VERSION 5.8 ;
BUSBITCHARS "[]" ;
DIVIDERCHAR "/" ;
UNITS
    DATABASE MICRONS 1000 ;
END UNITS

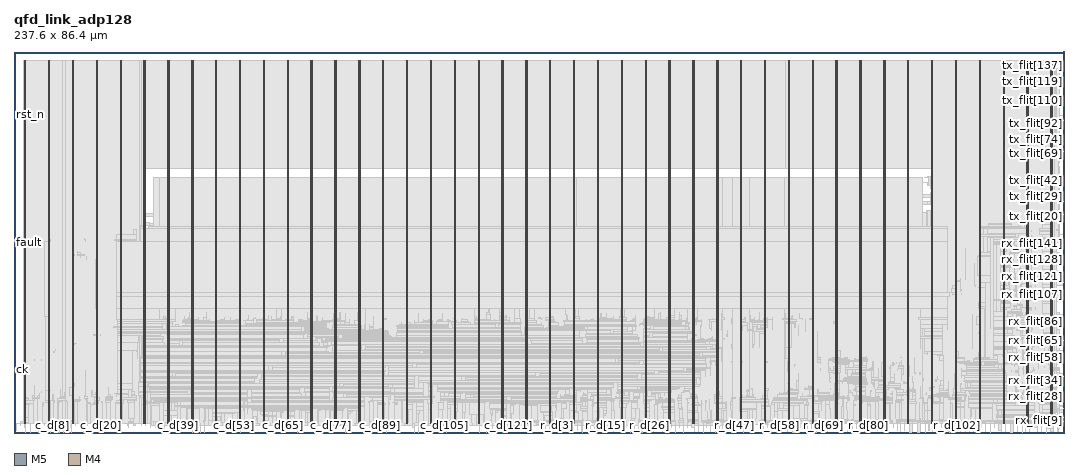
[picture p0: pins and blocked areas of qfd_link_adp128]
MACRO qfd_link_adp128
  FOREIGN qfd_link_adp128 0 0 ;
  CLASS BLOCK ;
  SIZE 237.6 BY 86.4 ;
  PIN c_cr
    DIRECTION OUTPUT ;
    USE SIGNAL ;
    PORT
      LAYER M5 ;
        RECT  0.432 0 0.456 0.084 ;
    END
  END c_cr
  PIN c_d[0]
    DIRECTION INPUT ;
    USE SIGNAL ;
    PORT
      LAYER M5 ;
        RECT  1.344 0 1.368 0.084 ;
    END
  END c_d[0]
  PIN c_d[100]
    DIRECTION INPUT ;
    USE SIGNAL ;
    PORT
      LAYER M5 ;
        RECT  92.736 0 92.76 0.084 ;
    END
  END c_d[100]
  PIN c_d[101]
    DIRECTION INPUT ;
    USE SIGNAL ;
    PORT
      LAYER M5 ;
        RECT  93.648 0 93.672 0.084 ;
    END
  END c_d[101]
  PIN c_d[102]
    DIRECTION INPUT ;
    USE SIGNAL ;
    PORT
      LAYER M5 ;
        RECT  94.56 0 94.584 0.084 ;
    END
  END c_d[102]
  PIN c_d[103]
    DIRECTION INPUT ;
    USE SIGNAL ;
    PORT
      LAYER M5 ;
        RECT  95.472 0 95.496 0.084 ;
    END
  END c_d[103]
  PIN c_d[104]
    DIRECTION INPUT ;
    USE SIGNAL ;
    PORT
      LAYER M5 ;
        RECT  96.384 0 96.408 0.084 ;
    END
  END c_d[104]
  PIN c_d[105]
    DIRECTION INPUT ;
    USE SIGNAL ;
    PORT
      LAYER M5 ;
        RECT  97.296 0 97.32 0.084 ;
    END
  END c_d[105]
  PIN c_d[106]
    DIRECTION INPUT ;
    USE SIGNAL ;
    PORT
      LAYER M5 ;
        RECT  98.208 0 98.232 0.084 ;
    END
  END c_d[106]
  PIN c_d[107]
    DIRECTION INPUT ;
    USE SIGNAL ;
    PORT
      LAYER M5 ;
        RECT  99.12 0 99.144 0.084 ;
    END
  END c_d[107]
  PIN c_d[108]
    DIRECTION INPUT ;
    USE SIGNAL ;
    PORT
      LAYER M5 ;
        RECT  100.032 0 100.056 0.084 ;
    END
  END c_d[108]
  PIN c_d[109]
    DIRECTION INPUT ;
    USE SIGNAL ;
    PORT
      LAYER M5 ;
        RECT  100.992 0 101.016 0.084 ;
    END
  END c_d[109]
  PIN c_d[10]
    DIRECTION INPUT ;
    USE SIGNAL ;
    PORT
      LAYER M5 ;
        RECT  10.512 0 10.536 0.084 ;
    END
  END c_d[10]
  PIN c_d[110]
    DIRECTION INPUT ;
    USE SIGNAL ;
    PORT
      LAYER M5 ;
        RECT  101.904 0 101.928 0.084 ;
    END
  END c_d[110]
  PIN c_d[111]
    DIRECTION INPUT ;
    USE SIGNAL ;
    PORT
      LAYER M5 ;
        RECT  102.816 0 102.84 0.084 ;
    END
  END c_d[111]
  PIN c_d[112]
    DIRECTION INPUT ;
    USE SIGNAL ;
    PORT
      LAYER M5 ;
        RECT  103.728 0 103.752 0.084 ;
    END
  END c_d[112]
  PIN c_d[113]
    DIRECTION INPUT ;
    USE SIGNAL ;
    PORT
      LAYER M5 ;
        RECT  104.64 0 104.664 0.084 ;
    END
  END c_d[113]
  PIN c_d[114]
    DIRECTION INPUT ;
    USE SIGNAL ;
    PORT
      LAYER M5 ;
        RECT  105.552 0 105.576 0.084 ;
    END
  END c_d[114]
  PIN c_d[115]
    DIRECTION INPUT ;
    USE SIGNAL ;
    PORT
      LAYER M5 ;
        RECT  106.464 0 106.488 0.084 ;
    END
  END c_d[115]
  PIN c_d[116]
    DIRECTION INPUT ;
    USE SIGNAL ;
    PORT
      LAYER M5 ;
        RECT  107.376 0 107.4 0.084 ;
    END
  END c_d[116]
  PIN c_d[117]
    DIRECTION INPUT ;
    USE SIGNAL ;
    PORT
      LAYER M5 ;
        RECT  108.288 0 108.312 0.084 ;
    END
  END c_d[117]
  PIN c_d[118]
    DIRECTION INPUT ;
    USE SIGNAL ;
    PORT
      LAYER M5 ;
        RECT  109.2 0 109.224 0.084 ;
    END
  END c_d[118]
  PIN c_d[119]
    DIRECTION INPUT ;
    USE SIGNAL ;
    PORT
      LAYER M5 ;
        RECT  110.112 0 110.136 0.084 ;
    END
  END c_d[119]
  PIN c_d[11]
    DIRECTION INPUT ;
    USE SIGNAL ;
    PORT
      LAYER M5 ;
        RECT  11.424 0 11.448 0.084 ;
    END
  END c_d[11]
  PIN c_d[120]
    DIRECTION INPUT ;
    USE SIGNAL ;
    PORT
      LAYER M5 ;
        RECT  111.024 0 111.048 0.084 ;
    END
  END c_d[120]
  PIN c_d[121]
    DIRECTION INPUT ;
    USE SIGNAL ;
    PORT
      LAYER M5 ;
        RECT  111.936 0 111.96 0.084 ;
    END
  END c_d[121]
  PIN c_d[122]
    DIRECTION INPUT ;
    USE SIGNAL ;
    PORT
      LAYER M5 ;
        RECT  112.848 0 112.872 0.084 ;
    END
  END c_d[122]
  PIN c_d[123]
    DIRECTION INPUT ;
    USE SIGNAL ;
    PORT
      LAYER M5 ;
        RECT  113.76 0 113.784 0.084 ;
    END
  END c_d[123]
  PIN c_d[124]
    DIRECTION INPUT ;
    USE SIGNAL ;
    PORT
      LAYER M5 ;
        RECT  114.672 0 114.696 0.084 ;
    END
  END c_d[124]
  PIN c_d[125]
    DIRECTION INPUT ;
    USE SIGNAL ;
    PORT
      LAYER M5 ;
        RECT  115.584 0 115.608 0.084 ;
    END
  END c_d[125]
  PIN c_d[126]
    DIRECTION INPUT ;
    USE SIGNAL ;
    PORT
      LAYER M5 ;
        RECT  116.496 0 116.52 0.084 ;
    END
  END c_d[126]
  PIN c_d[127]
    DIRECTION INPUT ;
    USE SIGNAL ;
    PORT
      LAYER M5 ;
        RECT  117.408 0 117.432 0.084 ;
    END
  END c_d[127]
  PIN c_d[12]
    DIRECTION INPUT ;
    USE SIGNAL ;
    PORT
      LAYER M5 ;
        RECT  12.336 0 12.36 0.084 ;
    END
  END c_d[12]
  PIN c_d[13]
    DIRECTION INPUT ;
    USE SIGNAL ;
    PORT
      LAYER M5 ;
        RECT  13.248 0 13.272 0.084 ;
    END
  END c_d[13]
  PIN c_d[14]
    DIRECTION INPUT ;
    USE SIGNAL ;
    PORT
      LAYER M5 ;
        RECT  14.16 0 14.184 0.084 ;
    END
  END c_d[14]
  PIN c_d[15]
    DIRECTION INPUT ;
    USE SIGNAL ;
    PORT
      LAYER M5 ;
        RECT  15.072 0 15.096 0.084 ;
    END
  END c_d[15]
  PIN c_d[16]
    DIRECTION INPUT ;
    USE SIGNAL ;
    PORT
      LAYER M5 ;
        RECT  15.984 0 16.008 0.084 ;
    END
  END c_d[16]
  PIN c_d[17]
    DIRECTION INPUT ;
    USE SIGNAL ;
    PORT
      LAYER M5 ;
        RECT  16.896 0 16.92 0.084 ;
    END
  END c_d[17]
  PIN c_d[18]
    DIRECTION INPUT ;
    USE SIGNAL ;
    PORT
      LAYER M5 ;
        RECT  17.808 0 17.832 0.084 ;
    END
  END c_d[18]
  PIN c_d[19]
    DIRECTION INPUT ;
    USE SIGNAL ;
    PORT
      LAYER M5 ;
        RECT  18.72 0 18.744 0.084 ;
    END
  END c_d[19]
  PIN c_d[1]
    DIRECTION INPUT ;
    USE SIGNAL ;
    PORT
      LAYER M5 ;
        RECT  2.256 0 2.28 0.084 ;
    END
  END c_d[1]
  PIN c_d[20]
    DIRECTION INPUT ;
    USE SIGNAL ;
    PORT
      LAYER M5 ;
        RECT  19.632 0 19.656 0.084 ;
    END
  END c_d[20]
  PIN c_d[21]
    DIRECTION INPUT ;
    USE SIGNAL ;
    PORT
      LAYER M5 ;
        RECT  20.544 0 20.568 0.084 ;
    END
  END c_d[21]
  PIN c_d[22]
    DIRECTION INPUT ;
    USE SIGNAL ;
    PORT
      LAYER M5 ;
        RECT  21.456 0 21.48 0.084 ;
    END
  END c_d[22]
  PIN c_d[23]
    DIRECTION INPUT ;
    USE SIGNAL ;
    PORT
      LAYER M5 ;
        RECT  22.368 0 22.392 0.084 ;
    END
  END c_d[23]
  PIN c_d[24]
    DIRECTION INPUT ;
    USE SIGNAL ;
    PORT
      LAYER M5 ;
        RECT  23.28 0 23.304 0.084 ;
    END
  END c_d[24]
  PIN c_d[25]
    DIRECTION INPUT ;
    USE SIGNAL ;
    PORT
      LAYER M5 ;
        RECT  24.192 0 24.216 0.084 ;
    END
  END c_d[25]
  PIN c_d[26]
    DIRECTION INPUT ;
    USE SIGNAL ;
    PORT
      LAYER M5 ;
        RECT  25.104 0 25.128 0.084 ;
    END
  END c_d[26]
  PIN c_d[27]
    DIRECTION INPUT ;
    USE SIGNAL ;
    PORT
      LAYER M5 ;
        RECT  26.016 0 26.04 0.084 ;
    END
  END c_d[27]
  PIN c_d[28]
    DIRECTION INPUT ;
    USE SIGNAL ;
    PORT
      LAYER M5 ;
        RECT  26.928 0 26.952 0.084 ;
    END
  END c_d[28]
  PIN c_d[29]
    DIRECTION INPUT ;
    USE SIGNAL ;
    PORT
      LAYER M5 ;
        RECT  27.84 0 27.864 0.084 ;
    END
  END c_d[29]
  PIN c_d[2]
    DIRECTION INPUT ;
    USE SIGNAL ;
    PORT
      LAYER M5 ;
        RECT  3.168 0 3.192 0.084 ;
    END
  END c_d[2]
  PIN c_d[30]
    DIRECTION INPUT ;
    USE SIGNAL ;
    PORT
      LAYER M5 ;
        RECT  28.752 0 28.776 0.084 ;
    END
  END c_d[30]
  PIN c_d[31]
    DIRECTION INPUT ;
    USE SIGNAL ;
    PORT
      LAYER M5 ;
        RECT  29.712 0 29.736 0.084 ;
    END
  END c_d[31]
  PIN c_d[32]
    DIRECTION INPUT ;
    USE SIGNAL ;
    PORT
      LAYER M5 ;
        RECT  30.624 0 30.648 0.084 ;
    END
  END c_d[32]
  PIN c_d[33]
    DIRECTION INPUT ;
    USE SIGNAL ;
    PORT
      LAYER M5 ;
        RECT  31.536 0 31.56 0.084 ;
    END
  END c_d[33]
  PIN c_d[34]
    DIRECTION INPUT ;
    USE SIGNAL ;
    PORT
      LAYER M5 ;
        RECT  32.448 0 32.472 0.084 ;
    END
  END c_d[34]
  PIN c_d[35]
    DIRECTION INPUT ;
    USE SIGNAL ;
    PORT
      LAYER M5 ;
        RECT  33.36 0 33.384 0.084 ;
    END
  END c_d[35]
  PIN c_d[36]
    DIRECTION INPUT ;
    USE SIGNAL ;
    PORT
      LAYER M5 ;
        RECT  34.272 0 34.296 0.084 ;
    END
  END c_d[36]
  PIN c_d[37]
    DIRECTION INPUT ;
    USE SIGNAL ;
    PORT
      LAYER M5 ;
        RECT  35.184 0 35.208 0.084 ;
    END
  END c_d[37]
  PIN c_d[38]
    DIRECTION INPUT ;
    USE SIGNAL ;
    PORT
      LAYER M5 ;
        RECT  36.096 0 36.12 0.084 ;
    END
  END c_d[38]
  PIN c_d[39]
    DIRECTION INPUT ;
    USE SIGNAL ;
    PORT
      LAYER M5 ;
        RECT  37.008 0 37.032 0.084 ;
    END
  END c_d[39]
  PIN c_d[3]
    DIRECTION INPUT ;
    USE SIGNAL ;
    PORT
      LAYER M5 ;
        RECT  4.08 0 4.104 0.084 ;
    END
  END c_d[3]
  PIN c_d[40]
    DIRECTION INPUT ;
    USE SIGNAL ;
    PORT
      LAYER M5 ;
        RECT  37.92 0 37.944 0.084 ;
    END
  END c_d[40]
  PIN c_d[41]
    DIRECTION INPUT ;
    USE SIGNAL ;
    PORT
      LAYER M5 ;
        RECT  38.832 0 38.856 0.084 ;
    END
  END c_d[41]
  PIN c_d[42]
    DIRECTION INPUT ;
    USE SIGNAL ;
    PORT
      LAYER M5 ;
        RECT  39.744 0 39.768 0.084 ;
    END
  END c_d[42]
  PIN c_d[43]
    DIRECTION INPUT ;
    USE SIGNAL ;
    PORT
      LAYER M5 ;
        RECT  40.656 0 40.68 0.084 ;
    END
  END c_d[43]
  PIN c_d[44]
    DIRECTION INPUT ;
    USE SIGNAL ;
    PORT
      LAYER M5 ;
        RECT  41.568 0 41.592 0.084 ;
    END
  END c_d[44]
  PIN c_d[45]
    DIRECTION INPUT ;
    USE SIGNAL ;
    PORT
      LAYER M5 ;
        RECT  42.48 0 42.504 0.084 ;
    END
  END c_d[45]
  PIN c_d[46]
    DIRECTION INPUT ;
    USE SIGNAL ;
    PORT
      LAYER M5 ;
        RECT  43.392 0 43.416 0.084 ;
    END
  END c_d[46]
  PIN c_d[47]
    DIRECTION INPUT ;
    USE SIGNAL ;
    PORT
      LAYER M5 ;
        RECT  44.304 0 44.328 0.084 ;
    END
  END c_d[47]
  PIN c_d[48]
    DIRECTION INPUT ;
    USE SIGNAL ;
    PORT
      LAYER M5 ;
        RECT  45.216 0 45.24 0.084 ;
    END
  END c_d[48]
  PIN c_d[49]
    DIRECTION INPUT ;
    USE SIGNAL ;
    PORT
      LAYER M5 ;
        RECT  46.128 0 46.152 0.084 ;
    END
  END c_d[49]
  PIN c_d[4]
    DIRECTION INPUT ;
    USE SIGNAL ;
    PORT
      LAYER M5 ;
        RECT  4.992 0 5.016 0.084 ;
    END
  END c_d[4]
  PIN c_d[50]
    DIRECTION INPUT ;
    USE SIGNAL ;
    PORT
      LAYER M5 ;
        RECT  47.04 0 47.064 0.084 ;
    END
  END c_d[50]
  PIN c_d[51]
    DIRECTION INPUT ;
    USE SIGNAL ;
    PORT
      LAYER M5 ;
        RECT  47.952 0 47.976 0.084 ;
    END
  END c_d[51]
  PIN c_d[52]
    DIRECTION INPUT ;
    USE SIGNAL ;
    PORT
      LAYER M5 ;
        RECT  48.864 0 48.888 0.084 ;
    END
  END c_d[52]
  PIN c_d[53]
    DIRECTION INPUT ;
    USE SIGNAL ;
    PORT
      LAYER M5 ;
        RECT  49.776 0 49.8 0.084 ;
    END
  END c_d[53]
  PIN c_d[54]
    DIRECTION INPUT ;
    USE SIGNAL ;
    PORT
      LAYER M5 ;
        RECT  50.688 0 50.712 0.084 ;
    END
  END c_d[54]
  PIN c_d[55]
    DIRECTION INPUT ;
    USE SIGNAL ;
    PORT
      LAYER M5 ;
        RECT  51.6 0 51.624 0.084 ;
    END
  END c_d[55]
  PIN c_d[56]
    DIRECTION INPUT ;
    USE SIGNAL ;
    PORT
      LAYER M5 ;
        RECT  52.512 0 52.536 0.084 ;
    END
  END c_d[56]
  PIN c_d[57]
    DIRECTION INPUT ;
    USE SIGNAL ;
    PORT
      LAYER M5 ;
        RECT  53.472 0 53.496 0.084 ;
    END
  END c_d[57]
  PIN c_d[58]
    DIRECTION INPUT ;
    USE SIGNAL ;
    PORT
      LAYER M5 ;
        RECT  54.384 0 54.408 0.084 ;
    END
  END c_d[58]
  PIN c_d[59]
    DIRECTION INPUT ;
    USE SIGNAL ;
    PORT
      LAYER M5 ;
        RECT  55.296 0 55.32 0.084 ;
    END
  END c_d[59]
  PIN c_d[5]
    DIRECTION INPUT ;
    USE SIGNAL ;
    PORT
      LAYER M5 ;
        RECT  5.952 0 5.976 0.084 ;
    END
  END c_d[5]
  PIN c_d[60]
    DIRECTION INPUT ;
    USE SIGNAL ;
    PORT
      LAYER M5 ;
        RECT  56.208 0 56.232 0.084 ;
    END
  END c_d[60]
  PIN c_d[61]
    DIRECTION INPUT ;
    USE SIGNAL ;
    PORT
      LAYER M5 ;
        RECT  57.12 0 57.144 0.084 ;
    END
  END c_d[61]
  PIN c_d[62]
    DIRECTION INPUT ;
    USE SIGNAL ;
    PORT
      LAYER M5 ;
        RECT  58.032 0 58.056 0.084 ;
    END
  END c_d[62]
  PIN c_d[63]
    DIRECTION INPUT ;
    USE SIGNAL ;
    PORT
      LAYER M5 ;
        RECT  58.944 0 58.968 0.084 ;
    END
  END c_d[63]
  PIN c_d[64]
    DIRECTION INPUT ;
    USE SIGNAL ;
    PORT
      LAYER M5 ;
        RECT  59.856 0 59.88 0.084 ;
    END
  END c_d[64]
  PIN c_d[65]
    DIRECTION INPUT ;
    USE SIGNAL ;
    PORT
      LAYER M5 ;
        RECT  60.768 0 60.792 0.084 ;
    END
  END c_d[65]
  PIN c_d[66]
    DIRECTION INPUT ;
    USE SIGNAL ;
    PORT
      LAYER M5 ;
        RECT  61.68 0 61.704 0.084 ;
    END
  END c_d[66]
  PIN c_d[67]
    DIRECTION INPUT ;
    USE SIGNAL ;
    PORT
      LAYER M5 ;
        RECT  62.592 0 62.616 0.084 ;
    END
  END c_d[67]
  PIN c_d[68]
    DIRECTION INPUT ;
    USE SIGNAL ;
    PORT
      LAYER M5 ;
        RECT  63.504 0 63.528 0.084 ;
    END
  END c_d[68]
  PIN c_d[69]
    DIRECTION INPUT ;
    USE SIGNAL ;
    PORT
      LAYER M5 ;
        RECT  64.416 0 64.44 0.084 ;
    END
  END c_d[69]
  PIN c_d[6]
    DIRECTION INPUT ;
    USE SIGNAL ;
    PORT
      LAYER M5 ;
        RECT  6.864 0 6.888 0.084 ;
    END
  END c_d[6]
  PIN c_d[70]
    DIRECTION INPUT ;
    USE SIGNAL ;
    PORT
      LAYER M5 ;
        RECT  65.328 0 65.352 0.084 ;
    END
  END c_d[70]
  PIN c_d[71]
    DIRECTION INPUT ;
    USE SIGNAL ;
    PORT
      LAYER M5 ;
        RECT  66.24 0 66.264 0.084 ;
    END
  END c_d[71]
  PIN c_d[72]
    DIRECTION INPUT ;
    USE SIGNAL ;
    PORT
      LAYER M5 ;
        RECT  67.152 0 67.176 0.084 ;
    END
  END c_d[72]
  PIN c_d[73]
    DIRECTION INPUT ;
    USE SIGNAL ;
    PORT
      LAYER M5 ;
        RECT  68.064 0 68.088 0.084 ;
    END
  END c_d[73]
  PIN c_d[74]
    DIRECTION INPUT ;
    USE SIGNAL ;
    PORT
      LAYER M5 ;
        RECT  68.976 0 69 0.084 ;
    END
  END c_d[74]
  PIN c_d[75]
    DIRECTION INPUT ;
    USE SIGNAL ;
    PORT
      LAYER M5 ;
        RECT  69.888 0 69.912 0.084 ;
    END
  END c_d[75]
  PIN c_d[76]
    DIRECTION INPUT ;
    USE SIGNAL ;
    PORT
      LAYER M5 ;
        RECT  70.8 0 70.824 0.084 ;
    END
  END c_d[76]
  PIN c_d[77]
    DIRECTION INPUT ;
    USE SIGNAL ;
    PORT
      LAYER M5 ;
        RECT  71.712 0 71.736 0.084 ;
    END
  END c_d[77]
  PIN c_d[78]
    DIRECTION INPUT ;
    USE SIGNAL ;
    PORT
      LAYER M5 ;
        RECT  72.624 0 72.648 0.084 ;
    END
  END c_d[78]
  PIN c_d[79]
    DIRECTION INPUT ;
    USE SIGNAL ;
    PORT
      LAYER M5 ;
        RECT  73.536 0 73.56 0.084 ;
    END
  END c_d[79]
  PIN c_d[7]
    DIRECTION INPUT ;
    USE SIGNAL ;
    PORT
      LAYER M5 ;
        RECT  7.776 0 7.8 0.084 ;
    END
  END c_d[7]
  PIN c_d[80]
    DIRECTION INPUT ;
    USE SIGNAL ;
    PORT
      LAYER M5 ;
        RECT  74.448 0 74.472 0.084 ;
    END
  END c_d[80]
  PIN c_d[81]
    DIRECTION INPUT ;
    USE SIGNAL ;
    PORT
      LAYER M5 ;
        RECT  75.36 0 75.384 0.084 ;
    END
  END c_d[81]
  PIN c_d[82]
    DIRECTION INPUT ;
    USE SIGNAL ;
    PORT
      LAYER M5 ;
        RECT  76.272 0 76.296 0.084 ;
    END
  END c_d[82]
  PIN c_d[83]
    DIRECTION INPUT ;
    USE SIGNAL ;
    PORT
      LAYER M5 ;
        RECT  77.232 0 77.256 0.084 ;
    END
  END c_d[83]
  PIN c_d[84]
    DIRECTION INPUT ;
    USE SIGNAL ;
    PORT
      LAYER M5 ;
        RECT  78.144 0 78.168 0.084 ;
    END
  END c_d[84]
  PIN c_d[85]
    DIRECTION INPUT ;
    USE SIGNAL ;
    PORT
      LAYER M5 ;
        RECT  79.056 0 79.08 0.084 ;
    END
  END c_d[85]
  PIN c_d[86]
    DIRECTION INPUT ;
    USE SIGNAL ;
    PORT
      LAYER M5 ;
        RECT  79.968 0 79.992 0.084 ;
    END
  END c_d[86]
  PIN c_d[87]
    DIRECTION INPUT ;
    USE SIGNAL ;
    PORT
      LAYER M5 ;
        RECT  80.88 0 80.904 0.084 ;
    END
  END c_d[87]
  PIN c_d[88]
    DIRECTION INPUT ;
    USE SIGNAL ;
    PORT
      LAYER M5 ;
        RECT  81.792 0 81.816 0.084 ;
    END
  END c_d[88]
  PIN c_d[89]
    DIRECTION INPUT ;
    USE SIGNAL ;
    PORT
      LAYER M5 ;
        RECT  82.704 0 82.728 0.084 ;
    END
  END c_d[89]
  PIN c_d[8]
    DIRECTION INPUT ;
    USE SIGNAL ;
    PORT
      LAYER M5 ;
        RECT  8.688 0 8.712 0.084 ;
    END
  END c_d[8]
  PIN c_d[90]
    DIRECTION INPUT ;
    USE SIGNAL ;
    PORT
      LAYER M5 ;
        RECT  83.616 0 83.64 0.084 ;
    END
  END c_d[90]
  PIN c_d[91]
    DIRECTION INPUT ;
    USE SIGNAL ;
    PORT
      LAYER M5 ;
        RECT  84.528 0 84.552 0.084 ;
    END
  END c_d[91]
  PIN c_d[92]
    DIRECTION INPUT ;
    USE SIGNAL ;
    PORT
      LAYER M5 ;
        RECT  85.44 0 85.464 0.084 ;
    END
  END c_d[92]
  PIN c_d[93]
    DIRECTION INPUT ;
    USE SIGNAL ;
    PORT
      LAYER M5 ;
        RECT  86.352 0 86.376 0.084 ;
    END
  END c_d[93]
  PIN c_d[94]
    DIRECTION INPUT ;
    USE SIGNAL ;
    PORT
      LAYER M5 ;
        RECT  87.264 0 87.288 0.084 ;
    END
  END c_d[94]
  PIN c_d[95]
    DIRECTION INPUT ;
    USE SIGNAL ;
    PORT
      LAYER M5 ;
        RECT  88.176 0 88.2 0.084 ;
    END
  END c_d[95]
  PIN c_d[96]
    DIRECTION INPUT ;
    USE SIGNAL ;
    PORT
      LAYER M5 ;
        RECT  89.088 0 89.112 0.084 ;
    END
  END c_d[96]
  PIN c_d[97]
    DIRECTION INPUT ;
    USE SIGNAL ;
    PORT
      LAYER M5 ;
        RECT  90 0 90.024 0.084 ;
    END
  END c_d[97]
  PIN c_d[98]
    DIRECTION INPUT ;
    USE SIGNAL ;
    PORT
      LAYER M5 ;
        RECT  90.912 0 90.936 0.084 ;
    END
  END c_d[98]
  PIN c_d[99]
    DIRECTION INPUT ;
    USE SIGNAL ;
    PORT
      LAYER M5 ;
        RECT  91.824 0 91.848 0.084 ;
    END
  END c_d[99]
  PIN c_d[9]
    DIRECTION INPUT ;
    USE SIGNAL ;
    PORT
      LAYER M5 ;
        RECT  9.6 0 9.624 0.084 ;
    END
  END c_d[9]
  PIN c_v
    DIRECTION INPUT ;
    USE SIGNAL ;
    PORT
      LAYER M5 ;
        RECT  118.32 0 118.344 0.084 ;
    END
  END c_v
  PIN ck
    DIRECTION INPUT ;
    USE SIGNAL ;
    PORT
      LAYER M4 ;
        RECT  0 14.4 0.084 14.424 ;
    END
    PORT
      LAYER M4 ;
        RECT  0.06 14.4 2.408 14.424 ;
    END
  END ck
  PIN fault
    DIRECTION OUTPUT ;
    USE SIGNAL ;
    PORT
      LAYER M4 ;
        RECT  0 43.2 0.084 43.224 ;
    END
    PORT
      LAYER M4 ;
        RECT  0.06 43.2 0.137 43.224 ;
    END
  END fault
  PIN r_cr
    DIRECTION INPUT ;
    USE SIGNAL ;
    PORT
      LAYER M5 ;
        RECT  119.232 0 119.256 0.084 ;
    END
  END r_cr
  PIN r_d[0]
    DIRECTION OUTPUT ;
    USE SIGNAL ;
    PORT
      LAYER M5 ;
        RECT  120.144 0 120.168 0.084 ;
    END
  END r_d[0]
  PIN r_d[100]
    DIRECTION OUTPUT ;
    USE SIGNAL ;
    PORT
      LAYER M5 ;
        RECT  211.536 0 211.56 0.084 ;
    END
  END r_d[100]
  PIN r_d[101]
    DIRECTION OUTPUT ;
    USE SIGNAL ;
    PORT
      LAYER M5 ;
        RECT  212.448 0 212.472 0.084 ;
    END
  END r_d[101]
  PIN r_d[102]
    DIRECTION OUTPUT ;
    USE SIGNAL ;
    PORT
      LAYER M5 ;
        RECT  213.36 0 213.384 0.084 ;
    END
  END r_d[102]
  PIN r_d[103]
    DIRECTION OUTPUT ;
    USE SIGNAL ;
    PORT
      LAYER M5 ;
        RECT  214.272 0 214.296 0.084 ;
    END
  END r_d[103]
  PIN r_d[104]
    DIRECTION OUTPUT ;
    USE SIGNAL ;
    PORT
      LAYER M5 ;
        RECT  215.184 0 215.208 0.084 ;
    END
  END r_d[104]
  PIN r_d[105]
    DIRECTION OUTPUT ;
    USE SIGNAL ;
    PORT
      LAYER M5 ;
        RECT  216.096 0 216.12 0.084 ;
    END
  END r_d[105]
  PIN r_d[106]
    DIRECTION OUTPUT ;
    USE SIGNAL ;
    PORT
      LAYER M5 ;
        RECT  217.008 0 217.032 0.084 ;
    END
  END r_d[106]
  PIN r_d[107]
    DIRECTION OUTPUT ;
    USE SIGNAL ;
    PORT
      LAYER M5 ;
        RECT  217.92 0 217.944 0.084 ;
    END
  END r_d[107]
  PIN r_d[108]
    DIRECTION OUTPUT ;
    USE SIGNAL ;
    PORT
      LAYER M5 ;
        RECT  218.832 0 218.856 0.084 ;
    END
  END r_d[108]
  PIN r_d[109]
    DIRECTION OUTPUT ;
    USE SIGNAL ;
    PORT
      LAYER M5 ;
        RECT  219.792 0 219.816 0.084 ;
    END
  END r_d[109]
  PIN r_d[10]
    DIRECTION OUTPUT ;
    USE SIGNAL ;
    PORT
      LAYER M5 ;
        RECT  129.312 0 129.336 0.084 ;
    END
  END r_d[10]
  PIN r_d[110]
    DIRECTION OUTPUT ;
    USE SIGNAL ;
    PORT
      LAYER M5 ;
        RECT  220.704 0 220.728 0.084 ;
    END
  END r_d[110]
  PIN r_d[111]
    DIRECTION OUTPUT ;
    USE SIGNAL ;
    PORT
      LAYER M5 ;
        RECT  221.616 0 221.64 0.084 ;
    END
  END r_d[111]
  PIN r_d[112]
    DIRECTION OUTPUT ;
    USE SIGNAL ;
    PORT
      LAYER M5 ;
        RECT  222.528 0 222.552 0.084 ;
    END
  END r_d[112]
  PIN r_d[113]
    DIRECTION OUTPUT ;
    USE SIGNAL ;
    PORT
      LAYER M5 ;
        RECT  223.44 0 223.464 0.084 ;
    END
  END r_d[113]
  PIN r_d[114]
    DIRECTION OUTPUT ;
    USE SIGNAL ;
    PORT
      LAYER M5 ;
        RECT  224.352 0 224.376 0.084 ;
    END
  END r_d[114]
  PIN r_d[115]
    DIRECTION OUTPUT ;
    USE SIGNAL ;
    PORT
      LAYER M5 ;
        RECT  225.264 0 225.288 0.084 ;
    END
  END r_d[115]
  PIN r_d[116]
    DIRECTION OUTPUT ;
    USE SIGNAL ;
    PORT
      LAYER M5 ;
        RECT  226.176 0 226.2 0.084 ;
    END
  END r_d[116]
  PIN r_d[117]
    DIRECTION OUTPUT ;
    USE SIGNAL ;
    PORT
      LAYER M5 ;
        RECT  227.088 0 227.112 0.084 ;
    END
  END r_d[117]
  PIN r_d[118]
    DIRECTION OUTPUT ;
    USE SIGNAL ;
    PORT
      LAYER M5 ;
        RECT  228 0 228.024 0.084 ;
    END
  END r_d[118]
  PIN r_d[119]
    DIRECTION OUTPUT ;
    USE SIGNAL ;
    PORT
      LAYER M5 ;
        RECT  228.912 0 228.936 0.084 ;
    END
  END r_d[119]
  PIN r_d[11]
    DIRECTION OUTPUT ;
    USE SIGNAL ;
    PORT
      LAYER M5 ;
        RECT  130.224 0 130.248 0.084 ;
    END
  END r_d[11]
  PIN r_d[120]
    DIRECTION OUTPUT ;
    USE SIGNAL ;
    PORT
      LAYER M5 ;
        RECT  229.824 0 229.848 0.084 ;
    END
  END r_d[120]
  PIN r_d[121]
    DIRECTION OUTPUT ;
    USE SIGNAL ;
    PORT
      LAYER M5 ;
        RECT  230.736 0 230.76 0.084 ;
    END
  END r_d[121]
  PIN r_d[122]
    DIRECTION OUTPUT ;
    USE SIGNAL ;
    PORT
      LAYER M5 ;
        RECT  231.648 0 231.672 0.084 ;
    END
  END r_d[122]
  PIN r_d[123]
    DIRECTION OUTPUT ;
    USE SIGNAL ;
    PORT
      LAYER M5 ;
        RECT  232.56 0 232.584 0.084 ;
    END
  END r_d[123]
  PIN r_d[124]
    DIRECTION OUTPUT ;
    USE SIGNAL ;
    PORT
      LAYER M5 ;
        RECT  233.472 0 233.496 0.084 ;
    END
  END r_d[124]
  PIN r_d[125]
    DIRECTION OUTPUT ;
    USE SIGNAL ;
    PORT
      LAYER M5 ;
        RECT  234.384 0 234.408 0.084 ;
    END
  END r_d[125]
  PIN r_d[126]
    DIRECTION OUTPUT ;
    USE SIGNAL ;
    PORT
      LAYER M5 ;
        RECT  235.296 0 235.32 0.084 ;
    END
  END r_d[126]
  PIN r_d[127]
    DIRECTION OUTPUT ;
    USE SIGNAL ;
    PORT
      LAYER M5 ;
        RECT  236.208 0 236.232 0.084 ;
    END
  END r_d[127]
  PIN r_d[12]
    DIRECTION OUTPUT ;
    USE SIGNAL ;
    PORT
      LAYER M5 ;
        RECT  131.136 0 131.16 0.084 ;
    END
  END r_d[12]
  PIN r_d[13]
    DIRECTION OUTPUT ;
    USE SIGNAL ;
    PORT
      LAYER M5 ;
        RECT  132.048 0 132.072 0.084 ;
    END
  END r_d[13]
  PIN r_d[14]
    DIRECTION OUTPUT ;
    USE SIGNAL ;
    PORT
      LAYER M5 ;
        RECT  132.96 0 132.984 0.084 ;
    END
  END r_d[14]
  PIN r_d[15]
    DIRECTION OUTPUT ;
    USE SIGNAL ;
    PORT
      LAYER M5 ;
        RECT  133.872 0 133.896 0.084 ;
    END
  END r_d[15]
  PIN r_d[16]
    DIRECTION OUTPUT ;
    USE SIGNAL ;
    PORT
      LAYER M5 ;
        RECT  134.784 0 134.808 0.084 ;
    END
  END r_d[16]
  PIN r_d[17]
    DIRECTION OUTPUT ;
    USE SIGNAL ;
    PORT
      LAYER M5 ;
        RECT  135.696 0 135.72 0.084 ;
    END
  END r_d[17]
  PIN r_d[18]
    DIRECTION OUTPUT ;
    USE SIGNAL ;
    PORT
      LAYER M5 ;
        RECT  136.608 0 136.632 0.084 ;
    END
  END r_d[18]
  PIN r_d[19]
    DIRECTION OUTPUT ;
    USE SIGNAL ;
    PORT
      LAYER M5 ;
        RECT  137.52 0 137.544 0.084 ;
    END
  END r_d[19]
  PIN r_d[1]
    DIRECTION OUTPUT ;
    USE SIGNAL ;
    PORT
      LAYER M5 ;
        RECT  121.056 0 121.08 0.084 ;
    END
  END r_d[1]
  PIN r_d[20]
    DIRECTION OUTPUT ;
    USE SIGNAL ;
    PORT
      LAYER M5 ;
        RECT  138.432 0 138.456 0.084 ;
    END
  END r_d[20]
  PIN r_d[21]
    DIRECTION OUTPUT ;
    USE SIGNAL ;
    PORT
      LAYER M5 ;
        RECT  139.344 0 139.368 0.084 ;
    END
  END r_d[21]
  PIN r_d[22]
    DIRECTION OUTPUT ;
    USE SIGNAL ;
    PORT
      LAYER M5 ;
        RECT  140.256 0 140.28 0.084 ;
    END
  END r_d[22]
  PIN r_d[23]
    DIRECTION OUTPUT ;
    USE SIGNAL ;
    PORT
      LAYER M5 ;
        RECT  141.168 0 141.192 0.084 ;
    END
  END r_d[23]
  PIN r_d[24]
    DIRECTION OUTPUT ;
    USE SIGNAL ;
    PORT
      LAYER M5 ;
        RECT  142.08 0 142.104 0.084 ;
    END
  END r_d[24]
  PIN r_d[25]
    DIRECTION OUTPUT ;
    USE SIGNAL ;
    PORT
      LAYER M5 ;
        RECT  142.992 0 143.016 0.084 ;
    END
  END r_d[25]
  PIN r_d[26]
    DIRECTION OUTPUT ;
    USE SIGNAL ;
    PORT
      LAYER M5 ;
        RECT  143.904 0 143.928 0.084 ;
    END
  END r_d[26]
  PIN r_d[27]
    DIRECTION OUTPUT ;
    USE SIGNAL ;
    PORT
      LAYER M5 ;
        RECT  144.816 0 144.84 0.084 ;
    END
  END r_d[27]
  PIN r_d[28]
    DIRECTION OUTPUT ;
    USE SIGNAL ;
    PORT
      LAYER M5 ;
        RECT  145.728 0 145.752 0.084 ;
    END
  END r_d[28]
  PIN r_d[29]
    DIRECTION OUTPUT ;
    USE SIGNAL ;
    PORT
      LAYER M5 ;
        RECT  146.64 0 146.664 0.084 ;
    END
  END r_d[29]
  PIN r_d[2]
    DIRECTION OUTPUT ;
    USE SIGNAL ;
    PORT
      LAYER M5 ;
        RECT  121.968 0 121.992 0.084 ;
    END
  END r_d[2]
  PIN r_d[30]
    DIRECTION OUTPUT ;
    USE SIGNAL ;
    PORT
      LAYER M5 ;
        RECT  147.552 0 147.576 0.084 ;
    END
  END r_d[30]
  PIN r_d[31]
    DIRECTION OUTPUT ;
    USE SIGNAL ;
    PORT
      LAYER M5 ;
        RECT  148.512 0 148.536 0.084 ;
    END
  END r_d[31]
  PIN r_d[32]
    DIRECTION OUTPUT ;
    USE SIGNAL ;
    PORT
      LAYER M5 ;
        RECT  149.424 0 149.448 0.084 ;
    END
  END r_d[32]
  PIN r_d[33]
    DIRECTION OUTPUT ;
    USE SIGNAL ;
    PORT
      LAYER M5 ;
        RECT  150.336 0 150.36 0.084 ;
    END
  END r_d[33]
  PIN r_d[34]
    DIRECTION OUTPUT ;
    USE SIGNAL ;
    PORT
      LAYER M5 ;
        RECT  151.248 0 151.272 0.084 ;
    END
  END r_d[34]
  PIN r_d[35]
    DIRECTION OUTPUT ;
    USE SIGNAL ;
    PORT
      LAYER M5 ;
        RECT  152.16 0 152.184 0.084 ;
    END
  END r_d[35]
  PIN r_d[36]
    DIRECTION OUTPUT ;
    USE SIGNAL ;
    PORT
      LAYER M5 ;
        RECT  153.072 0 153.096 0.084 ;
    END
  END r_d[36]
  PIN r_d[37]
    DIRECTION OUTPUT ;
    USE SIGNAL ;
    PORT
      LAYER M5 ;
        RECT  153.984 0 154.008 0.084 ;
    END
  END r_d[37]
  PIN r_d[38]
    DIRECTION OUTPUT ;
    USE SIGNAL ;
    PORT
      LAYER M5 ;
        RECT  154.896 0 154.92 0.084 ;
    END
  END r_d[38]
  PIN r_d[39]
    DIRECTION OUTPUT ;
    USE SIGNAL ;
    PORT
      LAYER M5 ;
        RECT  155.808 0 155.832 0.084 ;
    END
  END r_d[39]
  PIN r_d[3]
    DIRECTION OUTPUT ;
    USE SIGNAL ;
    PORT
      LAYER M5 ;
        RECT  122.88 0 122.904 0.084 ;
    END
  END r_d[3]
  PIN r_d[40]
    DIRECTION OUTPUT ;
    USE SIGNAL ;
    PORT
      LAYER M5 ;
        RECT  156.72 0 156.744 0.084 ;
    END
  END r_d[40]
  PIN r_d[41]
    DIRECTION OUTPUT ;
    USE SIGNAL ;
    PORT
      LAYER M5 ;
        RECT  157.632 0 157.656 0.084 ;
    END
  END r_d[41]
  PIN r_d[42]
    DIRECTION OUTPUT ;
    USE SIGNAL ;
    PORT
      LAYER M5 ;
        RECT  158.544 0 158.568 0.084 ;
    END
  END r_d[42]
  PIN r_d[43]
    DIRECTION OUTPUT ;
    USE SIGNAL ;
    PORT
      LAYER M5 ;
        RECT  159.456 0 159.48 0.084 ;
    END
  END r_d[43]
  PIN r_d[44]
    DIRECTION OUTPUT ;
    USE SIGNAL ;
    PORT
      LAYER M5 ;
        RECT  160.368 0 160.392 0.084 ;
    END
  END r_d[44]
  PIN r_d[45]
    DIRECTION OUTPUT ;
    USE SIGNAL ;
    PORT
      LAYER M5 ;
        RECT  161.28 0 161.304 0.084 ;
    END
  END r_d[45]
  PIN r_d[46]
    DIRECTION OUTPUT ;
    USE SIGNAL ;
    PORT
      LAYER M5 ;
        RECT  162.192 0 162.216 0.084 ;
    END
  END r_d[46]
  PIN r_d[47]
    DIRECTION OUTPUT ;
    USE SIGNAL ;
    PORT
      LAYER M5 ;
        RECT  163.104 0 163.128 0.084 ;
    END
  END r_d[47]
  PIN r_d[48]
    DIRECTION OUTPUT ;
    USE SIGNAL ;
    PORT
      LAYER M5 ;
        RECT  164.016 0 164.04 0.084 ;
    END
  END r_d[48]
  PIN r_d[49]
    DIRECTION OUTPUT ;
    USE SIGNAL ;
    PORT
      LAYER M5 ;
        RECT  164.928 0 164.952 0.084 ;
    END
  END r_d[49]
  PIN r_d[4]
    DIRECTION OUTPUT ;
    USE SIGNAL ;
    PORT
      LAYER M5 ;
        RECT  123.792 0 123.816 0.084 ;
    END
  END r_d[4]
  PIN r_d[50]
    DIRECTION OUTPUT ;
    USE SIGNAL ;
    PORT
      LAYER M5 ;
        RECT  165.84 0 165.864 0.084 ;
    END
  END r_d[50]
  PIN r_d[51]
    DIRECTION OUTPUT ;
    USE SIGNAL ;
    PORT
      LAYER M5 ;
        RECT  166.752 0 166.776 0.084 ;
    END
  END r_d[51]
  PIN r_d[52]
    DIRECTION OUTPUT ;
    USE SIGNAL ;
    PORT
      LAYER M5 ;
        RECT  167.664 0 167.688 0.084 ;
    END
  END r_d[52]
  PIN r_d[53]
    DIRECTION OUTPUT ;
    USE SIGNAL ;
    PORT
      LAYER M5 ;
        RECT  168.576 0 168.6 0.084 ;
    END
  END r_d[53]
  PIN r_d[54]
    DIRECTION OUTPUT ;
    USE SIGNAL ;
    PORT
      LAYER M5 ;
        RECT  169.488 0 169.512 0.084 ;
    END
  END r_d[54]
  PIN r_d[55]
    DIRECTION OUTPUT ;
    USE SIGNAL ;
    PORT
      LAYER M5 ;
        RECT  170.4 0 170.424 0.084 ;
    END
  END r_d[55]
  PIN r_d[56]
    DIRECTION OUTPUT ;
    USE SIGNAL ;
    PORT
      LAYER M5 ;
        RECT  171.312 0 171.336 0.084 ;
    END
  END r_d[56]
  PIN r_d[57]
    DIRECTION OUTPUT ;
    USE SIGNAL ;
    PORT
      LAYER M5 ;
        RECT  172.272 0 172.296 0.084 ;
    END
  END r_d[57]
  PIN r_d[58]
    DIRECTION OUTPUT ;
    USE SIGNAL ;
    PORT
      LAYER M5 ;
        RECT  173.184 0 173.208 0.084 ;
    END
  END r_d[58]
  PIN r_d[59]
    DIRECTION OUTPUT ;
    USE SIGNAL ;
    PORT
      LAYER M5 ;
        RECT  174.096 0 174.12 0.084 ;
    END
  END r_d[59]
  PIN r_d[5]
    DIRECTION OUTPUT ;
    USE SIGNAL ;
    PORT
      LAYER M5 ;
        RECT  124.752 0 124.776 0.084 ;
    END
  END r_d[5]
  PIN r_d[60]
    DIRECTION OUTPUT ;
    USE SIGNAL ;
    PORT
      LAYER M5 ;
        RECT  175.008 0 175.032 0.084 ;
    END
  END r_d[60]
  PIN r_d[61]
    DIRECTION OUTPUT ;
    USE SIGNAL ;
    PORT
      LAYER M5 ;
        RECT  175.92 0 175.944 0.084 ;
    END
  END r_d[61]
  PIN r_d[62]
    DIRECTION OUTPUT ;
    USE SIGNAL ;
    PORT
      LAYER M5 ;
        RECT  176.832 0 176.856 0.084 ;
    END
  END r_d[62]
  PIN r_d[63]
    DIRECTION OUTPUT ;
    USE SIGNAL ;
    PORT
      LAYER M5 ;
        RECT  177.744 0 177.768 0.084 ;
    END
  END r_d[63]
  PIN r_d[64]
    DIRECTION OUTPUT ;
    USE SIGNAL ;
    PORT
      LAYER M5 ;
        RECT  178.656 0 178.68 0.084 ;
    END
  END r_d[64]
  PIN r_d[65]
    DIRECTION OUTPUT ;
    USE SIGNAL ;
    PORT
      LAYER M5 ;
        RECT  179.568 0 179.592 0.084 ;
    END
  END r_d[65]
  PIN r_d[66]
    DIRECTION OUTPUT ;
    USE SIGNAL ;
    PORT
      LAYER M5 ;
        RECT  180.48 0 180.504 0.084 ;
    END
  END r_d[66]
  PIN r_d[67]
    DIRECTION OUTPUT ;
    USE SIGNAL ;
    PORT
      LAYER M5 ;
        RECT  181.392 0 181.416 0.084 ;
    END
  END r_d[67]
  PIN r_d[68]
    DIRECTION OUTPUT ;
    USE SIGNAL ;
    PORT
      LAYER M5 ;
        RECT  182.304 0 182.328 0.084 ;
    END
  END r_d[68]
  PIN r_d[69]
    DIRECTION OUTPUT ;
    USE SIGNAL ;
    PORT
      LAYER M5 ;
        RECT  183.216 0 183.24 0.084 ;
    END
  END r_d[69]
  PIN r_d[6]
    DIRECTION OUTPUT ;
    USE SIGNAL ;
    PORT
      LAYER M5 ;
        RECT  125.664 0 125.688 0.084 ;
    END
  END r_d[6]
  PIN r_d[70]
    DIRECTION OUTPUT ;
    USE SIGNAL ;
    PORT
      LAYER M5 ;
        RECT  184.128 0 184.152 0.084 ;
    END
  END r_d[70]
  PIN r_d[71]
    DIRECTION OUTPUT ;
    USE SIGNAL ;
    PORT
      LAYER M5 ;
        RECT  185.04 0 185.064 0.084 ;
    END
  END r_d[71]
  PIN r_d[72]
    DIRECTION OUTPUT ;
    USE SIGNAL ;
    PORT
      LAYER M5 ;
        RECT  185.952 0 185.976 0.084 ;
    END
  END r_d[72]
  PIN r_d[73]
    DIRECTION OUTPUT ;
    USE SIGNAL ;
    PORT
      LAYER M5 ;
        RECT  186.864 0 186.888 0.084 ;
    END
  END r_d[73]
  PIN r_d[74]
    DIRECTION OUTPUT ;
    USE SIGNAL ;
    PORT
      LAYER M5 ;
        RECT  187.776 0 187.8 0.084 ;
    END
  END r_d[74]
  PIN r_d[75]
    DIRECTION OUTPUT ;
    USE SIGNAL ;
    PORT
      LAYER M5 ;
        RECT  188.688 0 188.712 0.084 ;
    END
  END r_d[75]
  PIN r_d[76]
    DIRECTION OUTPUT ;
    USE SIGNAL ;
    PORT
      LAYER M5 ;
        RECT  189.6 0 189.624 0.084 ;
    END
  END r_d[76]
  PIN r_d[77]
    DIRECTION OUTPUT ;
    USE SIGNAL ;
    PORT
      LAYER M5 ;
        RECT  190.512 0 190.536 0.084 ;
    END
  END r_d[77]
  PIN r_d[78]
    DIRECTION OUTPUT ;
    USE SIGNAL ;
    PORT
      LAYER M5 ;
        RECT  191.424 0 191.448 0.084 ;
    END
  END r_d[78]
  PIN r_d[79]
    DIRECTION OUTPUT ;
    USE SIGNAL ;
    PORT
      LAYER M5 ;
        RECT  192.336 0 192.36 0.084 ;
    END
  END r_d[79]
  PIN r_d[7]
    DIRECTION OUTPUT ;
    USE SIGNAL ;
    PORT
      LAYER M5 ;
        RECT  126.576 0 126.6 0.084 ;
    END
  END r_d[7]
  PIN r_d[80]
    DIRECTION OUTPUT ;
    USE SIGNAL ;
    PORT
      LAYER M5 ;
        RECT  193.248 0 193.272 0.084 ;
    END
  END r_d[80]
  PIN r_d[81]
    DIRECTION OUTPUT ;
    USE SIGNAL ;
    PORT
      LAYER M5 ;
        RECT  194.16 0 194.184 0.084 ;
    END
  END r_d[81]
  PIN r_d[82]
    DIRECTION OUTPUT ;
    USE SIGNAL ;
    PORT
      LAYER M5 ;
        RECT  195.072 0 195.096 0.084 ;
    END
  END r_d[82]
  PIN r_d[83]
    DIRECTION OUTPUT ;
    USE SIGNAL ;
    PORT
      LAYER M5 ;
        RECT  196.032 0 196.056 0.084 ;
    END
  END r_d[83]
  PIN r_d[84]
    DIRECTION OUTPUT ;
    USE SIGNAL ;
    PORT
      LAYER M5 ;
        RECT  196.944 0 196.968 0.084 ;
    END
  END r_d[84]
  PIN r_d[85]
    DIRECTION OUTPUT ;
    USE SIGNAL ;
    PORT
      LAYER M5 ;
        RECT  197.856 0 197.88 0.084 ;
    END
  END r_d[85]
  PIN r_d[86]
    DIRECTION OUTPUT ;
    USE SIGNAL ;
    PORT
      LAYER M5 ;
        RECT  198.768 0 198.792 0.084 ;
    END
  END r_d[86]
  PIN r_d[87]
    DIRECTION OUTPUT ;
    USE SIGNAL ;
    PORT
      LAYER M5 ;
        RECT  199.68 0 199.704 0.084 ;
    END
  END r_d[87]
  PIN r_d[88]
    DIRECTION OUTPUT ;
    USE SIGNAL ;
    PORT
      LAYER M5 ;
        RECT  200.592 0 200.616 0.084 ;
    END
  END r_d[88]
  PIN r_d[89]
    DIRECTION OUTPUT ;
    USE SIGNAL ;
    PORT
      LAYER M5 ;
        RECT  201.504 0 201.528 0.084 ;
    END
  END r_d[89]
  PIN r_d[8]
    DIRECTION OUTPUT ;
    USE SIGNAL ;
    PORT
      LAYER M5 ;
        RECT  127.488 0 127.512 0.084 ;
    END
  END r_d[8]
  PIN r_d[90]
    DIRECTION OUTPUT ;
    USE SIGNAL ;
    PORT
      LAYER M5 ;
        RECT  202.416 0 202.44 0.084 ;
    END
  END r_d[90]
  PIN r_d[91]
    DIRECTION OUTPUT ;
    USE SIGNAL ;
    PORT
      LAYER M5 ;
        RECT  203.328 0 203.352 0.084 ;
    END
  END r_d[91]
  PIN r_d[92]
    DIRECTION OUTPUT ;
    USE SIGNAL ;
    PORT
      LAYER M5 ;
        RECT  204.24 0 204.264 0.084 ;
    END
  END r_d[92]
  PIN r_d[93]
    DIRECTION OUTPUT ;
    USE SIGNAL ;
    PORT
      LAYER M5 ;
        RECT  205.152 0 205.176 0.084 ;
    END
  END r_d[93]
  PIN r_d[94]
    DIRECTION OUTPUT ;
    USE SIGNAL ;
    PORT
      LAYER M5 ;
        RECT  206.064 0 206.088 0.084 ;
    END
  END r_d[94]
  PIN r_d[95]
    DIRECTION OUTPUT ;
    USE SIGNAL ;
    PORT
      LAYER M5 ;
        RECT  206.976 0 207 0.084 ;
    END
  END r_d[95]
  PIN r_d[96]
    DIRECTION OUTPUT ;
    USE SIGNAL ;
    PORT
      LAYER M5 ;
        RECT  207.888 0 207.912 0.084 ;
    END
  END r_d[96]
  PIN r_d[97]
    DIRECTION OUTPUT ;
    USE SIGNAL ;
    PORT
      LAYER M5 ;
        RECT  208.8 0 208.824 0.084 ;
    END
  END r_d[97]
  PIN r_d[98]
    DIRECTION OUTPUT ;
    USE SIGNAL ;
    PORT
      LAYER M5 ;
        RECT  209.712 0 209.736 0.084 ;
    END
  END r_d[98]
  PIN r_d[99]
    DIRECTION OUTPUT ;
    USE SIGNAL ;
    PORT
      LAYER M5 ;
        RECT  210.624 0 210.648 0.084 ;
    END
  END r_d[99]
  PIN r_d[9]
    DIRECTION OUTPUT ;
    USE SIGNAL ;
    PORT
      LAYER M5 ;
        RECT  128.4 0 128.424 0.084 ;
    END
  END r_d[9]
  PIN r_v
    DIRECTION OUTPUT ;
    USE SIGNAL ;
    PORT
      LAYER M5 ;
        RECT  237.12 0 237.144 0.084 ;
    END
  END r_v
  PIN rst_n
    DIRECTION INPUT ;
    USE SIGNAL ;
    PORT
      LAYER M4 ;
        RECT  0 72 0.084 72.024 ;
    END
    PORT
      LAYER M4 ;
        RECT  0.06 72 0.179 72.024 ;
    END
  END rst_n
  PIN rx_flit[0]
    DIRECTION INPUT ;
    USE SIGNAL ;
    PORT
      LAYER M4 ;
        RECT  237.516 0.144 237.6 0.168 ;
    END
  END rx_flit[0]
  PIN rx_flit[100]
    DIRECTION INPUT ;
    USE SIGNAL ;
    PORT
      LAYER M4 ;
        RECT  237.516 29.232 237.6 29.256 ;
    END
  END rx_flit[100]
  PIN rx_flit[101]
    DIRECTION INPUT ;
    USE SIGNAL ;
    PORT
      LAYER M4 ;
        RECT  237.516 29.52 237.6 29.544 ;
    END
  END rx_flit[101]
  PIN rx_flit[102]
    DIRECTION INPUT ;
    USE SIGNAL ;
    PORT
      LAYER M4 ;
        RECT  237.516 29.808 237.6 29.832 ;
    END
  END rx_flit[102]
  PIN rx_flit[103]
    DIRECTION INPUT ;
    USE SIGNAL ;
    PORT
      LAYER M4 ;
        RECT  237.516 30.096 237.6 30.12 ;
    END
  END rx_flit[103]
  PIN rx_flit[104]
    DIRECTION INPUT ;
    USE SIGNAL ;
    PORT
      LAYER M4 ;
        RECT  237.516 30.384 237.6 30.408 ;
    END
  END rx_flit[104]
  PIN rx_flit[105]
    DIRECTION INPUT ;
    USE SIGNAL ;
    PORT
      LAYER M4 ;
        RECT  237.516 30.672 237.6 30.696 ;
    END
  END rx_flit[105]
  PIN rx_flit[106]
    DIRECTION INPUT ;
    USE SIGNAL ;
    PORT
      LAYER M4 ;
        RECT  237.516 30.96 237.6 30.984 ;
    END
  END rx_flit[106]
  PIN rx_flit[107]
    DIRECTION INPUT ;
    USE SIGNAL ;
    PORT
      LAYER M4 ;
        RECT  237.516 31.248 237.6 31.272 ;
    END
  END rx_flit[107]
  PIN rx_flit[108]
    DIRECTION INPUT ;
    USE SIGNAL ;
    PORT
      LAYER M4 ;
        RECT  237.516 31.536 237.6 31.56 ;
    END
  END rx_flit[108]
  PIN rx_flit[109]
    DIRECTION INPUT ;
    USE SIGNAL ;
    PORT
      LAYER M4 ;
        RECT  237.516 31.824 237.6 31.848 ;
    END
  END rx_flit[109]
  PIN rx_flit[10]
    DIRECTION INPUT ;
    USE SIGNAL ;
    PORT
      LAYER M4 ;
        RECT  237.516 3.024 237.6 3.048 ;
    END
  END rx_flit[10]
  PIN rx_flit[110]
    DIRECTION INPUT ;
    USE SIGNAL ;
    PORT
      LAYER M4 ;
        RECT  237.516 32.112 237.6 32.136 ;
    END
  END rx_flit[110]
  PIN rx_flit[111]
    DIRECTION INPUT ;
    USE SIGNAL ;
    PORT
      LAYER M4 ;
        RECT  237.516 32.448 237.6 32.472 ;
    END
  END rx_flit[111]
  PIN rx_flit[112]
    DIRECTION INPUT ;
    USE SIGNAL ;
    PORT
      LAYER M4 ;
        RECT  237.516 32.736 237.6 32.76 ;
    END
  END rx_flit[112]
  PIN rx_flit[113]
    DIRECTION INPUT ;
    USE SIGNAL ;
    PORT
      LAYER M4 ;
        RECT  237.516 33.024 237.6 33.048 ;
    END
  END rx_flit[113]
  PIN rx_flit[114]
    DIRECTION INPUT ;
    USE SIGNAL ;
    PORT
      LAYER M4 ;
        RECT  237.516 33.312 237.6 33.336 ;
    END
  END rx_flit[114]
  PIN rx_flit[115]
    DIRECTION INPUT ;
    USE SIGNAL ;
    PORT
      LAYER M4 ;
        RECT  237.516 33.6 237.6 33.624 ;
    END
  END rx_flit[115]
  PIN rx_flit[116]
    DIRECTION INPUT ;
    USE SIGNAL ;
    PORT
      LAYER M4 ;
        RECT  237.516 33.888 237.6 33.912 ;
    END
  END rx_flit[116]
  PIN rx_flit[117]
    DIRECTION INPUT ;
    USE SIGNAL ;
    PORT
      LAYER M4 ;
        RECT  237.516 34.176 237.6 34.2 ;
    END
  END rx_flit[117]
  PIN rx_flit[118]
    DIRECTION INPUT ;
    USE SIGNAL ;
    PORT
      LAYER M4 ;
        RECT  237.516 34.464 237.6 34.488 ;
    END
  END rx_flit[118]
  PIN rx_flit[119]
    DIRECTION INPUT ;
    USE SIGNAL ;
    PORT
      LAYER M4 ;
        RECT  237.516 34.752 237.6 34.776 ;
    END
  END rx_flit[119]
  PIN rx_flit[11]
    DIRECTION INPUT ;
    USE SIGNAL ;
    PORT
      LAYER M4 ;
        RECT  237.516 3.312 237.6 3.336 ;
    END
  END rx_flit[11]
  PIN rx_flit[120]
    DIRECTION INPUT ;
    USE SIGNAL ;
    PORT
      LAYER M4 ;
        RECT  237.516 35.04 237.6 35.064 ;
    END
  END rx_flit[120]
  PIN rx_flit[121]
    DIRECTION INPUT ;
    USE SIGNAL ;
    PORT
      LAYER M4 ;
        RECT  237.516 35.328 237.6 35.352 ;
    END
  END rx_flit[121]
  PIN rx_flit[122]
    DIRECTION INPUT ;
    USE SIGNAL ;
    PORT
      LAYER M4 ;
        RECT  237.516 35.616 237.6 35.64 ;
    END
  END rx_flit[122]
  PIN rx_flit[123]
    DIRECTION INPUT ;
    USE SIGNAL ;
    PORT
      LAYER M4 ;
        RECT  237.516 35.904 237.6 35.928 ;
    END
  END rx_flit[123]
  PIN rx_flit[124]
    DIRECTION INPUT ;
    USE SIGNAL ;
    PORT
      LAYER M4 ;
        RECT  237.516 36.192 237.6 36.216 ;
    END
  END rx_flit[124]
  PIN rx_flit[125]
    DIRECTION INPUT ;
    USE SIGNAL ;
    PORT
      LAYER M4 ;
        RECT  237.516 36.48 237.6 36.504 ;
    END
  END rx_flit[125]
  PIN rx_flit[126]
    DIRECTION INPUT ;
    USE SIGNAL ;
    PORT
      LAYER M4 ;
        RECT  237.516 36.768 237.6 36.792 ;
    END
  END rx_flit[126]
  PIN rx_flit[127]
    DIRECTION INPUT ;
    USE SIGNAL ;
    PORT
      LAYER M4 ;
        RECT  237.516 37.056 237.6 37.08 ;
    END
  END rx_flit[127]
  PIN rx_flit[128]
    DIRECTION INPUT ;
    USE SIGNAL ;
    PORT
      LAYER M4 ;
        RECT  237.516 37.392 237.6 37.416 ;
    END
  END rx_flit[128]
  PIN rx_flit[129]
    DIRECTION INPUT ;
    USE SIGNAL ;
    PORT
      LAYER M4 ;
        RECT  237.516 37.68 237.6 37.704 ;
    END
  END rx_flit[129]
  PIN rx_flit[12]
    DIRECTION INPUT ;
    USE SIGNAL ;
    PORT
      LAYER M4 ;
        RECT  237.516 3.648 237.6 3.672 ;
    END
  END rx_flit[12]
  PIN rx_flit[130]
    DIRECTION INPUT ;
    USE SIGNAL ;
    PORT
      LAYER M4 ;
        RECT  237.516 37.968 237.6 37.992 ;
    END
  END rx_flit[130]
  PIN rx_flit[131]
    DIRECTION INPUT ;
    USE SIGNAL ;
    PORT
      LAYER M4 ;
        RECT  237.516 38.256 237.6 38.28 ;
    END
  END rx_flit[131]
  PIN rx_flit[132]
    DIRECTION INPUT ;
    USE SIGNAL ;
    PORT
      LAYER M4 ;
        RECT  237.516 38.544 237.6 38.568 ;
    END
  END rx_flit[132]
  PIN rx_flit[133]
    DIRECTION INPUT ;
    USE SIGNAL ;
    PORT
      LAYER M4 ;
        RECT  237.516 38.832 237.6 38.856 ;
    END
  END rx_flit[133]
  PIN rx_flit[134]
    DIRECTION INPUT ;
    USE SIGNAL ;
    PORT
      LAYER M4 ;
        RECT  237.516 39.12 237.6 39.144 ;
    END
  END rx_flit[134]
  PIN rx_flit[135]
    DIRECTION INPUT ;
    USE SIGNAL ;
    PORT
      LAYER M4 ;
        RECT  237.516 39.408 237.6 39.432 ;
    END
  END rx_flit[135]
  PIN rx_flit[136]
    DIRECTION INPUT ;
    USE SIGNAL ;
    PORT
      LAYER M4 ;
        RECT  237.516 39.696 237.6 39.72 ;
    END
  END rx_flit[136]
  PIN rx_flit[137]
    DIRECTION INPUT ;
    USE SIGNAL ;
    PORT
      LAYER M4 ;
        RECT  237.516 39.984 237.6 40.008 ;
    END
  END rx_flit[137]
  PIN rx_flit[138]
    DIRECTION INPUT ;
    USE SIGNAL ;
    PORT
      LAYER M4 ;
        RECT  237.516 40.272 237.6 40.296 ;
    END
  END rx_flit[138]
  PIN rx_flit[139]
    DIRECTION INPUT ;
    USE SIGNAL ;
    PORT
      LAYER M4 ;
        RECT  237.516 40.56 237.6 40.584 ;
    END
  END rx_flit[139]
  PIN rx_flit[13]
    DIRECTION INPUT ;
    USE SIGNAL ;
    PORT
      LAYER M4 ;
        RECT  237.516 3.936 237.6 3.96 ;
    END
  END rx_flit[13]
  PIN rx_flit[140]
    DIRECTION INPUT ;
    USE SIGNAL ;
    PORT
      LAYER M4 ;
        RECT  237.516 40.848 237.6 40.872 ;
    END
  END rx_flit[140]
  PIN rx_flit[141]
    DIRECTION INPUT ;
    USE SIGNAL ;
    PORT
      LAYER M4 ;
        RECT  237.516 41.136 237.6 41.16 ;
    END
  END rx_flit[141]
  PIN rx_flit[142]
    DIRECTION INPUT ;
    USE SIGNAL ;
    PORT
      LAYER M4 ;
        RECT  237.516 41.424 237.6 41.448 ;
    END
  END rx_flit[142]
  PIN rx_flit[143]
    DIRECTION INPUT ;
    USE SIGNAL ;
    PORT
      LAYER M4 ;
        RECT  237.516 41.712 237.6 41.736 ;
    END
  END rx_flit[143]
  PIN rx_flit[144]
    DIRECTION INPUT ;
    USE SIGNAL ;
    PORT
      LAYER M4 ;
        RECT  237.516 42.048 237.6 42.072 ;
    END
  END rx_flit[144]
  PIN rx_flit[145]
    DIRECTION INPUT ;
    USE SIGNAL ;
    PORT
      LAYER M4 ;
        RECT  237.516 42.336 237.6 42.36 ;
    END
  END rx_flit[145]
  PIN rx_flit[146]
    DIRECTION INPUT ;
    USE SIGNAL ;
    PORT
      LAYER M4 ;
        RECT  237.516 42.624 237.6 42.648 ;
    END
  END rx_flit[146]
  PIN rx_flit[14]
    DIRECTION INPUT ;
    USE SIGNAL ;
    PORT
      LAYER M4 ;
        RECT  237.516 4.224 237.6 4.248 ;
    END
  END rx_flit[14]
  PIN rx_flit[15]
    DIRECTION INPUT ;
    USE SIGNAL ;
    PORT
      LAYER M4 ;
        RECT  237.516 4.512 237.6 4.536 ;
    END
  END rx_flit[15]
  PIN rx_flit[16]
    DIRECTION INPUT ;
    USE SIGNAL ;
    PORT
      LAYER M4 ;
        RECT  237.516 4.8 237.6 4.824 ;
    END
  END rx_flit[16]
  PIN rx_flit[17]
    DIRECTION INPUT ;
    USE SIGNAL ;
    PORT
      LAYER M4 ;
        RECT  237.516 5.088 237.6 5.112 ;
    END
  END rx_flit[17]
  PIN rx_flit[18]
    DIRECTION INPUT ;
    USE SIGNAL ;
    PORT
      LAYER M4 ;
        RECT  237.516 5.376 237.6 5.4 ;
    END
  END rx_flit[18]
  PIN rx_flit[19]
    DIRECTION INPUT ;
    USE SIGNAL ;
    PORT
      LAYER M4 ;
        RECT  237.516 5.664 237.6 5.688 ;
    END
  END rx_flit[19]
  PIN rx_flit[1]
    DIRECTION INPUT ;
    USE SIGNAL ;
    PORT
      LAYER M4 ;
        RECT  237.516 0.432 237.6 0.456 ;
    END
  END rx_flit[1]
  PIN rx_flit[20]
    DIRECTION INPUT ;
    USE SIGNAL ;
    PORT
      LAYER M4 ;
        RECT  237.516 5.952 237.6 5.976 ;
    END
  END rx_flit[20]
  PIN rx_flit[21]
    DIRECTION INPUT ;
    USE SIGNAL ;
    PORT
      LAYER M4 ;
        RECT  237.516 6.24 237.6 6.264 ;
    END
  END rx_flit[21]
  PIN rx_flit[22]
    DIRECTION INPUT ;
    USE SIGNAL ;
    PORT
      LAYER M4 ;
        RECT  237.516 6.528 237.6 6.552 ;
    END
  END rx_flit[22]
  PIN rx_flit[23]
    DIRECTION INPUT ;
    USE SIGNAL ;
    PORT
      LAYER M4 ;
        RECT  237.516 6.816 237.6 6.84 ;
    END
  END rx_flit[23]
  PIN rx_flit[24]
    DIRECTION INPUT ;
    USE SIGNAL ;
    PORT
      LAYER M4 ;
        RECT  237.516 7.104 237.6 7.128 ;
    END
  END rx_flit[24]
  PIN rx_flit[25]
    DIRECTION INPUT ;
    USE SIGNAL ;
    PORT
      LAYER M4 ;
        RECT  237.516 7.392 237.6 7.416 ;
    END
  END rx_flit[25]
  PIN rx_flit[26]
    DIRECTION INPUT ;
    USE SIGNAL ;
    PORT
      LAYER M4 ;
        RECT  237.516 7.68 237.6 7.704 ;
    END
  END rx_flit[26]
  PIN rx_flit[27]
    DIRECTION INPUT ;
    USE SIGNAL ;
    PORT
      LAYER M4 ;
        RECT  237.516 7.968 237.6 7.992 ;
    END
  END rx_flit[27]
  PIN rx_flit[28]
    DIRECTION INPUT ;
    USE SIGNAL ;
    PORT
      LAYER M4 ;
        RECT  237.516 8.256 237.6 8.28 ;
    END
  END rx_flit[28]
  PIN rx_flit[29]
    DIRECTION INPUT ;
    USE SIGNAL ;
    PORT
      LAYER M4 ;
        RECT  237.516 8.592 237.6 8.616 ;
    END
  END rx_flit[29]
  PIN rx_flit[2]
    DIRECTION INPUT ;
    USE SIGNAL ;
    PORT
      LAYER M4 ;
        RECT  237.516 0.72 237.6 0.744 ;
    END
  END rx_flit[2]
  PIN rx_flit[30]
    DIRECTION INPUT ;
    USE SIGNAL ;
    PORT
      LAYER M4 ;
        RECT  237.516 8.88 237.6 8.904 ;
    END
  END rx_flit[30]
  PIN rx_flit[31]
    DIRECTION INPUT ;
    USE SIGNAL ;
    PORT
      LAYER M4 ;
        RECT  237.516 9.168 237.6 9.192 ;
    END
  END rx_flit[31]
  PIN rx_flit[32]
    DIRECTION INPUT ;
    USE SIGNAL ;
    PORT
      LAYER M4 ;
        RECT  237.516 9.456 237.6 9.48 ;
    END
  END rx_flit[32]
  PIN rx_flit[33]
    DIRECTION INPUT ;
    USE SIGNAL ;
    PORT
      LAYER M4 ;
        RECT  237.516 9.744 237.6 9.768 ;
    END
  END rx_flit[33]
  PIN rx_flit[34]
    DIRECTION INPUT ;
    USE SIGNAL ;
    PORT
      LAYER M4 ;
        RECT  237.516 10.032 237.6 10.056 ;
    END
  END rx_flit[34]
  PIN rx_flit[35]
    DIRECTION INPUT ;
    USE SIGNAL ;
    PORT
      LAYER M4 ;
        RECT  237.516 10.32 237.6 10.344 ;
    END
  END rx_flit[35]
  PIN rx_flit[36]
    DIRECTION INPUT ;
    USE SIGNAL ;
    PORT
      LAYER M4 ;
        RECT  237.516 10.608 237.6 10.632 ;
    END
  END rx_flit[36]
  PIN rx_flit[37]
    DIRECTION INPUT ;
    USE SIGNAL ;
    PORT
      LAYER M4 ;
        RECT  237.516 10.896 237.6 10.92 ;
    END
  END rx_flit[37]
  PIN rx_flit[38]
    DIRECTION INPUT ;
    USE SIGNAL ;
    PORT
      LAYER M4 ;
        RECT  237.516 11.184 237.6 11.208 ;
    END
  END rx_flit[38]
  PIN rx_flit[39]
    DIRECTION INPUT ;
    USE SIGNAL ;
    PORT
      LAYER M4 ;
        RECT  237.516 11.472 237.6 11.496 ;
    END
  END rx_flit[39]
  PIN rx_flit[3]
    DIRECTION INPUT ;
    USE SIGNAL ;
    PORT
      LAYER M4 ;
        RECT  237.516 1.008 237.6 1.032 ;
    END
  END rx_flit[3]
  PIN rx_flit[40]
    DIRECTION INPUT ;
    USE SIGNAL ;
    PORT
      LAYER M4 ;
        RECT  237.516 11.76 237.6 11.784 ;
    END
  END rx_flit[40]
  PIN rx_flit[41]
    DIRECTION INPUT ;
    USE SIGNAL ;
    PORT
      LAYER M4 ;
        RECT  237.516 12.048 237.6 12.072 ;
    END
  END rx_flit[41]
  PIN rx_flit[42]
    DIRECTION INPUT ;
    USE SIGNAL ;
    PORT
      LAYER M4 ;
        RECT  237.516 12.336 237.6 12.36 ;
    END
  END rx_flit[42]
  PIN rx_flit[43]
    DIRECTION INPUT ;
    USE SIGNAL ;
    PORT
      LAYER M4 ;
        RECT  237.516 12.624 237.6 12.648 ;
    END
  END rx_flit[43]
  PIN rx_flit[44]
    DIRECTION INPUT ;
    USE SIGNAL ;
    PORT
      LAYER M4 ;
        RECT  237.516 12.912 237.6 12.936 ;
    END
  END rx_flit[44]
  PIN rx_flit[45]
    DIRECTION INPUT ;
    USE SIGNAL ;
    PORT
      LAYER M4 ;
        RECT  237.516 13.248 237.6 13.272 ;
    END
  END rx_flit[45]
  PIN rx_flit[46]
    DIRECTION INPUT ;
    USE SIGNAL ;
    PORT
      LAYER M4 ;
        RECT  237.516 13.536 237.6 13.56 ;
    END
  END rx_flit[46]
  PIN rx_flit[47]
    DIRECTION INPUT ;
    USE SIGNAL ;
    PORT
      LAYER M4 ;
        RECT  237.516 13.824 237.6 13.848 ;
    END
  END rx_flit[47]
  PIN rx_flit[48]
    DIRECTION INPUT ;
    USE SIGNAL ;
    PORT
      LAYER M4 ;
        RECT  237.516 14.112 237.6 14.136 ;
    END
  END rx_flit[48]
  PIN rx_flit[49]
    DIRECTION INPUT ;
    USE SIGNAL ;
    PORT
      LAYER M4 ;
        RECT  237.516 14.4 237.6 14.424 ;
    END
  END rx_flit[49]
  PIN rx_flit[4]
    DIRECTION INPUT ;
    USE SIGNAL ;
    PORT
      LAYER M4 ;
        RECT  237.516 1.296 237.6 1.32 ;
    END
  END rx_flit[4]
  PIN rx_flit[50]
    DIRECTION INPUT ;
    USE SIGNAL ;
    PORT
      LAYER M4 ;
        RECT  237.516 14.688 237.6 14.712 ;
    END
  END rx_flit[50]
  PIN rx_flit[51]
    DIRECTION INPUT ;
    USE SIGNAL ;
    PORT
      LAYER M4 ;
        RECT  237.516 14.976 237.6 15 ;
    END
  END rx_flit[51]
  PIN rx_flit[52]
    DIRECTION INPUT ;
    USE SIGNAL ;
    PORT
      LAYER M4 ;
        RECT  237.516 15.264 237.6 15.288 ;
    END
  END rx_flit[52]
  PIN rx_flit[53]
    DIRECTION INPUT ;
    USE SIGNAL ;
    PORT
      LAYER M4 ;
        RECT  237.516 15.552 237.6 15.576 ;
    END
  END rx_flit[53]
  PIN rx_flit[54]
    DIRECTION INPUT ;
    USE SIGNAL ;
    PORT
      LAYER M4 ;
        RECT  237.516 15.84 237.6 15.864 ;
    END
  END rx_flit[54]
  PIN rx_flit[55]
    DIRECTION INPUT ;
    USE SIGNAL ;
    PORT
      LAYER M4 ;
        RECT  237.516 16.128 237.6 16.152 ;
    END
  END rx_flit[55]
  PIN rx_flit[56]
    DIRECTION INPUT ;
    USE SIGNAL ;
    PORT
      LAYER M4 ;
        RECT  237.516 16.416 237.6 16.44 ;
    END
  END rx_flit[56]
  PIN rx_flit[57]
    DIRECTION INPUT ;
    USE SIGNAL ;
    PORT
      LAYER M4 ;
        RECT  237.516 16.704 237.6 16.728 ;
    END
  END rx_flit[57]
  PIN rx_flit[58]
    DIRECTION INPUT ;
    USE SIGNAL ;
    PORT
      LAYER M4 ;
        RECT  237.516 16.992 237.6 17.016 ;
    END
  END rx_flit[58]
  PIN rx_flit[59]
    DIRECTION INPUT ;
    USE SIGNAL ;
    PORT
      LAYER M4 ;
        RECT  237.516 17.28 237.6 17.304 ;
    END
  END rx_flit[59]
  PIN rx_flit[5]
    DIRECTION INPUT ;
    USE SIGNAL ;
    PORT
      LAYER M4 ;
        RECT  237.516 1.584 237.6 1.608 ;
    END
  END rx_flit[5]
  PIN rx_flit[60]
    DIRECTION INPUT ;
    USE SIGNAL ;
    PORT
      LAYER M4 ;
        RECT  237.516 17.568 237.6 17.592 ;
    END
  END rx_flit[60]
  PIN rx_flit[61]
    DIRECTION INPUT ;
    USE SIGNAL ;
    PORT
      LAYER M4 ;
        RECT  237.516 17.856 237.6 17.88 ;
    END
  END rx_flit[61]
  PIN rx_flit[62]
    DIRECTION INPUT ;
    USE SIGNAL ;
    PORT
      LAYER M4 ;
        RECT  237.516 18.192 237.6 18.216 ;
    END
  END rx_flit[62]
  PIN rx_flit[63]
    DIRECTION INPUT ;
    USE SIGNAL ;
    PORT
      LAYER M4 ;
        RECT  237.516 18.48 237.6 18.504 ;
    END
  END rx_flit[63]
  PIN rx_flit[64]
    DIRECTION INPUT ;
    USE SIGNAL ;
    PORT
      LAYER M4 ;
        RECT  237.516 18.768 237.6 18.792 ;
    END
  END rx_flit[64]
  PIN rx_flit[65]
    DIRECTION INPUT ;
    USE SIGNAL ;
    PORT
      LAYER M4 ;
        RECT  237.516 19.056 237.6 19.08 ;
    END
  END rx_flit[65]
  PIN rx_flit[66]
    DIRECTION INPUT ;
    USE SIGNAL ;
    PORT
      LAYER M4 ;
        RECT  237.516 19.344 237.6 19.368 ;
    END
  END rx_flit[66]
  PIN rx_flit[67]
    DIRECTION INPUT ;
    USE SIGNAL ;
    PORT
      LAYER M4 ;
        RECT  237.516 19.632 237.6 19.656 ;
    END
  END rx_flit[67]
  PIN rx_flit[68]
    DIRECTION INPUT ;
    USE SIGNAL ;
    PORT
      LAYER M4 ;
        RECT  237.516 19.92 237.6 19.944 ;
    END
  END rx_flit[68]
  PIN rx_flit[69]
    DIRECTION INPUT ;
    USE SIGNAL ;
    PORT
      LAYER M4 ;
        RECT  237.516 20.208 237.6 20.232 ;
    END
  END rx_flit[69]
  PIN rx_flit[6]
    DIRECTION INPUT ;
    USE SIGNAL ;
    PORT
      LAYER M4 ;
        RECT  237.516 1.872 237.6 1.896 ;
    END
  END rx_flit[6]
  PIN rx_flit[70]
    DIRECTION INPUT ;
    USE SIGNAL ;
    PORT
      LAYER M4 ;
        RECT  237.516 20.496 237.6 20.52 ;
    END
  END rx_flit[70]
  PIN rx_flit[71]
    DIRECTION INPUT ;
    USE SIGNAL ;
    PORT
      LAYER M4 ;
        RECT  237.516 20.784 237.6 20.808 ;
    END
  END rx_flit[71]
  PIN rx_flit[72]
    DIRECTION INPUT ;
    USE SIGNAL ;
    PORT
      LAYER M4 ;
        RECT  237.516 21.072 237.6 21.096 ;
    END
  END rx_flit[72]
  PIN rx_flit[73]
    DIRECTION INPUT ;
    USE SIGNAL ;
    PORT
      LAYER M4 ;
        RECT  237.516 21.36 237.6 21.384 ;
    END
  END rx_flit[73]
  PIN rx_flit[74]
    DIRECTION INPUT ;
    USE SIGNAL ;
    PORT
      LAYER M4 ;
        RECT  237.516 21.648 237.6 21.672 ;
    END
  END rx_flit[74]
  PIN rx_flit[75]
    DIRECTION INPUT ;
    USE SIGNAL ;
    PORT
      LAYER M4 ;
        RECT  237.516 21.936 237.6 21.96 ;
    END
  END rx_flit[75]
  PIN rx_flit[76]
    DIRECTION INPUT ;
    USE SIGNAL ;
    PORT
      LAYER M4 ;
        RECT  237.516 22.224 237.6 22.248 ;
    END
  END rx_flit[76]
  PIN rx_flit[77]
    DIRECTION INPUT ;
    USE SIGNAL ;
    PORT
      LAYER M4 ;
        RECT  237.516 22.512 237.6 22.536 ;
    END
  END rx_flit[77]
  PIN rx_flit[78]
    DIRECTION INPUT ;
    USE SIGNAL ;
    PORT
      LAYER M4 ;
        RECT  237.516 22.848 237.6 22.872 ;
    END
  END rx_flit[78]
  PIN rx_flit[79]
    DIRECTION INPUT ;
    USE SIGNAL ;
    PORT
      LAYER M4 ;
        RECT  237.516 23.136 237.6 23.16 ;
    END
  END rx_flit[79]
  PIN rx_flit[7]
    DIRECTION INPUT ;
    USE SIGNAL ;
    PORT
      LAYER M4 ;
        RECT  237.516 2.16 237.6 2.184 ;
    END
  END rx_flit[7]
  PIN rx_flit[80]
    DIRECTION INPUT ;
    USE SIGNAL ;
    PORT
      LAYER M4 ;
        RECT  237.516 23.424 237.6 23.448 ;
    END
  END rx_flit[80]
  PIN rx_flit[81]
    DIRECTION INPUT ;
    USE SIGNAL ;
    PORT
      LAYER M4 ;
        RECT  237.516 23.712 237.6 23.736 ;
    END
  END rx_flit[81]
  PIN rx_flit[82]
    DIRECTION INPUT ;
    USE SIGNAL ;
    PORT
      LAYER M4 ;
        RECT  237.516 24 237.6 24.024 ;
    END
  END rx_flit[82]
  PIN rx_flit[83]
    DIRECTION INPUT ;
    USE SIGNAL ;
    PORT
      LAYER M4 ;
        RECT  237.516 24.288 237.6 24.312 ;
    END
  END rx_flit[83]
  PIN rx_flit[84]
    DIRECTION INPUT ;
    USE SIGNAL ;
    PORT
      LAYER M4 ;
        RECT  237.516 24.576 237.6 24.6 ;
    END
  END rx_flit[84]
  PIN rx_flit[85]
    DIRECTION INPUT ;
    USE SIGNAL ;
    PORT
      LAYER M4 ;
        RECT  237.516 24.864 237.6 24.888 ;
    END
  END rx_flit[85]
  PIN rx_flit[86]
    DIRECTION INPUT ;
    USE SIGNAL ;
    PORT
      LAYER M4 ;
        RECT  237.516 25.152 237.6 25.176 ;
    END
  END rx_flit[86]
  PIN rx_flit[87]
    DIRECTION INPUT ;
    USE SIGNAL ;
    PORT
      LAYER M4 ;
        RECT  237.516 25.44 237.6 25.464 ;
    END
  END rx_flit[87]
  PIN rx_flit[88]
    DIRECTION INPUT ;
    USE SIGNAL ;
    PORT
      LAYER M4 ;
        RECT  237.516 25.728 237.6 25.752 ;
    END
  END rx_flit[88]
  PIN rx_flit[89]
    DIRECTION INPUT ;
    USE SIGNAL ;
    PORT
      LAYER M4 ;
        RECT  237.516 26.016 237.6 26.04 ;
    END
  END rx_flit[89]
  PIN rx_flit[8]
    DIRECTION INPUT ;
    USE SIGNAL ;
    PORT
      LAYER M4 ;
        RECT  237.516 2.448 237.6 2.472 ;
    END
  END rx_flit[8]
  PIN rx_flit[90]
    DIRECTION INPUT ;
    USE SIGNAL ;
    PORT
      LAYER M4 ;
        RECT  237.516 26.304 237.6 26.328 ;
    END
  END rx_flit[90]
  PIN rx_flit[91]
    DIRECTION INPUT ;
    USE SIGNAL ;
    PORT
      LAYER M4 ;
        RECT  237.516 26.592 237.6 26.616 ;
    END
  END rx_flit[91]
  PIN rx_flit[92]
    DIRECTION INPUT ;
    USE SIGNAL ;
    PORT
      LAYER M4 ;
        RECT  237.516 26.88 237.6 26.904 ;
    END
  END rx_flit[92]
  PIN rx_flit[93]
    DIRECTION INPUT ;
    USE SIGNAL ;
    PORT
      LAYER M4 ;
        RECT  237.516 27.168 237.6 27.192 ;
    END
  END rx_flit[93]
  PIN rx_flit[94]
    DIRECTION INPUT ;
    USE SIGNAL ;
    PORT
      LAYER M4 ;
        RECT  237.516 27.456 237.6 27.48 ;
    END
  END rx_flit[94]
  PIN rx_flit[95]
    DIRECTION INPUT ;
    USE SIGNAL ;
    PORT
      LAYER M4 ;
        RECT  237.516 27.792 237.6 27.816 ;
    END
  END rx_flit[95]
  PIN rx_flit[96]
    DIRECTION INPUT ;
    USE SIGNAL ;
    PORT
      LAYER M4 ;
        RECT  237.516 28.08 237.6 28.104 ;
    END
  END rx_flit[96]
  PIN rx_flit[97]
    DIRECTION INPUT ;
    USE SIGNAL ;
    PORT
      LAYER M4 ;
        RECT  237.516 28.368 237.6 28.392 ;
    END
  END rx_flit[97]
  PIN rx_flit[98]
    DIRECTION INPUT ;
    USE SIGNAL ;
    PORT
      LAYER M4 ;
        RECT  237.516 28.656 237.6 28.68 ;
    END
  END rx_flit[98]
  PIN rx_flit[99]
    DIRECTION INPUT ;
    USE SIGNAL ;
    PORT
      LAYER M4 ;
        RECT  237.516 28.944 237.6 28.968 ;
    END
  END rx_flit[99]
  PIN rx_flit[9]
    DIRECTION INPUT ;
    USE SIGNAL ;
    PORT
      LAYER M4 ;
        RECT  237.516 2.736 237.6 2.76 ;
    END
  END rx_flit[9]
  PIN rx_v
    DIRECTION INPUT ;
    USE SIGNAL ;
    PORT
      LAYER M4 ;
        RECT  237.516 42.912 237.6 42.936 ;
    END
  END rx_v
  PIN tx_flit[0]
    DIRECTION OUTPUT ;
    USE SIGNAL ;
    PORT
      LAYER M4 ;
        RECT  237.516 43.2 237.6 43.224 ;
    END
  END tx_flit[0]
  PIN tx_flit[100]
    DIRECTION OUTPUT ;
    USE SIGNAL ;
    PORT
      LAYER M4 ;
        RECT  237.516 72.288 237.6 72.312 ;
    END
  END tx_flit[100]
  PIN tx_flit[101]
    DIRECTION OUTPUT ;
    USE SIGNAL ;
    PORT
      LAYER M4 ;
        RECT  237.516 72.576 237.6 72.6 ;
    END
  END tx_flit[101]
  PIN tx_flit[102]
    DIRECTION OUTPUT ;
    USE SIGNAL ;
    PORT
      LAYER M4 ;
        RECT  237.516 72.864 237.6 72.888 ;
    END
  END tx_flit[102]
  PIN tx_flit[103]
    DIRECTION OUTPUT ;
    USE SIGNAL ;
    PORT
      LAYER M4 ;
        RECT  237.516 73.152 237.6 73.176 ;
    END
  END tx_flit[103]
  PIN tx_flit[104]
    DIRECTION OUTPUT ;
    USE SIGNAL ;
    PORT
      LAYER M4 ;
        RECT  237.516 73.44 237.6 73.464 ;
    END
  END tx_flit[104]
  PIN tx_flit[105]
    DIRECTION OUTPUT ;
    USE SIGNAL ;
    PORT
      LAYER M4 ;
        RECT  237.516 73.728 237.6 73.752 ;
    END
  END tx_flit[105]
  PIN tx_flit[106]
    DIRECTION OUTPUT ;
    USE SIGNAL ;
    PORT
      LAYER M4 ;
        RECT  237.516 74.016 237.6 74.04 ;
    END
  END tx_flit[106]
  PIN tx_flit[107]
    DIRECTION OUTPUT ;
    USE SIGNAL ;
    PORT
      LAYER M4 ;
        RECT  237.516 74.304 237.6 74.328 ;
    END
  END tx_flit[107]
  PIN tx_flit[108]
    DIRECTION OUTPUT ;
    USE SIGNAL ;
    PORT
      LAYER M4 ;
        RECT  237.516 74.592 237.6 74.616 ;
    END
  END tx_flit[108]
  PIN tx_flit[109]
    DIRECTION OUTPUT ;
    USE SIGNAL ;
    PORT
      LAYER M4 ;
        RECT  237.516 74.88 237.6 74.904 ;
    END
  END tx_flit[109]
  PIN tx_flit[10]
    DIRECTION OUTPUT ;
    USE SIGNAL ;
    PORT
      LAYER M4 ;
        RECT  237.516 46.08 237.6 46.104 ;
    END
  END tx_flit[10]
  PIN tx_flit[110]
    DIRECTION OUTPUT ;
    USE SIGNAL ;
    PORT
      LAYER M4 ;
        RECT  237.516 75.168 237.6 75.192 ;
    END
  END tx_flit[110]
  PIN tx_flit[111]
    DIRECTION OUTPUT ;
    USE SIGNAL ;
    PORT
      LAYER M4 ;
        RECT  237.516 75.456 237.6 75.48 ;
    END
  END tx_flit[111]
  PIN tx_flit[112]
    DIRECTION OUTPUT ;
    USE SIGNAL ;
    PORT
      LAYER M4 ;
        RECT  237.516 75.792 237.6 75.816 ;
    END
  END tx_flit[112]
  PIN tx_flit[113]
    DIRECTION OUTPUT ;
    USE SIGNAL ;
    PORT
      LAYER M4 ;
        RECT  237.516 76.08 237.6 76.104 ;
    END
  END tx_flit[113]
  PIN tx_flit[114]
    DIRECTION OUTPUT ;
    USE SIGNAL ;
    PORT
      LAYER M4 ;
        RECT  237.516 76.368 237.6 76.392 ;
    END
  END tx_flit[114]
  PIN tx_flit[115]
    DIRECTION OUTPUT ;
    USE SIGNAL ;
    PORT
      LAYER M4 ;
        RECT  237.516 76.656 237.6 76.68 ;
    END
  END tx_flit[115]
  PIN tx_flit[116]
    DIRECTION OUTPUT ;
    USE SIGNAL ;
    PORT
      LAYER M4 ;
        RECT  237.516 76.944 237.6 76.968 ;
    END
  END tx_flit[116]
  PIN tx_flit[117]
    DIRECTION OUTPUT ;
    USE SIGNAL ;
    PORT
      LAYER M4 ;
        RECT  237.516 77.232 237.6 77.256 ;
    END
  END tx_flit[117]
  PIN tx_flit[118]
    DIRECTION OUTPUT ;
    USE SIGNAL ;
    PORT
      LAYER M4 ;
        RECT  237.516 77.52 237.6 77.544 ;
    END
  END tx_flit[118]
  PIN tx_flit[119]
    DIRECTION OUTPUT ;
    USE SIGNAL ;
    PORT
      LAYER M4 ;
        RECT  237.516 77.808 237.6 77.832 ;
    END
  END tx_flit[119]
  PIN tx_flit[11]
    DIRECTION OUTPUT ;
    USE SIGNAL ;
    PORT
      LAYER M4 ;
        RECT  237.516 46.368 237.6 46.392 ;
    END
  END tx_flit[11]
  PIN tx_flit[120]
    DIRECTION OUTPUT ;
    USE SIGNAL ;
    PORT
      LAYER M4 ;
        RECT  237.516 78.096 237.6 78.12 ;
    END
  END tx_flit[120]
  PIN tx_flit[121]
    DIRECTION OUTPUT ;
    USE SIGNAL ;
    PORT
      LAYER M4 ;
        RECT  237.516 78.384 237.6 78.408 ;
    END
  END tx_flit[121]
  PIN tx_flit[122]
    DIRECTION OUTPUT ;
    USE SIGNAL ;
    PORT
      LAYER M4 ;
        RECT  237.516 78.672 237.6 78.696 ;
    END
  END tx_flit[122]
  PIN tx_flit[123]
    DIRECTION OUTPUT ;
    USE SIGNAL ;
    PORT
      LAYER M4 ;
        RECT  237.516 78.96 237.6 78.984 ;
    END
  END tx_flit[123]
  PIN tx_flit[124]
    DIRECTION OUTPUT ;
    USE SIGNAL ;
    PORT
      LAYER M4 ;
        RECT  237.516 79.248 237.6 79.272 ;
    END
  END tx_flit[124]
  PIN tx_flit[125]
    DIRECTION OUTPUT ;
    USE SIGNAL ;
    PORT
      LAYER M4 ;
        RECT  237.516 79.536 237.6 79.56 ;
    END
  END tx_flit[125]
  PIN tx_flit[126]
    DIRECTION OUTPUT ;
    USE SIGNAL ;
    PORT
      LAYER M4 ;
        RECT  237.516 79.824 237.6 79.848 ;
    END
  END tx_flit[126]
  PIN tx_flit[127]
    DIRECTION OUTPUT ;
    USE SIGNAL ;
    PORT
      LAYER M4 ;
        RECT  237.516 80.112 237.6 80.136 ;
    END
  END tx_flit[127]
  PIN tx_flit[128]
    DIRECTION OUTPUT ;
    USE SIGNAL ;
    PORT
      LAYER M4 ;
        RECT  237.516 80.448 237.6 80.472 ;
    END
  END tx_flit[128]
  PIN tx_flit[129]
    DIRECTION OUTPUT ;
    USE SIGNAL ;
    PORT
      LAYER M4 ;
        RECT  237.516 80.736 237.6 80.76 ;
    END
  END tx_flit[129]
  PIN tx_flit[12]
    DIRECTION OUTPUT ;
    USE SIGNAL ;
    PORT
      LAYER M4 ;
        RECT  237.516 46.656 237.6 46.68 ;
    END
  END tx_flit[12]
  PIN tx_flit[130]
    DIRECTION OUTPUT ;
    USE SIGNAL ;
    PORT
      LAYER M4 ;
        RECT  237.516 81.024 237.6 81.048 ;
    END
  END tx_flit[130]
  PIN tx_flit[131]
    DIRECTION OUTPUT ;
    USE SIGNAL ;
    PORT
      LAYER M4 ;
        RECT  237.516 81.312 237.6 81.336 ;
    END
  END tx_flit[131]
  PIN tx_flit[132]
    DIRECTION OUTPUT ;
    USE SIGNAL ;
    PORT
      LAYER M4 ;
        RECT  237.516 81.6 237.6 81.624 ;
    END
  END tx_flit[132]
  PIN tx_flit[133]
    DIRECTION OUTPUT ;
    USE SIGNAL ;
    PORT
      LAYER M4 ;
        RECT  237.516 81.888 237.6 81.912 ;
    END
  END tx_flit[133]
  PIN tx_flit[134]
    DIRECTION OUTPUT ;
    USE SIGNAL ;
    PORT
      LAYER M4 ;
        RECT  237.516 82.176 237.6 82.2 ;
    END
  END tx_flit[134]
  PIN tx_flit[135]
    DIRECTION OUTPUT ;
    USE SIGNAL ;
    PORT
      LAYER M4 ;
        RECT  237.516 82.464 237.6 82.488 ;
    END
  END tx_flit[135]
  PIN tx_flit[136]
    DIRECTION OUTPUT ;
    USE SIGNAL ;
    PORT
      LAYER M4 ;
        RECT  237.516 82.752 237.6 82.776 ;
    END
  END tx_flit[136]
  PIN tx_flit[137]
    DIRECTION OUTPUT ;
    USE SIGNAL ;
    PORT
      LAYER M4 ;
        RECT  237.516 83.04 237.6 83.064 ;
    END
  END tx_flit[137]
  PIN tx_flit[138]
    DIRECTION OUTPUT ;
    USE SIGNAL ;
    PORT
      LAYER M4 ;
        RECT  237.516 83.328 237.6 83.352 ;
    END
  END tx_flit[138]
  PIN tx_flit[139]
    DIRECTION OUTPUT ;
    USE SIGNAL ;
    PORT
      LAYER M4 ;
        RECT  237.516 83.616 237.6 83.64 ;
    END
  END tx_flit[139]
  PIN tx_flit[13]
    DIRECTION OUTPUT ;
    USE SIGNAL ;
    PORT
      LAYER M4 ;
        RECT  237.516 46.992 237.6 47.016 ;
    END
  END tx_flit[13]
  PIN tx_flit[140]
    DIRECTION OUTPUT ;
    USE SIGNAL ;
    PORT
      LAYER M4 ;
        RECT  237.516 83.904 237.6 83.928 ;
    END
  END tx_flit[140]
  PIN tx_flit[141]
    DIRECTION OUTPUT ;
    USE SIGNAL ;
    PORT
      LAYER M4 ;
        RECT  237.516 84.192 237.6 84.216 ;
    END
  END tx_flit[141]
  PIN tx_flit[142]
    DIRECTION OUTPUT ;
    USE SIGNAL ;
    PORT
      LAYER M4 ;
        RECT  237.516 84.48 237.6 84.504 ;
    END
  END tx_flit[142]
  PIN tx_flit[143]
    DIRECTION OUTPUT ;
    USE SIGNAL ;
    PORT
      LAYER M4 ;
        RECT  237.516 84.768 237.6 84.792 ;
    END
  END tx_flit[143]
  PIN tx_flit[144]
    DIRECTION OUTPUT ;
    USE SIGNAL ;
    PORT
      LAYER M4 ;
        RECT  237.516 85.056 237.6 85.08 ;
    END
  END tx_flit[144]
  PIN tx_flit[145]
    DIRECTION OUTPUT ;
    USE SIGNAL ;
    PORT
      LAYER M4 ;
        RECT  237.516 85.392 237.6 85.416 ;
    END
  END tx_flit[145]
  PIN tx_flit[146]
    DIRECTION OUTPUT ;
    USE SIGNAL ;
    PORT
      LAYER M4 ;
        RECT  237.516 85.68 237.6 85.704 ;
    END
  END tx_flit[146]
  PIN tx_flit[14]
    DIRECTION OUTPUT ;
    USE SIGNAL ;
    PORT
      LAYER M4 ;
        RECT  237.516 47.28 237.6 47.304 ;
    END
  END tx_flit[14]
  PIN tx_flit[15]
    DIRECTION OUTPUT ;
    USE SIGNAL ;
    PORT
      LAYER M4 ;
        RECT  237.516 47.568 237.6 47.592 ;
    END
  END tx_flit[15]
  PIN tx_flit[16]
    DIRECTION OUTPUT ;
    USE SIGNAL ;
    PORT
      LAYER M4 ;
        RECT  237.516 47.856 237.6 47.88 ;
    END
  END tx_flit[16]
  PIN tx_flit[17]
    DIRECTION OUTPUT ;
    USE SIGNAL ;
    PORT
      LAYER M4 ;
        RECT  237.516 48.144 237.6 48.168 ;
    END
  END tx_flit[17]
  PIN tx_flit[18]
    DIRECTION OUTPUT ;
    USE SIGNAL ;
    PORT
      LAYER M4 ;
        RECT  237.516 48.432 237.6 48.456 ;
    END
  END tx_flit[18]
  PIN tx_flit[19]
    DIRECTION OUTPUT ;
    USE SIGNAL ;
    PORT
      LAYER M4 ;
        RECT  237.516 48.72 237.6 48.744 ;
    END
  END tx_flit[19]
  PIN tx_flit[1]
    DIRECTION OUTPUT ;
    USE SIGNAL ;
    PORT
      LAYER M4 ;
        RECT  237.516 43.488 237.6 43.512 ;
    END
  END tx_flit[1]
  PIN tx_flit[20]
    DIRECTION OUTPUT ;
    USE SIGNAL ;
    PORT
      LAYER M4 ;
        RECT  237.516 49.008 237.6 49.032 ;
    END
  END tx_flit[20]
  PIN tx_flit[21]
    DIRECTION OUTPUT ;
    USE SIGNAL ;
    PORT
      LAYER M4 ;
        RECT  237.516 49.296 237.6 49.32 ;
    END
  END tx_flit[21]
  PIN tx_flit[22]
    DIRECTION OUTPUT ;
    USE SIGNAL ;
    PORT
      LAYER M4 ;
        RECT  237.516 49.584 237.6 49.608 ;
    END
  END tx_flit[22]
  PIN tx_flit[23]
    DIRECTION OUTPUT ;
    USE SIGNAL ;
    PORT
      LAYER M4 ;
        RECT  237.516 49.872 237.6 49.896 ;
    END
  END tx_flit[23]
  PIN tx_flit[24]
    DIRECTION OUTPUT ;
    USE SIGNAL ;
    PORT
      LAYER M4 ;
        RECT  237.516 50.16 237.6 50.184 ;
    END
  END tx_flit[24]
  PIN tx_flit[25]
    DIRECTION OUTPUT ;
    USE SIGNAL ;
    PORT
      LAYER M4 ;
        RECT  237.516 50.448 237.6 50.472 ;
    END
  END tx_flit[25]
  PIN tx_flit[26]
    DIRECTION OUTPUT ;
    USE SIGNAL ;
    PORT
      LAYER M4 ;
        RECT  237.516 50.736 237.6 50.76 ;
    END
  END tx_flit[26]
  PIN tx_flit[27]
    DIRECTION OUTPUT ;
    USE SIGNAL ;
    PORT
      LAYER M4 ;
        RECT  237.516 51.024 237.6 51.048 ;
    END
  END tx_flit[27]
  PIN tx_flit[28]
    DIRECTION OUTPUT ;
    USE SIGNAL ;
    PORT
      LAYER M4 ;
        RECT  237.516 51.312 237.6 51.336 ;
    END
  END tx_flit[28]
  PIN tx_flit[29]
    DIRECTION OUTPUT ;
    USE SIGNAL ;
    PORT
      LAYER M4 ;
        RECT  237.516 51.648 237.6 51.672 ;
    END
  END tx_flit[29]
  PIN tx_flit[2]
    DIRECTION OUTPUT ;
    USE SIGNAL ;
    PORT
      LAYER M4 ;
        RECT  237.516 43.776 237.6 43.8 ;
    END
  END tx_flit[2]
  PIN tx_flit[30]
    DIRECTION OUTPUT ;
    USE SIGNAL ;
    PORT
      LAYER M4 ;
        RECT  237.516 51.936 237.6 51.96 ;
    END
  END tx_flit[30]
  PIN tx_flit[31]
    DIRECTION OUTPUT ;
    USE SIGNAL ;
    PORT
      LAYER M4 ;
        RECT  237.516 52.224 237.6 52.248 ;
    END
  END tx_flit[31]
  PIN tx_flit[32]
    DIRECTION OUTPUT ;
    USE SIGNAL ;
    PORT
      LAYER M4 ;
        RECT  237.516 52.512 237.6 52.536 ;
    END
  END tx_flit[32]
  PIN tx_flit[33]
    DIRECTION OUTPUT ;
    USE SIGNAL ;
    PORT
      LAYER M4 ;
        RECT  237.516 52.8 237.6 52.824 ;
    END
  END tx_flit[33]
  PIN tx_flit[34]
    DIRECTION OUTPUT ;
    USE SIGNAL ;
    PORT
      LAYER M4 ;
        RECT  237.516 53.088 237.6 53.112 ;
    END
  END tx_flit[34]
  PIN tx_flit[35]
    DIRECTION OUTPUT ;
    USE SIGNAL ;
    PORT
      LAYER M4 ;
        RECT  237.516 53.376 237.6 53.4 ;
    END
  END tx_flit[35]
  PIN tx_flit[36]
    DIRECTION OUTPUT ;
    USE SIGNAL ;
    PORT
      LAYER M4 ;
        RECT  237.516 53.664 237.6 53.688 ;
    END
  END tx_flit[36]
  PIN tx_flit[37]
    DIRECTION OUTPUT ;
    USE SIGNAL ;
    PORT
      LAYER M4 ;
        RECT  237.516 53.952 237.6 53.976 ;
    END
  END tx_flit[37]
  PIN tx_flit[38]
    DIRECTION OUTPUT ;
    USE SIGNAL ;
    PORT
      LAYER M4 ;
        RECT  237.516 54.24 237.6 54.264 ;
    END
  END tx_flit[38]
  PIN tx_flit[39]
    DIRECTION OUTPUT ;
    USE SIGNAL ;
    PORT
      LAYER M4 ;
        RECT  237.516 54.528 237.6 54.552 ;
    END
  END tx_flit[39]
  PIN tx_flit[3]
    DIRECTION OUTPUT ;
    USE SIGNAL ;
    PORT
      LAYER M4 ;
        RECT  237.516 44.064 237.6 44.088 ;
    END
  END tx_flit[3]
  PIN tx_flit[40]
    DIRECTION OUTPUT ;
    USE SIGNAL ;
    PORT
      LAYER M4 ;
        RECT  237.516 54.816 237.6 54.84 ;
    END
  END tx_flit[40]
  PIN tx_flit[41]
    DIRECTION OUTPUT ;
    USE SIGNAL ;
    PORT
      LAYER M4 ;
        RECT  237.516 55.104 237.6 55.128 ;
    END
  END tx_flit[41]
  PIN tx_flit[42]
    DIRECTION OUTPUT ;
    USE SIGNAL ;
    PORT
      LAYER M4 ;
        RECT  237.516 55.392 237.6 55.416 ;
    END
  END tx_flit[42]
  PIN tx_flit[43]
    DIRECTION OUTPUT ;
    USE SIGNAL ;
    PORT
      LAYER M4 ;
        RECT  237.516 55.68 237.6 55.704 ;
    END
  END tx_flit[43]
  PIN tx_flit[44]
    DIRECTION OUTPUT ;
    USE SIGNAL ;
    PORT
      LAYER M4 ;
        RECT  237.516 55.968 237.6 55.992 ;
    END
  END tx_flit[44]
  PIN tx_flit[45]
    DIRECTION OUTPUT ;
    USE SIGNAL ;
    PORT
      LAYER M4 ;
        RECT  237.516 56.256 237.6 56.28 ;
    END
  END tx_flit[45]
  PIN tx_flit[46]
    DIRECTION OUTPUT ;
    USE SIGNAL ;
    PORT
      LAYER M4 ;
        RECT  237.516 56.592 237.6 56.616 ;
    END
  END tx_flit[46]
  PIN tx_flit[47]
    DIRECTION OUTPUT ;
    USE SIGNAL ;
    PORT
      LAYER M4 ;
        RECT  237.516 56.88 237.6 56.904 ;
    END
  END tx_flit[47]
  PIN tx_flit[48]
    DIRECTION OUTPUT ;
    USE SIGNAL ;
    PORT
      LAYER M4 ;
        RECT  237.516 57.168 237.6 57.192 ;
    END
  END tx_flit[48]
  PIN tx_flit[49]
    DIRECTION OUTPUT ;
    USE SIGNAL ;
    PORT
      LAYER M4 ;
        RECT  237.516 57.456 237.6 57.48 ;
    END
  END tx_flit[49]
  PIN tx_flit[4]
    DIRECTION OUTPUT ;
    USE SIGNAL ;
    PORT
      LAYER M4 ;
        RECT  237.516 44.352 237.6 44.376 ;
    END
  END tx_flit[4]
  PIN tx_flit[50]
    DIRECTION OUTPUT ;
    USE SIGNAL ;
    PORT
      LAYER M4 ;
        RECT  237.516 57.744 237.6 57.768 ;
    END
  END tx_flit[50]
  PIN tx_flit[51]
    DIRECTION OUTPUT ;
    USE SIGNAL ;
    PORT
      LAYER M4 ;
        RECT  237.516 58.032 237.6 58.056 ;
    END
  END tx_flit[51]
  PIN tx_flit[52]
    DIRECTION OUTPUT ;
    USE SIGNAL ;
    PORT
      LAYER M4 ;
        RECT  237.516 58.32 237.6 58.344 ;
    END
  END tx_flit[52]
  PIN tx_flit[53]
    DIRECTION OUTPUT ;
    USE SIGNAL ;
    PORT
      LAYER M4 ;
        RECT  237.516 58.608 237.6 58.632 ;
    END
  END tx_flit[53]
  PIN tx_flit[54]
    DIRECTION OUTPUT ;
    USE SIGNAL ;
    PORT
      LAYER M4 ;
        RECT  237.516 58.896 237.6 58.92 ;
    END
  END tx_flit[54]
  PIN tx_flit[55]
    DIRECTION OUTPUT ;
    USE SIGNAL ;
    PORT
      LAYER M4 ;
        RECT  237.516 59.184 237.6 59.208 ;
    END
  END tx_flit[55]
  PIN tx_flit[56]
    DIRECTION OUTPUT ;
    USE SIGNAL ;
    PORT
      LAYER M4 ;
        RECT  237.516 59.472 237.6 59.496 ;
    END
  END tx_flit[56]
  PIN tx_flit[57]
    DIRECTION OUTPUT ;
    USE SIGNAL ;
    PORT
      LAYER M4 ;
        RECT  237.516 59.76 237.6 59.784 ;
    END
  END tx_flit[57]
  PIN tx_flit[58]
    DIRECTION OUTPUT ;
    USE SIGNAL ;
    PORT
      LAYER M4 ;
        RECT  237.516 60.048 237.6 60.072 ;
    END
  END tx_flit[58]
  PIN tx_flit[59]
    DIRECTION OUTPUT ;
    USE SIGNAL ;
    PORT
      LAYER M4 ;
        RECT  237.516 60.336 237.6 60.36 ;
    END
  END tx_flit[59]
  PIN tx_flit[5]
    DIRECTION OUTPUT ;
    USE SIGNAL ;
    PORT
      LAYER M4 ;
        RECT  237.516 44.64 237.6 44.664 ;
    END
  END tx_flit[5]
  PIN tx_flit[60]
    DIRECTION OUTPUT ;
    USE SIGNAL ;
    PORT
      LAYER M4 ;
        RECT  237.516 60.624 237.6 60.648 ;
    END
  END tx_flit[60]
  PIN tx_flit[61]
    DIRECTION OUTPUT ;
    USE SIGNAL ;
    PORT
      LAYER M4 ;
        RECT  237.516 60.912 237.6 60.936 ;
    END
  END tx_flit[61]
  PIN tx_flit[62]
    DIRECTION OUTPUT ;
    USE SIGNAL ;
    PORT
      LAYER M4 ;
        RECT  237.516 61.248 237.6 61.272 ;
    END
  END tx_flit[62]
  PIN tx_flit[63]
    DIRECTION OUTPUT ;
    USE SIGNAL ;
    PORT
      LAYER M4 ;
        RECT  237.516 61.536 237.6 61.56 ;
    END
  END tx_flit[63]
  PIN tx_flit[64]
    DIRECTION OUTPUT ;
    USE SIGNAL ;
    PORT
      LAYER M4 ;
        RECT  237.516 61.824 237.6 61.848 ;
    END
  END tx_flit[64]
  PIN tx_flit[65]
    DIRECTION OUTPUT ;
    USE SIGNAL ;
    PORT
      LAYER M4 ;
        RECT  237.516 62.112 237.6 62.136 ;
    END
  END tx_flit[65]
  PIN tx_flit[66]
    DIRECTION OUTPUT ;
    USE SIGNAL ;
    PORT
      LAYER M4 ;
        RECT  237.516 62.4 237.6 62.424 ;
    END
  END tx_flit[66]
  PIN tx_flit[67]
    DIRECTION OUTPUT ;
    USE SIGNAL ;
    PORT
      LAYER M4 ;
        RECT  237.516 62.688 237.6 62.712 ;
    END
  END tx_flit[67]
  PIN tx_flit[68]
    DIRECTION OUTPUT ;
    USE SIGNAL ;
    PORT
      LAYER M4 ;
        RECT  237.516 62.976 237.6 63 ;
    END
  END tx_flit[68]
  PIN tx_flit[69]
    DIRECTION OUTPUT ;
    USE SIGNAL ;
    PORT
      LAYER M4 ;
        RECT  237.516 63.264 237.6 63.288 ;
    END
  END tx_flit[69]
  PIN tx_flit[6]
    DIRECTION OUTPUT ;
    USE SIGNAL ;
    PORT
      LAYER M4 ;
        RECT  237.516 44.928 237.6 44.952 ;
    END
  END tx_flit[6]
  PIN tx_flit[70]
    DIRECTION OUTPUT ;
    USE SIGNAL ;
    PORT
      LAYER M4 ;
        RECT  237.516 63.552 237.6 63.576 ;
    END
  END tx_flit[70]
  PIN tx_flit[71]
    DIRECTION OUTPUT ;
    USE SIGNAL ;
    PORT
      LAYER M4 ;
        RECT  237.516 63.84 237.6 63.864 ;
    END
  END tx_flit[71]
  PIN tx_flit[72]
    DIRECTION OUTPUT ;
    USE SIGNAL ;
    PORT
      LAYER M4 ;
        RECT  237.516 64.128 237.6 64.152 ;
    END
  END tx_flit[72]
  PIN tx_flit[73]
    DIRECTION OUTPUT ;
    USE SIGNAL ;
    PORT
      LAYER M4 ;
        RECT  237.516 64.416 237.6 64.44 ;
    END
  END tx_flit[73]
  PIN tx_flit[74]
    DIRECTION OUTPUT ;
    USE SIGNAL ;
    PORT
      LAYER M4 ;
        RECT  237.516 64.704 237.6 64.728 ;
    END
  END tx_flit[74]
  PIN tx_flit[75]
    DIRECTION OUTPUT ;
    USE SIGNAL ;
    PORT
      LAYER M4 ;
        RECT  237.516 64.992 237.6 65.016 ;
    END
  END tx_flit[75]
  PIN tx_flit[76]
    DIRECTION OUTPUT ;
    USE SIGNAL ;
    PORT
      LAYER M4 ;
        RECT  237.516 65.28 237.6 65.304 ;
    END
  END tx_flit[76]
  PIN tx_flit[77]
    DIRECTION OUTPUT ;
    USE SIGNAL ;
    PORT
      LAYER M4 ;
        RECT  237.516 65.568 237.6 65.592 ;
    END
  END tx_flit[77]
  PIN tx_flit[78]
    DIRECTION OUTPUT ;
    USE SIGNAL ;
    PORT
      LAYER M4 ;
        RECT  237.516 65.856 237.6 65.88 ;
    END
  END tx_flit[78]
  PIN tx_flit[79]
    DIRECTION OUTPUT ;
    USE SIGNAL ;
    PORT
      LAYER M4 ;
        RECT  237.516 66.192 237.6 66.216 ;
    END
  END tx_flit[79]
  PIN tx_flit[7]
    DIRECTION OUTPUT ;
    USE SIGNAL ;
    PORT
      LAYER M4 ;
        RECT  237.516 45.216 237.6 45.24 ;
    END
  END tx_flit[7]
  PIN tx_flit[80]
    DIRECTION OUTPUT ;
    USE SIGNAL ;
    PORT
      LAYER M4 ;
        RECT  237.516 66.48 237.6 66.504 ;
    END
  END tx_flit[80]
  PIN tx_flit[81]
    DIRECTION OUTPUT ;
    USE SIGNAL ;
    PORT
      LAYER M4 ;
        RECT  237.516 66.768 237.6 66.792 ;
    END
  END tx_flit[81]
  PIN tx_flit[82]
    DIRECTION OUTPUT ;
    USE SIGNAL ;
    PORT
      LAYER M4 ;
        RECT  237.516 67.056 237.6 67.08 ;
    END
  END tx_flit[82]
  PIN tx_flit[83]
    DIRECTION OUTPUT ;
    USE SIGNAL ;
    PORT
      LAYER M4 ;
        RECT  237.516 67.344 237.6 67.368 ;
    END
  END tx_flit[83]
  PIN tx_flit[84]
    DIRECTION OUTPUT ;
    USE SIGNAL ;
    PORT
      LAYER M4 ;
        RECT  237.516 67.632 237.6 67.656 ;
    END
  END tx_flit[84]
  PIN tx_flit[85]
    DIRECTION OUTPUT ;
    USE SIGNAL ;
    PORT
      LAYER M4 ;
        RECT  237.516 67.92 237.6 67.944 ;
    END
  END tx_flit[85]
  PIN tx_flit[86]
    DIRECTION OUTPUT ;
    USE SIGNAL ;
    PORT
      LAYER M4 ;
        RECT  237.516 68.208 237.6 68.232 ;
    END
  END tx_flit[86]
  PIN tx_flit[87]
    DIRECTION OUTPUT ;
    USE SIGNAL ;
    PORT
      LAYER M4 ;
        RECT  237.516 68.496 237.6 68.52 ;
    END
  END tx_flit[87]
  PIN tx_flit[88]
    DIRECTION OUTPUT ;
    USE SIGNAL ;
    PORT
      LAYER M4 ;
        RECT  237.516 68.784 237.6 68.808 ;
    END
  END tx_flit[88]
  PIN tx_flit[89]
    DIRECTION OUTPUT ;
    USE SIGNAL ;
    PORT
      LAYER M4 ;
        RECT  237.516 69.072 237.6 69.096 ;
    END
  END tx_flit[89]
  PIN tx_flit[8]
    DIRECTION OUTPUT ;
    USE SIGNAL ;
    PORT
      LAYER M4 ;
        RECT  237.516 45.504 237.6 45.528 ;
    END
  END tx_flit[8]
  PIN tx_flit[90]
    DIRECTION OUTPUT ;
    USE SIGNAL ;
    PORT
      LAYER M4 ;
        RECT  237.516 69.36 237.6 69.384 ;
    END
  END tx_flit[90]
  PIN tx_flit[91]
    DIRECTION OUTPUT ;
    USE SIGNAL ;
    PORT
      LAYER M4 ;
        RECT  237.516 69.648 237.6 69.672 ;
    END
  END tx_flit[91]
  PIN tx_flit[92]
    DIRECTION OUTPUT ;
    USE SIGNAL ;
    PORT
      LAYER M4 ;
        RECT  237.516 69.936 237.6 69.96 ;
    END
  END tx_flit[92]
  PIN tx_flit[93]
    DIRECTION OUTPUT ;
    USE SIGNAL ;
    PORT
      LAYER M4 ;
        RECT  237.516 70.224 237.6 70.248 ;
    END
  END tx_flit[93]
  PIN tx_flit[94]
    DIRECTION OUTPUT ;
    USE SIGNAL ;
    PORT
      LAYER M4 ;
        RECT  237.516 70.512 237.6 70.536 ;
    END
  END tx_flit[94]
  PIN tx_flit[95]
    DIRECTION OUTPUT ;
    USE SIGNAL ;
    PORT
      LAYER M4 ;
        RECT  237.516 70.848 237.6 70.872 ;
    END
  END tx_flit[95]
  PIN tx_flit[96]
    DIRECTION OUTPUT ;
    USE SIGNAL ;
    PORT
      LAYER M4 ;
        RECT  237.516 71.136 237.6 71.16 ;
    END
  END tx_flit[96]
  PIN tx_flit[97]
    DIRECTION OUTPUT ;
    USE SIGNAL ;
    PORT
      LAYER M4 ;
        RECT  237.516 71.424 237.6 71.448 ;
    END
  END tx_flit[97]
  PIN tx_flit[98]
    DIRECTION OUTPUT ;
    USE SIGNAL ;
    PORT
      LAYER M4 ;
        RECT  237.516 71.712 237.6 71.736 ;
    END
  END tx_flit[98]
  PIN tx_flit[99]
    DIRECTION OUTPUT ;
    USE SIGNAL ;
    PORT
      LAYER M4 ;
        RECT  237.516 72 237.6 72.024 ;
    END
  END tx_flit[99]
  PIN tx_flit[9]
    DIRECTION OUTPUT ;
    USE SIGNAL ;
    PORT
      LAYER M4 ;
        RECT  237.516 45.792 237.6 45.816 ;
    END
  END tx_flit[9]
  PIN tx_up
    DIRECTION INPUT ;
    USE SIGNAL ;
    PORT
      LAYER M4 ;
        RECT  237.516 85.968 237.6 85.992 ;
    END
  END tx_up
  PIN tx_v
    DIRECTION OUTPUT ;
    USE SIGNAL ;
    PORT
      LAYER M4 ;
        RECT  237.516 86.256 237.6 86.28 ;
    END
  END tx_v
  PIN VDD
    DIRECTION INOUT ;
    USE POWER ;
    PORT
      LAYER M5 ;
        RECT  234.792 2.151 234.912 84.249 ;
        RECT  229.392 2.151 229.512 84.249 ;
        RECT  223.992 2.151 224.112 84.249 ;
        RECT  218.592 2.151 218.712 84.249 ;
        RECT  213.192 2.151 213.312 84.249 ;
        RECT  207.792 2.151 207.912 84.249 ;
        RECT  202.392 2.151 202.512 84.249 ;
        RECT  196.992 2.151 197.112 84.249 ;
        RECT  191.592 2.151 191.712 84.249 ;
        RECT  186.192 2.151 186.312 84.249 ;
        RECT  180.792 2.151 180.912 84.249 ;
        RECT  175.392 2.151 175.512 84.249 ;
        RECT  169.992 2.151 170.112 84.249 ;
        RECT  164.592 2.151 164.712 84.249 ;
        RECT  159.192 2.151 159.312 84.249 ;
        RECT  153.792 2.151 153.912 84.249 ;
        RECT  148.392 2.151 148.512 84.249 ;
        RECT  142.992 2.151 143.112 84.249 ;
        RECT  137.592 2.151 137.712 84.249 ;
        RECT  132.192 2.151 132.312 84.249 ;
        RECT  126.792 2.151 126.912 84.249 ;
        RECT  121.392 2.151 121.512 84.249 ;
        RECT  115.992 2.151 116.112 84.249 ;
        RECT  110.592 2.151 110.712 84.249 ;
        RECT  105.192 2.151 105.312 84.249 ;
        RECT  99.792 2.151 99.912 84.249 ;
        RECT  94.392 2.151 94.512 84.249 ;
        RECT  88.992 2.151 89.112 84.249 ;
        RECT  83.592 2.151 83.712 84.249 ;
        RECT  78.192 2.151 78.312 84.249 ;
        RECT  72.792 2.151 72.912 84.249 ;
        RECT  67.392 2.151 67.512 84.249 ;
        RECT  61.992 2.151 62.112 84.249 ;
        RECT  56.592 2.151 56.712 84.249 ;
        RECT  51.192 2.151 51.312 84.249 ;
        RECT  45.792 2.151 45.912 84.249 ;
        RECT  40.392 2.151 40.512 84.249 ;
        RECT  34.992 2.151 35.112 84.249 ;
        RECT  29.592 2.151 29.712 84.249 ;
        RECT  24.192 2.151 24.312 84.249 ;
        RECT  18.792 2.151 18.912 84.249 ;
        RECT  13.392 2.151 13.512 84.249 ;
        RECT  7.992 2.151 8.112 84.249 ;
        RECT  2.592 2.151 2.712 84.249 ;
    END
  END VDD
  PIN VSS
    DIRECTION INOUT ;
    USE GROUND ;
    PORT
      LAYER M5 ;
        RECT  234.6 2.137 234.72 84.263 ;
        RECT  229.2 2.137 229.32 84.263 ;
        RECT  223.8 2.137 223.92 84.263 ;
        RECT  218.4 2.137 218.52 84.263 ;
        RECT  213 2.137 213.12 84.263 ;
        RECT  207.6 2.137 207.72 84.263 ;
        RECT  202.2 2.137 202.32 84.263 ;
        RECT  196.8 2.137 196.92 84.263 ;
        RECT  191.4 2.137 191.52 84.263 ;
        RECT  186 2.137 186.12 84.263 ;
        RECT  180.6 2.137 180.72 84.263 ;
        RECT  175.2 2.137 175.32 84.263 ;
        RECT  169.8 2.137 169.92 84.263 ;
        RECT  164.4 2.137 164.52 84.263 ;
        RECT  159 2.137 159.12 84.263 ;
        RECT  153.6 2.137 153.72 84.263 ;
        RECT  148.2 2.137 148.32 84.263 ;
        RECT  142.8 2.137 142.92 84.263 ;
        RECT  137.4 2.137 137.52 84.263 ;
        RECT  132 2.137 132.12 84.263 ;
        RECT  126.6 2.137 126.72 84.263 ;
        RECT  121.2 2.137 121.32 84.263 ;
        RECT  115.8 2.137 115.92 84.263 ;
        RECT  110.4 2.137 110.52 84.263 ;
        RECT  105 2.137 105.12 84.263 ;
        RECT  99.6 2.137 99.72 84.263 ;
        RECT  94.2 2.137 94.32 84.263 ;
        RECT  88.8 2.137 88.92 84.263 ;
        RECT  83.4 2.137 83.52 84.263 ;
        RECT  78 2.137 78.12 84.263 ;
        RECT  72.6 2.137 72.72 84.263 ;
        RECT  67.2 2.137 67.32 84.263 ;
        RECT  61.8 2.137 61.92 84.263 ;
        RECT  56.4 2.137 56.52 84.263 ;
        RECT  51 2.137 51.12 84.263 ;
        RECT  45.6 2.137 45.72 84.263 ;
        RECT  40.2 2.137 40.32 84.263 ;
        RECT  34.8 2.137 34.92 84.263 ;
        RECT  29.4 2.137 29.52 84.263 ;
        RECT  24 2.137 24.12 84.263 ;
        RECT  18.6 2.137 18.72 84.263 ;
        RECT  13.2 2.137 13.32 84.263 ;
        RECT  7.8 2.137 7.92 84.263 ;
        RECT  2.4 2.137 2.52 84.263 ;
    END
  END VSS
  # OT_OBS_CLOSED layer=M5 d_um=1.536 added=412
  OBS
    LAYER RVTN ;
     RECT  2.16 2.16 235.44 2.295 ;
     RECT  2.16 2.565 235.44 2.835 ;
     RECT  2.16 3.105 235.44 3.375 ;
     RECT  2.16 3.645 235.44 3.915 ;
     RECT  2.16 4.185 235.44 4.455 ;
     RECT  2.16 4.725 235.44 4.995 ;
     RECT  2.16 5.265 235.44 5.535 ;
     RECT  2.16 5.805 235.44 6.075 ;
     RECT  2.16 6.345 235.44 6.615 ;
     RECT  2.16 6.885 235.44 7.155 ;
     RECT  2.16 7.425 235.44 7.695 ;
     RECT  2.16 7.965 235.44 8.235 ;
     RECT  2.16 8.505 235.44 8.775 ;
     RECT  2.16 9.045 235.44 9.315 ;
     RECT  2.16 9.585 235.44 9.855 ;
     RECT  2.16 10.125 235.44 10.395 ;
     RECT  2.16 10.665 235.44 10.935 ;
     RECT  2.16 11.205 235.44 11.475 ;
     RECT  2.16 11.745 235.44 12.015 ;
     RECT  2.16 12.285 235.44 12.555 ;
     RECT  2.16 12.825 235.44 13.095 ;
     RECT  2.16 13.365 235.44 13.635 ;
     RECT  2.16 13.905 235.44 14.175 ;
     RECT  2.16 14.445 235.44 14.715 ;
     RECT  2.16 14.985 235.44 15.255 ;
     RECT  2.16 15.525 235.44 15.795 ;
     RECT  2.16 16.065 235.44 16.335 ;
     RECT  2.16 16.605 235.44 16.875 ;
     RECT  2.16 17.145 235.44 17.415 ;
     RECT  2.16 17.685 235.44 17.955 ;
     RECT  2.16 18.225 235.44 18.495 ;
     RECT  2.16 18.765 235.44 19.035 ;
     RECT  2.16 19.305 235.44 19.575 ;
     RECT  2.16 19.845 235.44 20.115 ;
     RECT  2.16 20.385 235.44 20.655 ;
     RECT  2.16 20.925 235.44 21.195 ;
     RECT  2.16 21.465 235.44 21.735 ;
     RECT  2.16 22.005 235.44 22.275 ;
     RECT  2.16 22.545 235.44 22.815 ;
     RECT  2.16 23.085 235.44 23.355 ;
     RECT  2.16 23.625 235.44 23.895 ;
     RECT  2.16 24.165 235.44 24.435 ;
     RECT  2.16 24.705 235.44 24.975 ;
     RECT  2.16 25.245 235.44 25.515 ;
     RECT  2.16 25.785 235.44 25.92 ;
     RECT  2.16 25.92 29.484 26.055 ;
     RECT  207.684 25.92 235.44 26.055 ;
     RECT  2.16 26.325 29.484 26.595 ;
     RECT  207.684 26.325 235.44 26.595 ;
     RECT  2.16 26.865 29.484 27.135 ;
     RECT  207.684 26.865 235.44 27.135 ;
     RECT  2.16 27.405 29.484 27.675 ;
     RECT  207.684 27.405 235.44 27.675 ;
     RECT  2.16 27.945 29.484 28.215 ;
     RECT  207.684 27.945 235.44 28.215 ;
     RECT  2.16 28.485 29.484 28.755 ;
     RECT  207.684 28.485 235.44 28.755 ;
     RECT  2.16 29.025 29.484 29.295 ;
     RECT  207.684 29.025 235.44 29.295 ;
     RECT  2.16 29.565 29.484 29.835 ;
     RECT  207.684 29.565 235.44 29.835 ;
     RECT  2.16 30.105 29.484 30.375 ;
     RECT  207.684 30.105 235.44 30.375 ;
     RECT  2.16 30.645 29.484 30.915 ;
     RECT  207.684 30.645 235.44 30.915 ;
     RECT  2.16 31.185 29.484 31.455 ;
     RECT  207.684 31.185 235.44 31.455 ;
     RECT  2.16 31.725 29.484 31.995 ;
     RECT  207.684 31.725 235.44 31.995 ;
     RECT  2.16 32.265 29.484 32.535 ;
     RECT  207.684 32.265 235.44 32.535 ;
     RECT  2.16 32.805 29.484 33.075 ;
     RECT  207.684 32.805 235.44 33.075 ;
     RECT  2.16 33.345 29.484 33.615 ;
     RECT  207.684 33.345 235.44 33.615 ;
     RECT  2.16 33.885 29.484 34.155 ;
     RECT  207.684 33.885 235.44 34.155 ;
     RECT  2.16 34.425 29.484 34.695 ;
     RECT  207.684 34.425 235.44 34.695 ;
     RECT  2.16 34.965 29.484 35.235 ;
     RECT  207.684 34.965 235.44 35.235 ;
     RECT  2.16 35.505 29.484 35.775 ;
     RECT  207.684 35.505 235.44 35.775 ;
     RECT  2.16 36.045 29.484 36.315 ;
     RECT  207.684 36.045 235.44 36.315 ;
     RECT  2.16 36.585 29.484 36.855 ;
     RECT  207.684 36.585 235.44 36.855 ;
     RECT  2.16 37.125 29.484 37.395 ;
     RECT  207.684 37.125 235.44 37.395 ;
     RECT  2.16 37.665 29.484 37.935 ;
     RECT  207.684 37.665 235.44 37.935 ;
     RECT  2.16 38.205 29.484 38.475 ;
     RECT  207.684 38.205 235.44 38.475 ;
     RECT  2.16 38.745 29.484 39.015 ;
     RECT  207.684 38.745 235.44 39.015 ;
     RECT  2.16 39.285 29.484 39.555 ;
     RECT  207.684 39.285 235.44 39.555 ;
     RECT  2.16 39.825 29.484 40.095 ;
     RECT  207.684 39.825 235.44 40.095 ;
     RECT  2.16 40.365 29.484 40.635 ;
     RECT  207.684 40.365 235.44 40.635 ;
     RECT  2.16 40.905 29.484 41.175 ;
     RECT  207.684 40.905 235.44 41.175 ;
     RECT  2.16 41.445 29.484 41.715 ;
     RECT  207.684 41.445 235.44 41.715 ;
     RECT  2.16 41.985 29.484 42.255 ;
     RECT  207.684 41.985 235.44 42.255 ;
     RECT  2.16 42.525 29.484 42.795 ;
     RECT  207.684 42.525 235.44 42.795 ;
     RECT  2.16 43.065 29.484 43.335 ;
     RECT  207.684 43.065 235.44 43.335 ;
     RECT  2.16 43.605 29.484 43.875 ;
     RECT  207.684 43.605 235.44 43.875 ;
     RECT  2.16 44.145 29.484 44.415 ;
     RECT  207.684 44.145 235.44 44.415 ;
     RECT  2.16 44.685 29.484 44.955 ;
     RECT  207.684 44.685 235.44 44.955 ;
     RECT  2.16 45.225 29.484 45.495 ;
     RECT  207.684 45.225 235.44 45.495 ;
     RECT  2.16 45.765 29.484 46.035 ;
     RECT  207.684 45.765 235.44 46.035 ;
     RECT  2.16 46.305 29.484 46.575 ;
     RECT  207.684 46.305 235.44 46.575 ;
     RECT  2.16 46.845 29.484 47.115 ;
     RECT  207.684 46.845 235.44 47.115 ;
     RECT  2.16 47.385 29.484 47.655 ;
     RECT  207.684 47.385 235.44 47.655 ;
     RECT  2.16 47.925 29.484 48.195 ;
     RECT  207.684 47.925 235.44 48.195 ;
     RECT  2.16 48.465 29.484 48.735 ;
     RECT  207.684 48.465 235.44 48.735 ;
     RECT  2.16 49.005 29.484 49.275 ;
     RECT  207.684 49.005 235.44 49.275 ;
     RECT  2.16 49.545 29.484 49.815 ;
     RECT  207.684 49.545 235.44 49.815 ;
     RECT  2.16 50.085 29.484 50.355 ;
     RECT  207.684 50.085 235.44 50.355 ;
     RECT  2.16 50.625 29.484 50.895 ;
     RECT  207.684 50.625 235.44 50.895 ;
     RECT  2.16 51.165 29.484 51.435 ;
     RECT  207.684 51.165 235.44 51.435 ;
     RECT  2.16 51.705 29.484 51.975 ;
     RECT  207.684 51.705 235.44 51.975 ;
     RECT  2.16 52.245 29.484 52.515 ;
     RECT  207.684 52.245 235.44 52.515 ;
     RECT  2.16 52.785 29.484 53.055 ;
     RECT  207.684 52.785 235.44 53.055 ;
     RECT  2.16 53.325 29.484 53.595 ;
     RECT  207.684 53.325 235.44 53.595 ;
     RECT  2.16 53.865 29.484 54.135 ;
     RECT  207.684 53.865 235.44 54.135 ;
     RECT  2.16 54.405 29.484 54.675 ;
     RECT  207.684 54.405 235.44 54.675 ;
     RECT  2.16 54.945 29.484 55.215 ;
     RECT  207.684 54.945 235.44 55.215 ;
     RECT  2.16 55.485 29.484 55.755 ;
     RECT  207.684 55.485 235.44 55.755 ;
     RECT  2.16 56.025 29.484 56.295 ;
     RECT  207.684 56.025 235.44 56.295 ;
     RECT  2.16 56.565 29.484 56.835 ;
     RECT  207.684 56.565 235.44 56.835 ;
     RECT  2.16 57.105 29.484 57.375 ;
     RECT  207.684 57.105 235.44 57.375 ;
     RECT  2.16 57.645 29.484 57.915 ;
     RECT  207.684 57.645 235.44 57.915 ;
     RECT  2.16 58.185 29.484 58.455 ;
     RECT  207.684 58.185 235.44 58.455 ;
     RECT  2.16 58.725 29.484 58.995 ;
     RECT  207.684 58.725 235.44 58.995 ;
     RECT  2.16 59.265 29.484 59.535 ;
     RECT  207.684 59.265 235.44 59.535 ;
     RECT  2.16 59.805 29.484 59.94 ;
     RECT  207.684 59.805 235.44 59.94 ;
     RECT  2.16 59.94 235.44 60.075 ;
     RECT  2.16 60.345 235.44 60.615 ;
     RECT  2.16 60.885 235.44 61.155 ;
     RECT  2.16 61.425 235.44 61.695 ;
     RECT  2.16 61.965 235.44 62.235 ;
     RECT  2.16 62.505 235.44 62.775 ;
     RECT  2.16 63.045 235.44 63.315 ;
     RECT  2.16 63.585 235.44 63.855 ;
     RECT  2.16 64.125 235.44 64.395 ;
     RECT  2.16 64.665 235.44 64.935 ;
     RECT  2.16 65.205 235.44 65.475 ;
     RECT  2.16 65.745 235.44 66.015 ;
     RECT  2.16 66.285 235.44 66.555 ;
     RECT  2.16 66.825 235.44 67.095 ;
     RECT  2.16 67.365 235.44 67.635 ;
     RECT  2.16 67.905 235.44 68.175 ;
     RECT  2.16 68.445 235.44 68.715 ;
     RECT  2.16 68.985 235.44 69.255 ;
     RECT  2.16 69.525 235.44 69.795 ;
     RECT  2.16 70.065 235.44 70.335 ;
     RECT  2.16 70.605 235.44 70.875 ;
     RECT  2.16 71.145 235.44 71.415 ;
     RECT  2.16 71.685 235.44 71.955 ;
     RECT  2.16 72.225 235.44 72.495 ;
     RECT  2.16 72.765 235.44 73.035 ;
     RECT  2.16 73.305 235.44 73.575 ;
     RECT  2.16 73.845 235.44 74.115 ;
     RECT  2.16 74.385 235.44 74.655 ;
     RECT  2.16 74.925 235.44 75.195 ;
     RECT  2.16 75.465 235.44 75.735 ;
     RECT  2.16 76.005 235.44 76.275 ;
     RECT  2.16 76.545 235.44 76.815 ;
     RECT  2.16 77.085 235.44 77.355 ;
     RECT  2.16 77.625 235.44 77.895 ;
     RECT  2.16 78.165 235.44 78.435 ;
     RECT  2.16 78.705 235.44 78.975 ;
     RECT  2.16 79.245 235.44 79.515 ;
     RECT  2.16 79.785 235.44 80.055 ;
     RECT  2.16 80.325 235.44 80.595 ;
     RECT  2.16 80.865 235.44 81.135 ;
     RECT  2.16 81.405 235.44 81.675 ;
     RECT  2.16 81.945 235.44 82.215 ;
     RECT  2.16 82.485 235.44 82.755 ;
     RECT  2.16 83.025 235.44 83.295 ;
     RECT  2.16 83.565 235.44 83.835 ;
     RECT  2.16 84.105 235.44 84.24 ;
    LAYER RVTP ;
     RECT  2.16 2.295 235.44 2.565 ;
     RECT  2.16 2.835 235.44 3.105 ;
     RECT  2.16 3.375 235.44 3.645 ;
     RECT  2.16 3.915 235.44 4.185 ;
     RECT  2.16 4.455 235.44 4.725 ;
     RECT  2.16 4.995 235.44 5.265 ;
     RECT  2.16 5.535 235.44 5.805 ;
     RECT  2.16 6.075 235.44 6.345 ;
     RECT  2.16 6.615 235.44 6.885 ;
     RECT  2.16 7.155 235.44 7.425 ;
     RECT  2.16 7.695 235.44 7.965 ;
     RECT  2.16 8.235 235.44 8.505 ;
     RECT  2.16 8.775 235.44 9.045 ;
     RECT  2.16 9.315 235.44 9.585 ;
     RECT  2.16 9.855 235.44 10.125 ;
     RECT  2.16 10.395 235.44 10.665 ;
     RECT  2.16 10.935 235.44 11.205 ;
     RECT  2.16 11.475 235.44 11.745 ;
     RECT  2.16 12.015 235.44 12.285 ;
     RECT  2.16 12.555 235.44 12.825 ;
     RECT  2.16 13.095 235.44 13.365 ;
     RECT  2.16 13.635 235.44 13.905 ;
     RECT  2.16 14.175 235.44 14.445 ;
     RECT  2.16 14.715 235.44 14.985 ;
     RECT  2.16 15.255 235.44 15.525 ;
     RECT  2.16 15.795 235.44 16.065 ;
     RECT  2.16 16.335 235.44 16.605 ;
     RECT  2.16 16.875 235.44 17.145 ;
     RECT  2.16 17.415 235.44 17.685 ;
     RECT  2.16 17.955 235.44 18.225 ;
     RECT  2.16 18.495 235.44 18.765 ;
     RECT  2.16 19.035 235.44 19.305 ;
     RECT  2.16 19.575 235.44 19.845 ;
     RECT  2.16 20.115 235.44 20.385 ;
     RECT  2.16 20.655 235.44 20.925 ;
     RECT  2.16 21.195 235.44 21.465 ;
     RECT  2.16 21.735 235.44 22.005 ;
     RECT  2.16 22.275 235.44 22.545 ;
     RECT  2.16 22.815 235.44 23.085 ;
     RECT  2.16 23.355 235.44 23.625 ;
     RECT  2.16 23.895 235.44 24.165 ;
     RECT  2.16 24.435 235.44 24.705 ;
     RECT  2.16 24.975 235.44 25.245 ;
     RECT  2.16 25.515 235.44 25.785 ;
     RECT  2.16 26.055 29.484 26.325 ;
     RECT  207.684 26.055 235.44 26.325 ;
     RECT  2.16 26.595 29.484 26.865 ;
     RECT  207.684 26.595 235.44 26.865 ;
     RECT  2.16 27.135 29.484 27.405 ;
     RECT  207.684 27.135 235.44 27.405 ;
     RECT  2.16 27.675 29.484 27.945 ;
     RECT  207.684 27.675 235.44 27.945 ;
     RECT  2.16 28.215 29.484 28.485 ;
     RECT  207.684 28.215 235.44 28.485 ;
     RECT  2.16 28.755 29.484 29.025 ;
     RECT  207.684 28.755 235.44 29.025 ;
     RECT  2.16 29.295 29.484 29.565 ;
     RECT  207.684 29.295 235.44 29.565 ;
     RECT  2.16 29.835 29.484 30.105 ;
     RECT  207.684 29.835 235.44 30.105 ;
     RECT  2.16 30.375 29.484 30.645 ;
     RECT  207.684 30.375 235.44 30.645 ;
     RECT  2.16 30.915 29.484 31.185 ;
     RECT  207.684 30.915 235.44 31.185 ;
     RECT  2.16 31.455 29.484 31.725 ;
     RECT  207.684 31.455 235.44 31.725 ;
     RECT  2.16 31.995 29.484 32.265 ;
     RECT  207.684 31.995 235.44 32.265 ;
     RECT  2.16 32.535 29.484 32.805 ;
     RECT  207.684 32.535 235.44 32.805 ;
     RECT  2.16 33.075 29.484 33.345 ;
     RECT  207.684 33.075 235.44 33.345 ;
     RECT  2.16 33.615 29.484 33.885 ;
     RECT  207.684 33.615 235.44 33.885 ;
     RECT  2.16 34.155 29.484 34.425 ;
     RECT  207.684 34.155 235.44 34.425 ;
     RECT  2.16 34.695 29.484 34.965 ;
     RECT  207.684 34.695 235.44 34.965 ;
     RECT  2.16 35.235 29.484 35.505 ;
     RECT  207.684 35.235 235.44 35.505 ;
     RECT  2.16 35.775 29.484 36.045 ;
     RECT  207.684 35.775 235.44 36.045 ;
     RECT  2.16 36.315 29.484 36.585 ;
     RECT  207.684 36.315 235.44 36.585 ;
     RECT  2.16 36.855 29.484 37.125 ;
     RECT  207.684 36.855 235.44 37.125 ;
     RECT  2.16 37.395 29.484 37.665 ;
     RECT  207.684 37.395 235.44 37.665 ;
     RECT  2.16 37.935 29.484 38.205 ;
     RECT  207.684 37.935 235.44 38.205 ;
     RECT  2.16 38.475 29.484 38.745 ;
     RECT  207.684 38.475 235.44 38.745 ;
     RECT  2.16 39.015 29.484 39.285 ;
     RECT  207.684 39.015 235.44 39.285 ;
     RECT  2.16 39.555 29.484 39.825 ;
     RECT  207.684 39.555 235.44 39.825 ;
     RECT  2.16 40.095 29.484 40.365 ;
     RECT  207.684 40.095 235.44 40.365 ;
     RECT  2.16 40.635 29.484 40.905 ;
     RECT  207.684 40.635 235.44 40.905 ;
     RECT  2.16 41.175 29.484 41.445 ;
     RECT  207.684 41.175 235.44 41.445 ;
     RECT  2.16 41.715 29.484 41.985 ;
     RECT  207.684 41.715 235.44 41.985 ;
     RECT  2.16 42.255 29.484 42.525 ;
     RECT  207.684 42.255 235.44 42.525 ;
     RECT  2.16 42.795 29.484 43.065 ;
     RECT  207.684 42.795 235.44 43.065 ;
     RECT  2.16 43.335 29.484 43.605 ;
     RECT  207.684 43.335 235.44 43.605 ;
     RECT  2.16 43.875 29.484 44.145 ;
     RECT  207.684 43.875 235.44 44.145 ;
     RECT  2.16 44.415 29.484 44.685 ;
     RECT  207.684 44.415 235.44 44.685 ;
     RECT  2.16 44.955 29.484 45.225 ;
     RECT  207.684 44.955 235.44 45.225 ;
     RECT  2.16 45.495 29.484 45.765 ;
     RECT  207.684 45.495 235.44 45.765 ;
     RECT  2.16 46.035 29.484 46.305 ;
     RECT  207.684 46.035 235.44 46.305 ;
     RECT  2.16 46.575 29.484 46.845 ;
     RECT  207.684 46.575 235.44 46.845 ;
     RECT  2.16 47.115 29.484 47.385 ;
     RECT  207.684 47.115 235.44 47.385 ;
     RECT  2.16 47.655 29.484 47.925 ;
     RECT  207.684 47.655 235.44 47.925 ;
     RECT  2.16 48.195 29.484 48.465 ;
     RECT  207.684 48.195 235.44 48.465 ;
     RECT  2.16 48.735 29.484 49.005 ;
     RECT  207.684 48.735 235.44 49.005 ;
     RECT  2.16 49.275 29.484 49.545 ;
     RECT  207.684 49.275 235.44 49.545 ;
     RECT  2.16 49.815 29.484 50.085 ;
     RECT  207.684 49.815 235.44 50.085 ;
     RECT  2.16 50.355 29.484 50.625 ;
     RECT  207.684 50.355 235.44 50.625 ;
     RECT  2.16 50.895 29.484 51.165 ;
     RECT  207.684 50.895 235.44 51.165 ;
     RECT  2.16 51.435 29.484 51.705 ;
     RECT  207.684 51.435 235.44 51.705 ;
     RECT  2.16 51.975 29.484 52.245 ;
     RECT  207.684 51.975 235.44 52.245 ;
     RECT  2.16 52.515 29.484 52.785 ;
     RECT  207.684 52.515 235.44 52.785 ;
     RECT  2.16 53.055 29.484 53.325 ;
     RECT  207.684 53.055 235.44 53.325 ;
     RECT  2.16 53.595 29.484 53.865 ;
     RECT  207.684 53.595 235.44 53.865 ;
     RECT  2.16 54.135 29.484 54.405 ;
     RECT  207.684 54.135 235.44 54.405 ;
     RECT  2.16 54.675 29.484 54.945 ;
     RECT  207.684 54.675 235.44 54.945 ;
     RECT  2.16 55.215 29.484 55.485 ;
     RECT  207.684 55.215 235.44 55.485 ;
     RECT  2.16 55.755 29.484 56.025 ;
     RECT  207.684 55.755 235.44 56.025 ;
     RECT  2.16 56.295 29.484 56.565 ;
     RECT  207.684 56.295 235.44 56.565 ;
     RECT  2.16 56.835 29.484 57.105 ;
     RECT  207.684 56.835 235.44 57.105 ;
     RECT  2.16 57.375 29.484 57.645 ;
     RECT  207.684 57.375 235.44 57.645 ;
     RECT  2.16 57.915 29.484 58.185 ;
     RECT  207.684 57.915 235.44 58.185 ;
     RECT  2.16 58.455 29.484 58.725 ;
     RECT  207.684 58.455 235.44 58.725 ;
     RECT  2.16 58.995 29.484 59.265 ;
     RECT  207.684 58.995 235.44 59.265 ;
     RECT  2.16 59.535 29.484 59.805 ;
     RECT  207.684 59.535 235.44 59.805 ;
     RECT  2.16 60.075 235.44 60.345 ;
     RECT  2.16 60.615 235.44 60.885 ;
     RECT  2.16 61.155 235.44 61.425 ;
     RECT  2.16 61.695 235.44 61.965 ;
     RECT  2.16 62.235 235.44 62.505 ;
     RECT  2.16 62.775 235.44 63.045 ;
     RECT  2.16 63.315 235.44 63.585 ;
     RECT  2.16 63.855 235.44 64.125 ;
     RECT  2.16 64.395 235.44 64.665 ;
     RECT  2.16 64.935 235.44 65.205 ;
     RECT  2.16 65.475 235.44 65.745 ;
     RECT  2.16 66.015 235.44 66.285 ;
     RECT  2.16 66.555 235.44 66.825 ;
     RECT  2.16 67.095 235.44 67.365 ;
     RECT  2.16 67.635 235.44 67.905 ;
     RECT  2.16 68.175 235.44 68.445 ;
     RECT  2.16 68.715 235.44 68.985 ;
     RECT  2.16 69.255 235.44 69.525 ;
     RECT  2.16 69.795 235.44 70.065 ;
     RECT  2.16 70.335 235.44 70.605 ;
     RECT  2.16 70.875 235.44 71.145 ;
     RECT  2.16 71.415 235.44 71.685 ;
     RECT  2.16 71.955 235.44 72.225 ;
     RECT  2.16 72.495 235.44 72.765 ;
     RECT  2.16 73.035 235.44 73.305 ;
     RECT  2.16 73.575 235.44 73.845 ;
     RECT  2.16 74.115 235.44 74.385 ;
     RECT  2.16 74.655 235.44 74.925 ;
     RECT  2.16 75.195 235.44 75.465 ;
     RECT  2.16 75.735 235.44 76.005 ;
     RECT  2.16 76.275 235.44 76.545 ;
     RECT  2.16 76.815 235.44 77.085 ;
     RECT  2.16 77.355 235.44 77.625 ;
     RECT  2.16 77.895 235.44 78.165 ;
     RECT  2.16 78.435 235.44 78.705 ;
     RECT  2.16 78.975 235.44 79.245 ;
     RECT  2.16 79.515 235.44 79.785 ;
     RECT  2.16 80.055 235.44 80.325 ;
     RECT  2.16 80.595 235.44 80.865 ;
     RECT  2.16 81.135 235.44 81.405 ;
     RECT  2.16 81.675 235.44 81.945 ;
     RECT  2.16 82.215 235.44 82.485 ;
     RECT  2.16 82.755 235.44 83.025 ;
     RECT  2.16 83.295 235.44 83.565 ;
     RECT  2.16 83.835 235.44 84.105 ;
    LAYER M1 ;
     RECT  2.16 2.151 235.44 25.929 ;
     RECT  31.536 28.08 205.656 57.816 ;
     RECT  2.16 25.929 29.484 59.931 ;
     RECT  207.684 25.929 235.44 59.931 ;
     RECT  2.16 59.931 235.44 84.249 ;
    LAYER M2 ;
     RECT  0.463 2.106 1.363 2.124 ;
     RECT  1.363 2.106 2.16 2.52 ;
     RECT  0.103 43.146 2.16 43.164 ;
     RECT  2.16 2.106 2.399 84.249 ;
     RECT  2.399 2.151 11.011 84.249 ;
     RECT  11.011 2.106 11.723 84.249 ;
     RECT  11.723 2.151 28.507 84.249 ;
     RECT  28.507 2.106 28.859 84.249 ;
     RECT  28.859 2.151 29.484 84.249 ;
     RECT  29.484 36.864 29.52 37.269 ;
     RECT  29.484 39.906 29.52 42.984 ;
     RECT  29.484 45.846 29.52 45.909 ;
     RECT  29.484 48.978 29.52 84.249 ;
     RECT  29.484 2.151 29.543 30.024 ;
     RECT  29.52 36.864 29.579 36.882 ;
     RECT  29.52 42.156 29.615 42.984 ;
     RECT  29.484 31.428 29.651 33.138 ;
     RECT  29.651 32.976 29.687 33.066 ;
     RECT  29.615 42.606 29.687 42.984 ;
     RECT  29.543 2.151 29.695 28.476 ;
     RECT  29.651 31.428 29.939 31.914 ;
     RECT  29.484 35.406 29.975 35.424 ;
     RECT  29.939 31.896 30.011 31.914 ;
     RECT  29.52 39.906 30.047 41.094 ;
     RECT  29.695 2.106 30.119 28.476 ;
     RECT  29.687 42.696 30.191 42.984 ;
     RECT  29.484 34.092 30.227 34.65 ;
     RECT  30.191 42.696 30.227 42.714 ;
     RECT  29.52 45.846 30.227 45.864 ;
     RECT  30.227 34.326 30.263 34.65 ;
     RECT  30.047 39.906 30.479 40.554 ;
     RECT  29.484 46.926 30.767 47.682 ;
     RECT  29.484 44.226 30.803 44.244 ;
     RECT  30.119 2.151 30.883 28.476 ;
     RECT  29.543 29.466 30.883 30.024 ;
     RECT  30.883 2.151 31.171 30.024 ;
     RECT  31.171 1.692 31.536 30.024 ;
     RECT  30.263 34.632 31.536 34.65 ;
     RECT  30.479 39.906 31.536 39.924 ;
     RECT  30.767 46.926 31.536 47.304 ;
     RECT  29.52 48.978 31.536 49.572 ;
     RECT  31.536 1.692 32.827 57.816 ;
     RECT  32.827 1.611 127.211 57.816 ;
     RECT  127.211 1.656 160.331 57.816 ;
     RECT  160.331 2.034 162.499 57.816 ;
     RECT  29.52 59.931 164.731 84.249 ;
     RECT  162.499 1.998 166.523 57.816 ;
     RECT  166.523 2.034 174.407 57.816 ;
     RECT  164.731 59.886 174.515 84.249 ;
     RECT  174.407 2.151 205.656 57.816 ;
     RECT  205.656 36.792 206.527 49.878 ;
     RECT  205.987 57.816 206.671 57.834 ;
     RECT  205.656 56.736 206.707 56.754 ;
     RECT  206.527 36.792 206.779 50.346 ;
     RECT  205.656 51.786 206.815 52.434 ;
     RECT  206.707 56.106 206.887 56.754 ;
     RECT  206.671 57.816 206.887 58.104 ;
     RECT  205.656 32.508 206.923 33.102 ;
     RECT  205.656 33.93 206.923 35.298 ;
     RECT  206.887 56.106 207.283 58.104 ;
     RECT  206.815 51.642 207.355 52.434 ;
     RECT  205.656 53.298 207.355 54.054 ;
     RECT  207.355 51.642 207.391 54.054 ;
     RECT  206.923 32.508 207.499 35.298 ;
     RECT  206.779 36.792 207.499 50.454 ;
     RECT  205.656 2.151 207.684 28.944 ;
     RECT  205.656 31.662 207.684 31.68 ;
     RECT  207.499 32.508 207.684 50.454 ;
     RECT  207.391 51.642 207.684 54.504 ;
     RECT  207.283 55.386 207.684 58.104 ;
     RECT  174.515 59.931 207.684 84.249 ;
     RECT  207.684 2.151 235.44 84.249 ;
     RECT  235.44 83.304 235.463 84.204 ;
     RECT  235.44 3.582 235.679 10.89 ;
     RECT  235.44 66.456 235.679 82.476 ;
     RECT  235.44 13.068 235.931 16.974 ;
     RECT  235.44 21.942 235.931 35.46 ;
     RECT  235.44 36.36 235.931 38.97 ;
     RECT  235.679 4.662 235.967 10.89 ;
     RECT  235.44 11.682 235.967 12.24 ;
     RECT  235.931 13.338 235.967 16.974 ;
     RECT  235.44 17.892 235.967 21.186 ;
     RECT  235.931 21.942 235.967 23.85 ;
     RECT  235.931 25.722 235.967 35.46 ;
     RECT  235.931 36.792 235.967 38.97 ;
     RECT  235.44 39.87 235.967 42.21 ;
     RECT  235.679 66.456 235.967 79.704 ;
     RECT  235.679 80.496 235.967 82.476 ;
     RECT  235.463 83.304 235.967 83.754 ;
     RECT  235.967 4.662 236.003 8.226 ;
     RECT  235.967 80.676 236.003 82.476 ;
     RECT  235.44 43.002 236.363 65.664 ;
     RECT  235.967 15.462 236.435 16.974 ;
     RECT  235.967 66.456 236.471 66.744 ;
     RECT  235.967 67.536 236.471 79.704 ;
     RECT  236.003 4.662 236.507 7.254 ;
     RECT  235.967 22.212 236.507 23.31 ;
     RECT  235.931 24.642 236.507 24.93 ;
     RECT  236.471 67.536 236.507 75.114 ;
     RECT  236.471 75.906 236.507 78.084 ;
     RECT  235.967 83.466 236.507 83.754 ;
     RECT  236.507 4.662 236.543 6.408 ;
     RECT  236.507 7.236 236.543 7.254 ;
     RECT  236.003 8.208 236.543 8.226 ;
     RECT  235.967 10.332 236.543 10.35 ;
     RECT  235.967 13.338 236.543 13.59 ;
     RECT  235.967 14.688 236.543 14.706 ;
     RECT  236.435 15.462 236.543 16.02 ;
     RECT  236.435 16.956 236.543 16.974 ;
     RECT  235.967 18.54 236.543 21.186 ;
     RECT  236.507 22.356 236.543 23.31 ;
     RECT  236.507 24.912 236.543 24.93 ;
     RECT  235.967 26.802 236.543 27.36 ;
     RECT  235.967 29.646 236.543 30.708 ;
     RECT  235.967 36.792 236.543 36.81 ;
     RECT  235.967 38.142 236.543 38.16 ;
     RECT  235.967 40.374 236.543 40.896 ;
     RECT  236.363 43.002 236.543 60.264 ;
     RECT  236.363 61.2 236.543 65.664 ;
     RECT  236.471 66.456 236.543 66.474 ;
     RECT  236.507 67.536 236.543 73.224 ;
     RECT  236.507 74.016 236.543 74.034 ;
     RECT  236.507 75.096 236.543 75.114 ;
     RECT  236.507 75.906 236.543 76.194 ;
     RECT  236.507 77.256 236.543 78.084 ;
     RECT  236.471 78.876 236.543 79.704 ;
     RECT  236.003 80.766 236.543 82.476 ;
     RECT  236.507 83.466 236.543 83.484 ;
     RECT  236.543 18.54 236.579 18.72 ;
     RECT  235.967 31.968 236.579 32.328 ;
     RECT  236.543 40.374 236.579 40.392 ;
     RECT  236.543 61.236 236.579 61.254 ;
     RECT  236.543 62.586 236.579 63.684 ;
     RECT  236.543 77.904 236.579 77.922 ;
     RECT  236.543 78.984 236.579 79.614 ;
     RECT  236.579 62.676 236.615 63.684 ;
     RECT  236.579 78.984 236.615 79.002 ;
     RECT  235.679 3.582 237.443 3.87 ;
     RECT  236.543 6.012 237.443 6.336 ;
     RECT  236.543 13.338 237.443 13.356 ;
     RECT  237.443 3.582 237.479 3.744 ;
     RECT  236.543 21.132 237.479 21.186 ;
     RECT  236.543 29.646 237.479 29.826 ;
     RECT  235.967 33.354 237.479 34.92 ;
     RECT  237.479 3.582 237.515 3.6 ;
     RECT  236.543 4.662 237.515 5.22 ;
     RECT  236.543 15.462 237.515 15.48 ;
     RECT  236.579 18.702 237.515 18.72 ;
     RECT  236.543 20.052 237.515 20.07 ;
     RECT  237.479 21.132 237.515 21.15 ;
     RECT  236.543 26.802 237.515 26.82 ;
     RECT  237.479 29.808 237.515 29.826 ;
     RECT  236.579 31.968 237.515 31.986 ;
     RECT  237.479 33.588 237.515 33.606 ;
     RECT  237.479 34.362 237.515 34.92 ;
     RECT  236.543 45 237.515 45.018 ;
     RECT  236.543 49.446 237.515 50.004 ;
     RECT  236.543 52.416 237.515 52.884 ;
     RECT  236.543 56.916 237.515 56.934 ;
     RECT  236.615 63.126 237.515 63.684 ;
     RECT  236.543 69.534 237.515 69.552 ;
     RECT  236.543 70.776 237.515 70.794 ;
     RECT  236.543 71.856 237.515 71.874 ;
     RECT  236.543 75.906 237.515 75.924 ;
     RECT  236.543 82.386 237.515 82.476 ;
     RECT  237.515 5.04 237.551 5.058 ;
     RECT  237.443 6.012 237.587 6.03 ;
     RECT  237.515 82.386 237.587 82.404 ;
    LAYER M3 ;
     RECT  235.296 0.091 235.314 0.139 ;
     RECT  235.116 0.139 235.314 0.235 ;
     RECT  131.436 0.091 131.454 0.523 ;
     RECT  223.416 0.091 223.434 0.571 ;
     RECT  237.492 0.139 237.51 1.003 ;
     RECT  233.604 0.091 233.622 1.099 ;
     RECT  234.432 0.235 235.314 1.099 ;
     RECT  236.232 0.427 236.25 1.099 ;
     RECT  2.556 0.091 2.574 1.147 ;
     RECT  12.924 0.091 12.942 1.147 ;
     RECT  20.232 0.091 20.25 1.147 ;
     RECT  61.308 0.091 61.326 1.147 ;
     RECT  90.576 0.091 90.594 1.147 ;
     RECT  116.136 0.091 116.154 1.147 ;
     RECT  135.648 0.091 135.666 1.147 ;
     RECT  144.792 0.091 144.81 1.147 ;
     RECT  153.972 0.091 153.99 1.147 ;
     RECT  165.024 0.091 165.042 1.147 ;
     RECT  169.488 0.091 169.506 1.147 ;
     RECT  173.196 0.091 173.214 1.147 ;
     RECT  179.568 0.091 179.586 1.147 ;
     RECT  211.572 0.091 211.59 1.147 ;
     RECT  231.66 0.091 231.678 1.147 ;
     RECT  237.42 1.003 237.51 1.387 ;
     RECT  126.576 0.091 126.594 1.606 ;
     RECT  127.476 0.571 127.494 1.606 ;
     RECT  160.38 0.091 160.398 1.651 ;
     RECT  30.816 1.147 30.834 1.687 ;
     RECT  136.8 1.147 136.818 1.687 ;
     RECT  137.556 0.091 137.574 1.687 ;
     RECT  8.352 0.091 8.37 1.723 ;
     RECT  15.696 0.091 15.714 1.723 ;
     RECT  23.904 0.091 23.922 1.723 ;
     RECT  25.956 1.147 25.974 1.723 ;
     RECT  32.004 1.147 32.022 1.723 ;
     RECT  32.832 1.606 32.85 1.723 ;
     RECT  33.948 0.091 33.966 1.723 ;
     RECT  59.364 1.651 59.382 1.723 ;
     RECT  64.188 0.091 64.206 1.723 ;
     RECT  68.436 1.147 68.454 1.723 ;
     RECT  80.388 1.147 80.406 1.723 ;
     RECT  82.368 0.091 82.386 1.723 ;
     RECT  105.264 0.091 105.282 1.723 ;
     RECT  106.992 0.091 107.01 1.723 ;
     RECT  183.276 0.091 183.294 1.723 ;
     RECT  73.584 1.723 74.142 1.957 ;
     RECT  75.024 0.091 75.042 1.957 ;
     RECT  78.156 1.723 78.174 1.957 ;
     RECT  110.124 1.723 110.682 1.957 ;
     RECT  162.36 0.091 162.378 1.993 ;
     RECT  163.224 0.091 163.242 1.993 ;
     RECT  165.888 1.147 165.906 1.993 ;
     RECT  166.716 0.091 166.734 1.993 ;
     RECT  54.18 1.723 54.414 2.029 ;
     RECT  118.296 1.723 118.314 2.029 ;
     RECT  174.24 0.571 174.258 2.029 ;
     RECT  175.068 0.091 175.086 2.029 ;
     RECT  110.124 1.957 110.718 2.056 ;
     RECT  45.288 1.723 45.306 2.059 ;
     RECT  46.188 1.147 46.206 2.059 ;
     RECT  56.304 1.723 56.322 2.059 ;
     RECT  57.168 1.723 57.186 2.059 ;
     RECT  62.928 1.147 62.946 2.059 ;
     RECT  45.288 2.059 46.206 2.065 ;
     RECT  73.584 1.957 75.042 2.065 ;
     RECT  75.888 1.723 75.906 2.065 ;
     RECT  77.184 1.723 77.202 2.065 ;
     RECT  11.088 0.091 11.106 2.101 ;
     RECT  28.764 1.723 28.782 2.101 ;
     RECT  29.772 1.723 29.79 2.101 ;
     RECT  30.816 1.687 31.194 2.101 ;
     RECT  45.036 2.065 46.206 2.101 ;
     RECT  122.004 0.571 122.022 2.101 ;
     RECT  123.012 0.091 123.03 2.101 ;
     RECT  130.392 0.091 130.41 2.101 ;
     RECT  162.36 1.993 163.242 2.101 ;
     RECT  171.288 0.091 171.306 2.101 ;
     RECT  172.728 1.147 173.214 2.101 ;
     RECT  0.468 0.571 0.486 2.129 ;
     RECT  78.156 1.957 78.822 2.129 ;
     RECT  12.708 1.147 12.942 2.143 ;
     RECT  13.86 1.723 13.878 2.143 ;
     RECT  19.188 1.147 19.206 2.143 ;
     RECT  23.184 1.723 23.922 2.143 ;
     RECT  28.512 2.101 28.854 2.143 ;
     RECT  29.7 2.101 31.194 2.143 ;
     RECT  35.244 1.723 35.262 2.143 ;
     RECT  40.428 0.091 40.446 2.143 ;
     RECT  50.292 1.723 50.31 2.143 ;
     RECT  51.228 0.091 51.246 2.143 ;
     RECT  61.092 1.147 61.326 2.143 ;
     RECT  67.14 1.723 67.158 2.143 ;
     RECT  72.756 1.723 72.774 2.143 ;
     RECT  77.112 2.065 77.418 2.143 ;
     RECT  78.156 2.129 78.297 2.143 ;
     RECT  83.304 1.723 83.322 2.143 ;
     RECT  84.204 0.091 84.222 2.143 ;
     RECT  88.272 1.723 88.29 2.143 ;
     RECT  89.136 1.723 89.154 2.143 ;
     RECT  93.672 1.723 93.69 2.143 ;
     RECT  94.536 1.723 94.554 2.143 ;
     RECT  99.18 1.147 99.198 2.143 ;
     RECT  100.26 1.723 100.278 2.143 ;
     RECT  121.176 0.091 121.194 2.143 ;
     RECT  122.004 2.101 123.03 2.143 ;
     RECT  131.436 0.523 131.994 2.143 ;
     RECT  142.092 0.091 142.11 2.143 ;
     RECT  143.208 1.147 143.226 2.143 ;
     RECT  147.672 1.147 147.69 2.143 ;
     RECT  148.788 1.147 148.806 2.143 ;
     RECT  158.688 0.091 158.706 2.143 ;
     RECT  159.552 0.091 159.57 2.143 ;
     RECT  168.804 1.147 169.506 2.143 ;
     RECT  170.424 1.147 170.442 2.143 ;
     RECT  174.24 2.029 175.086 2.143 ;
     RECT  180.468 0.091 180.486 2.143 ;
     RECT  185.364 1.147 185.382 2.143 ;
     RECT  186.408 1.147 187.002 2.143 ;
     RECT  191.556 1.147 191.574 2.143 ;
     RECT  196.164 1.147 196.182 2.143 ;
     RECT  196.956 0.091 196.974 2.143 ;
     RECT  201.528 0.571 201.546 2.143 ;
     RECT  202.536 0.091 203.274 2.143 ;
     RECT  207.036 0.571 207.054 2.143 ;
     RECT  207.9 0.091 207.918 2.143 ;
     RECT  212.58 0.091 212.598 2.143 ;
     RECT  213.372 0.571 213.39 2.143 ;
     RECT  222.696 0.571 223.434 2.143 ;
     RECT  224.352 0.091 224.37 2.143 ;
     RECT  228.924 0.091 228.942 2.143 ;
     RECT  229.788 0.091 229.806 2.143 ;
     RECT  237.42 1.387 237.582 2.155 ;
     RECT  9.252 1.723 9.27 2.191 ;
     RECT  10.188 0.091 10.206 2.191 ;
     RECT  11.016 2.101 11.718 2.191 ;
     RECT  12.708 2.143 13.878 2.191 ;
     RECT  52.74 1.723 52.758 2.191 ;
     RECT  53.856 2.029 54.414 2.191 ;
     RECT  55.476 1.723 55.494 2.191 ;
     RECT  59.004 1.723 59.922 2.191 ;
     RECT  66.384 1.723 66.402 2.191 ;
     RECT  87.3 1.723 87.318 2.191 ;
     RECT  96.372 1.723 96.39 2.191 ;
     RECT  97.128 1.723 97.146 2.191 ;
     RECT  97.884 0.091 97.902 2.191 ;
     RECT  145.944 1.147 145.962 2.191 ;
     RECT  153.324 1.147 153.99 2.191 ;
     RECT  154.908 0.091 154.926 2.191 ;
     RECT  156.744 1.147 156.762 2.191 ;
     RECT  157.572 0.091 157.59 2.191 ;
     RECT  164.376 1.147 165.042 2.191 ;
     RECT  165.888 1.993 166.734 2.191 ;
     RECT  225.504 0.091 226.206 2.191 ;
     RECT  11.016 2.191 13.878 2.219 ;
     RECT  28.512 2.143 31.194 2.219 ;
     RECT  77.112 2.143 78.297 2.219 ;
     RECT  138.672 1.147 138.69 2.219 ;
     RECT  149.724 0.091 149.742 2.219 ;
     RECT  152.316 1.147 152.334 2.219 ;
     RECT  153.324 2.191 154.926 2.219 ;
     RECT  162.324 2.101 163.242 2.219 ;
     RECT  187.776 0.091 187.794 2.219 ;
     RECT  198.936 1.147 198.954 2.219 ;
     RECT  211.14 1.147 211.59 2.219 ;
     RECT  215.352 0.091 215.37 2.219 ;
     RECT  135.108 1.147 135.666 2.227 ;
     RECT  136.8 1.687 137.574 2.227 ;
     RECT  180.468 2.143 180.705 2.227 ;
     RECT  181.656 0.091 181.674 2.227 ;
     RECT  199.836 0.571 199.854 2.227 ;
     RECT  200.592 0.091 200.61 2.227 ;
     RECT  206.208 0.091 206.226 2.227 ;
     RECT  207.036 2.143 207.918 2.227 ;
     RECT  222.696 2.143 224.37 2.227 ;
     RECT  225.108 2.191 226.386 2.227 ;
     RECT  228.132 0.091 228.15 2.227 ;
     RECT  228.924 2.143 229.806 2.227 ;
     RECT  230.94 1.147 231.678 2.227 ;
     RECT  3.708 0.091 3.726 2.255 ;
     RECT  4.608 1.723 4.626 2.255 ;
     RECT  5.58 0.091 5.598 2.255 ;
     RECT  6.984 1.723 7.002 2.255 ;
     RECT  7.74 1.723 8.37 2.255 ;
     RECT  9.252 2.191 10.206 2.255 ;
     RECT  11.088 2.219 13.878 2.255 ;
     RECT  15.156 1.723 15.714 2.255 ;
     RECT  18.615 2.143 19.206 2.255 ;
     RECT  20.16 1.147 20.25 2.255 ;
     RECT  22.428 1.723 22.446 2.255 ;
     RECT  25.668 1.723 25.974 2.255 ;
     RECT  26.928 1.723 27.486 2.255 ;
     RECT  28.764 2.219 31.194 2.255 ;
     RECT  32.004 1.723 33.966 2.255 ;
     RECT  36.108 1.723 36.126 2.255 ;
     RECT  37.98 1.723 37.998 2.255 ;
     RECT  38.808 1.723 39.402 2.255 ;
     RECT  42.156 0.091 42.174 2.255 ;
     RECT  43.992 1.723 44.01 2.255 ;
     RECT  49.428 0.091 49.446 2.255 ;
     RECT  50.292 2.143 51.246 2.255 ;
     RECT  52.092 2.191 52.758 2.255 ;
     RECT  53.856 2.191 55.494 2.255 ;
     RECT  58.032 1.723 58.05 2.255 ;
     RECT  65.376 1.723 65.394 2.255 ;
     RECT  68.436 1.723 68.994 2.255 ;
     RECT  70.884 1.723 71.37 2.255 ;
     RECT  73.584 2.065 75.906 2.255 ;
     RECT  77.184 2.219 78.297 2.255 ;
     RECT  79.56 1.147 79.578 2.255 ;
     RECT  80.388 1.723 80.946 2.255 ;
     RECT  82.008 1.723 82.386 2.255 ;
     RECT  83.304 2.143 84.222 2.255 ;
     RECT  85.176 1.723 85.194 2.255 ;
     RECT  86.328 1.723 86.346 2.255 ;
     RECT  88.272 2.143 89.154 2.255 ;
     RECT  90.216 1.147 90.594 2.255 ;
     RECT  91.512 0.091 91.53 2.255 ;
     RECT  92.484 1.723 92.502 2.255 ;
     RECT  93.672 2.143 94.554 2.255 ;
     RECT  95.544 1.723 95.562 2.255 ;
     RECT  99.18 2.143 100.278 2.255 ;
     RECT  101.052 1.723 101.07 2.255 ;
     RECT  101.988 1.723 102.69 2.255 ;
     RECT  103.752 1.723 103.77 2.255 ;
     RECT  106.416 1.723 107.01 2.255 ;
     RECT  108.288 0.091 108.306 2.255 ;
     RECT  109.224 1.723 109.242 2.255 ;
     RECT  110.124 2.056 110.754 2.255 ;
     RECT  111.6 0.091 111.618 2.255 ;
     RECT  112.896 1.723 112.914 2.255 ;
     RECT  113.796 1.723 113.814 2.255 ;
     RECT  114.768 1.723 114.786 2.255 ;
     RECT  117.036 0.091 117.054 2.255 ;
     RECT  16.596 1.723 16.614 2.263 ;
     RECT  17.46 0.091 17.478 2.263 ;
     RECT  20.16 2.255 20.178 2.263 ;
     RECT  21.132 1.723 21.15 2.263 ;
     RECT  25.956 2.255 25.974 2.263 ;
     RECT  26.928 2.255 26.946 2.263 ;
     RECT  37.08 1.147 37.098 2.263 ;
     RECT  43.056 0.091 43.074 2.263 ;
     RECT  59.004 2.191 59.994 2.263 ;
     RECT  61.092 2.143 61.905 2.263 ;
     RECT  62.928 2.059 63.018 2.263 ;
     RECT  80.424 2.255 80.946 2.263 ;
     RECT  96.372 2.191 97.902 2.263 ;
     RECT  99.18 2.255 100.206 2.263 ;
     RECT  101.988 2.255 102.438 2.263 ;
     RECT  104.724 1.723 105.282 2.263 ;
     RECT  118.296 2.029 118.602 2.263 ;
     RECT  128.52 0.091 128.538 2.263 ;
     RECT  135.108 2.227 137.574 2.263 ;
     RECT  139.536 0.091 139.554 2.263 ;
     RECT  164.376 2.191 166.734 2.263 ;
     RECT  168.804 2.143 170.442 2.263 ;
     RECT  191.415 2.143 191.574 2.263 ;
     RECT  192.384 0.091 192.402 2.263 ;
     RECT  193.356 0.091 193.374 2.263 ;
     RECT  194.508 1.147 194.526 2.263 ;
     RECT  197.856 0.091 197.874 2.263 ;
     RECT  212.58 2.143 213.39 2.263 ;
     RECT  216.144 0.091 216.162 2.263 ;
     RECT  218.304 1.147 218.934 2.263 ;
     RECT  221.94 1.147 221.958 2.263 ;
     RECT  222.696 2.227 226.386 2.263 ;
     RECT  227.124 0.091 227.142 2.263 ;
     RECT  228.132 2.227 229.806 2.263 ;
     RECT  232.56 0.091 232.578 2.263 ;
     RECT  233.604 1.099 235.314 2.263 ;
     RECT  237.384 2.155 237.582 2.285 ;
     RECT  59.004 2.263 60.354 2.291 ;
     RECT  63.756 1.723 64.206 2.291 ;
     RECT  158.688 2.143 159.57 2.299 ;
     RECT  230.868 2.227 231.678 2.299 ;
     RECT  232.56 2.263 235.314 2.299 ;
     RECT  87.228 2.191 87.318 2.327 ;
     RECT  56.304 2.059 57.186 2.335 ;
     RECT  59.004 2.291 59.382 2.335 ;
     RECT  91.44 2.263 91.458 2.335 ;
     RECT  120.24 0.091 120.258 2.335 ;
     RECT  121.176 2.143 123.03 2.335 ;
     RECT  123.984 0.091 124.002 2.335 ;
     RECT  124.884 1.147 124.902 2.335 ;
     RECT  125.676 0.571 125.694 2.335 ;
     RECT  126.576 1.606 127.494 2.335 ;
     RECT  130.356 2.101 130.554 2.335 ;
     RECT  131.436 2.143 132.105 2.335 ;
     RECT  142.092 2.143 143.226 2.335 ;
     RECT  144.216 1.147 144.81 2.335 ;
     RECT  146.808 0.091 146.826 2.335 ;
     RECT  150.588 1.147 150.606 2.335 ;
     RECT  155.952 0.091 155.97 2.335 ;
     RECT  156.744 2.191 157.59 2.335 ;
     RECT  158.364 2.299 159.57 2.335 ;
     RECT  160.308 1.651 160.398 2.335 ;
     RECT  161.316 1.147 161.334 2.335 ;
     RECT  164.052 2.263 166.734 2.335 ;
     RECT  167.544 0.091 167.562 2.335 ;
     RECT  168.804 2.263 170.55 2.335 ;
     RECT  171.288 2.101 173.214 2.335 ;
     RECT  177.984 1.147 178.002 2.335 ;
     RECT  180.468 2.227 181.674 2.335 ;
     RECT  182.988 1.723 183.294 2.335 ;
     RECT  184.14 0.091 184.158 2.335 ;
     RECT  185.364 2.143 187.002 2.335 ;
     RECT  188.64 0.091 188.658 2.335 ;
     RECT  189.612 0.091 189.63 2.335 ;
     RECT  190.656 0.091 190.674 2.335 ;
     RECT  191.415 2.263 193.518 2.335 ;
     RECT  194.364 2.263 194.526 2.335 ;
     RECT  195.408 0.571 195.426 2.335 ;
     RECT  197.82 2.263 197.874 2.335 ;
     RECT  204.48 0.091 205.182 2.335 ;
     RECT  206.208 2.227 207.918 2.335 ;
     RECT  215.496 2.263 216.162 2.335 ;
     RECT  217.008 0.091 217.026 2.335 ;
     RECT  218.304 2.263 219.042 2.335 ;
     RECT  219.78 0.091 219.798 2.335 ;
     RECT  227.124 2.263 229.806 2.335 ;
     RECT  230.868 2.299 235.314 2.335 ;
     RECT  17.352 2.263 17.478 2.371 ;
     RECT  18.615 2.255 18.897 2.371 ;
     RECT  21.024 2.263 21.15 2.371 ;
     RECT  23.184 2.143 24.105 2.371 ;
     RECT  33.696 2.255 33.966 2.371 ;
     RECT  34.815 2.143 35.262 2.371 ;
     RECT  36.9 2.263 37.098 2.371 ;
     RECT  40.215 2.143 40.446 2.371 ;
     RECT  41.22 1.723 41.238 2.371 ;
     RECT  44.856 2.101 46.206 2.371 ;
     RECT  47.232 1.723 47.25 2.371 ;
     RECT  47.988 1.723 48.546 2.371 ;
     RECT  66.312 2.191 66.402 2.371 ;
     RECT  67.14 2.143 67.305 2.371 ;
     RECT  70.056 1.723 70.074 2.371 ;
     RECT  72.615 2.143 72.774 2.371 ;
     RECT  73.584 2.255 74.43 2.371 ;
     RECT  82.26 2.255 82.386 2.371 ;
     RECT  83.304 2.255 83.898 2.371 ;
     RECT  88.704 2.255 89.154 2.371 ;
     RECT  101.808 2.263 102.438 2.371 ;
     RECT  106.416 2.255 106.722 2.371 ;
     RECT  110.196 2.255 110.754 2.371 ;
     RECT  117.792 2.263 118.602 2.371 ;
     RECT  124.884 2.335 127.494 2.371 ;
     RECT  128.376 2.263 128.538 2.371 ;
     RECT  130.284 2.335 130.554 2.371 ;
     RECT  131.328 2.335 132.105 2.371 ;
     RECT  134.064 1.147 134.082 2.371 ;
     RECT  135.108 2.263 138.582 2.371 ;
     RECT  142.092 2.335 144.81 2.371 ;
     RECT  145.548 2.191 145.962 2.371 ;
     RECT  150.48 2.335 150.606 2.371 ;
     RECT  155.952 2.335 161.334 2.371 ;
     RECT  162.324 2.219 163.134 2.371 ;
     RECT  199.836 2.227 200.61 2.371 ;
     RECT  2.304 1.147 2.574 2.413 ;
     RECT  3.312 2.263 3.33 2.413 ;
     RECT  50.544 2.255 51.246 2.413 ;
     RECT  65.88 2.371 67.305 2.413 ;
     RECT  104.616 2.263 105.282 2.413 ;
     RECT  130.284 2.371 132.105 2.413 ;
     RECT  174.24 2.143 175.305 2.413 ;
     RECT  176.076 0.091 176.778 2.413 ;
     RECT  196.164 2.143 196.974 2.413 ;
     RECT  227.124 2.335 235.314 2.443 ;
     RECT  236.232 1.099 236.574 2.443 ;
     RECT  60.228 2.291 60.354 2.461 ;
     RECT  61.092 2.263 63.018 2.461 ;
     RECT  63.756 2.291 63.846 2.461 ;
     RECT  96.084 2.263 97.902 2.461 ;
     RECT  98.748 2.263 100.206 2.461 ;
     RECT  103.5 2.371 103.518 2.461 ;
     RECT  115.704 1.147 116.154 2.461 ;
     RECT  120.096 2.335 120.258 2.461 ;
     RECT  121.032 2.335 123.066 2.461 ;
     RECT  129.384 1.147 129.402 2.461 ;
     RECT  130.284 2.413 132.297 2.461 ;
     RECT  133.164 0.091 133.182 2.461 ;
     RECT  134.064 2.371 138.582 2.461 ;
     RECT  141.3 0.091 141.318 2.461 ;
     RECT  142.092 2.371 145.962 2.461 ;
     RECT  146.772 2.335 146.826 2.461 ;
     RECT  150.48 2.371 150.642 2.461 ;
     RECT  151.452 0.091 151.47 2.461 ;
     RECT  155.952 2.371 163.134 2.461 ;
     RECT  168.804 2.335 173.214 2.461 ;
     RECT  174.24 2.413 176.778 2.461 ;
     RECT  221.94 2.263 226.386 2.461 ;
     RECT  227.124 2.443 236.574 2.461 ;
     RECT  9.684 2.255 9.99 2.489 ;
     RECT  15.444 2.255 15.462 2.489 ;
     RECT  22.752 2.371 24.606 2.489 ;
     RECT  33.696 2.371 35.586 2.489 ;
     RECT  44.856 2.371 49.374 2.489 ;
     RECT  60.228 2.461 63.846 2.489 ;
     RECT  65.88 2.413 67.497 2.489 ;
     RECT  82.26 2.371 83.898 2.489 ;
     RECT  87.444 2.371 87.93 2.489 ;
     RECT  90.9 2.335 91.458 2.489 ;
     RECT  96.084 2.461 100.206 2.489 ;
     RECT  114.12 2.263 114.354 2.489 ;
     RECT  141.3 2.461 146.826 2.489 ;
     RECT  129.276 2.461 133.182 2.497 ;
     RECT  133.92 2.461 138.582 2.497 ;
     RECT  139.536 2.263 139.662 2.497 ;
     RECT  140.436 0.091 140.454 2.497 ;
     RECT  147.672 2.143 148.806 2.497 ;
     RECT  149.616 2.335 149.634 2.497 ;
     RECT  168.804 2.461 176.778 2.497 ;
     RECT  1.368 1.723 1.386 2.525 ;
     RECT  7.74 2.255 8.154 2.525 ;
     RECT  11.7 2.255 13.626 2.525 ;
     RECT  19.944 2.263 20.178 2.525 ;
     RECT  25.956 2.263 26.946 2.525 ;
     RECT  60.336 2.489 63.846 2.525 ;
     RECT  71.424 2.371 74.43 2.525 ;
     RECT  80.424 2.263 81.306 2.525 ;
     RECT  115.704 2.461 116.262 2.525 ;
     RECT  119.808 2.461 123.066 2.533 ;
     RECT  123.984 2.335 124.146 2.533 ;
     RECT  124.884 2.371 128.538 2.533 ;
     RECT  139.536 2.497 140.454 2.533 ;
     RECT  70.056 2.371 70.686 2.539 ;
     RECT  63.396 2.525 63.846 2.561 ;
     RECT  146.628 2.489 146.826 2.561 ;
     RECT  141.3 2.489 145.782 2.569 ;
     RECT  146.7 2.561 146.826 2.569 ;
     RECT  147.672 2.497 149.634 2.569 ;
     RECT  220.968 0.091 220.986 2.569 ;
     RECT  221.94 2.461 236.574 2.569 ;
     RECT  69.84 2.539 70.686 2.573 ;
     RECT  69.84 2.573 70.578 2.597 ;
     RECT  106.2 2.371 106.722 2.597 ;
     RECT  129.276 2.497 138.582 2.597 ;
     RECT  31.032 2.255 31.194 2.605 ;
     RECT  32.004 2.255 32.85 2.605 ;
     RECT  152.388 2.335 152.586 2.605 ;
     RECT  153.324 2.219 154.818 2.605 ;
     RECT  155.844 2.461 163.134 2.605 ;
     RECT  168.624 2.497 176.778 2.605 ;
     RECT  177.912 2.335 178.002 2.605 ;
     RECT  178.992 1.147 179.586 2.605 ;
     RECT  180.432 2.335 181.674 2.605 ;
     RECT  182.808 2.335 184.158 2.605 ;
     RECT  187.884 2.335 188.658 2.605 ;
     RECT  189.612 2.335 189.81 2.605 ;
     RECT  190.656 2.335 193.518 2.605 ;
     RECT  194.364 2.335 195.426 2.605 ;
     RECT  196.164 2.413 197.097 2.605 ;
     RECT  197.82 2.335 198.81 2.605 ;
     RECT  199.728 2.371 200.61 2.605 ;
     RECT  201.528 2.143 203.274 2.605 ;
     RECT  206.064 2.335 207.918 2.605 ;
     RECT  208.8 0.571 208.818 2.605 ;
     RECT  209.772 1.147 209.79 2.605 ;
     RECT  211.068 2.335 211.086 2.605 ;
     RECT  211.824 2.263 213.39 2.605 ;
     RECT  214.236 0.091 214.254 2.605 ;
     RECT  218.304 2.335 219.798 2.605 ;
     RECT  220.968 2.569 236.574 2.605 ;
     RECT  129.276 2.597 138.546 2.633 ;
     RECT  155.556 2.605 163.134 2.633 ;
     RECT  21.024 2.371 21.762 2.641 ;
     RECT  42.984 2.263 43.074 2.641 ;
     RECT  117.108 2.371 118.71 2.641 ;
     RECT  164.052 2.335 167.562 2.641 ;
     RECT  177.876 2.605 184.158 2.641 ;
     RECT  187.884 2.605 189.81 2.641 ;
     RECT  190.656 2.605 198.81 2.641 ;
     RECT  199.728 2.605 203.526 2.641 ;
     RECT  204.372 2.335 205.182 2.641 ;
     RECT  206.064 2.605 208.818 2.641 ;
     RECT  209.772 2.605 211.086 2.641 ;
     RECT  211.824 2.605 214.254 2.641 ;
     RECT  215.496 2.335 217.026 2.641 ;
     RECT  217.98 2.605 236.574 2.641 ;
     RECT  101.376 2.371 102.438 2.669 ;
     RECT  119.736 2.533 128.538 2.759 ;
     RECT  129.276 2.633 134.082 2.759 ;
     RECT  135.108 2.633 138.546 2.759 ;
     RECT  139.392 2.533 140.454 2.759 ;
     RECT  141.228 2.569 145.782 2.759 ;
     RECT  146.7 2.569 149.634 2.759 ;
     RECT  150.372 2.461 151.47 2.759 ;
     RECT  152.388 2.605 154.818 2.759 ;
     RECT  155.556 2.633 161.406 2.759 ;
     RECT  162.216 2.633 163.134 2.759 ;
     RECT  164.052 2.641 167.85 2.759 ;
     RECT  168.624 2.605 177.03 2.759 ;
     RECT  177.876 2.641 184.446 2.759 ;
     RECT  185.256 2.335 187.074 2.759 ;
     RECT  187.884 2.641 198.81 2.759 ;
     RECT  199.728 2.641 211.086 2.759 ;
     RECT  211.824 2.641 214.434 2.759 ;
     RECT  215.496 2.641 236.574 2.759 ;
     RECT  13.104 2.525 13.626 2.768 ;
     RECT  56.304 2.335 57.69 2.768 ;
     RECT  88.704 2.371 89.37 2.768 ;
     RECT  98.1 2.489 100.206 2.768 ;
     RECT  121.104 2.759 122.634 2.768 ;
     RECT  44.1 2.371 44.118 2.779 ;
     RECT  44.856 2.489 46.89 2.779 ;
     RECT  101.376 2.669 102.366 2.795 ;
     RECT  117.108 2.641 118.746 2.795 ;
     RECT  146.7 2.759 149.526 2.795 ;
     RECT  158.652 2.759 161.334 2.795 ;
     RECT  36.9 2.371 37.746 2.803 ;
     RECT  176.364 2.759 177.03 2.803 ;
     RECT  44.1 2.779 46.89 2.831 ;
     RECT  185.256 2.759 186.297 2.831 ;
     RECT  196.815 2.759 198.45 2.831 ;
     RECT  217.26 2.759 221.526 2.831 ;
     RECT  42.984 2.641 43.218 2.839 ;
     RECT  176.364 2.803 177.066 2.839 ;
     RECT  36.684 2.803 37.746 2.861 ;
     RECT  42.984 2.839 43.254 2.867 ;
     RECT  44.856 2.831 46.89 2.867 ;
     RECT  53.856 2.255 54.99 2.867 ;
     RECT  71.424 2.525 73.062 2.867 ;
     RECT  74.196 2.525 74.43 2.867 ;
     RECT  107.82 2.263 108.018 2.867 ;
     RECT  129.564 2.759 129.69 2.867 ;
     RECT  131.688 2.759 132.498 2.867 ;
     RECT  53.856 2.867 54.126 2.939 ;
     RECT  74.268 2.867 74.43 2.939 ;
     RECT  121.176 2.768 122.634 3.029 ;
     RECT  128.664 2.911 128.79 3.029 ;
     RECT  136.944 2.759 138.474 3.029 ;
     RECT  141.372 2.759 141.462 3.029 ;
     RECT  142.776 2.759 144.126 3.029 ;
     RECT  152.388 2.759 154.782 3.029 ;
     RECT  156.888 2.759 157.914 3.029 ;
     RECT  158.652 2.795 160.542 3.029 ;
     RECT  162.36 2.759 162.486 3.029 ;
     RECT  167.112 2.759 167.85 3.029 ;
     RECT  169.128 2.759 170.097 3.029 ;
     RECT  173.916 2.759 175.59 3.029 ;
     RECT  180.468 2.759 180.954 3.029 ;
     RECT  181.944 2.759 182.286 3.029 ;
     RECT  184.428 2.759 184.446 3.029 ;
     RECT  187.02 2.759 187.074 3.029 ;
     RECT  187.884 2.759 188.73 3.029 ;
     RECT  189.54 2.759 190.026 3.029 ;
     RECT  193.068 2.759 193.914 3.029 ;
     RECT  194.904 2.759 195.75 3.029 ;
     RECT  199.728 2.759 203.994 3.029 ;
     RECT  204.804 2.759 205.182 3.029 ;
     RECT  209.34 2.759 210.402 3.029 ;
     RECT  211.824 2.759 214.254 3.029 ;
     RECT  215.496 2.759 215.514 3.029 ;
     RECT  156.888 3.029 157.806 3.065 ;
     RECT  112.392 2.263 112.41 3.073 ;
     RECT  64.656 2.461 64.674 3.109 ;
     RECT  110.196 2.371 111.33 3.145 ;
     RECT  26.424 2.525 26.946 3.181 ;
     RECT  176.364 2.839 177.138 3.181 ;
     RECT  177.876 2.759 179.622 3.181 ;
     RECT  123.732 2.759 124.362 3.209 ;
     RECT  131.832 2.867 132.498 3.209 ;
     RECT  171.108 2.759 171.27 3.209 ;
     RECT  176.364 3.181 179.622 3.209 ;
     RECT  204.948 3.029 205.038 3.209 ;
     RECT  150.588 2.759 151.434 3.299 ;
     RECT  26.424 3.181 27.306 3.307 ;
     RECT  139.824 2.759 140.454 3.307 ;
     RECT  171.144 3.209 171.27 3.335 ;
     RECT  222.444 2.759 236.574 3.577 ;
     RECT  2.304 2.413 3.33 3.605 ;
     RECT  54.036 2.939 54.126 3.685 ;
     RECT  54.864 2.867 54.99 3.685 ;
     RECT  61.815 2.525 62.478 3.685 ;
     RECT  63.396 2.561 63.414 3.685 ;
     RECT  216.504 2.759 216.522 3.685 ;
     RECT  44.856 2.867 45.99 3.721 ;
     RECT  46.728 2.867 46.89 3.721 ;
     RECT  222.3 3.577 236.574 3.749 ;
     RECT  110.196 3.145 111.402 3.811 ;
     RECT  56.415 2.768 57.69 3.835 ;
     RECT  58.5 2.335 59.382 3.835 ;
     RECT  33.732 2.489 35.586 3.847 ;
     RECT  36.9 2.861 36.918 3.847 ;
     RECT  56.415 3.835 59.382 3.847 ;
     RECT  108 2.867 108.018 3.847 ;
     RECT  56.232 3.847 59.382 3.875 ;
     RECT  237.42 2.285 237.582 3.875 ;
     RECT  119.808 2.759 119.934 3.883 ;
     RECT  121.176 3.029 121.842 3.883 ;
     RECT  133.488 2.759 133.506 3.919 ;
     RECT  61.815 3.685 63.414 3.965 ;
     RECT  110.196 3.811 111.474 3.965 ;
     RECT  222.3 3.749 231.066 3.983 ;
     RECT  231.984 3.749 236.574 4.109 ;
     RECT  232.056 4.109 236.574 4.145 ;
     RECT  223.488 3.983 231.066 4.157 ;
     RECT  222.3 3.983 222.678 4.181 ;
     RECT  56.232 3.875 57.69 4.189 ;
     RECT  103.428 2.461 103.518 4.189 ;
     RECT  103.176 4.189 103.518 4.225 ;
     RECT  104.616 2.413 105.297 4.225 ;
     RECT  103.176 4.225 105.297 4.261 ;
     RECT  106.2 2.597 106.542 4.261 ;
     RECT  52.092 2.255 52.11 4.351 ;
     RECT  232.056 4.145 235.314 4.379 ;
     RECT  108 3.847 108.198 4.387 ;
     RECT  75.564 2.255 75.69 4.423 ;
     RECT  133.488 3.919 133.866 4.423 ;
     RECT  47.736 2.489 49.374 4.459 ;
     RECT  44.856 3.721 46.89 4.495 ;
     RECT  47.736 4.459 49.806 4.495 ;
     RECT  112.392 3.073 112.59 4.495 ;
     RECT  91.08 2.489 91.458 4.507 ;
     RECT  180.615 3.029 180.954 4.507 ;
     RECT  181.944 3.029 182.178 4.507 ;
     RECT  44.856 4.495 49.806 4.531 ;
     RECT  50.544 2.413 51.297 4.531 ;
     RECT  119.808 3.883 121.842 4.531 ;
     RECT  126.576 2.759 127.71 4.531 ;
     RECT  60.336 2.525 60.57 4.621 ;
     RECT  65.88 2.489 66.33 4.621 ;
     RECT  67.068 2.489 67.497 4.621 ;
     RECT  147.06 2.795 149.526 4.649 ;
     RECT  152.496 3.029 154.782 4.649 ;
     RECT  232.056 4.379 235.278 4.649 ;
     RECT  109.044 2.263 109.062 4.657 ;
     RECT  101.376 2.795 101.97 4.729 ;
     RECT  60.3 4.621 60.57 4.747 ;
     RECT  55.836 4.189 57.69 4.765 ;
     RECT  58.5 3.875 59.382 4.765 ;
     RECT  99.615 2.768 100.206 4.765 ;
     RECT  128.664 3.029 128.682 4.801 ;
     RECT  129.672 2.867 129.69 4.801 ;
     RECT  61.815 3.965 62.478 4.891 ;
     RECT  63.396 3.965 63.414 4.891 ;
     RECT  132.015 3.209 132.498 4.891 ;
     RECT  142.776 3.029 143.874 4.891 ;
     RECT  164.304 2.759 166.05 4.891 ;
     RECT  196.815 2.831 197.19 4.891 ;
     RECT  207.576 2.759 207.897 4.891 ;
     RECT  119.16 4.531 121.842 4.919 ;
     RECT  122.616 3.029 122.634 4.919 ;
     RECT  126.54 4.531 127.71 4.919 ;
     RECT  155.556 2.759 155.574 4.919 ;
     RECT  156.888 3.065 156.906 4.919 ;
     RECT  161.316 2.795 161.334 4.919 ;
     RECT  172.008 2.759 172.782 4.919 ;
     RECT  180.615 4.507 182.178 4.919 ;
     RECT  232.056 4.649 232.074 4.927 ;
     RECT  131.904 4.891 132.498 4.928 ;
     RECT  142.704 4.891 143.874 4.928 ;
     RECT  196.704 4.891 197.19 4.928 ;
     RECT  55.836 4.765 59.382 4.963 ;
     RECT  60.3 4.747 61.002 4.963 ;
     RECT  75.564 4.423 76.05 4.963 ;
     RECT  236.232 4.145 236.574 4.991 ;
     RECT  65.88 4.621 67.497 4.999 ;
     RECT  68.724 2.255 68.958 4.999 ;
     RECT  125.784 2.759 125.802 4.999 ;
     RECT  126.54 4.919 127.206 4.999 ;
     RECT  205.956 2.759 206.658 5.029 ;
     RECT  207.504 4.891 207.897 5.029 ;
     RECT  54.036 3.685 54.99 5.035 ;
     RECT  55.836 4.963 61.002 5.035 ;
     RECT  61.815 4.891 63.414 5.035 ;
     RECT  92.592 2.371 92.61 5.035 ;
     RECT  128.664 4.801 129.69 5.035 ;
     RECT  160.128 3.029 160.506 5.035 ;
     RECT  172.764 4.919 172.782 5.035 ;
     RECT  173.916 3.029 175.554 5.035 ;
     RECT  205.956 5.029 207.897 5.069 ;
     RECT  68.724 4.999 69.174 5.071 ;
     RECT  91.08 4.507 91.854 5.071 ;
     RECT  92.592 5.035 92.646 5.071 ;
     RECT  64.656 3.109 64.962 5.131 ;
     RECT  65.88 4.999 67.554 5.131 ;
     RECT  222.552 4.181 222.678 5.131 ;
     RECT  223.488 4.157 230.994 5.131 ;
     RECT  43.2 2.867 43.254 5.161 ;
     RECT  54.036 5.035 61.002 5.161 ;
     RECT  61.815 5.035 63.486 5.161 ;
     RECT  70.56 2.597 70.578 5.161 ;
     RECT  71.496 2.867 71.514 5.161 ;
     RECT  72.324 2.867 72.99 5.161 ;
     RECT  74.34 2.939 74.43 5.161 ;
     RECT  75.564 4.963 76.626 5.161 ;
     RECT  77.4 2.255 78.297 5.161 ;
     RECT  109.044 4.657 109.386 5.161 ;
     RECT  110.196 3.965 111.402 5.161 ;
     RECT  133.488 4.423 133.974 5.161 ;
     RECT  222.552 5.131 230.994 5.161 ;
     RECT  52.092 4.351 52.146 5.179 ;
     RECT  73.8 5.161 74.43 5.179 ;
     RECT  33.732 3.847 36.918 5.189 ;
     RECT  135.288 2.759 135.774 5.189 ;
     RECT  152.496 4.649 154.674 5.189 ;
     RECT  157.716 3.065 157.734 5.189 ;
     RECT  162.36 3.029 162.378 5.189 ;
     RECT  183.564 2.759 183.582 5.189 ;
     RECT  188.604 3.029 188.622 5.189 ;
     RECT  70.56 5.161 70.686 5.197 ;
     RECT  71.496 5.161 72.99 5.197 ;
     RECT  73.8 5.179 74.574 5.197 ;
     RECT  96.084 2.489 97.038 5.233 ;
     RECT  150.588 3.299 151.254 5.233 ;
     RECT  64.656 5.131 67.554 5.269 ;
     RECT  68.724 5.071 69.282 5.269 ;
     RECT  70.488 5.197 70.686 5.269 ;
     RECT  93.78 2.255 94.497 5.269 ;
     RECT  232.812 4.649 235.278 5.269 ;
     RECT  53.928 5.161 63.63 5.275 ;
     RECT  64.62 5.269 67.554 5.275 ;
     RECT  107.928 4.387 108.198 5.305 ;
     RECT  109.044 5.161 111.402 5.305 ;
     RECT  147.06 4.649 149.418 5.305 ;
     RECT  167.112 3.029 167.166 5.305 ;
     RECT  167.976 3.181 167.994 5.305 ;
     RECT  222.336 5.161 230.994 5.332 ;
     RECT  53.928 5.275 67.554 5.341 ;
     RECT  68.724 5.269 70.686 5.341 ;
     RECT  71.496 5.197 74.574 5.341 ;
     RECT  88.815 2.768 89.37 5.341 ;
     RECT  90.144 2.263 90.162 5.341 ;
     RECT  164.268 4.891 166.05 5.341 ;
     RECT  167.112 5.305 167.994 5.341 ;
     RECT  231.984 4.927 232.074 5.369 ;
     RECT  52.884 4.387 52.902 5.431 ;
     RECT  53.784 5.341 67.554 5.431 ;
     RECT  68.724 5.341 74.574 5.431 ;
     RECT  141.444 3.029 141.462 5.459 ;
     RECT  150.552 5.233 151.254 5.459 ;
     RECT  158.94 3.029 159.297 5.459 ;
     RECT  160.128 5.035 161.118 5.459 ;
     RECT  164.268 5.341 168.03 5.459 ;
     RECT  172.764 5.035 175.554 5.459 ;
     RECT  184.68 3.181 184.698 5.459 ;
     RECT  190.008 3.029 190.026 5.459 ;
     RECT  191.304 2.759 191.754 5.459 ;
     RECT  44.1 2.831 44.118 5.467 ;
     RECT  44.856 4.531 51.297 5.467 ;
     RECT  53.784 5.431 74.574 5.467 ;
     RECT  98.1 2.768 98.802 5.467 ;
     RECT  236.232 4.991 236.538 5.495 ;
     RECT  75.564 5.161 78.297 5.503 ;
     RECT  99.615 4.765 100.314 5.503 ;
     RECT  107.928 5.305 111.402 5.503 ;
     RECT  185.688 2.831 186.297 5.503 ;
     RECT  216.504 3.685 216.558 5.503 ;
     RECT  217.476 2.831 221.526 5.503 ;
     RECT  123.804 3.209 124.362 5.539 ;
     RECT  43.128 5.161 43.254 5.552 ;
     RECT  236.232 5.495 236.25 5.567 ;
     RECT  39.024 2.255 39.258 5.575 ;
     RECT  40.215 2.371 41.958 5.575 ;
     RECT  52.884 5.431 52.938 5.575 ;
     RECT  128.124 5.035 129.69 5.575 ;
     RECT  139.824 3.307 140.526 5.575 ;
     RECT  159.015 5.459 159.297 5.575 ;
     RECT  160.128 5.459 160.362 5.575 ;
     RECT  164.268 5.459 167.958 5.575 ;
     RECT  169.164 3.029 170.097 5.575 ;
     RECT  98.064 5.467 98.802 5.603 ;
     RECT  42.768 5.552 43.254 5.611 ;
     RECT  44.1 5.467 51.297 5.611 ;
     RECT  107.82 5.503 111.402 5.611 ;
     RECT  237.492 3.875 237.582 5.659 ;
     RECT  42.768 5.611 51.297 5.701 ;
     RECT  52.02 5.179 52.146 5.701 ;
     RECT  52.884 5.575 52.974 5.701 ;
     RECT  53.784 5.467 74.718 5.701 ;
     RECT  75.492 5.503 78.297 5.701 ;
     RECT  122.688 5.035 122.706 5.701 ;
     RECT  132.015 4.928 132.498 5.701 ;
     RECT  142.776 4.928 143.874 5.729 ;
     RECT  151.092 5.459 151.254 5.729 ;
     RECT  215.1 3.181 215.118 5.729 ;
     RECT  39.024 5.575 41.958 5.737 ;
     RECT  42.768 5.701 52.146 5.737 ;
     RECT  37.728 2.861 37.746 5.809 ;
     RECT  37.728 5.809 38.178 5.845 ;
     RECT  39.024 5.737 52.146 5.845 ;
     RECT  137.268 3.029 138.474 5.845 ;
     RECT  142.776 5.729 143.802 5.845 ;
     RECT  185.688 5.503 186.426 5.845 ;
     RECT  37.728 5.845 52.146 5.881 ;
     RECT  52.884 5.701 78.297 5.881 ;
     RECT  130.824 2.759 130.842 5.881 ;
     RECT  132.015 5.701 132.642 5.881 ;
     RECT  133.488 5.161 134.046 5.881 ;
     RECT  137.124 5.845 138.474 5.881 ;
     RECT  146.844 5.305 149.418 5.881 ;
     RECT  213.015 3.029 214.254 5.881 ;
     RECT  216.504 5.503 221.526 5.881 ;
     RECT  4.356 2.371 4.374 5.971 ;
     RECT  130.824 5.881 130.878 5.971 ;
     RECT  36.36 5.189 36.918 5.995 ;
     RECT  37.728 5.881 78.297 5.995 ;
     RECT  146.484 5.881 149.418 5.999 ;
     RECT  187.308 3.181 187.722 5.999 ;
     RECT  213.015 5.881 215.01 5.999 ;
     RECT  237.42 5.659 237.582 6.035 ;
     RECT  36.36 5.995 78.297 6.043 ;
     RECT  79.308 2.263 79.326 6.043 ;
     RECT  115.815 2.525 116.262 6.043 ;
     RECT  169.092 5.575 170.097 6.043 ;
     RECT  171.252 3.335 171.27 6.043 ;
     RECT  128.124 5.575 129.798 6.071 ;
     RECT  91.08 5.071 92.646 6.079 ;
     RECT  115.704 6.043 116.262 6.115 ;
     RECT  36.36 6.043 79.326 6.173 ;
     RECT  174.06 5.459 175.554 6.241 ;
     RECT  176.364 3.209 177.714 6.241 ;
     RECT  37.728 6.173 79.326 6.269 ;
     RECT  169.092 6.043 171.27 6.269 ;
     RECT  222.3 5.332 230.994 6.269 ;
     RECT  52.02 6.269 79.326 6.275 ;
     RECT  6.336 2.263 6.354 6.277 ;
     RECT  112.392 4.495 113.058 6.277 ;
     RECT  115.344 6.115 116.262 6.277 ;
     RECT  117.108 2.795 118.422 6.277 ;
     RECT  119.16 4.919 121.734 6.277 ;
     RECT  122.544 5.701 122.706 6.277 ;
     RECT  130.824 5.971 131.022 6.277 ;
     RECT  153.54 5.189 154.674 6.277 ;
     RECT  155.484 5.035 155.502 6.277 ;
     RECT  178.92 3.209 179.622 6.277 ;
     RECT  189.972 5.575 189.99 6.277 ;
     RECT  193.068 3.029 193.734 6.277 ;
     RECT  132.015 5.881 134.046 6.283 ;
     RECT  6.336 6.277 6.57 6.305 ;
     RECT  31.032 2.605 32.85 6.313 ;
     RECT  112.284 6.277 113.058 6.313 ;
     RECT  132.012 6.283 134.046 6.313 ;
     RECT  130.788 6.277 131.022 6.317 ;
     RECT  237.42 6.035 237.438 6.341 ;
     RECT  84.672 2.263 84.834 6.349 ;
     RECT  99.576 5.503 100.314 6.349 ;
     RECT  189.972 6.277 190.422 6.349 ;
     RECT  232.056 5.369 232.074 6.349 ;
     RECT  232.812 5.269 235.314 6.349 ;
     RECT  84.672 6.349 84.87 6.377 ;
     RECT  193.068 6.277 193.842 6.377 ;
     RECT  2.415 3.605 3.33 6.385 ;
     RECT  172.008 4.919 172.026 6.385 ;
     RECT  82.26 2.489 82.278 6.421 ;
     RECT  83.34 2.489 83.898 6.421 ;
     RECT  130.824 6.317 131.022 6.421 ;
     RECT  189.972 6.349 190.494 6.449 ;
     RECT  193.068 6.377 193.77 6.449 ;
     RECT  88.815 5.341 90.162 6.511 ;
     RECT  98.1 5.603 98.802 6.511 ;
     RECT  99.576 6.349 100.35 6.511 ;
     RECT  112.284 6.313 113.094 6.511 ;
     RECT  114.3 2.489 114.354 6.511 ;
     RECT  115.272 6.277 118.422 6.511 ;
     RECT  153.54 6.277 155.502 6.511 ;
     RECT  183.672 5.305 183.69 6.511 ;
     RECT  184.536 5.575 184.554 6.511 ;
     RECT  17.352 2.371 18.897 6.539 ;
     RECT  28.836 2.255 30.114 6.539 ;
     RECT  145.044 2.759 145.71 6.539 ;
     RECT  153.324 6.511 155.502 6.539 ;
     RECT  178.92 6.277 179.694 6.539 ;
     RECT  82.26 6.421 83.898 6.547 ;
     RECT  86.04 2.263 86.058 6.547 ;
     RECT  86.796 6.421 86.814 6.547 ;
     RECT  125.784 4.999 127.206 6.547 ;
     RECT  128.124 6.071 128.574 6.547 ;
     RECT  130.824 6.421 131.058 6.547 ;
     RECT  162.216 5.305 162.234 6.547 ;
     RECT  153.324 6.539 154.818 6.557 ;
     RECT  130.824 6.547 131.13 6.571 ;
     RECT  131.94 6.313 134.046 6.571 ;
     RECT  150.3 5.575 150.318 6.571 ;
     RECT  151.092 5.729 151.11 6.571 ;
     RECT  22.932 2.489 24.606 6.583 ;
     RECT  112.284 6.511 113.382 6.583 ;
     RECT  114.3 6.511 118.422 6.583 ;
     RECT  119.16 6.277 122.706 6.583 ;
     RECT  123.804 5.539 125.01 6.583 ;
     RECT  86.04 6.547 86.814 6.611 ;
     RECT  191.304 5.459 191.697 6.619 ;
     RECT  232.02 6.349 235.422 6.619 ;
     RECT  16.488 2.263 16.614 6.655 ;
     RECT  137.124 5.881 138.546 6.655 ;
     RECT  174.06 6.241 177.714 6.655 ;
     RECT  30.96 6.313 32.85 6.667 ;
     RECT  2.415 6.385 3.402 6.691 ;
     RECT  4.356 5.971 4.518 6.691 ;
     RECT  29.196 6.539 30.114 6.691 ;
     RECT  30.96 6.667 32.922 6.691 ;
     RECT  107.496 5.611 111.402 6.691 ;
     RECT  112.284 6.583 122.706 6.691 ;
     RECT  142.596 5.845 143.802 6.691 ;
     RECT  145.116 6.539 145.71 6.691 ;
     RECT  152.496 5.189 152.514 6.691 ;
     RECT  159.015 5.575 160.362 6.691 ;
     RECT  161.1 5.459 161.118 6.691 ;
     RECT  174.06 6.655 177.822 6.691 ;
     RECT  180.615 4.919 182.034 6.691 ;
     RECT  182.808 5.035 182.826 6.691 ;
     RECT  185.616 5.845 186.426 6.691 ;
     RECT  196.815 4.928 197.19 6.691 ;
     RECT  198 2.831 198.45 6.691 ;
     RECT  207.576 5.069 207.897 6.691 ;
     RECT  209.34 3.029 209.502 6.691 ;
     RECT  211.968 3.029 212.274 6.691 ;
     RECT  216.072 5.881 221.526 6.691 ;
     RECT  222.3 6.269 226.566 6.691 ;
     RECT  231.84 6.619 235.422 6.691 ;
     RECT  82.26 6.547 83.97 6.719 ;
     RECT  155.556 6.619 155.754 6.719 ;
     RECT  211.86 6.691 212.274 6.719 ;
     RECT  185.616 6.691 186.642 6.749 ;
     RECT  18.072 6.539 18.897 6.781 ;
     RECT  93.744 5.269 94.497 6.781 ;
     RECT  152.496 6.691 152.586 6.781 ;
     RECT  196.815 6.691 198.45 6.781 ;
     RECT  202.215 3.029 203.994 6.781 ;
     RECT  205.956 5.069 206.658 6.781 ;
     RECT  207.576 6.691 209.502 6.781 ;
     RECT  210.312 3.029 210.33 6.781 ;
     RECT  213.015 5.999 214.254 6.781 ;
     RECT  158.472 6.691 161.118 6.797 ;
     RECT  96.084 5.233 97.218 6.808 ;
     RECT  29.196 6.691 32.922 6.809 ;
     RECT  52.884 6.275 79.326 6.809 ;
     RECT  84.708 6.377 84.87 6.809 ;
     RECT  152.424 6.781 152.586 6.809 ;
     RECT  153.504 6.557 154.818 6.809 ;
     RECT  158.472 6.797 160.362 6.809 ;
     RECT  161.1 6.797 161.118 6.809 ;
     RECT  179.352 6.539 179.694 6.809 ;
     RECT  204.948 3.209 204.966 6.809 ;
     RECT  205.884 6.781 206.658 6.809 ;
     RECT  207.576 6.781 210.33 6.809 ;
     RECT  216.072 6.691 226.566 6.809 ;
     RECT  227.304 6.269 230.994 6.809 ;
     RECT  80.424 2.525 80.442 6.811 ;
     RECT  25.992 3.307 27.306 6.817 ;
     RECT  31.788 6.809 32.922 6.817 ;
     RECT  33.732 5.189 35.586 6.817 ;
     RECT  98.1 6.511 100.35 6.817 ;
     RECT  6.408 6.305 6.57 6.845 ;
     RECT  16.488 6.655 17.226 6.845 ;
     RECT  29.196 6.809 31.05 6.845 ;
     RECT  82.26 6.719 83.754 6.845 ;
     RECT  95.94 6.808 97.218 6.845 ;
     RECT  171.468 6.385 172.026 6.845 ;
     RECT  187.524 5.999 187.722 6.845 ;
     RECT  222.48 6.809 226.566 6.845 ;
     RECT  231.732 6.691 235.422 6.845 ;
     RECT  125.784 6.547 128.574 6.851 ;
     RECT  8.892 2.641 8.91 6.853 ;
     RECT  9.9 2.489 9.99 6.853 ;
     RECT  19.944 2.525 19.962 6.853 ;
     RECT  88.704 6.511 90.162 6.853 ;
     RECT  91.08 6.079 92.682 6.853 ;
     RECT  98.1 6.817 100.422 6.853 ;
     RECT  101.376 4.729 102.258 6.853 ;
     RECT  103.176 4.261 106.542 6.853 ;
     RECT  139.824 5.575 141.174 6.853 ;
     RECT  171.72 6.845 172.026 6.853 ;
     RECT  172.764 5.459 173.322 6.853 ;
     RECT  13.215 2.768 13.626 6.859 ;
     RECT  22.932 6.583 24.678 6.881 ;
     RECT  86.04 6.611 86.742 6.889 ;
     RECT  98.1 6.853 100.494 6.889 ;
     RECT  101.376 6.853 102.294 6.889 ;
     RECT  103.176 6.853 106.614 6.889 ;
     RECT  107.496 6.691 122.706 6.889 ;
     RECT  123.804 6.583 125.046 6.889 ;
     RECT  145.116 6.691 146.034 6.889 ;
     RECT  146.844 5.999 149.382 6.889 ;
     RECT  164.196 5.575 167.958 6.889 ;
     RECT  169.092 6.269 170.694 6.889 ;
     RECT  188.46 5.305 188.478 6.889 ;
     RECT  199.548 3.181 199.566 6.889 ;
     RECT  153.504 6.809 154.638 6.893 ;
     RECT  19.944 6.853 20.07 6.907 ;
     RECT  20.916 2.641 21.762 6.907 ;
     RECT  103.032 6.889 106.614 6.907 ;
     RECT  171.72 6.853 173.322 6.907 ;
     RECT  174.06 6.691 178.542 6.907 ;
     RECT  127.98 6.851 128.574 6.917 ;
     RECT  31.788 6.817 35.586 6.925 ;
     RECT  36.36 6.173 36.918 6.925 ;
     RECT  103.032 6.907 106.65 6.925 ;
     RECT  18.072 6.781 19.026 6.941 ;
     RECT  196.815 6.781 198.702 6.952 ;
     RECT  207.576 6.809 209.61 6.952 ;
     RECT  7.815 2.525 8.154 6.961 ;
     RECT  98.1 6.889 102.294 6.961 ;
     RECT  103.032 6.925 106.686 6.961 ;
     RECT  139.752 6.853 141.174 6.961 ;
     RECT  156.492 5.035 156.51 6.961 ;
     RECT  199.512 6.889 199.566 6.961 ;
     RECT  200.412 3.029 200.826 6.961 ;
     RECT  85.68 6.889 86.742 6.989 ;
     RECT  130.824 6.571 134.046 6.989 ;
     RECT  160.164 6.809 160.362 6.989 ;
     RECT  188.46 6.889 188.514 6.989 ;
     RECT  204.984 6.889 205.002 6.989 ;
     RECT  207.504 6.952 209.61 6.989 ;
     RECT  9.9 6.853 10.206 7.051 ;
     RECT  88.704 6.853 92.682 7.051 ;
     RECT  11.7 2.525 12.042 7.079 ;
     RECT  13.14 6.859 13.626 7.079 ;
     RECT  19.908 6.907 20.07 7.079 ;
     RECT  29.415 6.845 31.05 7.079 ;
     RECT  53.64 6.809 79.326 7.079 ;
     RECT  162.216 6.547 162.522 7.079 ;
     RECT  80.208 6.811 80.442 7.087 ;
     RECT  81.288 2.525 81.306 7.087 ;
     RECT  98.1 6.961 106.686 7.087 ;
     RECT  107.496 6.889 125.046 7.087 ;
     RECT  125.784 6.851 127.098 7.087 ;
     RECT  128.268 6.917 128.574 7.087 ;
     RECT  142.524 6.691 143.802 7.087 ;
     RECT  191.304 6.619 192.078 7.087 ;
     RECT  193.068 6.449 193.698 7.087 ;
     RECT  236.52 6.235 236.538 7.087 ;
     RECT  9.864 7.051 10.854 7.088 ;
     RECT  52.02 6.275 52.146 7.099 ;
     RECT  52.884 6.809 52.902 7.099 ;
     RECT  19.908 7.079 19.926 7.115 ;
     RECT  160.2 6.989 160.362 7.115 ;
     RECT  161.28 6.961 161.298 7.115 ;
     RECT  135.288 5.189 135.738 7.123 ;
     RECT  84.708 6.809 84.834 7.147 ;
     RECT  145.116 6.889 149.382 7.147 ;
     RECT  207.576 6.989 209.61 7.151 ;
     RECT  80.208 7.087 81.306 7.181 ;
     RECT  202.215 6.781 204.174 7.187 ;
     RECT  128.268 7.087 128.61 7.195 ;
     RECT  129.348 6.071 129.798 7.195 ;
     RECT  135.252 7.123 135.738 7.195 ;
     RECT  137.124 6.655 138.942 7.195 ;
     RECT  139.716 6.961 141.174 7.195 ;
     RECT  212.976 6.781 214.254 7.195 ;
     RECT  214.992 5.999 215.01 7.195 ;
     RECT  227.376 6.809 230.994 7.195 ;
     RECT  13.215 7.079 13.626 7.231 ;
     RECT  14.4 2.371 14.418 7.231 ;
     RECT  31.788 6.925 36.918 7.231 ;
     RECT  37.728 6.269 51.297 7.231 ;
     RECT  80.64 7.181 81.306 7.231 ;
     RECT  135.18 7.195 135.738 7.231 ;
     RECT  164.196 6.889 170.694 7.231 ;
     RECT  180.615 6.691 182.826 7.231 ;
     RECT  191.304 7.087 193.698 7.231 ;
     RECT  194.904 3.029 195.57 7.231 ;
     RECT  199.512 6.961 200.826 7.231 ;
     RECT  212.976 7.195 215.01 7.231 ;
     RECT  80.64 7.231 81.342 7.259 ;
     RECT  98.1 7.087 127.098 7.259 ;
     RECT  137.124 7.195 141.174 7.259 ;
     RECT  212.976 7.231 215.154 7.259 ;
     RECT  199.476 7.231 200.826 7.277 ;
     RECT  134.928 7.231 135.738 7.291 ;
     RECT  7.092 6.961 8.154 7.321 ;
     RECT  8.892 6.853 9.126 7.321 ;
     RECT  13.215 7.231 14.85 7.321 ;
     RECT  31.788 7.231 51.297 7.321 ;
     RECT  52.02 7.099 52.902 7.321 ;
     RECT  131.976 6.989 134.046 7.321 ;
     RECT  134.784 7.291 135.738 7.321 ;
     RECT  171.72 6.907 178.542 7.321 ;
     RECT  179.352 6.809 179.622 7.321 ;
     RECT  180.615 7.231 182.898 7.321 ;
     RECT  183.672 6.511 184.554 7.321 ;
     RECT  185.616 6.749 186.426 7.321 ;
     RECT  142.524 7.087 143.838 7.339 ;
     RECT  191.304 7.231 195.606 7.339 ;
     RECT  2.415 6.691 4.518 7.349 ;
     RECT  7.092 7.321 9.126 7.349 ;
     RECT  53.64 7.079 79.218 7.349 ;
     RECT  145.116 7.147 149.526 7.349 ;
     RECT  155.556 6.719 155.682 7.349 ;
     RECT  156.492 6.961 156.654 7.349 ;
     RECT  157.428 5.305 157.446 7.349 ;
     RECT  171.72 7.321 179.622 7.349 ;
     RECT  189.972 6.449 189.99 7.349 ;
     RECT  206.64 6.809 206.658 7.349 ;
     RECT  227.376 7.195 231.678 7.349 ;
     RECT  9.9 7.088 10.854 7.357 ;
     RECT  11.7 7.079 11.898 7.357 ;
     RECT  25.668 6.817 27.306 7.357 ;
     RECT  87.624 2.489 87.93 7.357 ;
     RECT  88.704 7.051 92.718 7.357 ;
     RECT  215.1 7.259 215.154 7.357 ;
     RECT  236.484 7.087 236.538 7.357 ;
     RECT  9.9 7.357 11.898 7.373 ;
     RECT  23.112 6.881 24.678 7.373 ;
     RECT  29.415 7.079 29.97 7.373 ;
     RECT  18.252 6.941 19.026 7.384 ;
     RECT  8.82 7.349 8.946 7.385 ;
     RECT  18.252 7.384 19.314 7.385 ;
     RECT  98.1 7.259 111.654 7.385 ;
     RECT  155.556 7.349 155.61 7.385 ;
     RECT  232.452 6.845 234.897 7.385 ;
     RECT  20.808 6.907 21.762 7.387 ;
     RECT  191.304 7.339 195.822 7.393 ;
     RECT  196.704 6.952 198.702 7.393 ;
     RECT  199.764 7.277 200.826 7.393 ;
     RECT  23.112 7.373 23.13 7.421 ;
     RECT  155.556 7.385 155.574 7.421 ;
     RECT  156.456 7.357 156.474 7.421 ;
     RECT  86.04 6.989 86.742 7.429 ;
     RECT  96.408 6.845 97.218 7.429 ;
     RECT  98.1 7.385 111.402 7.429 ;
     RECT  128.268 7.195 129.798 7.429 ;
     RECT  130.824 6.989 131.202 7.429 ;
     RECT  131.976 7.321 135.738 7.429 ;
     RECT  4.284 7.349 4.518 7.435 ;
     RECT  150.3 6.571 151.11 7.435 ;
     RECT  180.615 7.321 186.426 7.457 ;
     RECT  20.808 7.387 22.014 7.465 ;
     RECT  81.036 7.259 81.342 7.465 ;
     RECT  82.26 6.845 83.697 7.465 ;
     RECT  86.04 7.429 86.886 7.465 ;
     RECT  87.624 7.357 92.718 7.465 ;
     RECT  142.524 7.339 144.162 7.465 ;
     RECT  188.532 7.321 188.694 7.465 ;
     RECT  190.08 7.429 190.494 7.465 ;
     RECT  13.215 7.321 15.03 7.469 ;
     RECT  145.116 7.349 149.382 7.469 ;
     RECT  93.636 6.781 94.59 7.483 ;
     RECT  14.4 7.469 15.03 7.493 ;
     RECT  20.664 7.465 22.014 7.501 ;
     RECT  86.04 7.465 92.718 7.501 ;
     RECT  93.636 7.483 94.734 7.501 ;
     RECT  131.976 7.429 135.774 7.501 ;
     RECT  142.524 7.465 144.198 7.501 ;
     RECT  145.116 7.469 148.914 7.501 ;
     RECT  187.56 6.845 187.722 7.501 ;
     RECT  188.532 7.465 189.054 7.501 ;
     RECT  14.616 7.493 15.03 7.517 ;
     RECT  23.904 7.373 24.678 7.529 ;
     RECT  128.268 7.429 131.202 7.529 ;
     RECT  157.464 7.429 157.482 7.529 ;
     RECT  182.016 7.457 186.426 7.591 ;
     RECT  188.532 7.501 189.126 7.591 ;
     RECT  190.08 7.465 190.566 7.591 ;
     RECT  191.304 7.393 198.702 7.591 ;
     RECT  211.86 6.719 211.878 7.591 ;
     RECT  212.976 7.259 214.362 7.591 ;
     RECT  86.04 7.501 94.734 7.619 ;
     RECT  142.524 7.501 148.914 7.619 ;
     RECT  160.236 7.115 160.362 7.619 ;
     RECT  164.196 7.231 170.802 7.619 ;
     RECT  171.756 7.349 179.622 7.619 ;
     RECT  199.764 7.393 201.294 7.619 ;
     RECT  202.215 7.187 204.102 7.619 ;
     RECT  205.884 6.809 205.902 7.619 ;
     RECT  234.072 7.385 234.897 7.619 ;
     RECT  202.215 7.619 202.554 7.621 ;
     RECT  16.488 6.845 16.614 7.627 ;
     RECT  24.015 7.529 24.678 7.627 ;
     RECT  25.668 7.357 27.81 7.627 ;
     RECT  84.636 7.147 84.834 7.627 ;
     RECT  152.424 6.809 152.442 7.627 ;
     RECT  202.212 7.621 202.554 7.627 ;
     RECT  164.232 7.619 170.622 7.655 ;
     RECT  171.828 7.619 179.622 7.655 ;
     RECT  96.408 7.429 111.402 7.661 ;
     RECT  30.78 7.079 31.05 7.663 ;
     RECT  31.788 7.321 52.902 7.663 ;
     RECT  216.072 6.809 221.706 7.663 ;
     RECT  222.48 6.845 225.558 7.663 ;
     RECT  234.288 7.619 234.897 7.663 ;
     RECT  102.096 7.661 111.402 7.664 ;
     RECT  168.84 7.655 170.622 7.664 ;
     RECT  14.616 7.517 14.85 7.678 ;
     RECT  164.232 7.655 167.814 7.691 ;
     RECT  4.284 7.435 4.626 7.699 ;
     RECT  5.364 2.263 5.382 7.699 ;
     RECT  30.78 7.663 52.902 7.699 ;
     RECT  53.64 7.349 71.442 7.699 ;
     RECT  112.464 7.259 127.098 7.727 ;
     RECT  171.972 7.655 177.282 7.727 ;
     RECT  128.268 7.529 129.798 7.735 ;
     RECT  152.208 7.627 152.442 7.735 ;
     RECT  178.02 7.655 179.622 7.735 ;
     RECT  182.016 7.591 186.462 7.735 ;
     RECT  187.56 7.501 187.794 7.735 ;
     RECT  206.712 7.501 206.73 7.735 ;
     RECT  207.576 7.151 207.99 7.735 ;
     RECT  16.272 7.627 16.614 7.771 ;
     RECT  162.468 7.079 162.522 7.771 ;
     RECT  182.016 7.735 187.794 7.771 ;
     RECT  188.532 7.591 189.162 7.771 ;
     RECT  204.912 7.735 204.93 7.771 ;
     RECT  211.5 7.591 214.362 7.771 ;
     RECT  216.072 7.663 225.558 7.771 ;
     RECT  226.332 6.845 226.566 7.771 ;
     RECT  227.376 7.349 228.294 7.771 ;
     RECT  232.452 7.385 233.334 7.771 ;
     RECT  9.9 7.373 11.718 7.799 ;
     RECT  30.78 7.699 71.442 7.799 ;
     RECT  140.076 7.259 141.174 7.799 ;
     RECT  145.836 7.619 146.718 7.799 ;
     RECT  234.288 7.663 234.954 7.799 ;
     RECT  20.664 7.501 22.23 7.805 ;
     RECT  128.16 7.735 129.798 7.805 ;
     RECT  140.22 7.799 141.174 7.819 ;
     RECT  152.208 7.735 152.694 7.819 ;
     RECT  153.504 6.893 154.566 7.819 ;
     RECT  4.284 7.699 5.382 7.861 ;
     RECT  20.772 7.805 22.23 7.861 ;
     RECT  137.124 7.259 139.194 7.861 ;
     RECT  158.472 6.809 159.426 7.861 ;
     RECT  160.236 7.619 160.254 7.861 ;
     RECT  178.02 7.735 179.694 7.861 ;
     RECT  180.615 7.457 181.17 7.861 ;
     RECT  2.415 7.349 3.33 7.889 ;
     RECT  96.408 7.661 100.998 7.889 ;
     RECT  131.976 7.501 135.846 7.889 ;
     RECT  147.492 7.619 148.914 7.889 ;
     RECT  150.156 7.435 151.11 7.889 ;
     RECT  152.064 7.819 154.566 7.889 ;
     RECT  162.468 7.771 163.35 7.889 ;
     RECT  168.84 7.664 170.586 7.889 ;
     RECT  190.08 7.591 198.702 7.889 ;
     RECT  206.712 7.735 207.99 7.889 ;
     RECT  216.036 7.771 228.294 7.889 ;
     RECT  229.068 7.349 230.994 7.889 ;
     RECT  137.088 7.861 139.194 7.897 ;
     RECT  147.492 7.889 148.59 7.901 ;
     RECT  204.912 7.771 205.794 7.901 ;
     RECT  226.548 7.889 228.294 7.901 ;
     RECT  136.908 7.897 139.194 7.915 ;
     RECT  10.224 7.799 11.718 7.925 ;
     RECT  14.796 7.678 14.85 7.925 ;
     RECT  20.772 7.861 22.374 7.925 ;
     RECT  24.015 7.627 27.81 7.925 ;
     RECT  164.268 7.691 167.814 7.925 ;
     RECT  205.164 7.901 205.794 7.925 ;
     RECT  227.88 7.901 228.294 7.925 ;
     RECT  18.288 7.385 19.314 7.933 ;
     RECT  234.324 7.799 234.954 7.933 ;
     RECT  235.944 7.357 236.538 7.933 ;
     RECT  123.588 7.727 127.098 7.949 ;
     RECT  128.268 7.805 129.798 7.949 ;
     RECT  136.188 7.915 139.194 7.949 ;
     RECT  140.22 7.819 141.498 7.949 ;
     RECT  145.908 7.799 146.718 7.949 ;
     RECT  148.176 7.901 148.59 7.949 ;
     RECT  150.156 7.889 151.074 7.949 ;
     RECT  182.016 7.771 189.162 7.949 ;
     RECT  229.215 7.889 230.994 7.949 ;
     RECT  30.888 7.799 71.442 7.961 ;
     RECT  162.468 7.889 163.206 7.961 ;
     RECT  171.972 7.727 177.246 7.961 ;
     RECT  182.016 7.949 188.91 7.961 ;
     RECT  210.348 6.889 210.366 7.963 ;
     RECT  211.464 7.771 214.362 7.963 ;
     RECT  153.144 7.889 154.566 7.969 ;
     RECT  2.415 7.889 3.15 7.997 ;
     RECT  4.284 7.861 5.706 7.997 ;
     RECT  18.288 7.933 19.422 7.997 ;
     RECT  20.844 7.925 22.374 7.997 ;
     RECT  102.204 7.664 111.402 7.997 ;
     RECT  162.504 7.961 163.206 7.997 ;
     RECT  164.268 7.925 164.826 7.997 ;
     RECT  172.692 7.961 177.246 7.997 ;
     RECT  196.74 7.889 198.702 7.997 ;
     RECT  210.348 7.963 214.362 7.997 ;
     RECT  231.984 7.771 233.334 7.997 ;
     RECT  86.184 7.619 94.734 8.005 ;
     RECT  112.464 7.727 122.85 8.011 ;
     RECT  29.415 7.373 29.697 8.041 ;
     RECT  207 7.889 207.99 8.041 ;
     RECT  209.34 7.151 209.61 8.041 ;
     RECT  72.18 7.349 79.218 8.045 ;
     RECT  190.08 7.889 195.822 8.069 ;
     RECT  81.036 7.465 83.697 8.131 ;
     RECT  131.976 7.889 135.306 8.131 ;
     RECT  15.948 7.771 16.614 8.159 ;
     RECT  20.844 7.997 22.194 8.159 ;
     RECT  53.64 7.961 71.442 8.159 ;
     RECT  123.624 7.949 127.098 8.159 ;
     RECT  136.188 7.949 136.35 8.159 ;
     RECT  153.144 7.969 154.602 8.159 ;
     RECT  158.472 7.861 160.254 8.159 ;
     RECT  165.6 7.925 167.382 8.159 ;
     RECT  178.02 7.861 181.17 8.159 ;
     RECT  190.08 8.069 193.734 8.159 ;
     RECT  194.904 8.069 195.822 8.159 ;
     RECT  232.236 7.997 232.398 8.159 ;
     RECT  86.184 8.005 95.202 8.189 ;
     RECT  96.48 7.889 100.998 8.189 ;
     RECT  196.74 7.997 197.946 8.189 ;
     RECT  10.476 7.925 11.718 8.195 ;
     RECT  15.948 8.159 16.29 8.195 ;
     RECT  20.844 8.159 22.014 8.195 ;
     RECT  130.536 7.529 131.202 8.195 ;
     RECT  182.016 7.961 187.866 8.195 ;
     RECT  216.036 7.889 225.666 8.195 ;
     RECT  232.236 8.159 232.254 8.195 ;
     RECT  80.424 8.131 83.697 8.203 ;
     RECT  142.524 7.619 145.062 8.203 ;
     RECT  233.172 7.997 233.334 8.203 ;
     RECT  153.144 8.159 154.566 8.231 ;
     RECT  158.472 8.159 159.894 8.231 ;
     RECT  178.02 8.159 178.686 8.231 ;
     RECT  234.324 7.933 236.538 8.231 ;
     RECT  11.376 8.195 11.718 8.237 ;
     RECT  112.392 8.011 122.85 8.237 ;
     RECT  80.388 8.203 83.697 8.239 ;
     RECT  75.24 8.045 79.218 8.251 ;
     RECT  93.744 8.189 95.202 8.267 ;
     RECT  96.588 8.189 100.998 8.267 ;
     RECT  75.24 8.251 79.254 8.275 ;
     RECT  80.064 8.239 83.697 8.275 ;
     RECT  84.636 7.627 85.194 8.275 ;
     RECT  233.172 8.203 233.478 8.285 ;
     RECT  123.624 8.159 123.822 8.303 ;
     RECT  165.744 8.159 167.382 8.303 ;
     RECT  18.288 7.997 18.897 8.311 ;
     RECT  104.004 7.997 111.402 8.311 ;
     RECT  112.392 8.237 122.67 8.311 ;
     RECT  140.256 7.949 141.498 8.311 ;
     RECT  179.532 8.159 181.17 8.311 ;
     RECT  182.016 8.195 186.822 8.311 ;
     RECT  207 8.041 208.026 8.311 ;
     RECT  208.872 8.041 209.61 8.311 ;
     RECT  210.348 7.997 211.626 8.311 ;
     RECT  215.1 7.357 215.226 8.311 ;
     RECT  14.796 7.925 14.814 8.333 ;
     RECT  142.416 8.203 145.062 8.339 ;
     RECT  178.02 8.231 178.506 8.339 ;
     RECT  187.596 8.195 187.866 8.339 ;
     RECT  11.448 8.237 11.718 8.429 ;
     RECT  150.3 7.949 151.074 8.429 ;
     RECT  164.415 7.997 164.826 8.429 ;
     RECT  165.744 8.303 166.266 8.429 ;
     RECT  169.272 7.889 170.586 8.429 ;
     RECT  179.532 8.311 186.822 8.429 ;
     RECT  187.596 8.339 187.614 8.429 ;
     RECT  203.328 7.619 204.102 8.429 ;
     RECT  207 8.311 211.626 8.429 ;
     RECT  216.396 8.195 225.666 8.429 ;
     RECT  226.548 7.901 227.106 8.429 ;
     RECT  227.88 7.925 227.898 8.429 ;
     RECT  230.292 7.949 230.994 8.429 ;
     RECT  4.284 7.997 4.554 8.465 ;
     RECT  5.328 7.997 5.706 8.465 ;
     RECT  11.448 8.429 11.538 8.465 ;
     RECT  15.948 8.195 16.182 8.465 ;
     RECT  26.604 7.925 27.81 8.465 ;
     RECT  137.088 7.949 139.194 8.465 ;
     RECT  167.04 8.303 167.382 8.465 ;
     RECT  188.712 7.961 188.838 8.465 ;
     RECT  212.4 7.997 214.362 8.465 ;
     RECT  215.1 8.311 215.55 8.465 ;
     RECT  234.324 8.231 235.962 8.465 ;
     RECT  124.632 8.159 127.098 8.477 ;
     RECT  165.78 8.429 166.266 8.477 ;
     RECT  190.08 8.159 192.618 8.491 ;
     RECT  93.744 8.267 94.77 8.501 ;
     RECT  165.78 8.477 166.05 8.501 ;
     RECT  13.215 7.469 13.497 8.509 ;
     RECT  28.728 8.041 29.697 8.509 ;
     RECT  199.764 7.619 200.754 8.509 ;
     RECT  16.128 8.465 16.182 8.525 ;
     RECT  93.744 8.501 94.734 8.525 ;
     RECT  189.684 8.491 192.618 8.525 ;
     RECT  130.608 8.195 131.202 8.536 ;
     RECT  131.94 8.131 135.306 8.536 ;
     RECT  5.364 8.465 5.706 8.537 ;
     RECT  123.624 8.303 123.714 8.537 ;
     RECT  128.736 7.949 129.798 8.537 ;
     RECT  164.415 8.429 164.754 8.537 ;
     RECT  165.78 8.501 166.014 8.537 ;
     RECT  180.072 8.429 184.77 8.537 ;
     RECT  212.472 8.465 214.362 8.545 ;
     RECT  215.1 8.465 215.478 8.545 ;
     RECT  181.8 8.537 184.77 8.573 ;
     RECT  202.176 7.627 202.554 8.581 ;
     RECT  123.696 8.537 123.714 8.609 ;
     RECT  212.472 8.545 215.478 8.609 ;
     RECT  24.015 7.925 25.83 8.671 ;
     RECT  75.24 8.275 85.194 8.671 ;
     RECT  86.184 8.189 92.754 8.671 ;
     RECT  126.504 8.477 127.098 8.671 ;
     RECT  144.18 8.339 145.062 8.671 ;
     RECT  234.324 8.465 234.897 8.671 ;
     RECT  167.04 8.465 167.346 8.699 ;
     RECT  185.508 8.429 186.822 8.699 ;
     RECT  207.54 8.429 211.518 8.699 ;
     RECT  216.396 8.429 225.45 8.699 ;
     RECT  158.472 8.231 159.642 8.717 ;
     RECT  102.204 7.997 103.194 8.731 ;
     RECT  104.004 8.311 122.67 8.731 ;
     RECT  8.82 7.385 8.838 8.735 ;
     RECT  17.64 8.311 18.897 8.735 ;
     RECT  21.384 8.195 21.726 8.735 ;
     RECT  130.608 8.536 135.306 8.735 ;
     RECT  212.472 8.609 215.226 8.735 ;
     RECT  23.148 8.311 23.166 8.743 ;
     RECT  23.904 8.671 25.83 8.743 ;
     RECT  226.548 8.429 226.962 8.743 ;
     RECT  128.844 8.537 129.798 8.765 ;
     RECT  30.888 7.961 52.758 8.771 ;
     RECT  30.888 8.771 39.186 8.779 ;
     RECT  153.144 8.231 154.494 8.779 ;
     RECT  124.632 8.477 125.766 8.807 ;
     RECT  150.3 8.429 150.318 8.807 ;
     RECT  162.504 7.997 162.522 8.807 ;
     RECT  167.04 8.699 167.31 8.807 ;
     RECT  172.728 7.997 177.246 8.807 ;
     RECT  178.38 8.339 178.506 8.807 ;
     RECT  153.108 8.779 154.494 8.813 ;
     RECT  206.352 8.683 206.406 8.813 ;
     RECT  26.604 8.465 27.342 8.815 ;
     RECT  198.684 7.997 198.702 8.815 ;
     RECT  199.764 8.509 201.186 8.815 ;
     RECT  201.924 8.581 202.554 8.815 ;
     RECT  137.088 8.465 138.222 8.827 ;
     RECT  178.488 8.807 178.506 8.843 ;
     RECT  23.148 8.743 25.83 8.851 ;
     RECT  98.352 8.267 100.998 8.851 ;
     RECT  144.18 8.671 145.206 8.851 ;
     RECT  145.944 7.949 146.214 8.851 ;
     RECT  173.304 8.807 177.246 8.851 ;
     RECT  229.215 7.949 229.497 8.851 ;
     RECT  128.844 8.765 129.042 8.861 ;
     RECT  22.788 8.851 25.83 8.909 ;
     RECT  153.108 8.813 153.897 8.909 ;
     RECT  39.924 8.771 52.758 8.941 ;
     RECT  98.352 8.851 101.178 8.941 ;
     RECT  136.548 8.827 138.222 8.941 ;
     RECT  234.288 8.671 234.897 8.941 ;
     RECT  128.88 8.861 129.042 8.957 ;
     RECT  53.64 8.159 65.07 8.969 ;
     RECT  173.304 8.851 177.534 8.969 ;
     RECT  198.36 8.815 198.702 8.969 ;
     RECT  216.396 8.699 224.874 8.969 ;
     RECT  226.296 8.743 226.962 8.969 ;
     RECT  229.104 8.851 229.497 8.969 ;
     RECT  72.216 8.045 74.466 8.977 ;
     RECT  75.24 8.671 92.754 8.977 ;
     RECT  98.352 8.941 101.322 8.977 ;
     RECT  216.396 8.969 224.838 8.977 ;
     RECT  5.688 8.537 5.706 9.005 ;
     RECT  134.892 8.735 135.306 9.005 ;
     RECT  185.508 8.699 186.75 9.005 ;
     RECT  208.764 8.699 211.518 9.005 ;
     RECT  231.552 8.941 231.57 9.005 ;
     RECT  144.18 8.851 146.214 9.019 ;
     RECT  53.676 8.969 65.07 9.041 ;
     RECT  128.88 8.957 129.006 9.041 ;
     RECT  134.892 9.005 135.234 9.041 ;
     RECT  181.8 8.573 184.59 9.041 ;
     RECT  226.332 8.969 226.962 9.041 ;
     RECT  102.204 8.731 122.67 9.049 ;
     RECT  18.468 8.735 18.897 9.053 ;
     RECT  53.676 9.041 64.782 9.077 ;
     RECT  136.296 8.941 138.222 9.077 ;
     RECT  209.412 9.005 211.518 9.077 ;
     RECT  188.748 8.465 188.838 9.085 ;
     RECT  189.684 8.525 189.702 9.085 ;
     RECT  194.904 8.159 195.606 9.085 ;
     RECT  196.74 8.189 197.514 9.085 ;
     RECT  230.292 8.429 230.31 9.085 ;
     RECT  128.88 9.041 128.97 9.113 ;
     RECT  136.44 9.077 138.222 9.113 ;
     RECT  173.304 8.969 173.322 9.113 ;
     RECT  174.096 8.969 177.534 9.113 ;
     RECT  188.748 9.085 189.702 9.113 ;
     RECT  206.388 8.813 206.406 9.113 ;
     RECT  233.928 8.941 234.897 9.113 ;
     RECT  28.26 8.509 29.697 9.115 ;
     RECT  30.78 8.779 39.186 9.115 ;
     RECT  129.78 8.765 129.798 9.115 ;
     RECT  130.608 8.735 134.118 9.115 ;
     RECT  151.056 8.429 151.074 9.115 ;
     RECT  228.168 8.779 228.366 9.115 ;
     RECT  39.924 8.941 52.83 9.121 ;
     RECT  96.588 8.267 97.506 9.121 ;
     RECT  140.256 8.311 141.57 9.121 ;
     RECT  142.416 8.339 143.298 9.121 ;
     RECT  144.18 9.019 146.394 9.121 ;
     RECT  147.204 8.539 147.222 9.121 ;
     RECT  148.176 7.949 148.497 9.121 ;
     RECT  128.88 9.113 128.898 9.149 ;
     RECT  174.996 9.113 177.534 9.149 ;
     RECT  181.8 9.041 184.446 9.149 ;
     RECT  212.616 8.735 215.226 9.149 ;
     RECT  126.504 8.671 127.242 9.155 ;
     RECT  65.916 8.159 71.406 9.163 ;
     RECT  140.076 9.121 141.57 9.163 ;
     RECT  142.416 9.121 143.37 9.163 ;
     RECT  72.216 8.977 92.754 9.205 ;
     RECT  98.352 8.977 101.466 9.211 ;
     RECT  102.204 9.049 122.958 9.211 ;
     RECT  203.4 8.429 204.102 9.211 ;
     RECT  65.556 9.163 71.406 9.239 ;
     RECT  72.144 9.205 92.754 9.239 ;
     RECT  151.056 9.115 151.794 9.239 ;
     RECT  174.096 9.113 174.258 9.239 ;
     RECT  181.8 9.149 183.654 9.239 ;
     RECT  184.428 9.149 184.446 9.239 ;
     RECT  185.616 9.005 186.75 9.239 ;
     RECT  214.056 9.149 215.226 9.239 ;
     RECT  228.168 9.115 228.474 9.239 ;
     RECT  96.588 9.121 97.614 9.247 ;
     RECT  98.352 9.211 122.958 9.247 ;
     RECT  144.144 9.121 146.394 9.247 ;
     RECT  147.132 9.121 148.806 9.247 ;
     RECT  193.716 8.159 193.734 9.247 ;
     RECT  11.448 8.465 11.466 9.275 ;
     RECT  199.764 8.815 202.554 9.275 ;
     RECT  96.588 9.247 122.958 9.283 ;
     RECT  139.032 8.465 139.194 9.283 ;
     RECT  140.076 9.163 143.37 9.283 ;
     RECT  151.56 9.239 151.794 9.283 ;
     RECT  152.748 9.121 152.838 9.283 ;
     RECT  216.252 8.977 224.838 9.283 ;
     RECT  216.18 9.283 224.838 9.311 ;
     RECT  190.584 8.525 192.618 9.319 ;
     RECT  136.584 9.113 138.222 9.355 ;
     RECT  139.032 9.283 143.37 9.355 ;
     RECT  165.888 8.537 166.014 9.355 ;
     RECT  190.512 9.319 192.618 9.355 ;
     RECT  193.716 9.247 193.806 9.355 ;
     RECT  159.015 8.717 159.642 9.383 ;
     RECT  190.44 9.355 192.618 9.383 ;
     RECT  198.684 8.969 198.702 9.383 ;
     RECT  28.26 9.115 39.186 9.389 ;
     RECT  65.808 9.239 71.406 9.391 ;
     RECT  72.144 9.239 85.158 9.391 ;
     RECT  216.18 9.311 224.658 9.391 ;
     RECT  226.548 9.041 226.962 9.391 ;
     RECT  6.228 9.121 6.246 9.419 ;
     RECT  233.136 8.779 233.154 9.419 ;
     RECT  26.568 8.815 27.342 9.437 ;
     RECT  65.808 9.391 85.158 9.437 ;
     RECT  96.588 9.283 123.246 9.481 ;
     RECT  165.816 9.355 166.014 9.481 ;
     RECT  202.032 9.275 202.554 9.481 ;
     RECT  203.292 9.211 204.102 9.481 ;
     RECT  229.215 8.969 229.497 9.481 ;
     RECT  230.256 9.085 230.31 9.481 ;
     RECT  93.744 8.525 94.698 9.499 ;
     RECT  165.816 9.481 166.122 9.509 ;
     RECT  167.04 8.807 167.058 9.509 ;
     RECT  188.748 9.113 189.198 9.509 ;
     RECT  191.415 9.383 192.618 9.509 ;
     RECT  193.716 9.355 193.986 9.509 ;
     RECT  226.548 9.391 227.322 9.509 ;
     RECT  228.456 9.239 228.474 9.509 ;
     RECT  169.815 8.429 170.586 9.517 ;
     RECT  151.56 9.283 152.838 9.545 ;
     RECT  165.888 9.509 166.122 9.545 ;
     RECT  175.032 9.149 177.534 9.545 ;
     RECT  193.788 9.509 193.806 9.545 ;
     RECT  126.615 9.155 127.242 9.553 ;
     RECT  128.124 9.481 128.142 9.553 ;
     RECT  214.2 9.239 215.226 9.553 ;
     RECT  229.215 9.481 230.31 9.581 ;
     RECT  207.54 8.699 207.954 9.589 ;
     RECT  17.64 8.735 17.658 9.617 ;
     RECT  214.2 9.553 215.262 9.625 ;
     RECT  216.072 9.391 224.658 9.625 ;
     RECT  93.744 9.499 94.734 9.629 ;
     RECT  202.032 9.481 204.102 9.629 ;
     RECT  7.092 7.349 8.097 9.643 ;
     RECT  136.584 9.355 143.37 9.643 ;
     RECT  144.144 9.247 148.842 9.643 ;
     RECT  190.44 9.383 190.638 9.643 ;
     RECT  188.784 9.509 189.198 9.677 ;
     RECT  7.092 9.643 8.298 9.689 ;
     RECT  189.972 9.643 190.638 9.689 ;
     RECT  209.52 9.077 211.518 9.689 ;
     RECT  126.615 9.553 128.142 9.739 ;
     RECT  30.6 9.389 39.186 9.751 ;
     RECT  39.924 9.121 52.902 9.751 ;
     RECT  95.904 9.481 123.246 9.751 ;
     RECT  180.072 8.537 180.897 9.751 ;
     RECT  165.996 9.545 166.122 9.779 ;
     RECT  175.215 9.545 177.534 9.779 ;
     RECT  181.8 9.239 181.998 9.779 ;
     RECT  185.616 9.239 186.714 9.779 ;
     RECT  194.904 9.085 197.514 9.779 ;
     RECT  199.764 9.275 201.186 9.779 ;
     RECT  136.584 9.643 148.842 9.787 ;
     RECT  149.868 9.751 149.886 9.787 ;
     RECT  167.004 9.625 167.022 9.787 ;
     RECT  199.764 9.779 200.574 9.787 ;
     RECT  190.044 9.689 190.638 9.815 ;
     RECT  202.215 9.629 204.102 9.815 ;
     RECT  211.104 9.689 211.518 9.815 ;
     RECT  95.904 9.751 123.498 9.823 ;
     RECT  124.848 8.807 125.766 9.823 ;
     RECT  179.568 9.751 180.897 9.823 ;
     RECT  129.78 9.115 134.118 9.835 ;
     RECT  134.892 9.041 135.162 9.835 ;
     RECT  136.584 9.787 149.886 9.851 ;
     RECT  181.98 9.779 181.998 9.851 ;
     RECT  30.6 9.751 52.902 9.859 ;
     RECT  53.676 9.077 64.71 9.859 ;
     RECT  126.615 9.739 128.682 9.883 ;
     RECT  23.328 8.909 25.83 9.895 ;
     RECT  26.568 9.437 26.802 9.895 ;
     RECT  126.504 9.883 128.682 9.895 ;
     RECT  129.78 9.835 135.162 9.895 ;
     RECT  179.136 9.823 180.897 9.895 ;
     RECT  195.48 9.779 197.514 9.895 ;
     RECT  10.476 8.195 10.494 9.917 ;
     RECT  203.364 9.815 204.102 9.923 ;
     RECT  141.732 9.851 149.886 9.931 ;
     RECT  179.136 9.895 180.954 9.931 ;
     RECT  212.616 9.149 213.297 9.959 ;
     RECT  30.6 9.859 64.71 10.021 ;
     RECT  65.808 9.437 71.298 10.021 ;
     RECT  72.072 9.437 85.158 10.021 ;
     RECT  86.004 9.239 92.754 10.021 ;
     RECT  151.632 9.545 152.838 10.021 ;
     RECT  153.615 8.909 153.897 10.021 ;
     RECT  199.512 9.787 200.574 10.021 ;
     RECT  234.615 9.113 234.897 10.027 ;
     RECT  235.944 8.465 235.962 10.027 ;
     RECT  72.072 10.021 92.754 10.049 ;
     RECT  166.932 9.787 167.022 10.049 ;
     RECT  178.956 9.931 180.954 10.049 ;
     RECT  199.152 10.021 200.574 10.049 ;
     RECT  209.52 9.689 210.294 10.049 ;
     RECT  166.932 10.049 166.95 10.085 ;
     RECT  190.26 9.815 190.638 10.085 ;
     RECT  207.144 9.589 207.954 10.085 ;
     RECT  126.504 9.895 135.162 10.093 ;
     RECT  214.2 9.625 224.658 10.109 ;
     RECT  95.904 9.823 125.766 10.129 ;
     RECT  126.504 10.093 135.234 10.129 ;
     RECT  141.732 9.931 149.922 10.129 ;
     RECT  169.815 9.517 170.694 10.157 ;
     RECT  175.215 9.779 176.202 10.157 ;
     RECT  178.956 10.049 179.01 10.157 ;
     RECT  179.748 10.049 180.954 10.157 ;
     RECT  184.752 9.895 184.77 10.157 ;
     RECT  95.904 10.129 135.234 10.171 ;
     RECT  203.364 9.923 203.562 10.193 ;
     RECT  30.6 10.021 64.746 10.201 ;
     RECT  141.732 10.129 150.606 10.201 ;
     RECT  207.216 10.085 207.954 10.201 ;
     RECT  207.216 10.201 208.278 10.205 ;
     RECT  174.42 9.931 174.438 10.229 ;
     RECT  179.82 10.157 180.954 10.229 ;
     RECT  72.072 10.049 90.702 10.253 ;
     RECT  178.992 10.157 179.01 10.253 ;
     RECT  30.42 10.201 64.746 10.267 ;
     RECT  65.664 10.021 71.298 10.267 ;
     RECT  95.796 10.171 135.234 10.267 ;
     RECT  195.48 9.895 197.874 10.291 ;
     RECT  199.152 10.049 200.502 10.291 ;
     RECT  234.615 10.027 235.962 10.291 ;
     RECT  234.036 10.291 235.962 10.315 ;
     RECT  85.608 10.253 90.702 10.319 ;
     RECT  95.796 10.267 135.666 10.319 ;
     RECT  179.856 10.229 180.954 10.319 ;
     RECT  195.48 10.291 200.502 10.319 ;
     RECT  207.252 10.205 208.278 10.319 ;
     RECT  233.136 10.201 233.154 10.319 ;
     RECT  12.564 8.509 13.497 10.355 ;
     RECT  202.215 9.815 202.554 10.355 ;
     RECT  225.648 10.315 225.666 10.355 ;
     RECT  226.548 9.509 226.962 10.355 ;
     RECT  234.036 10.315 236.538 10.355 ;
     RECT  30.42 10.267 71.298 10.363 ;
     RECT  191.415 9.509 191.826 10.363 ;
     RECT  192.6 9.509 192.618 10.363 ;
     RECT  215.208 10.109 224.658 10.391 ;
     RECT  234.036 10.355 235.962 10.391 ;
     RECT  21.384 8.735 21.402 10.397 ;
     RECT  28.26 9.389 29.697 10.411 ;
     RECT  30.42 10.363 71.334 10.411 ;
     RECT  72.072 10.253 84.798 10.427 ;
     RECT  28.26 10.411 71.334 10.435 ;
     RECT  72.072 10.427 73.746 10.435 ;
     RECT  191.415 10.363 192.618 10.435 ;
     RECT  194.688 10.165 194.706 10.435 ;
     RECT  205.164 7.925 205.182 10.463 ;
     RECT  13.215 10.355 13.497 10.471 ;
     RECT  141.732 10.201 150.642 10.471 ;
     RECT  227.736 10.363 227.754 10.471 ;
     RECT  225.396 10.411 225.414 10.499 ;
     RECT  28.26 10.435 73.746 10.541 ;
     RECT  141.732 10.471 150.894 10.555 ;
     RECT  151.632 10.021 153.897 10.555 ;
     RECT  141.732 10.555 153.897 10.561 ;
     RECT  155.016 10.435 155.034 10.561 ;
     RECT  190.476 10.085 190.638 10.561 ;
     RECT  191.415 10.435 192.762 10.561 ;
     RECT  226.548 10.355 226.674 10.561 ;
     RECT  230.832 10.471 230.85 10.561 ;
     RECT  179.856 10.319 180.897 10.589 ;
     RECT  207.54 10.319 208.278 10.589 ;
     RECT  136.584 9.851 140.994 10.625 ;
     RECT  207.54 10.589 208.206 10.625 ;
     RECT  227.736 10.471 227.97 10.625 ;
     RECT  93.744 9.629 94.662 10.633 ;
     RECT  136.62 10.625 140.994 10.633 ;
     RECT  141.732 10.561 155.07 10.633 ;
     RECT  226.368 10.561 226.674 10.661 ;
     RECT  227.952 10.625 227.97 10.661 ;
     RECT  230.832 10.561 230.886 10.661 ;
     RECT  4.536 8.465 4.554 10.697 ;
     RECT  209.52 10.049 210.258 10.697 ;
     RECT  230.832 10.661 230.85 10.697 ;
     RECT  229.215 9.581 229.878 10.733 ;
     RECT  226.368 10.661 226.566 10.769 ;
     RECT  216.468 10.391 224.658 10.795 ;
     RECT  179.856 10.589 179.874 10.829 ;
     RECT  159.015 9.383 159.297 10.843 ;
     RECT  195.516 10.319 200.502 10.859 ;
     RECT  190.476 10.561 192.762 10.867 ;
     RECT  136.62 10.633 155.07 10.895 ;
     RECT  93.744 10.633 94.734 10.903 ;
     RECT  95.796 10.319 135.63 10.903 ;
     RECT  189.864 10.867 192.762 10.939 ;
     RECT  194.436 10.435 194.706 10.939 ;
     RECT  195.516 10.859 197.097 10.967 ;
     RECT  74.556 10.427 84.798 10.975 ;
     RECT  85.608 10.319 90.666 10.975 ;
     RECT  214.2 10.109 214.218 10.975 ;
     RECT  229.215 10.733 229.698 10.975 ;
     RECT  155.304 10.975 155.322 11.011 ;
     RECT  228.996 10.975 229.698 11.021 ;
     RECT  230.58 10.867 230.598 11.039 ;
     RECT  194.292 10.939 194.706 11.101 ;
     RECT  214.2 10.975 214.398 11.129 ;
     RECT  189.864 10.939 193.23 11.132 ;
     RECT  13.215 10.471 13.662 11.165 ;
     RECT  23.328 9.895 26.802 11.173 ;
     RECT  30.42 10.541 73.746 11.173 ;
     RECT  74.556 10.975 90.666 11.173 ;
     RECT  234.252 10.391 235.962 11.209 ;
     RECT  30.42 11.173 90.666 11.237 ;
     RECT  185.688 9.779 186.714 11.237 ;
     RECT  93.744 10.903 135.63 11.245 ;
     RECT  188.784 9.677 188.946 11.245 ;
     RECT  201.384 11.101 201.402 11.245 ;
     RECT  202.215 10.355 202.497 11.245 ;
     RECT  164.415 8.537 164.697 11.272 ;
     RECT  175.215 10.157 175.497 11.272 ;
     RECT  30.42 11.237 54.666 11.273 ;
     RECT  197.928 10.859 200.502 11.273 ;
     RECT  233.784 11.209 235.962 11.273 ;
     RECT  188.604 11.245 188.946 11.281 ;
     RECT  189.864 11.132 193.194 11.281 ;
     RECT  194.184 11.101 194.706 11.281 ;
     RECT  228.096 10.987 228.114 11.281 ;
     RECT  164.304 11.272 164.697 11.309 ;
     RECT  175.104 11.272 175.497 11.309 ;
     RECT  185.904 11.237 186.714 11.309 ;
     RECT  200.484 11.273 200.502 11.309 ;
     RECT  194.04 11.281 194.706 11.323 ;
     RECT  91.62 10.049 92.754 11.371 ;
     RECT  93.6 11.245 135.63 11.371 ;
     RECT  159.015 10.843 159.39 11.371 ;
     RECT  158.904 11.371 159.39 11.399 ;
     RECT  193.968 11.323 194.706 11.399 ;
     RECT  197.928 11.273 199.314 11.399 ;
     RECT  201.384 11.245 202.497 11.399 ;
     RECT  203.544 10.193 203.562 11.399 ;
     RECT  228.096 11.281 228.258 11.399 ;
     RECT  228.996 11.021 229.497 11.399 ;
     RECT  233.784 11.273 234.897 11.399 ;
     RECT  188.604 11.281 193.194 11.405 ;
     RECT  91.62 11.371 135.63 11.407 ;
     RECT  136.62 10.895 154.386 11.407 ;
     RECT  215.208 10.391 215.658 11.407 ;
     RECT  216.468 10.795 225.27 11.407 ;
     RECT  158.904 11.399 159.297 11.408 ;
     RECT  91.62 11.407 154.386 11.419 ;
     RECT  194.04 11.399 194.706 11.435 ;
     RECT  28.26 10.541 29.697 11.443 ;
     RECT  30.42 11.273 54.486 11.443 ;
     RECT  188.604 11.405 192.834 11.443 ;
     RECT  187.56 11.227 187.578 11.515 ;
     RECT  187.452 11.515 187.578 11.551 ;
     RECT  188.568 11.443 192.834 11.551 ;
     RECT  28.26 11.443 54.486 11.579 ;
     RECT  55.512 11.237 90.666 11.579 ;
     RECT  184.68 11.443 184.698 11.579 ;
     RECT  215.208 11.407 225.27 11.659 ;
     RECT  226.008 11.551 226.026 11.659 ;
     RECT  198.216 11.399 199.314 11.669 ;
     RECT  201.384 11.399 201.402 11.669 ;
     RECT  206.064 11.551 206.082 11.669 ;
     RECT  215.208 11.659 226.026 11.669 ;
     RECT  185.976 11.309 186.714 11.677 ;
     RECT  187.452 11.551 187.686 11.677 ;
     RECT  215.208 11.669 225.054 11.677 ;
     RECT  211.5 9.815 211.518 11.705 ;
     RECT  214.956 11.677 225.054 11.705 ;
     RECT  185.976 11.677 187.686 11.713 ;
     RECT  188.496 11.551 192.834 11.713 ;
     RECT  185.976 11.713 192.834 11.741 ;
     RECT  214.956 11.705 225.018 11.741 ;
     RECT  195.516 10.967 195.606 11.749 ;
     RECT  196.668 10.967 197.097 11.749 ;
     RECT  207.54 10.625 207.897 11.777 ;
     RECT  194.112 11.435 194.706 11.821 ;
     RECT  195.516 11.749 197.097 11.821 ;
     RECT  177.084 9.779 177.534 11.849 ;
     RECT  186.015 11.741 192.834 11.849 ;
     RECT  215.1 11.741 225.018 11.849 ;
     RECT  91.548 11.419 154.386 11.939 ;
     RECT  209.592 10.697 210.258 11.939 ;
     RECT  215.1 11.849 224.622 11.939 ;
     RECT  91.62 11.939 154.386 11.975 ;
     RECT  187.452 11.849 192.834 11.981 ;
     RECT  55.656 11.579 90.666 12.011 ;
     RECT  155.304 11.011 155.358 12.019 ;
     RECT  102.204 11.975 154.386 12.047 ;
     RECT  187.596 11.981 192.834 12.047 ;
     RECT  194.112 11.821 197.097 12.047 ;
     RECT  55.908 12.011 90.666 12.055 ;
     RECT  226.872 11.749 226.89 12.055 ;
     RECT  155.232 12.019 155.358 12.091 ;
     RECT  208.62 11.677 208.638 12.091 ;
     RECT  155.196 12.091 155.358 12.209 ;
     RECT  208.62 12.091 209.106 12.209 ;
     RECT  226.8 12.055 226.89 12.209 ;
     RECT  225.864 11.669 225.882 12.245 ;
     RECT  235.944 11.273 235.962 12.245 ;
     RECT  28.728 11.579 54.486 12.253 ;
     RECT  200.844 11.947 200.862 12.253 ;
     RECT  187.632 12.047 192.834 12.269 ;
     RECT  28.728 12.253 54.738 12.289 ;
     RECT  205.884 11.785 205.902 12.317 ;
     RECT  184.536 11.713 184.554 12.325 ;
     RECT  226.872 12.209 226.89 12.325 ;
     RECT  226.872 12.325 226.962 12.353 ;
     RECT  155.196 12.209 155.322 12.361 ;
     RECT  187.632 12.269 192.762 12.365 ;
     RECT  187.704 12.365 192.762 12.389 ;
     RECT  141.948 12.047 154.386 12.451 ;
     RECT  155.124 12.361 155.322 12.451 ;
     RECT  234.036 11.399 234.897 12.451 ;
     RECT  102.204 12.047 141.102 12.479 ;
     RECT  184.536 12.325 184.698 12.479 ;
     RECT  187.884 12.389 192.762 12.479 ;
     RECT  215.172 11.939 224.622 12.479 ;
     RECT  226.944 12.353 226.962 12.479 ;
     RECT  28.728 12.289 54.81 12.487 ;
     RECT  233.928 12.451 234.897 12.523 ;
     RECT  194.112 12.047 195.534 12.551 ;
     RECT  215.172 12.479 224.55 12.587 ;
     RECT  198.36 11.669 199.278 12.659 ;
     RECT  231.156 12.595 231.174 12.749 ;
     RECT  91.62 11.975 101.178 12.757 ;
     RECT  102.204 12.479 141.066 12.757 ;
     RECT  188.568 12.479 192.726 12.785 ;
     RECT  55.908 12.055 90.702 12.793 ;
     RECT  196.815 12.047 197.097 12.793 ;
     RECT  208.908 12.209 208.926 12.821 ;
     RECT  55.908 12.793 90.738 12.829 ;
     RECT  202.215 11.399 202.497 12.829 ;
     RECT  229.215 11.399 229.497 12.859 ;
     RECT  28.728 12.487 55.134 12.893 ;
     RECT  91.62 12.757 141.066 12.893 ;
     RECT  203.328 11.515 203.346 12.893 ;
     RECT  229.104 12.859 229.497 12.899 ;
     RECT  229.215 12.899 229.497 12.901 ;
     RECT  230.22 12.856 230.238 12.901 ;
     RECT  233.928 12.523 234.99 12.901 ;
     RECT  233.928 12.901 235.926 12.929 ;
     RECT  55.908 12.829 90.81 13.019 ;
     RECT  118.836 12.893 141.066 13.019 ;
     RECT  227.232 12.859 227.466 13.019 ;
     RECT  118.908 13.019 141.066 13.037 ;
     RECT  214.344 12.559 214.362 13.051 ;
     RECT  215.172 12.587 224.478 13.051 ;
     RECT  55.908 13.019 83.862 13.055 ;
     RECT  214.344 13.051 224.478 13.091 ;
     RECT  234.615 12.929 235.926 13.091 ;
     RECT  84.78 13.019 90.81 13.099 ;
     RECT  91.62 12.893 118.098 13.099 ;
     RECT  189.468 12.785 192.726 13.133 ;
     RECT  210.24 11.939 210.258 13.135 ;
     RECT  200.772 12.253 200.862 13.171 ;
     RECT  233.784 13.027 233.802 13.199 ;
     RECT  204.876 13.171 204.894 13.261 ;
     RECT  141.948 12.451 155.322 13.289 ;
     RECT  210.24 13.135 210.438 13.289 ;
     RECT  212.832 9.959 213.297 13.361 ;
     RECT  237.42 12.331 237.438 13.361 ;
     RECT  189.576 13.133 192.726 13.397 ;
     RECT  36.54 12.893 55.134 13.405 ;
     RECT  55.908 13.055 83.826 13.405 ;
     RECT  184.536 12.479 184.554 13.405 ;
     RECT  177.516 11.849 177.534 13.421 ;
     RECT  199.26 12.659 199.278 13.433 ;
     RECT  215.64 13.091 224.478 13.433 ;
     RECT  186.015 11.849 186.714 13.441 ;
     RECT  203.868 13.405 203.886 13.441 ;
     RECT  204.876 13.261 205.11 13.441 ;
     RECT  229.215 12.901 230.238 13.441 ;
     RECT  188.568 12.785 188.586 13.531 ;
     RECT  229.215 13.441 230.274 13.531 ;
     RECT  203.868 13.441 204.066 13.559 ;
     RECT  227.232 13.019 227.394 13.559 ;
     RECT  119.232 13.037 141.066 13.567 ;
     RECT  141.948 13.289 144.99 13.567 ;
     RECT  204.84 13.441 205.11 13.595 ;
     RECT  145.836 13.289 155.322 13.603 ;
     RECT  189.684 13.397 192.726 13.631 ;
     RECT  28.728 12.893 35.766 13.639 ;
     RECT  36.54 13.405 83.826 13.639 ;
     RECT  184.536 13.405 184.626 13.639 ;
     RECT  185.508 13.441 186.714 13.639 ;
     RECT  203.868 13.559 203.922 13.639 ;
     RECT  203.832 13.639 203.922 13.667 ;
     RECT  205.092 13.595 205.11 13.667 ;
     RECT  229.215 13.531 230.31 13.739 ;
     RECT  84.78 13.099 118.098 13.801 ;
     RECT  119.232 13.567 144.99 13.801 ;
     RECT  184.356 13.639 184.77 13.801 ;
     RECT  185.508 13.639 186.93 13.801 ;
     RECT  227.232 13.559 227.25 13.801 ;
     RECT  145.836 13.603 155.358 13.829 ;
     RECT  214.344 13.091 214.47 13.837 ;
     RECT  215.64 13.433 224.37 13.837 ;
     RECT  214.308 13.837 224.37 13.901 ;
     RECT  230.292 13.739 230.31 13.909 ;
     RECT  28.728 13.639 83.826 13.945 ;
     RECT  175.215 11.309 175.497 13.945 ;
     RECT  234.615 13.091 235.386 13.945 ;
     RECT  226.728 13.801 227.25 13.981 ;
     RECT  230.292 13.909 230.382 14.009 ;
     RECT  194.112 12.551 194.382 14.071 ;
     RECT  28.728 13.945 84.042 14.099 ;
     RECT  214.344 13.901 224.37 14.099 ;
     RECT  191.415 13.631 192.726 14.101 ;
     RECT  234.432 13.945 235.386 14.107 ;
     RECT  236.52 13.243 236.538 14.107 ;
     RECT  28.728 14.099 83.862 14.135 ;
     RECT  184.356 13.801 186.93 14.135 ;
     RECT  214.344 14.099 224.298 14.135 ;
     RECT  215.28 14.135 224.298 14.171 ;
     RECT  230.364 14.009 230.382 14.171 ;
     RECT  16.164 8.525 16.182 14.189 ;
     RECT  226.692 13.981 227.25 14.189 ;
     RECT  210.24 13.289 210.366 14.207 ;
     RECT  215.28 14.171 224.154 14.207 ;
     RECT  157.5 12.901 157.518 14.215 ;
     RECT  225.756 13.945 225.774 14.237 ;
     RECT  28.728 14.135 83.697 14.243 ;
     RECT  214.344 14.135 214.398 14.243 ;
     RECT  84.78 13.801 144.99 14.251 ;
     RECT  145.836 13.829 151.434 14.251 ;
     RECT  152.244 13.829 155.358 14.251 ;
     RECT  156.384 12.865 156.402 14.251 ;
     RECT  191.415 14.101 192.762 14.251 ;
     RECT  193.86 14.071 194.382 14.251 ;
     RECT  182.448 14.251 182.466 14.341 ;
     RECT  234.432 14.107 236.538 14.341 ;
     RECT  191.415 14.251 194.382 14.369 ;
     RECT  230.724 14.251 230.886 14.369 ;
     RECT  152.244 14.251 156.402 14.377 ;
     RECT  188.208 13.531 188.586 14.377 ;
     RECT  189.684 13.631 190.53 14.377 ;
     RECT  191.415 14.369 192.834 14.377 ;
     RECT  193.608 14.369 194.382 14.405 ;
     RECT  200.016 14.251 200.034 14.405 ;
     RECT  215.496 14.207 224.154 14.441 ;
     RECT  228.348 13.171 228.366 14.443 ;
     RECT  182.412 14.341 182.466 14.477 ;
     RECT  200.772 13.171 201.294 14.485 ;
     RECT  182.448 14.477 182.466 14.513 ;
     RECT  193.68 14.405 194.382 14.513 ;
     RECT  214.38 14.243 214.398 14.513 ;
     RECT  152.244 14.377 156.546 14.521 ;
     RECT  157.5 14.215 157.554 14.521 ;
     RECT  198.36 12.659 198.378 14.521 ;
     RECT  227.196 14.189 227.25 14.521 ;
     RECT  228.24 14.443 228.366 14.549 ;
     RECT  234.216 14.341 236.538 14.549 ;
     RECT  184.356 14.135 184.662 14.639 ;
     RECT  195.516 12.551 195.534 14.639 ;
     RECT  223.524 14.441 224.154 14.639 ;
     RECT  227.196 14.521 227.502 14.639 ;
     RECT  231.732 14.521 231.822 14.639 ;
     RECT  185.436 14.135 186.93 14.675 ;
     RECT  193.752 14.513 194.382 14.675 ;
     RECT  234.288 14.549 236.538 14.711 ;
     RECT  84.78 14.251 151.434 14.719 ;
     RECT  184.356 14.639 184.518 14.747 ;
     RECT  193.968 14.675 194.382 14.747 ;
     RECT  198.108 14.521 198.414 14.747 ;
     RECT  84.744 14.719 151.434 14.755 ;
     RECT  152.244 14.521 157.554 14.755 ;
     RECT  188.208 14.377 192.834 14.765 ;
     RECT  215.496 14.441 222.75 14.783 ;
     RECT  234.288 14.711 235.962 14.783 ;
     RECT  230.724 14.369 230.742 14.813 ;
     RECT  184.356 14.747 184.446 14.819 ;
     RECT  58.464 14.243 83.697 14.881 ;
     RECT  84.744 14.755 157.554 14.881 ;
     RECT  84.744 14.881 157.59 14.909 ;
     RECT  58.464 14.881 83.934 14.917 ;
     RECT  185.508 14.675 186.93 14.945 ;
     RECT  157.536 14.909 157.59 14.953 ;
     RECT  157.536 14.953 157.662 14.981 ;
     RECT  200.16 14.485 201.294 15.019 ;
     RECT  233.136 14.791 233.154 15.053 ;
     RECT  189.972 14.765 192.834 15.179 ;
     RECT  202.215 12.829 202.554 15.179 ;
     RECT  200.16 15.019 201.33 15.197 ;
     RECT  200.484 15.197 201.33 15.202 ;
     RECT  28.728 14.243 57.546 15.223 ;
     RECT  58.464 14.917 83.97 15.223 ;
     RECT  198.36 14.747 198.414 15.259 ;
     RECT  198.36 15.259 198.918 15.287 ;
     RECT  28.728 15.223 83.97 15.295 ;
     RECT  84.744 14.909 90.162 15.295 ;
     RECT  159.015 11.408 159.297 15.295 ;
     RECT  189.972 15.179 192.078 15.359 ;
     RECT  200.484 15.202 201.042 15.359 ;
     RECT  215.496 14.783 221.814 15.359 ;
     RECT  228.348 14.549 228.366 15.403 ;
     RECT  229.215 13.739 229.497 15.403 ;
     RECT  157.572 14.981 157.662 15.421 ;
     RECT  176.544 14.953 176.562 15.421 ;
     RECT  215.496 15.359 218.862 15.421 ;
     RECT  176.544 15.421 176.886 15.449 ;
     RECT  186.015 14.945 186.93 15.457 ;
     RECT  188.208 14.765 188.946 15.457 ;
     RECT  222.696 14.783 222.75 15.457 ;
     RECT  223.524 14.639 224.097 15.457 ;
     RECT  90.972 14.909 156.798 15.485 ;
     RECT  237.492 15.259 237.51 15.485 ;
     RECT  174.996 13.945 175.497 15.521 ;
     RECT  176.868 15.449 176.886 15.521 ;
     RECT  215.46 15.421 218.862 15.529 ;
     RECT  219.6 15.359 221.814 15.529 ;
     RECT  222.696 15.457 224.097 15.529 ;
     RECT  226.296 14.989 226.314 15.529 ;
     RECT  219.6 15.529 224.097 15.565 ;
     RECT  234.288 14.783 234.897 15.565 ;
     RECT  225.792 15.529 226.314 15.593 ;
     RECT  198.9 15.287 198.918 15.601 ;
     RECT  210.24 14.207 210.258 15.601 ;
     RECT  227.196 14.639 227.286 15.601 ;
     RECT  186.015 15.457 188.946 15.691 ;
     RECT  215.028 15.529 218.862 15.691 ;
     RECT  225.792 15.593 225.81 15.691 ;
     RECT  142.38 15.485 156.798 15.719 ;
     RECT  219.6 15.565 224.694 15.719 ;
     RECT  226.584 15.601 227.286 15.719 ;
     RECT  182.412 15.691 182.43 15.727 ;
     RECT  226.872 15.719 227.286 15.728 ;
     RECT  214.308 15.691 218.862 15.739 ;
     RECT  142.38 15.719 156.654 15.755 ;
     RECT  198.9 15.601 199.242 15.755 ;
     RECT  235.944 14.783 235.962 15.755 ;
     RECT  194.364 14.747 194.382 15.763 ;
     RECT  227.268 15.728 227.286 15.773 ;
     RECT  210.24 15.601 210.402 15.791 ;
     RECT  230.256 15.691 230.274 15.791 ;
     RECT  223.596 15.719 224.694 15.827 ;
     RECT  186.015 15.691 189.126 15.829 ;
     RECT  28.728 15.295 90.162 15.835 ;
     RECT  90.972 15.485 141.642 15.835 ;
     RECT  223.815 15.827 224.694 15.835 ;
     RECT  225.648 15.691 225.81 15.835 ;
     RECT  198.9 15.755 198.918 15.863 ;
     RECT  199.656 15.787 199.674 15.863 ;
     RECT  223.815 15.835 225.81 15.869 ;
     RECT  175.104 15.521 175.497 15.871 ;
     RECT  228.348 15.403 229.497 15.871 ;
     RECT  194.364 15.763 194.454 15.899 ;
     RECT  200.484 15.359 200.79 15.899 ;
     RECT  214.02 15.739 218.862 15.899 ;
     RECT  182.412 15.727 182.538 15.961 ;
     RECT  228.132 15.871 229.497 15.979 ;
     RECT  28.728 15.835 141.642 15.989 ;
     RECT  196.344 12.793 197.097 15.989 ;
     RECT  200.628 15.899 200.79 15.989 ;
     RECT  157.572 15.421 157.914 15.997 ;
     RECT  164.415 11.309 164.697 15.997 ;
     RECT  169.815 10.157 170.097 15.997 ;
     RECT  185.796 15.829 189.126 15.997 ;
     RECT  200.628 15.989 200.754 16.025 ;
     RECT  213.015 13.361 213.297 16.033 ;
     RECT  214.02 15.899 216.234 16.033 ;
     RECT  219.6 15.719 222.714 16.061 ;
     RECT  157.464 15.997 157.914 16.069 ;
     RECT  158.76 15.295 159.297 16.069 ;
     RECT  162.468 15.997 162.486 16.069 ;
     RECT  169.815 15.997 170.442 16.069 ;
     RECT  185.328 15.997 189.126 16.069 ;
     RECT  190.008 15.359 192.078 16.069 ;
     RECT  192.816 15.179 192.834 16.069 ;
     RECT  162.468 16.069 162.558 16.097 ;
     RECT  164.415 15.997 164.754 16.097 ;
     RECT  190.008 16.069 192.834 16.105 ;
     RECT  217.044 15.899 218.862 16.105 ;
     RECT  219.6 16.061 222.498 16.105 ;
     RECT  164.415 16.097 164.697 16.123 ;
     RECT  207.615 11.777 207.897 16.123 ;
     RECT  185.292 16.069 189.126 16.141 ;
     RECT  190.008 16.105 193.122 16.141 ;
     RECT  231.732 14.639 231.75 16.157 ;
     RECT  157.464 16.069 159.318 16.169 ;
     RECT  162.54 16.097 162.558 16.169 ;
     RECT  164.304 16.123 164.697 16.169 ;
     RECT  169.815 16.069 170.514 16.169 ;
     RECT  175.104 15.871 175.59 16.169 ;
     RECT  194.364 15.899 194.382 16.169 ;
     RECT  196.704 15.989 197.097 16.169 ;
     RECT  206.352 16.069 206.37 16.169 ;
     RECT  207.504 16.123 207.897 16.169 ;
     RECT  184.356 14.819 184.374 16.219 ;
     RECT  184.284 16.219 184.374 16.231 ;
     RECT  213.015 16.033 216.234 16.259 ;
     RECT  228.132 15.979 229.554 16.259 ;
     RECT  184.284 16.231 184.41 16.295 ;
     RECT  185.292 16.141 193.122 16.295 ;
     RECT  215.82 16.259 216.234 16.295 ;
     RECT  184.356 16.295 184.41 16.303 ;
     RECT  210.24 15.791 210.366 16.303 ;
     RECT  234.036 15.565 234.897 16.303 ;
     RECT  184.356 16.303 184.518 16.331 ;
     RECT  189.9 16.295 193.122 16.367 ;
     RECT  209.52 16.303 210.366 16.367 ;
     RECT  4.608 16.363 4.626 16.375 ;
     RECT  224.856 15.869 225.81 16.375 ;
     RECT  4.608 16.375 4.698 16.403 ;
     RECT  157.536 16.169 159.318 16.403 ;
     RECT  184.392 16.331 184.518 16.411 ;
     RECT  185.292 16.295 189.126 16.411 ;
     RECT  190.152 16.367 193.122 16.411 ;
     RECT  175.215 16.169 175.59 16.439 ;
     RECT  200.736 16.025 200.754 16.439 ;
     RECT  216.036 16.295 216.054 16.439 ;
     RECT  136.8 15.989 141.642 16.501 ;
     RECT  142.38 15.755 156.51 16.501 ;
     RECT  184.392 16.411 189.126 16.529 ;
     RECT  190.152 16.411 193.158 16.529 ;
     RECT  217.044 16.105 222.498 16.529 ;
     RECT  224.856 16.375 226.026 16.529 ;
     RECT  228.132 16.259 229.497 16.529 ;
     RECT  233.856 16.303 235.242 16.529 ;
     RECT  6.12 16.501 6.138 16.541 ;
     RECT  184.5 16.529 189.126 16.541 ;
     RECT  4.68 16.403 4.698 16.565 ;
     RECT  184.5 16.541 188.838 16.565 ;
     RECT  190.26 16.529 193.158 16.565 ;
     RECT  234.576 16.529 235.242 16.699 ;
     RECT  236.412 15.835 236.538 16.699 ;
     RECT  181.836 15.961 182.538 16.709 ;
     RECT  136.8 16.501 156.51 16.771 ;
     RECT  217.044 16.529 220.662 16.771 ;
     RECT  190.26 16.565 190.314 16.799 ;
     RECT  213.015 16.259 215.046 16.799 ;
     RECT  226.368 16.681 226.89 16.799 ;
     RECT  230.472 15.961 230.49 16.807 ;
     RECT  184.536 16.565 188.694 16.835 ;
     RECT  190.296 16.799 190.314 16.871 ;
     RECT  191.415 16.565 193.158 16.871 ;
     RECT  184.536 16.835 186.966 16.877 ;
     RECT  28.728 15.989 136.062 16.879 ;
     RECT  136.8 16.771 156.762 16.879 ;
     RECT  185.22 16.877 186.966 16.88 ;
     RECT  217.008 16.771 220.662 16.907 ;
     RECT  217.332 16.907 220.662 16.943 ;
     RECT  175.215 16.439 175.497 16.951 ;
     RECT  213.015 16.799 215.01 16.979 ;
     RECT  234.576 16.699 236.538 17.021 ;
     RECT  160.092 16.105 160.11 17.041 ;
     RECT  181.836 16.709 182.502 17.069 ;
     RECT  185.256 16.88 186.966 17.069 ;
     RECT  187.992 16.835 188.694 17.069 ;
     RECT  203.832 13.667 203.85 17.069 ;
     RECT  217.476 16.943 220.662 17.069 ;
     RECT  187.992 17.069 188.514 17.075 ;
     RECT  196.815 16.169 197.097 17.077 ;
     RECT  185.256 17.069 185.274 17.105 ;
     RECT  188.064 17.075 188.514 17.105 ;
     RECT  191.415 16.871 192.834 17.105 ;
     RECT  217.476 17.069 220.194 17.105 ;
     RECT  196.704 17.077 197.097 17.117 ;
     RECT  200.556 17.077 200.718 17.117 ;
     RECT  204.588 17.077 204.606 17.117 ;
     RECT  214.992 16.979 215.01 17.117 ;
     RECT  28.728 16.879 156.762 17.149 ;
     RECT  157.536 16.403 159.297 17.149 ;
     RECT  28.728 17.149 159.297 17.213 ;
     RECT  28.728 17.213 155.106 17.249 ;
     RECT  223.815 15.869 224.097 17.323 ;
     RECT  29.088 17.249 155.106 17.411 ;
     RECT  192.816 17.105 192.834 17.411 ;
     RECT  234.576 17.021 235.242 17.419 ;
     RECT  209.52 16.367 210.258 17.453 ;
     RECT  224.856 16.529 225.45 17.455 ;
     RECT  229.14 16.529 229.497 17.455 ;
     RECT  230.292 16.807 230.49 17.455 ;
     RECT  221.652 16.529 222.498 17.491 ;
     RECT  234.252 17.419 235.242 17.491 ;
     RECT  155.88 17.213 159.297 17.581 ;
     RECT  229.14 17.455 230.49 17.609 ;
     RECT  234.18 17.491 235.242 17.609 ;
     RECT  209.52 17.453 210.114 17.617 ;
     RECT  29.088 17.411 155.07 17.645 ;
     RECT  155.88 17.581 159.354 17.645 ;
     RECT  207.615 16.169 207.897 17.653 ;
     RECT  209.016 17.617 210.114 17.653 ;
     RECT  221.652 17.491 222.606 17.653 ;
     RECT  223.704 17.323 224.097 17.653 ;
     RECT  226.872 16.799 226.89 17.689 ;
     RECT  234.504 17.609 235.242 17.851 ;
     RECT  236.556 17.563 236.574 17.851 ;
     RECT  61.344 17.645 155.07 17.951 ;
     RECT  206.784 17.851 206.802 17.959 ;
     RECT  228.132 16.529 228.366 17.995 ;
     RECT  229.14 17.609 229.497 17.995 ;
     RECT  224.856 17.455 226.062 18.031 ;
     RECT  226.872 17.689 226.962 18.031 ;
     RECT  218.304 17.105 218.697 18.149 ;
     RECT  224.856 18.031 227.034 18.149 ;
     RECT  228.132 17.995 229.497 18.149 ;
     RECT  61.344 17.951 91.818 18.173 ;
     RECT  224.856 18.149 226.062 18.173 ;
     RECT  228.132 18.149 228.474 18.173 ;
     RECT  92.556 17.951 155.07 18.265 ;
     RECT  155.88 17.645 159.297 18.265 ;
     RECT  27.864 16.807 27.882 18.391 ;
     RECT  29.088 17.645 60.426 18.391 ;
     RECT  9.036 18.235 9.054 18.419 ;
     RECT  234.504 17.851 236.574 18.419 ;
     RECT  92.556 18.265 159.297 18.455 ;
     RECT  29.088 18.391 60.498 18.475 ;
     RECT  61.344 18.173 71.262 18.475 ;
     RECT  29.088 18.475 71.262 18.491 ;
     RECT  213.015 16.979 213.786 18.527 ;
     RECT  206.136 17.959 206.802 18.535 ;
     RECT  207.615 17.653 210.114 18.535 ;
     RECT  186.015 17.069 186.966 18.557 ;
     RECT  235.944 18.419 236.574 18.563 ;
     RECT  23.328 11.173 26.874 18.571 ;
     RECT  27.684 18.391 27.882 18.571 ;
     RECT  234.504 18.419 234.897 18.571 ;
     RECT  228.132 18.173 228.366 18.599 ;
     RECT  72.072 18.173 91.818 18.715 ;
     RECT  92.556 18.455 145.998 18.715 ;
     RECT  237.492 17.275 237.51 18.725 ;
     RECT  72.072 18.715 145.998 18.761 ;
     RECT  9.36 18.571 9.378 18.797 ;
     RECT  79.416 18.761 145.998 18.797 ;
     RECT  146.736 18.455 159.297 18.797 ;
     RECT  221.652 17.653 224.097 18.805 ;
     RECT  224.856 18.173 226.026 18.805 ;
     RECT  230.292 17.609 230.49 19.031 ;
     RECT  226.872 18.149 226.89 19.085 ;
     RECT  157.572 18.797 159.297 19.103 ;
     RECT  221.652 18.805 226.026 19.111 ;
     RECT  158.796 19.103 159.297 19.201 ;
     RECT  160.092 17.041 160.146 19.201 ;
     RECT  157.572 19.103 158.058 19.229 ;
     RECT  234.036 18.571 234.897 19.229 ;
     RECT  162.432 19.039 162.45 19.237 ;
     RECT  79.56 18.797 145.998 19.243 ;
     RECT  146.736 18.797 156.762 19.243 ;
     RECT  29.088 18.491 70.794 19.309 ;
     RECT  174.672 16.951 175.497 19.309 ;
     RECT  158.796 19.201 160.146 19.337 ;
     RECT  160.128 19.337 160.146 19.373 ;
     RECT  221.652 19.111 226.566 19.373 ;
     RECT  231.768 19.381 231.786 19.499 ;
     RECT  221.652 19.373 226.026 19.517 ;
     RECT  79.56 19.243 156.762 19.535 ;
     RECT  235.944 18.563 236.538 19.535 ;
     RECT  142.524 19.535 156.762 19.579 ;
     RECT  157.572 19.229 157.95 19.579 ;
     RECT  29.088 19.309 70.83 19.607 ;
     RECT  230.472 19.031 230.49 19.615 ;
     RECT  70.02 19.607 70.83 19.627 ;
     RECT  230.472 19.615 230.85 19.661 ;
     RECT  70.02 19.627 71.298 19.741 ;
     RECT  72.072 18.761 78.678 19.741 ;
     RECT  29.088 19.607 69.066 19.769 ;
     RECT  235.944 19.535 235.962 19.805 ;
     RECT  70.02 19.741 78.678 19.901 ;
     RECT  29.088 19.769 37.494 19.913 ;
     RECT  79.56 19.535 141.786 19.949 ;
     RECT  142.524 19.579 157.95 19.949 ;
     RECT  162.36 19.237 162.45 19.949 ;
     RECT  157.32 19.949 157.95 20.011 ;
     RECT  158.796 19.337 159.297 20.011 ;
     RECT  79.56 19.949 116.097 20.047 ;
     RECT  71.748 19.901 78.678 20.083 ;
     RECT  79.452 20.047 116.097 20.083 ;
     RECT  167.22 19.309 167.238 20.083 ;
     RECT  227.16 20.047 227.178 20.093 ;
     RECT  13.215 11.165 13.497 20.107 ;
     RECT  230.472 19.661 230.562 20.111 ;
     RECT  230.472 20.111 230.49 20.147 ;
     RECT  234.288 19.229 234.897 20.147 ;
     RECT  224.856 19.517 226.026 20.191 ;
     RECT  228.132 18.599 228.15 20.191 ;
     RECT  13.215 20.107 13.59 20.281 ;
     RECT  233.244 16.681 233.262 20.281 ;
     RECT  13.215 20.281 14.238 20.309 ;
     RECT  34.776 19.913 37.494 20.309 ;
     RECT  117.036 19.949 141.786 20.309 ;
     RECT  224.856 20.191 226.314 20.309 ;
     RECT  14.22 20.309 14.238 20.333 ;
     RECT  117.036 20.309 128.862 20.345 ;
     RECT  228.096 20.191 228.15 20.345 ;
     RECT  129.6 20.309 141.786 20.381 ;
     RECT  129.672 20.381 141.786 20.389 ;
     RECT  142.524 19.949 156.474 20.389 ;
     RECT  23.328 18.571 27.882 20.461 ;
     RECT  29.088 19.913 33.966 20.489 ;
     RECT  38.232 19.769 69.066 20.489 ;
     RECT  129.672 20.389 156.474 20.525 ;
     RECT  70.02 19.901 70.83 20.539 ;
     RECT  230.4 20.191 230.418 20.551 ;
     RECT  234.468 20.147 234.897 20.551 ;
     RECT  142.128 20.525 156.474 20.579 ;
     RECT  230.292 20.551 230.418 20.651 ;
     RECT  71.748 20.083 116.097 20.659 ;
     RECT  142.524 20.579 156.474 20.672 ;
     RECT  157.32 20.011 159.297 20.672 ;
     RECT  221.652 19.517 224.097 20.725 ;
     RECT  224.856 20.309 226.134 20.725 ;
     RECT  69.48 20.539 70.83 20.731 ;
     RECT  71.604 20.659 116.097 20.731 ;
     RECT  221.652 20.725 226.134 20.765 ;
     RECT  117.036 20.345 128.718 20.821 ;
     RECT  69.48 20.731 116.097 20.849 ;
     RECT  116.892 20.821 128.718 20.885 ;
     RECT  236.52 20.491 236.538 20.885 ;
     RECT  34.812 20.309 37.494 20.893 ;
     RECT  38.232 20.489 60.102 20.893 ;
     RECT  142.524 20.672 159.297 20.993 ;
     RECT  61.02 20.489 68.742 21.029 ;
     RECT  237.492 19.915 237.51 21.067 ;
     RECT  154.728 20.993 159.297 21.091 ;
     RECT  224.856 20.765 226.134 21.091 ;
     RECT  34.812 20.893 60.102 21.104 ;
     RECT  228.132 20.345 228.15 21.127 ;
     RECT  154.728 21.091 159.426 21.149 ;
     RECT  237.456 21.067 237.51 21.155 ;
     RECT  129.672 20.525 141.39 21.163 ;
     RECT  157.248 21.149 159.426 21.191 ;
     RECT  237.456 21.155 237.474 21.191 ;
     RECT  154.728 21.149 156.042 21.227 ;
     RECT  29.088 20.489 33.642 21.235 ;
     RECT  70.596 20.849 116.097 21.235 ;
     RECT  29.088 21.235 33.75 21.271 ;
     RECT  34.704 21.104 60.102 21.271 ;
     RECT  61.02 21.029 67.497 21.271 ;
     RECT  129.528 21.163 141.39 21.271 ;
     RECT  160.704 21.199 160.722 21.271 ;
     RECT  230.796 21.001 230.886 21.271 ;
     RECT  129.528 21.271 141.498 21.307 ;
     RECT  234.468 20.551 234.918 21.355 ;
     RECT  29.088 21.271 33.894 21.361 ;
     RECT  34.704 21.271 67.497 21.389 ;
     RECT  70.596 21.235 116.154 21.389 ;
     RECT  153.324 20.993 153.99 21.389 ;
     RECT  230.796 21.271 230.958 21.389 ;
     RECT  68.256 21.029 68.742 21.397 ;
     RECT  69.48 20.849 69.786 21.397 ;
     RECT  205.2 19.099 205.218 21.397 ;
     RECT  206.136 18.535 210.114 21.397 ;
     RECT  227.7 21.127 228.15 21.397 ;
     RECT  229.215 18.149 229.497 21.397 ;
     RECT  34.704 21.389 65.538 21.425 ;
     RECT  155.304 21.227 156.042 21.425 ;
     RECT  157.248 21.191 158.166 21.425 ;
     RECT  74.34 21.389 116.154 21.433 ;
     RECT  116.892 20.885 128.538 21.433 ;
     RECT  158.976 21.191 159.426 21.469 ;
     RECT  234.468 21.355 235.242 21.469 ;
     RECT  129.528 21.307 141.642 21.497 ;
     RECT  155.304 21.425 155.538 21.497 ;
     RECT  157.248 21.425 158.094 21.497 ;
     RECT  160.632 21.271 160.722 21.497 ;
     RECT  227.7 21.397 229.497 21.505 ;
     RECT  74.34 21.433 128.538 21.533 ;
     RECT  157.788 21.497 158.094 21.533 ;
     RECT  68.256 21.397 69.786 21.631 ;
     RECT  70.596 21.389 73.35 21.631 ;
     RECT  86.436 21.533 128.538 21.631 ;
     RECT  142.524 20.993 152.298 21.631 ;
     RECT  234.288 21.469 235.242 21.631 ;
     RECT  227.304 21.505 229.497 21.643 ;
     RECT  74.34 21.533 85.446 21.659 ;
     RECT  129.528 21.497 141.57 21.659 ;
     RECT  142.488 21.631 152.298 21.659 ;
     RECT  158.976 21.469 159.498 21.659 ;
     RECT  86.436 21.631 128.718 21.667 ;
     RECT  129.528 21.659 141.39 21.667 ;
     RECT  86.436 21.667 141.39 21.677 ;
     RECT  86.436 21.677 127.998 21.695 ;
     RECT  227.16 21.643 229.497 21.695 ;
     RECT  224.856 21.091 226.278 21.703 ;
     RECT  233.1 20.281 233.262 21.703 ;
     RECT  234.108 21.631 235.242 21.703 ;
     RECT  28.98 21.361 33.894 21.731 ;
     RECT  142.488 21.659 143.838 21.775 ;
     RECT  66.492 21.389 67.497 21.787 ;
     RECT  68.256 21.631 73.35 21.787 ;
     RECT  74.34 21.659 85.338 21.803 ;
     RECT  205.2 21.397 210.114 21.803 ;
     RECT  144.576 21.659 152.298 21.811 ;
     RECT  129.312 21.677 141.102 21.821 ;
     RECT  233.1 21.703 235.242 21.928 ;
     RECT  236.52 21.643 236.538 21.928 ;
     RECT  158.076 21.533 158.094 21.929 ;
     RECT  224.856 21.703 226.386 21.929 ;
     RECT  129.348 21.821 141.102 21.938 ;
     RECT  231.696 21.541 231.714 21.965 ;
     RECT  233.1 21.928 236.538 21.965 ;
     RECT  23.328 20.461 28.206 21.973 ;
     RECT  28.98 21.731 33.174 21.973 ;
     RECT  158.976 21.659 159.354 22.001 ;
     RECT  224.856 21.929 226.314 22.001 ;
     RECT  227.7 21.695 229.497 22.001 ;
     RECT  221.652 20.765 224.097 22.027 ;
     RECT  224.856 22.001 226.026 22.027 ;
     RECT  74.34 21.803 85.122 22.037 ;
     RECT  153.54 21.389 153.99 22.045 ;
     RECT  86.652 21.695 127.998 22.061 ;
     RECT  142.344 21.775 143.838 22.073 ;
     RECT  206.136 21.803 210.114 22.081 ;
     RECT  18.615 9.053 18.897 22.171 ;
     RECT  129.384 21.938 141.102 22.199 ;
     RECT  34.776 21.425 65.538 22.207 ;
     RECT  18.072 22.171 18.897 22.208 ;
     RECT  19.62 22.171 19.638 22.208 ;
     RECT  129.384 22.199 140.85 22.208 ;
     RECT  74.34 22.037 84.834 22.219 ;
     RECT  129.384 22.208 140.814 22.235 ;
     RECT  153.54 22.045 154.458 22.235 ;
     RECT  159.015 22.001 159.354 22.235 ;
     RECT  236.484 21.965 236.538 22.253 ;
     RECT  66.492 21.787 73.35 22.279 ;
     RECT  74.16 22.219 84.834 22.279 ;
     RECT  161.316 21.901 161.37 22.307 ;
     RECT  34.524 22.207 65.538 22.315 ;
     RECT  129.384 22.235 139.986 22.343 ;
     RECT  129.564 22.343 139.986 22.379 ;
     RECT  168.732 19.237 168.75 22.441 ;
     RECT  221.652 22.027 226.026 22.469 ;
     RECT  144.576 21.811 152.406 22.477 ;
     RECT  153.54 22.235 153.897 22.477 ;
     RECT  23.328 21.973 33.174 22.513 ;
     RECT  34.524 22.315 65.646 22.513 ;
     RECT  233.1 21.965 235.314 22.513 ;
     RECT  129.6 22.379 139.986 22.613 ;
     RECT  23.328 22.513 65.646 22.621 ;
     RECT  66.492 22.279 84.834 22.621 ;
     RECT  168.732 22.441 169.002 22.621 ;
     RECT  169.815 16.169 170.097 22.621 ;
     RECT  218.415 18.149 218.697 22.621 ;
     RECT  23.328 22.621 84.834 22.649 ;
     RECT  86.652 22.061 114.822 22.649 ;
     RECT  142.524 22.073 143.838 22.711 ;
     RECT  144.576 22.477 153.897 22.711 ;
     RECT  23.328 22.649 84.762 22.739 ;
     RECT  232.884 22.513 235.314 22.739 ;
     RECT  227.7 22.001 228.15 22.783 ;
     RECT  218.304 22.621 218.697 22.811 ;
     RECT  167.22 20.083 167.598 22.855 ;
     RECT  168.732 22.621 170.097 22.855 ;
     RECT  229.215 22.001 229.497 22.891 ;
     RECT  86.688 22.649 114.822 22.919 ;
     RECT  23.328 22.739 84.726 23.009 ;
     RECT  135.72 22.613 139.986 23.009 ;
     RECT  229.215 22.891 229.554 23.009 ;
     RECT  65.772 23.009 84.654 23.045 ;
     RECT  167.22 22.855 170.097 23.053 ;
     RECT  206.136 22.081 210.186 23.053 ;
     RECT  142.524 22.711 153.897 23.081 ;
     RECT  167.004 23.053 170.097 23.081 ;
     RECT  181.836 17.069 181.854 23.081 ;
     RECT  115.56 22.061 127.998 23.089 ;
     RECT  139.788 23.009 139.986 23.089 ;
     RECT  227.7 22.783 228.258 23.089 ;
     RECT  86.688 22.919 114.714 23.117 ;
     RECT  139.788 23.089 140.706 23.117 ;
     RECT  115.56 23.089 128.214 23.125 ;
     RECT  161.352 22.307 161.37 23.153 ;
     RECT  129.6 22.613 134.946 23.161 ;
     RECT  164.415 16.169 164.697 23.161 ;
     RECT  65.772 23.045 84.474 23.189 ;
     RECT  129.456 23.161 134.946 23.227 ;
     RECT  164.415 23.161 164.754 23.251 ;
     RECT  80.424 23.189 84.474 23.279 ;
     RECT  115.56 23.125 128.502 23.287 ;
     RECT  129.384 23.227 134.946 23.287 ;
     RECT  165.924 22.891 165.942 23.287 ;
     RECT  167.004 23.081 167.238 23.287 ;
     RECT  226.872 23.275 226.89 23.287 ;
     RECT  227.7 23.089 228.33 23.287 ;
     RECT  115.56 23.287 134.946 23.309 ;
     RECT  226.872 23.287 228.33 23.315 ;
     RECT  65.844 23.189 79.65 23.351 ;
     RECT  142.524 23.081 152.802 23.351 ;
     RECT  167.976 23.081 170.097 23.351 ;
     RECT  80.424 23.279 83.697 23.357 ;
     RECT  227.304 23.315 228.33 23.357 ;
     RECT  129.744 23.309 134.946 23.359 ;
     RECT  135.72 23.009 138.906 23.359 ;
     RECT  221.652 22.469 224.097 23.371 ;
     RECT  224.856 22.469 226.026 23.371 ;
     RECT  165.888 23.287 167.238 23.387 ;
     RECT  23.328 23.009 65.034 23.405 ;
     RECT  236.52 22.253 236.538 23.419 ;
     RECT  23.328 23.405 64.998 23.423 ;
     RECT  65.844 23.351 78.642 23.423 ;
     RECT  144.756 23.351 151.866 23.423 ;
     RECT  227.7 23.357 228.33 23.431 ;
     RECT  230.292 22.981 230.31 23.431 ;
     RECT  65.844 23.423 71.226 23.549 ;
     RECT  142.524 23.351 144.018 23.549 ;
     RECT  227.7 23.431 228.366 23.549 ;
     RECT  82.656 23.357 83.697 23.585 ;
     RECT  115.56 23.309 129.006 23.585 ;
     RECT  168.048 23.351 170.097 23.585 ;
     RECT  205.2 21.803 205.218 23.629 ;
     RECT  206.064 23.053 210.186 23.629 ;
     RECT  221.652 23.371 226.026 23.629 ;
     RECT  82.656 23.585 82.674 23.657 ;
     RECT  86.688 23.117 114.642 23.657 ;
     RECT  65.844 23.549 70.794 23.693 ;
     RECT  157.86 23.161 157.878 23.701 ;
     RECT  229.215 23.009 229.497 23.701 ;
     RECT  221.652 23.629 226.386 23.729 ;
     RECT  230.292 23.431 230.382 23.729 ;
     RECT  71.964 23.423 78.642 23.819 ;
     RECT  79.38 23.351 79.65 23.819 ;
     RECT  80.424 23.357 81.306 23.819 ;
     RECT  152.604 23.351 152.802 23.819 ;
     RECT  221.652 23.729 226.314 23.819 ;
     RECT  115.56 23.585 119.79 23.827 ;
     RECT  120.564 23.585 129.006 23.837 ;
     RECT  86.688 23.657 98.37 23.855 ;
     RECT  115.488 23.827 119.79 23.885 ;
     RECT  115.56 23.885 119.79 23.891 ;
     RECT  99.144 23.657 114.642 23.927 ;
     RECT  115.704 23.891 119.79 23.933 ;
     RECT  221.652 23.819 226.026 23.933 ;
     RECT  109.728 23.927 114.642 23.935 ;
     RECT  164.415 23.251 164.826 23.935 ;
     RECT  23.328 23.423 33.678 23.947 ;
     RECT  65.844 23.693 70.758 23.947 ;
     RECT  168.984 23.585 170.097 23.971 ;
     RECT  120.924 23.837 129.006 24.043 ;
     RECT  129.744 23.359 138.906 24.043 ;
     RECT  22.608 23.947 33.678 24.089 ;
     RECT  34.524 23.423 64.998 24.089 ;
     RECT  80.46 23.819 81.306 24.089 ;
     RECT  120.924 24.043 138.906 24.097 ;
     RECT  139.968 23.117 140.706 24.097 ;
     RECT  144.792 23.423 151.866 24.097 ;
     RECT  152.604 23.819 152.622 24.097 ;
     RECT  120.924 24.097 140.706 24.125 ;
     RECT  167.004 23.387 167.238 24.133 ;
     RECT  168.048 23.585 168.174 24.133 ;
     RECT  86.688 23.855 98.226 24.139 ;
     RECT  38.088 24.089 64.998 24.169 ;
     RECT  65.736 23.947 70.758 24.169 ;
     RECT  124.38 24.125 140.706 24.169 ;
     RECT  155.304 21.497 155.322 24.205 ;
     RECT  38.088 24.169 70.758 24.221 ;
     RECT  115.815 23.933 119.79 24.221 ;
     RECT  71.964 23.819 78.606 24.233 ;
     RECT  115.815 24.221 119.754 24.233 ;
     RECT  177.516 22.045 177.534 24.233 ;
     RECT  38.088 24.221 70.614 24.269 ;
     RECT  115.815 24.233 119.718 24.269 ;
     RECT  120.924 24.125 123.21 24.269 ;
     RECT  235.944 23.419 236.538 24.283 ;
     RECT  142.56 23.549 144.018 24.331 ;
     RECT  144.792 24.097 152.622 24.331 ;
     RECT  164.415 23.935 164.934 24.331 ;
     RECT  165.888 23.387 165.942 24.331 ;
     RECT  38.232 24.269 70.614 24.359 ;
     RECT  72.108 24.233 78.606 24.359 ;
     RECT  124.38 24.169 140.778 24.359 ;
     RECT  155.304 24.205 155.61 24.359 ;
     RECT  219.528 17.105 219.906 24.359 ;
     RECT  168.984 23.971 170.406 24.367 ;
     RECT  124.38 24.359 140.742 24.368 ;
     RECT  142.56 24.331 152.622 24.379 ;
     RECT  38.772 24.359 70.614 24.395 ;
     RECT  142.38 24.379 152.622 24.395 ;
     RECT  86.652 24.139 98.226 24.413 ;
     RECT  99.144 23.927 108.954 24.467 ;
     RECT  230.292 23.729 230.31 24.467 ;
     RECT  36.648 24.089 37.314 24.503 ;
     RECT  99.144 24.467 103.374 24.511 ;
     RECT  142.38 24.395 151.074 24.511 ;
     RECT  153.615 23.081 153.897 24.511 ;
     RECT  167.004 24.133 168.174 24.511 ;
     RECT  168.984 24.367 170.514 24.511 ;
     RECT  227.7 23.549 228.15 24.511 ;
     RECT  229.176 23.701 229.497 24.511 ;
     RECT  72.324 24.359 78.462 24.512 ;
     RECT  79.38 23.819 79.578 24.601 ;
     RECT  109.728 23.935 114.678 24.601 ;
     RECT  141.516 24.241 141.534 24.601 ;
     RECT  142.344 24.511 151.074 24.601 ;
     RECT  218.415 22.811 218.697 24.601 ;
     RECT  224.856 23.933 226.026 24.601 ;
     RECT  36.648 24.503 36.99 24.629 ;
     RECT  52.308 24.395 70.614 24.629 ;
     RECT  74.736 24.512 78.462 24.629 ;
     RECT  79.38 24.601 79.65 24.629 ;
     RECT  80.46 24.089 80.478 24.629 ;
     RECT  87.156 24.413 98.226 24.629 ;
     RECT  115.815 24.269 119.43 24.629 ;
     RECT  124.488 24.368 140.742 24.629 ;
     RECT  141.516 24.601 151.074 24.629 ;
     RECT  205.2 23.629 210.186 24.637 ;
     RECT  211.248 23.521 211.266 24.637 ;
     RECT  87.156 24.629 87.786 24.653 ;
     RECT  88.704 24.629 94.77 24.665 ;
     RECT  115.815 24.629 118.458 24.665 ;
     RECT  141.696 24.629 151.074 24.701 ;
     RECT  151.848 24.395 152.622 24.709 ;
     RECT  38.772 24.395 51.318 24.737 ;
     RECT  23.328 24.089 33.678 24.745 ;
     RECT  34.524 24.089 35.91 24.745 ;
     RECT  104.148 24.467 108.954 24.745 ;
     RECT  109.728 24.601 114.714 24.745 ;
     RECT  186.015 18.557 186.297 24.745 ;
     RECT  104.148 24.745 114.714 24.781 ;
     RECT  174.672 19.309 175.842 24.781 ;
     RECT  176.724 23.863 176.742 24.781 ;
     RECT  52.38 24.629 70.614 24.797 ;
     RECT  224.856 24.601 226.314 24.809 ;
     RECT  99 24.511 103.374 24.893 ;
     RECT  54.936 24.797 70.614 24.899 ;
     RECT  74.736 24.629 75.942 24.899 ;
     RECT  79.56 24.629 79.65 24.899 ;
     RECT  88.704 24.665 89.766 24.899 ;
     RECT  90.576 24.665 94.77 24.899 ;
     RECT  115.815 24.665 118.206 24.901 ;
     RECT  227.7 24.511 229.497 24.907 ;
     RECT  87.732 24.653 87.786 24.935 ;
     RECT  88.704 24.899 89.097 24.935 ;
     RECT  90.576 24.899 91.53 24.935 ;
     RECT  104.148 24.781 114.75 24.935 ;
     RECT  142.128 24.701 151.074 24.935 ;
     RECT  235.908 24.283 236.538 24.935 ;
     RECT  115.812 24.901 118.206 24.941 ;
     RECT  174.276 24.781 176.742 24.941 ;
     RECT  172.548 24.907 172.566 24.944 ;
     RECT  99 24.893 103.158 24.971 ;
     RECT  119.412 24.629 119.43 24.971 ;
     RECT  142.164 24.935 151.074 24.971 ;
     RECT  151.848 24.709 152.766 24.971 ;
     RECT  164.415 24.331 165.942 24.971 ;
     RECT  64.332 24.899 70.614 25.003 ;
     RECT  71.352 24.907 71.37 25.003 ;
     RECT  104.148 24.935 114.714 25.043 ;
     RECT  120.924 24.269 123.174 25.043 ;
     RECT  167.004 24.511 170.514 25.045 ;
     RECT  153.615 24.511 154.458 25.051 ;
     RECT  64.332 25.003 71.37 25.079 ;
     RECT  87.768 24.935 87.786 25.079 ;
     RECT  101.16 24.971 103.158 25.079 ;
     RECT  104.148 25.043 114.642 25.079 ;
     RECT  151.848 24.971 152.55 25.085 ;
     RECT  38.772 24.737 51.297 25.099 ;
     RECT  91.476 24.935 91.53 25.133 ;
     RECT  23.328 24.745 35.91 25.141 ;
     RECT  155.592 24.359 155.61 25.141 ;
     RECT  166.932 25.045 170.514 25.141 ;
     RECT  171.612 23.323 171.63 25.141 ;
     RECT  232.884 22.739 234.897 25.147 ;
     RECT  235.908 24.935 235.926 25.147 ;
     RECT  64.404 25.079 71.37 25.169 ;
     RECT  90.576 24.935 90.738 25.169 ;
     RECT  99 24.971 100.17 25.169 ;
     RECT  164.415 24.971 165.474 25.169 ;
     RECT  185.508 24.745 186.297 25.169 ;
     RECT  124.488 24.629 140.706 25.177 ;
     RECT  142.524 24.971 151.074 25.177 ;
     RECT  151.848 25.085 152.334 25.177 ;
     RECT  153.432 25.051 154.458 25.177 ;
     RECT  155.592 25.141 155.646 25.177 ;
     RECT  166.932 25.141 170.586 25.177 ;
     RECT  174.384 24.941 176.742 25.177 ;
     RECT  38.124 25.099 51.297 25.181 ;
     RECT  95.508 24.629 98.226 25.181 ;
     RECT  92.412 24.899 94.77 25.205 ;
     RECT  99 25.169 100.026 25.205 ;
     RECT  69.48 25.169 71.37 25.213 ;
     RECT  72.324 24.512 73.926 25.213 ;
     RECT  157.32 23.701 157.878 25.213 ;
     RECT  159.015 22.235 159.297 25.213 ;
     RECT  160.164 23.125 160.182 25.213 ;
     RECT  171.612 25.141 171.666 25.213 ;
     RECT  124.38 25.177 140.706 25.229 ;
     RECT  101.16 25.079 102.942 25.241 ;
     RECT  120.924 25.043 122.562 25.241 ;
     RECT  171.576 25.213 171.666 25.241 ;
     RECT  38.124 25.181 44.298 25.249 ;
     RECT  69.48 25.213 73.926 25.249 ;
     RECT  74.736 24.899 75.114 25.249 ;
     RECT  68.4 25.169 68.742 25.277 ;
     RECT  95.508 25.181 97.002 25.277 ;
     RECT  174.384 25.177 177.174 25.277 ;
     RECT  90.648 25.169 90.738 25.313 ;
     RECT  97.992 25.181 98.226 25.321 ;
     RECT  162.468 24.709 162.486 25.321 ;
     RECT  69.48 25.249 75.114 25.349 ;
     RECT  124.38 25.229 138.546 25.349 ;
     RECT  221.652 23.933 224.097 25.387 ;
     RECT  224.856 24.809 226.026 25.387 ;
     RECT  227.592 24.907 229.497 25.411 ;
     RECT  52.38 24.797 54.162 25.435 ;
     RECT  45.54 25.181 51.297 25.439 ;
     RECT  54.936 24.899 63.27 25.439 ;
     RECT  64.404 25.169 67.497 25.439 ;
     RECT  69.48 25.349 70.074 25.439 ;
     RECT  71.244 25.349 75.114 25.439 ;
     RECT  77.148 24.629 78.462 25.439 ;
     RECT  92.736 25.205 94.77 25.439 ;
     RECT  99.615 25.205 100.026 25.439 ;
     RECT  104.148 25.079 112.158 25.439 ;
     RECT  124.38 25.349 128.682 25.439 ;
     RECT  129.456 25.349 138.546 25.439 ;
     RECT  142.524 25.177 152.334 25.439 ;
     RECT  153.432 25.177 155.646 25.439 ;
     RECT  166.32 25.177 170.586 25.439 ;
     RECT  171.576 25.241 171.63 25.439 ;
     RECT  221.652 25.387 226.026 25.439 ;
     RECT  120.924 25.241 122.346 25.447 ;
     RECT  160.128 25.213 160.182 25.447 ;
     RECT  52.02 25.435 54.162 25.475 ;
     RECT  69.48 25.439 69.786 25.475 ;
     RECT  74.916 25.439 75.114 25.475 ;
     RECT  95.868 25.277 97.002 25.475 ;
     RECT  104.148 25.439 108.81 25.475 ;
     RECT  115.815 24.941 118.206 25.475 ;
     RECT  126.615 25.439 128.502 25.475 ;
     RECT  162.468 25.321 162.522 25.51 ;
     RECT  45.54 25.439 49.122 25.511 ;
     RECT  71.244 25.439 73.926 25.511 ;
     RECT  90.648 25.313 90.666 25.511 ;
     RECT  93.744 25.439 94.77 25.511 ;
     RECT  139.5 25.229 140.706 25.511 ;
     RECT  153.612 25.439 155.646 25.511 ;
     RECT  168.552 25.439 168.786 25.511 ;
     RECT  38.052 25.249 44.298 25.517 ;
     RECT  48.852 25.511 49.05 25.517 ;
     RECT  129.492 25.439 138.546 25.517 ;
     RECT  38.052 25.517 43.47 25.547 ;
     RECT  45.54 25.511 47.61 25.547 ;
     RECT  52.452 25.475 54.162 25.547 ;
     RECT  54.936 25.439 60.57 25.547 ;
     RECT  61.452 25.439 63.27 25.547 ;
     RECT  69.516 25.475 69.786 25.547 ;
     RECT  93.852 25.511 94.698 25.547 ;
     RECT  97.992 25.321 98.694 25.547 ;
     RECT  109.764 25.439 112.158 25.547 ;
     RECT  38.088 25.547 43.47 25.565 ;
     RECT  97.992 25.547 98.262 25.565 ;
     RECT  130.536 25.517 138.546 25.565 ;
     RECT  142.524 25.439 151.074 25.565 ;
     RECT  23.328 25.141 36.45 25.583 ;
     RECT  44.28 25.517 44.298 25.583 ;
     RECT  58.356 25.547 60.57 25.583 ;
     RECT  61.524 25.547 63.27 25.583 ;
     RECT  64.404 25.439 65.322 25.583 ;
     RECT  71.964 25.511 73.926 25.583 ;
     RECT  75.924 24.899 75.942 25.583 ;
     RECT  92.736 25.439 92.754 25.583 ;
     RECT  93.852 25.547 94.497 25.583 ;
     RECT  96.156 25.475 97.002 25.583 ;
     RECT  98.172 25.565 98.262 25.583 ;
     RECT  101.16 25.241 102.69 25.583 ;
     RECT  108.648 25.475 108.666 25.583 ;
     RECT  129.492 25.517 129.51 25.583 ;
     RECT  23.328 25.583 35.658 25.591 ;
     RECT  157.32 25.213 159.297 25.591 ;
     RECT  160.128 25.447 160.218 25.591 ;
     RECT  162.468 25.51 162.558 25.591 ;
     RECT  23.292 25.591 35.658 25.613 ;
     RECT  38.34 25.565 41.742 25.613 ;
     RECT  227.592 25.411 229.734 25.613 ;
     RECT  33.876 25.613 35.658 25.619 ;
     RECT  50.184 25.439 51.297 25.619 ;
     RECT  52.776 25.547 53.082 25.619 ;
     RECT  54.936 25.547 57.546 25.619 ;
     RECT  64.8 25.583 64.962 25.619 ;
     RECT  101.484 25.583 102.69 25.619 ;
     RECT  104.148 25.475 107.73 25.619 ;
     RECT  109.764 25.547 111.366 25.619 ;
     RECT  130.536 25.565 131.202 25.619 ;
     RECT  132.015 25.565 138.546 25.619 ;
     RECT  142.524 25.565 149.562 25.619 ;
     RECT  150.444 25.565 151.074 25.619 ;
     RECT  153.612 25.511 154.602 25.619 ;
     RECT  162.396 25.591 162.558 25.619 ;
     RECT  139.932 25.511 140.706 25.661 ;
     RECT  142.56 25.619 149.562 25.661 ;
     RECT  155.52 25.511 155.646 25.661 ;
     RECT  157.248 25.591 159.297 25.661 ;
     RECT  166.32 25.439 167.562 25.661 ;
     RECT  168.552 25.511 168.714 25.661 ;
     RECT  174.384 25.277 177.102 25.661 ;
     RECT  33.876 25.619 35.097 25.667 ;
     RECT  45.54 25.547 45.897 25.667 ;
     RECT  50.94 25.619 51.297 25.667 ;
     RECT  56.16 25.619 56.697 25.667 ;
     RECT  61.815 25.583 63.27 25.667 ;
     RECT  66.492 25.439 67.497 25.667 ;
     RECT  88.815 24.935 89.097 25.667 ;
     RECT  94.215 25.583 94.497 25.667 ;
     RECT  99.615 25.439 99.897 25.667 ;
     RECT  104.148 25.619 105.297 25.667 ;
     RECT  158.94 25.661 159.297 25.667 ;
     RECT  164.415 25.169 165.438 25.667 ;
     RECT  180.615 10.589 180.897 25.667 ;
     RECT  186.015 25.169 186.297 25.667 ;
     RECT  191.415 17.105 191.697 25.667 ;
     RECT  196.815 17.117 197.097 25.667 ;
     RECT  202.215 15.179 202.497 25.667 ;
     RECT  169.524 25.439 170.586 25.681 ;
     RECT  171.576 25.439 171.594 25.681 ;
     RECT  227.7 25.613 229.734 25.681 ;
     RECT  39.348 25.613 41.742 25.709 ;
     RECT  46.656 25.547 47.61 25.709 ;
     RECT  52.812 25.619 53.082 25.709 ;
     RECT  53.856 25.547 54.162 25.709 ;
     RECT  54.936 25.619 55.386 25.709 ;
     RECT  56.16 25.667 56.682 25.709 ;
     RECT  101.484 25.619 102.294 25.709 ;
     RECT  132.015 25.619 135.81 25.709 ;
     RECT  136.584 25.619 138.546 25.709 ;
     RECT  142.56 25.661 145.026 25.709 ;
     RECT  145.836 25.661 149.562 25.709 ;
     RECT  155.808 25.672 155.826 25.709 ;
     RECT  166.32 25.661 167.49 25.709 ;
     RECT  174.384 25.661 176.742 25.709 ;
     RECT  178.992 23.053 179.01 25.709 ;
     RECT  227.7 25.681 230.31 25.709 ;
     RECT  174.384 25.709 176.238 25.717 ;
     RECT  180.615 25.667 180.705 25.717 ;
     RECT  205.2 24.637 211.266 25.717 ;
     RECT  232.884 25.147 235.926 25.717 ;
     RECT  54.936 25.709 55.242 25.745 ;
     RECT  101.484 25.709 102.222 25.745 ;
     RECT  169.524 25.681 171.594 25.757 ;
     RECT  83.415 23.585 83.697 25.771 ;
     RECT  120.276 25.447 122.346 25.781 ;
     RECT  157.968 25.661 158.058 25.781 ;
     RECT  230.292 25.709 230.31 25.781 ;
     RECT  204.696 25.717 211.266 25.789 ;
     RECT  72.324 25.583 73.926 25.805 ;
     RECT  50.94 25.667 51.174 25.817 ;
     RECT  59.436 25.583 60.57 25.817 ;
     RECT  83.415 25.771 84.186 25.817 ;
     RECT  101.484 25.745 101.502 25.817 ;
     RECT  132.015 25.709 135.63 25.817 ;
     RECT  140.22 25.661 140.706 25.817 ;
     RECT  166.32 25.709 166.734 25.817 ;
     RECT  173.808 25.717 176.238 25.817 ;
     RECT  179.964 25.717 180.705 25.817 ;
     RECT  142.56 25.709 144.918 25.853 ;
     RECT  169.524 25.757 170.514 25.853 ;
     RECT  119.448 25.771 119.466 25.861 ;
     RECT  178.488 25.717 178.506 25.861 ;
     RECT  39.348 25.709 40.305 25.889 ;
     RECT  152.136 25.439 152.334 25.889 ;
     RECT  177.84 25.861 178.506 25.889 ;
     RECT  180.036 25.817 180.705 25.889 ;
     RECT  119.16 25.861 119.538 25.915 ;
     RECT  33.876 25.667 34.905 25.937 ;
     RECT  39.564 25.889 40.305 25.937 ;
     RECT  50.94 25.817 51.105 25.937 ;
     RECT  61.815 25.667 61.905 25.937 ;
     RECT  72.324 25.805 72.705 25.937 ;
     RECT  83.415 25.817 83.505 25.937 ;
     RECT  94.215 25.667 94.305 25.937 ;
     RECT  104.148 25.667 105.105 25.937 ;
     RECT  115.815 25.475 117.738 25.937 ;
     RECT  126.615 25.475 127.926 25.937 ;
     RECT  132.015 25.817 134.658 25.937 ;
     RECT  142.815 25.853 144.918 25.937 ;
     RECT  153.615 25.619 154.602 25.937 ;
     RECT  158.94 25.667 159.105 25.937 ;
     RECT  164.415 25.667 164.505 25.937 ;
     RECT  169.815 25.853 170.514 25.937 ;
     RECT  174.672 25.817 176.238 25.937 ;
     RECT  180.615 25.889 180.705 25.937 ;
     RECT  186.015 25.667 186.174 25.937 ;
     RECT  191.415 25.667 191.505 25.937 ;
     RECT  196.815 25.667 196.905 25.937 ;
     RECT  202.215 25.667 202.305 25.937 ;
     RECT  45.54 25.667 45.882 25.951 ;
     RECT  54.144 25.709 54.162 25.951 ;
     RECT  88.815 25.667 89.01 25.951 ;
     RECT  99.615 25.667 99.81 25.951 ;
     RECT  224.856 25.439 226.026 25.951 ;
     RECT  113.22 25.079 114.642 25.979 ;
     RECT  118.584 25.915 119.538 25.979 ;
     RECT  131.184 25.619 131.202 25.979 ;
     RECT  153.756 25.937 154.602 25.979 ;
     RECT  158.04 25.781 158.058 25.979 ;
     RECT  162.396 25.619 162.522 25.979 ;
     RECT  45.504 25.951 45.882 25.997 ;
     RECT  56.304 25.709 56.682 25.997 ;
     RECT  66.492 25.667 67.41 25.997 ;
     RECT  88.704 25.951 89.01 25.997 ;
     RECT  99.504 25.951 99.81 25.997 ;
     RECT  54.144 25.951 54.738 26.015 ;
     RECT  132.66 25.937 134.658 26.015 ;
     RECT  118.584 25.979 119.178 26.045 ;
     RECT  120.276 25.781 122.058 26.045 ;
     RECT  47.52 25.709 47.538 26.051 ;
     RECT  54.72 26.015 54.738 26.051 ;
     RECT  56.664 25.997 56.682 26.051 ;
     RECT  62.712 25.667 63.27 26.051 ;
     RECT  69.768 25.547 69.786 26.051 ;
     RECT  132.66 26.015 134.082 26.051 ;
     RECT  137.016 25.709 138.546 26.051 ;
     RECT  147.636 25.709 149.562 26.051 ;
     RECT  154.548 25.979 154.602 26.051 ;
     RECT  162.504 25.979 162.522 26.051 ;
     RECT  170.496 25.937 170.514 26.051 ;
     RECT  171.576 25.757 171.594 26.051 ;
     RECT  224.856 25.951 226.314 26.051 ;
     RECT  39.564 25.937 39.654 26.087 ;
     RECT  42.768 25.565 43.47 26.087 ;
     RECT  45.756 25.997 45.882 26.087 ;
     RECT  120.276 26.045 120.294 26.087 ;
     RECT  165.312 25.667 165.438 26.087 ;
     RECT  204.624 25.789 211.266 26.087 ;
     RECT  232.884 25.717 235.962 26.123 ;
     RECT  109.8 25.619 111.366 26.141 ;
     RECT  227.7 25.709 229.554 26.141 ;
     RECT  41.724 25.709 41.742 26.189 ;
     RECT  119.16 26.045 119.178 26.237 ;
     RECT  143.028 25.937 144.918 26.237 ;
     RECT  160.128 25.591 160.722 26.237 ;
     RECT  165.312 26.087 165.33 26.237 ;
     RECT  167.472 25.709 167.49 26.237 ;
     RECT  48.924 25.517 48.942 26.249 ;
     RECT  112.14 25.547 112.158 26.249 ;
     RECT  221.652 25.439 224.097 26.251 ;
     RECT  224.856 26.051 226.026 26.251 ;
     RECT  62.784 26.051 63.27 26.285 ;
     RECT  121.356 26.045 122.058 26.285 ;
     RECT  221.652 26.251 226.026 26.291 ;
     RECT  58.356 25.583 58.374 26.321 ;
     RECT  127.008 25.937 127.926 26.321 ;
     RECT  137.016 26.051 138.222 26.321 ;
     RECT  217.764 24.601 218.697 26.321 ;
     RECT  33.876 25.937 34.326 26.333 ;
     RECT  143.028 26.237 143.73 26.333 ;
     RECT  68.544 25.277 68.742 26.357 ;
     RECT  74.988 25.475 75.114 26.357 ;
     RECT  230.472 26.131 230.49 26.357 ;
     RECT  38.484 25.613 38.502 26.393 ;
     RECT  60.372 25.817 60.57 26.393 ;
     RECT  121.356 26.285 121.374 26.393 ;
     RECT  135.612 25.817 135.63 26.393 ;
     RECT  7.092 9.689 8.097 26.401 ;
     RECT  81.288 24.089 81.306 26.429 ;
     RECT  109.8 26.141 110.214 26.429 ;
     RECT  175.824 25.937 176.238 26.429 ;
     RECT  34.308 26.333 34.326 26.474 ;
     RECT  63.252 26.285 63.27 26.474 ;
     RECT  104.148 25.937 104.742 26.474 ;
     RECT  143.028 26.333 143.658 26.474 ;
     RECT  57.528 25.619 57.546 26.477 ;
     RECT  124.956 25.439 125.298 26.477 ;
     RECT  140.688 25.817 140.706 26.477 ;
     RECT  166.716 25.817 166.734 26.477 ;
     RECT  150.588 25.619 151.074 26.519 ;
     RECT  147.996 26.051 149.562 26.525 ;
     RECT  53.064 25.709 53.082 26.555 ;
     RECT  153.756 25.979 153.774 26.555 ;
     RECT  232.884 26.123 235.386 26.555 ;
     RECT  111.204 26.141 111.366 26.573 ;
     RECT  147.996 26.525 148.77 26.573 ;
     RECT  176.22 26.429 176.238 26.591 ;
     RECT  186.156 25.937 186.174 26.627 ;
     RECT  226.764 26.131 226.782 26.635 ;
     RECT  227.7 26.141 229.497 26.635 ;
     RECT  109.836 26.429 110.214 26.669 ;
     RECT  68.544 26.357 68.562 26.699 ;
     RECT  111.204 26.573 111.222 26.699 ;
     RECT  226.764 26.635 229.497 26.699 ;
     RECT  50.94 25.937 50.994 26.717 ;
     RECT  96.984 25.583 97.002 26.761 ;
     RECT  124.956 26.477 124.974 26.761 ;
     RECT  158.94 25.937 158.958 26.765 ;
     RECT  96.912 26.761 97.002 26.789 ;
     RECT  124.884 26.761 124.974 26.789 ;
     RECT  226.764 26.699 228.222 26.789 ;
     RECT  237.492 26.587 237.51 26.825 ;
     RECT  216.864 19.201 216.882 26.861 ;
     RECT  107.028 25.619 107.73 26.897 ;
     RECT  91.512 25.133 91.53 26.933 ;
     RECT  132.66 26.051 132.93 26.933 ;
     RECT  134.064 26.051 134.082 26.969 ;
     RECT  72.324 25.937 72.342 27.014 ;
     RECT  160.128 26.237 160.146 27.014 ;
     RECT  224.856 26.291 226.026 27.031 ;
     RECT  226.764 26.789 228.186 27.031 ;
     RECT  174.672 25.937 174.69 27.059 ;
     RECT  77.832 25.439 78.462 27.095 ;
     RECT  145.836 25.709 146.394 27.095 ;
     RECT  232.884 26.555 234.897 27.103 ;
     RECT  75.096 26.357 75.114 27.131 ;
     RECT  96.912 26.789 96.93 27.131 ;
     RECT  147.996 26.573 148.374 27.131 ;
     RECT  177.84 25.889 177.858 27.131 ;
     RECT  235.944 26.875 235.962 27.163 ;
     RECT  66.492 25.997 66.51 27.167 ;
     RECT  107.028 26.897 107.694 27.167 ;
     RECT  150.588 26.519 150.606 27.167 ;
     RECT  168.696 25.661 168.714 27.167 ;
     RECT  73.584 25.805 73.926 27.197 ;
     RECT  43.452 26.087 43.47 27.203 ;
     RECT  109.944 26.669 110.214 27.203 ;
     RECT  146.376 27.095 146.394 27.203 ;
     RECT  39.636 26.087 39.654 27.239 ;
     RECT  73.584 27.197 73.602 27.245 ;
     RECT  50.94 26.717 50.958 27.293 ;
     RECT  224.856 27.031 228.186 27.329 ;
     RECT  228.96 26.699 229.497 27.329 ;
     RECT  77.832 27.095 77.85 27.341 ;
     RECT  235.944 27.163 236.538 27.365 ;
     RECT  224.856 27.329 228.042 27.401 ;
     RECT  225.432 27.401 228.042 27.437 ;
     RECT  221.652 26.291 224.097 27.509 ;
     RECT  225.72 27.437 228.042 27.869 ;
     RECT  229.215 27.329 229.497 27.949 ;
     RECT  230.292 27.607 230.31 27.949 ;
     RECT  225.72 27.869 226.782 27.965 ;
     RECT  223.164 27.509 224.097 27.985 ;
     RECT  23.292 25.613 32.922 28.08 ;
     RECT  36.432 25.583 36.45 28.08 ;
     RECT  45.756 26.087 45.774 28.08 ;
     RECT  59.436 25.817 59.454 28.08 ;
     RECT  60.552 26.393 60.57 28.08 ;
     RECT  79.632 24.899 79.65 28.08 ;
     RECT  104.148 26.474 104.166 28.08 ;
     RECT  107.352 27.167 107.694 28.08 ;
     RECT  109.944 27.203 109.962 28.08 ;
     RECT  113.22 25.979 114.426 28.08 ;
     RECT  116.604 25.937 117.738 28.08 ;
     RECT  124.884 26.789 124.902 28.08 ;
     RECT  127.008 26.321 127.674 28.08 ;
     RECT  137.232 26.321 138.222 28.08 ;
     RECT  143.028 26.474 143.046 28.08 ;
     RECT  144.9 26.237 144.918 28.08 ;
     RECT  148.356 27.131 148.374 28.08 ;
     RECT  149.544 26.525 149.562 28.08 ;
     RECT  152.316 25.889 152.334 28.08 ;
     RECT  154.584 26.051 154.602 28.08 ;
     RECT  205.2 26.087 211.266 28.08 ;
     RECT  18.615 22.208 18.897 28.111 ;
     RECT  218.415 26.321 218.697 28.183 ;
     RECT  219.528 24.359 219.726 28.183 ;
     RECT  229.215 27.949 230.31 28.183 ;
     RECT  218.415 28.183 219.726 28.219 ;
     RECT  227.7 27.869 228.042 28.291 ;
     RECT  228.888 28.183 230.31 28.291 ;
     RECT  223.164 27.985 224.622 28.381 ;
     RECT  225.396 28.291 225.414 28.381 ;
     RECT  227.7 28.291 230.346 28.409 ;
     RECT  231.12 28.021 231.138 28.409 ;
     RECT  227.7 28.409 230.202 28.445 ;
     RECT  229.14 28.445 230.202 28.451 ;
     RECT  218.268 28.219 219.726 28.651 ;
     RECT  226.332 27.965 226.782 28.723 ;
     RECT  226.26 28.723 226.782 28.751 ;
     RECT  227.7 28.445 228.186 28.795 ;
     RECT  226.26 28.751 226.278 28.823 ;
     RECT  229.14 28.451 229.497 28.949 ;
     RECT  235.944 27.365 235.962 28.985 ;
     RECT  227.052 28.795 228.186 29.069 ;
     RECT  232.632 27.103 234.897 29.191 ;
     RECT  223.164 28.381 225.414 29.371 ;
     RECT  230.292 29.227 230.31 29.399 ;
     RECT  237.492 29.227 237.51 29.515 ;
     RECT  218.232 28.651 219.726 29.549 ;
     RECT  223.164 29.371 225.594 29.561 ;
     RECT  237.456 29.515 237.51 29.669 ;
     RECT  232.632 29.191 234.954 29.759 ;
     RECT  237.492 29.669 237.51 29.831 ;
     RECT  223.164 29.561 225.162 29.867 ;
     RECT  229.215 28.949 229.497 29.875 ;
     RECT  229.104 29.875 229.497 29.911 ;
     RECT  221.652 27.509 222.426 30.001 ;
     RECT  223.164 29.867 224.766 30.001 ;
     RECT  229.104 29.911 229.914 30.029 ;
     RECT  221.652 30.001 224.766 30.125 ;
     RECT  229.104 30.029 229.497 30.145 ;
     RECT  223.164 30.125 224.766 30.209 ;
     RECT  228.924 30.145 229.497 30.221 ;
     RECT  227.052 29.069 227.718 30.271 ;
     RECT  227.052 30.271 228.402 30.283 ;
     RECT  236.52 29.803 236.538 30.379 ;
     RECT  227.016 30.283 228.402 30.461 ;
     RECT  226.08 30.451 226.098 30.569 ;
     RECT  227.016 30.461 228.294 30.605 ;
     RECT  230.256 30.271 230.31 30.749 ;
     RECT  23.292 28.08 211.266 30.859 ;
     RECT  225.036 30.883 225.054 30.919 ;
     RECT  225.036 30.919 225.666 31.019 ;
     RECT  232.632 29.759 234.897 31.081 ;
     RECT  235.944 30.379 236.538 31.081 ;
     RECT  225.036 31.019 225.594 31.109 ;
     RECT  226.656 30.883 226.89 31.109 ;
     RECT  223.164 30.209 224.097 31.195 ;
     RECT  225.036 31.109 225.45 31.195 ;
     RECT  232.632 31.081 236.538 31.243 ;
     RECT  226.728 31.109 226.89 31.289 ;
     RECT  229.215 30.221 229.497 31.339 ;
     RECT  223.164 31.195 225.45 31.379 ;
     RECT  213.015 18.527 213.297 31.435 ;
     RECT  214.344 31.387 214.362 31.487 ;
     RECT  226.764 31.289 226.89 31.531 ;
     RECT  227.7 30.605 227.718 31.531 ;
     RECT  226.764 31.531 227.718 31.729 ;
     RECT  228.744 31.339 229.497 31.729 ;
     RECT  23.292 30.859 211.59 31.765 ;
     RECT  212.4 31.435 213.297 31.765 ;
     RECT  23.292 31.765 213.297 31.793 ;
     RECT  226.764 31.729 229.497 31.949 ;
     RECT  226.764 31.949 228.294 32.071 ;
     RECT  226.404 32.071 228.294 32.161 ;
     RECT  226.188 32.161 228.294 32.189 ;
     RECT  232.632 31.243 236.574 32.189 ;
     RECT  235.944 32.189 236.574 32.261 ;
     RECT  226.188 32.189 228.078 32.297 ;
     RECT  236.556 32.261 236.574 32.333 ;
     RECT  226.26 32.297 228.078 32.339 ;
     RECT  214.236 31.915 214.254 32.341 ;
     RECT  226.26 32.339 226.926 32.369 ;
     RECT  214.128 32.341 214.362 32.459 ;
     RECT  225.216 31.379 225.45 32.459 ;
     RECT  225.216 32.459 225.234 32.495 ;
     RECT  226.332 32.369 226.926 32.495 ;
     RECT  223.164 31.379 224.097 32.503 ;
     RECT  223.164 32.503 224.442 32.611 ;
     RECT  212.04 31.793 213.297 32.729 ;
     RECT  237.492 31.819 237.51 32.731 ;
     RECT  230.292 30.749 230.31 32.909 ;
     RECT  218.415 29.549 219.726 32.971 ;
     RECT  232.632 32.189 235.134 32.999 ;
     RECT  218.304 32.971 219.726 33.008 ;
     RECT  229.215 31.949 229.497 33.259 ;
     RECT  217.476 33.067 217.494 33.269 ;
     RECT  231.12 33.151 231.138 33.269 ;
     RECT  223.164 32.611 225.162 33.305 ;
     RECT  229.104 33.259 230.202 33.305 ;
     RECT  212.292 32.729 213.297 33.413 ;
     RECT  232.632 32.999 235.026 33.539 ;
     RECT  227.7 32.339 228.078 33.583 ;
     RECT  227.7 33.583 228.114 33.691 ;
     RECT  237.456 32.731 237.51 33.845 ;
     RECT  227.7 33.691 228.186 33.889 ;
     RECT  229.104 33.305 229.497 33.889 ;
     RECT  218.415 33.008 219.726 34.123 ;
     RECT  220.86 23.665 220.878 34.123 ;
     RECT  225.144 33.305 225.162 34.159 ;
     RECT  223.164 33.305 224.37 34.171 ;
     RECT  225.144 34.159 225.27 34.171 ;
     RECT  226.512 32.495 226.926 34.219 ;
     RECT  227.7 33.889 229.497 34.219 ;
     RECT  213.015 33.413 213.297 34.363 ;
     RECT  214.128 32.459 214.146 34.363 ;
     RECT  226.512 34.219 229.497 34.385 ;
     RECT  230.256 34.231 230.274 34.493 ;
     RECT  213.015 34.363 214.146 34.619 ;
     RECT  226.512 34.385 226.53 34.627 ;
     RECT  230.292 34.627 230.31 34.727 ;
     RECT  223.164 34.171 225.27 34.889 ;
     RECT  237.492 33.845 237.51 34.925 ;
     RECT  232.632 33.539 234.897 35.041 ;
     RECT  214.128 34.619 214.146 35.069 ;
     RECT  231.984 35.041 234.897 35.131 ;
     RECT  226.296 34.627 226.53 35.159 ;
     RECT  231.84 35.131 234.897 35.159 ;
     RECT  231.84 35.159 231.858 35.203 ;
     RECT  231.552 35.203 231.858 35.231 ;
     RECT  227.628 34.385 229.497 35.275 ;
     RECT  231.552 35.231 231.57 35.275 ;
     RECT  231.048 35.275 231.57 35.312 ;
     RECT  231.552 35.312 231.57 35.339 ;
     RECT  223.164 34.889 225.198 35.429 ;
     RECT  218.415 34.123 220.878 35.581 ;
     RECT  227.628 35.275 230.058 35.581 ;
     RECT  227.484 35.581 230.058 35.699 ;
     RECT  226.512 35.159 226.53 35.941 ;
     RECT  232.632 35.159 234.897 35.941 ;
     RECT  226.296 35.941 226.71 35.981 ;
     RECT  237.492 35.899 237.51 36.029 ;
     RECT  228.816 35.699 230.058 36.049 ;
     RECT  228.816 36.049 230.202 36.085 ;
     RECT  226.296 35.981 226.638 36.113 ;
     RECT  225.18 35.429 225.198 36.121 ;
     RECT  226.296 36.113 226.314 36.121 ;
     RECT  235.944 33.019 235.962 36.187 ;
     RECT  223.164 35.429 224.37 36.239 ;
     RECT  225.18 36.121 226.314 36.269 ;
     RECT  228.816 36.085 230.274 36.517 ;
     RECT  228.816 36.517 230.31 36.589 ;
     RECT  235.908 36.187 235.962 36.763 ;
     RECT  228.816 36.589 230.67 36.779 ;
     RECT  235.908 36.763 236.538 36.815 ;
     RECT  226.296 36.269 226.314 36.931 ;
     RECT  227.484 35.699 228.006 36.931 ;
     RECT  228.816 36.779 229.497 36.931 ;
     RECT  227.484 36.931 229.497 37.049 ;
     RECT  232.632 35.941 234.954 37.049 ;
     RECT  235.908 36.815 235.962 37.193 ;
     RECT  227.484 37.049 228.006 37.319 ;
     RECT  223.164 36.239 224.298 37.399 ;
     RECT  225.18 36.269 225.198 37.399 ;
     RECT  223.164 37.399 225.198 37.471 ;
     RECT  226.296 36.931 226.494 37.471 ;
     RECT  223.164 37.471 226.494 37.669 ;
     RECT  227.484 37.319 227.718 37.669 ;
     RECT  223.164 37.669 227.718 37.895 ;
     RECT  235.944 37.193 235.962 37.963 ;
     RECT  226.296 37.895 227.718 38.039 ;
     RECT  230.292 36.779 230.31 38.039 ;
     RECT  235.944 37.963 236.538 38.165 ;
     RECT  223.164 37.895 225.27 38.189 ;
     RECT  228.816 37.049 229.497 38.281 ;
     RECT  230.22 38.209 230.238 38.281 ;
     RECT  228.564 38.281 230.238 38.309 ;
     RECT  217.368 33.421 217.386 38.399 ;
     RECT  226.296 38.039 226.314 38.399 ;
     RECT  227.484 38.039 227.718 38.515 ;
     RECT  228.564 38.309 230.166 38.515 ;
     RECT  18.504 28.111 18.897 38.641 ;
     RECT  227.484 38.515 230.166 38.669 ;
     RECT  225.18 38.189 225.27 38.785 ;
     RECT  18.432 38.641 18.897 38.849 ;
     RECT  227.484 38.669 227.718 38.983 ;
     RECT  227.088 38.983 227.718 39.019 ;
     RECT  232.632 37.049 234.897 39.115 ;
     RECT  18.504 38.849 18.897 39.209 ;
     RECT  227.016 39.019 227.718 39.209 ;
     RECT  225.18 38.785 226.242 39.259 ;
     RECT  232.632 39.115 235.098 39.289 ;
     RECT  235.944 38.165 235.962 39.289 ;
     RECT  228.492 38.669 229.497 39.317 ;
     RECT  232.632 39.289 235.962 39.437 ;
     RECT  225.18 39.259 226.278 39.479 ;
     RECT  223.164 38.189 224.097 39.595 ;
     RECT  225.18 39.479 225.198 39.595 ;
     RECT  226.224 39.479 226.278 39.631 ;
     RECT  230.292 39.487 230.31 39.659 ;
     RECT  223.164 39.595 225.198 39.869 ;
     RECT  226.224 39.631 226.386 39.893 ;
     RECT  15.048 39.721 15.066 39.901 ;
     RECT  16.452 39.181 16.47 40.019 ;
     RECT  218.124 35.581 220.878 40.019 ;
     RECT  231.732 39.901 231.75 40.019 ;
     RECT  235.944 39.437 235.962 40.055 ;
     RECT  230.58 40.027 230.778 40.064 ;
     RECT  15.048 39.901 15.138 40.075 ;
     RECT  14.832 40.075 15.138 40.099 ;
     RECT  14.832 40.099 15.318 40.123 ;
     RECT  218.304 40.019 220.878 40.127 ;
     RECT  14.472 40.123 15.318 40.135 ;
     RECT  13.215 20.309 13.497 40.171 ;
     RECT  232.632 39.437 235.098 40.267 ;
     RECT  14.472 40.135 15.858 40.289 ;
     RECT  230.58 40.064 230.598 40.289 ;
     RECT  229.176 39.317 229.497 40.433 ;
     RECT  227.484 39.209 227.718 40.441 ;
     RECT  13.215 40.171 13.734 40.469 ;
     RECT  14.472 40.289 15.174 40.469 ;
     RECT  227.484 40.441 228.33 40.559 ;
     RECT  236.556 40.369 236.574 40.589 ;
     RECT  227.484 40.559 227.718 40.675 ;
     RECT  225.18 39.869 225.198 40.711 ;
     RECT  226.296 39.893 226.386 40.711 ;
     RECT  227.376 40.675 227.718 40.711 ;
     RECT  218.415 40.127 220.878 40.739 ;
     RECT  14.472 40.469 15.066 40.829 ;
     RECT  225.18 40.711 227.718 40.829 ;
     RECT  14.472 40.829 14.994 40.865 ;
     RECT  236.52 40.843 236.538 40.901 ;
     RECT  230.256 40.711 230.31 40.973 ;
     RECT  227.376 40.829 227.718 41.009 ;
     RECT  223.164 39.869 224.097 41.035 ;
     RECT  14.292 40.945 14.31 41.099 ;
     RECT  220.284 40.739 220.878 41.099 ;
     RECT  225.576 40.829 226.458 41.099 ;
     RECT  232.632 40.267 235.386 41.131 ;
     RECT  227.484 41.009 227.718 41.521 ;
     RECT  229.215 40.433 229.497 41.611 ;
     RECT  227.484 41.521 228.006 41.645 ;
     RECT  225.828 41.099 226.458 41.755 ;
     RECT  227.484 41.645 227.718 41.755 ;
     RECT  223.164 41.035 224.622 41.789 ;
     RECT  228.996 41.611 229.497 41.791 ;
     RECT  230.292 40.973 230.31 41.791 ;
     RECT  215.208 34.735 215.226 41.819 ;
     RECT  228.996 41.791 230.31 41.819 ;
     RECT  225.828 41.755 227.718 41.909 ;
     RECT  228.996 41.819 230.274 41.909 ;
     RECT  228.996 41.909 229.497 42.061 ;
     RECT  232.632 41.131 235.962 42.077 ;
     RECT  227.664 41.909 227.718 42.179 ;
     RECT  228.636 42.061 229.497 42.251 ;
     RECT  235.944 42.077 235.962 42.365 ;
     RECT  230.256 41.909 230.274 42.449 ;
     RECT  225.828 41.909 226.854 42.485 ;
     RECT  221.652 30.125 222.426 42.763 ;
     RECT  223.164 41.789 224.097 42.763 ;
     RECT  227.7 42.179 227.718 42.763 ;
     RECT  221.652 42.763 224.586 42.799 ;
     RECT  225.828 42.485 226.314 42.871 ;
     RECT  2.415 7.997 2.697 42.997 ;
     RECT  221.652 42.799 224.73 43.033 ;
     RECT  225.468 42.871 226.314 43.033 ;
     RECT  227.7 42.763 227.79 43.141 ;
     RECT  229.215 42.251 229.497 43.141 ;
     RECT  0.108 43.141 0.126 43.229 ;
     RECT  221.652 43.033 226.314 43.267 ;
     RECT  227.7 43.141 229.497 43.291 ;
     RECT  23.292 31.793 211.266 43.295 ;
     RECT  2.415 42.997 2.862 43.303 ;
     RECT  6.876 26.401 8.097 43.367 ;
     RECT  221.652 43.267 226.35 43.375 ;
     RECT  227.196 43.291 229.497 43.375 ;
     RECT  7.596 43.367 8.097 43.403 ;
     RECT  7.815 43.403 8.097 43.411 ;
     RECT  6.732 43.375 6.75 43.421 ;
     RECT  2.415 43.303 2.934 43.537 ;
     RECT  23.292 43.295 27.774 43.627 ;
     RECT  2.415 43.537 3.186 43.709 ;
     RECT  7.815 43.411 8.154 43.709 ;
     RECT  16.164 43.387 16.182 43.771 ;
     RECT  221.652 43.375 229.497 43.771 ;
     RECT  232.632 42.077 235.098 43.771 ;
     RECT  15.912 43.771 16.182 43.799 ;
     RECT  22.824 43.627 27.774 43.805 ;
     RECT  230.76 43.579 230.778 43.835 ;
     RECT  15.912 43.799 15.93 43.901 ;
     RECT  232.56 43.771 235.098 44.069 ;
     RECT  232.632 44.069 235.098 44.141 ;
     RECT  220.32 41.099 220.878 44.149 ;
     RECT  221.652 43.771 229.698 44.149 ;
     RECT  220.32 44.149 229.698 44.177 ;
     RECT  227.376 44.177 229.698 44.221 ;
     RECT  227.376 44.221 229.914 44.339 ;
     RECT  218.415 40.739 219.402 44.443 ;
     RECT  220.32 44.177 226.602 44.443 ;
     RECT  230.256 44.491 230.274 44.753 ;
     RECT  232.632 44.141 234.99 44.995 ;
     RECT  23.292 43.805 27.774 45.005 ;
     RECT  218.415 44.443 226.602 45.023 ;
     RECT  220.284 45.023 226.602 45.121 ;
     RECT  227.376 44.339 229.497 45.121 ;
     RECT  237.492 44.995 237.51 45.245 ;
     RECT  231.984 44.995 234.99 45.571 ;
     RECT  231.984 45.571 235.098 45.725 ;
     RECT  236.52 42.907 236.538 45.787 ;
     RECT  230.292 45.697 230.31 45.797 ;
     RECT  235.944 45.787 236.538 45.959 ;
     RECT  27.108 45.005 27.774 46.157 ;
     RECT  220.284 45.121 229.497 46.201 ;
     RECT  231.984 45.725 234.897 46.229 ;
     RECT  218.415 45.023 219.402 46.237 ;
     RECT  220.212 46.201 229.497 46.237 ;
     RECT  28.728 43.295 211.266 46.349 ;
     RECT  218.415 46.237 229.497 46.499 ;
     RECT  28.728 46.349 29.61 46.651 ;
     RECT  218.415 46.499 227.97 46.685 ;
     RECT  220.464 46.685 227.97 46.769 ;
     RECT  30.42 46.349 211.266 46.829 ;
     RECT  28.656 46.651 29.61 47.021 ;
     RECT  220.464 46.769 225.774 47.075 ;
     RECT  227.232 46.769 227.79 47.075 ;
     RECT  232.632 46.229 234.897 47.281 ;
     RECT  220.464 47.075 225.702 47.357 ;
     RECT  220.752 47.357 225.702 47.381 ;
     RECT  228.708 46.499 229.497 47.425 ;
     RECT  230.292 47.389 230.31 47.425 ;
     RECT  228.708 47.425 230.31 47.461 ;
     RECT  30.708 46.829 211.266 47.501 ;
     RECT  28.656 47.021 29.43 47.579 ;
     RECT  228.708 47.461 230.958 47.579 ;
     RECT  29.412 47.579 29.43 47.597 ;
     RECT  220.86 47.381 225.702 47.615 ;
     RECT  227.52 47.075 227.538 47.741 ;
     RECT  228.708 47.579 230.67 47.759 ;
     RECT  30.708 47.501 30.798 47.789 ;
     RECT  221.652 47.615 225.702 47.849 ;
     RECT  230.292 47.759 230.67 47.849 ;
     RECT  225.504 47.849 225.702 47.857 ;
     RECT  221.652 47.849 224.586 47.885 ;
     RECT  225.504 47.857 226.314 47.885 ;
     RECT  28.656 47.579 28.674 47.981 ;
     RECT  30.708 47.789 30.726 48.077 ;
     RECT  232.632 47.281 234.99 48.091 ;
     RECT  223.092 47.885 224.586 48.119 ;
     RECT  226.152 47.885 226.314 48.119 ;
     RECT  226.152 48.119 226.17 48.128 ;
     RECT  232.632 48.091 235.098 48.191 ;
     RECT  27.18 46.157 27.774 48.269 ;
     RECT  218.415 46.685 219.402 48.271 ;
     RECT  27.18 48.269 27.45 48.365 ;
     RECT  223.092 48.119 224.19 48.425 ;
     RECT  27.288 48.365 27.45 48.461 ;
     RECT  218.304 48.271 219.402 48.461 ;
     RECT  223.164 48.425 224.19 48.461 ;
     RECT  27.432 48.461 27.45 48.749 ;
     RECT  10.728 41.107 10.746 48.929 ;
     RECT  7.815 43.709 8.097 48.937 ;
     RECT  29.232 48.859 29.25 48.937 ;
     RECT  23.292 45.005 26.19 48.941 ;
     RECT  29.232 48.937 29.358 48.973 ;
     RECT  31.536 47.501 211.266 48.973 ;
     RECT  23.292 48.941 24.93 49.037 ;
     RECT  29.088 48.973 29.358 49.073 ;
     RECT  26.172 48.941 26.19 49.133 ;
     RECT  236.52 45.959 236.538 49.291 ;
     RECT  23.292 49.037 24.822 49.325 ;
     RECT  31.428 48.973 211.266 49.351 ;
     RECT  23.292 49.325 24.39 49.421 ;
     RECT  29.232 49.073 29.358 49.469 ;
     RECT  23.292 49.421 24.297 49.517 ;
     RECT  236.196 49.291 236.538 49.541 ;
     RECT  30.78 49.351 211.266 49.613 ;
     RECT  29.34 49.469 29.358 49.709 ;
     RECT  30.816 49.613 211.266 49.805 ;
     RECT  237.492 49.441 237.51 50.189 ;
     RECT  230.292 51.637 230.31 51.737 ;
     RECT  236.52 49.541 236.538 51.971 ;
     RECT  232.632 48.191 234.897 52.015 ;
     RECT  235.944 52.141 235.962 52.253 ;
     RECT  232.632 52.015 235.026 52.861 ;
     RECT  230.328 52.861 230.346 52.979 ;
     RECT  232.632 52.861 235.098 53.015 ;
     RECT  237.492 52.411 237.51 53.117 ;
     RECT  236.52 52.795 236.538 53.941 ;
     RECT  236.484 53.941 236.538 53.981 ;
     RECT  230.292 56.101 230.31 56.219 ;
     RECT  7.2 48.937 8.097 56.759 ;
     RECT  223.236 48.461 224.19 57.019 ;
     RECT  225.036 57.001 225.054 57.019 ;
     RECT  223.236 57.019 225.054 57.065 ;
     RECT  237.492 56.911 237.51 57.197 ;
     RECT  225.036 57.065 225.054 57.299 ;
     RECT  31.536 49.805 211.266 57.816 ;
     RECT  218.415 48.461 219.402 58.351 ;
     RECT  218.304 58.351 219.402 58.397 ;
     RECT  232.632 53.015 234.897 58.648 ;
     RECT  223.236 57.065 224.19 59.515 ;
     RECT  232.56 58.648 234.897 59.575 ;
     RECT  133.056 57.816 133.074 59.611 ;
     RECT  171.36 59.083 171.378 59.611 ;
     RECT  168.984 57.816 169.002 59.851 ;
     RECT  169.956 59.131 169.974 59.851 ;
     RECT  164.736 59.659 164.754 59.909 ;
     RECT  131.4 57.816 131.418 59.923 ;
     RECT  148.788 59.515 148.806 59.923 ;
     RECT  174.492 59.881 174.51 59.923 ;
     RECT  119.196 59.851 119.214 59.999 ;
     RECT  172.44 57.816 172.458 59.999 ;
     RECT  174.492 59.923 175.305 59.999 ;
     RECT  138.78 57.816 139.41 60.035 ;
     RECT  168.984 59.851 169.974 60.071 ;
     RECT  117.972 59.971 117.99 60.077 ;
     RECT  232.56 59.575 235.026 60.079 ;
     RECT  172.548 60.007 172.854 60.107 ;
     RECT  174.42 60.007 174.438 60.107 ;
     RECT  179.208 60.007 179.226 60.107 ;
     RECT  171.36 59.611 171.594 60.151 ;
     RECT  232.56 60.079 235.098 60.179 ;
     RECT  29.415 50.203 29.505 60.193 ;
     RECT  34.815 59.923 34.905 60.193 ;
     RECT  40.215 59.923 40.305 60.193 ;
     RECT  45.615 59.923 45.705 60.193 ;
     RECT  51.015 59.923 51.105 60.193 ;
     RECT  56.415 59.923 56.505 60.193 ;
     RECT  61.815 59.923 61.905 60.193 ;
     RECT  67.215 59.923 67.305 60.193 ;
     RECT  72.615 59.923 72.705 60.193 ;
     RECT  78.015 59.923 78.105 60.193 ;
     RECT  83.415 59.923 83.505 60.193 ;
     RECT  88.815 59.923 88.905 60.193 ;
     RECT  94.215 59.923 94.305 60.193 ;
     RECT  99.615 59.923 99.705 60.193 ;
     RECT  105.015 59.923 105.105 60.193 ;
     RECT  110.415 59.923 110.505 60.193 ;
     RECT  115.815 59.923 115.905 60.193 ;
     RECT  121.215 59.923 121.305 60.193 ;
     RECT  126.615 59.923 126.705 60.193 ;
     RECT  131.4 59.923 132.105 60.193 ;
     RECT  137.415 59.923 137.505 60.193 ;
     RECT  142.815 59.923 142.905 60.193 ;
     RECT  153.615 59.923 153.705 60.193 ;
     RECT  159.015 59.923 159.105 60.193 ;
     RECT  169.308 60.071 169.974 60.193 ;
     RECT  170.712 60.151 171.702 60.193 ;
     RECT  175.215 59.999 175.305 60.193 ;
     RECT  180.615 59.923 180.705 60.193 ;
     RECT  186.015 59.923 186.105 60.193 ;
     RECT  191.415 59.923 191.505 60.193 ;
     RECT  196.815 59.923 196.905 60.193 ;
     RECT  202.215 59.923 202.305 60.193 ;
     RECT  203.184 57.816 203.202 60.193 ;
     RECT  131.4 60.193 132.297 60.449 ;
     RECT  166.464 60.421 166.482 60.539 ;
     RECT  138.78 60.035 138.798 60.575 ;
     RECT  236.52 53.981 236.538 60.619 ;
     RECT  236.34 60.619 236.538 60.719 ;
     RECT  133.056 59.611 133.398 60.809 ;
     RECT  236.52 60.719 236.538 60.907 ;
     RECT  148.215 59.923 148.806 61.079 ;
     RECT  236.52 60.907 236.574 61.259 ;
     RECT  223.092 59.515 224.19 61.349 ;
     RECT  232.56 60.179 234.897 61.349 ;
     RECT  133.38 60.809 133.398 61.619 ;
     RECT  236.52 61.259 236.538 62.429 ;
     RECT  232.632 61.349 234.897 62.545 ;
     RECT  236.556 62.581 236.574 62.671 ;
     RECT  232.632 62.545 235.098 62.699 ;
     RECT  236.556 62.671 236.61 62.813 ;
     RECT  196.815 60.193 197.097 62.971 ;
     RECT  205.884 57.816 211.266 62.977 ;
     RECT  236.592 62.813 236.61 63.005 ;
     RECT  205.776 62.977 211.266 63.077 ;
     RECT  237.492 62.683 237.51 63.247 ;
     RECT  232.632 62.699 234.897 63.481 ;
     RECT  232.632 63.481 235.098 63.581 ;
     RECT  237.456 63.247 237.51 63.581 ;
     RECT  202.215 60.193 203.202 63.689 ;
     RECT  128.52 59.035 128.538 63.779 ;
     RECT  230.292 63.751 230.31 63.851 ;
     RECT  237.492 63.581 237.51 63.869 ;
     RECT  3.744 56.767 3.762 64.319 ;
     RECT  3.528 64.363 3.546 64.4 ;
     RECT  232.632 63.581 234.897 64.561 ;
     RECT  232.632 64.561 235.098 64.651 ;
     RECT  230.292 65.011 230.31 65.129 ;
     RECT  236.52 64.123 236.538 65.275 ;
     RECT  167.904 62.155 167.922 65.399 ;
     RECT  235.944 65.275 236.538 65.399 ;
     RECT  153.615 60.193 153.897 65.803 ;
     RECT  164.415 59.923 164.697 65.803 ;
     RECT  175.215 60.193 175.497 65.803 ;
     RECT  186.015 60.193 186.297 65.803 ;
     RECT  196.815 62.971 197.514 65.803 ;
     RECT  218.415 58.397 219.402 65.803 ;
     RECT  232.488 64.651 235.098 65.803 ;
     RECT  153.504 65.803 153.897 65.849 ;
     RECT  164.304 65.803 164.697 65.849 ;
     RECT  175.104 65.803 175.497 65.849 ;
     RECT  185.904 65.803 186.297 65.849 ;
     RECT  196.704 65.803 197.514 65.849 ;
     RECT  218.304 65.803 219.402 65.849 ;
     RECT  232.236 65.803 235.098 66.361 ;
     RECT  232.236 66.361 235.17 66.551 ;
     RECT  228.708 47.759 229.497 66.631 ;
     RECT  236.196 65.399 236.538 66.763 ;
     RECT  232.236 66.551 235.098 66.821 ;
     RECT  153.615 65.849 153.897 66.991 ;
     RECT  164.415 65.849 164.697 66.991 ;
     RECT  175.215 65.849 175.497 66.991 ;
     RECT  186.015 65.849 186.297 66.991 ;
     RECT  196.815 65.849 197.514 66.991 ;
     RECT  218.415 65.849 219.402 66.991 ;
     RECT  218.304 66.991 219.402 67.037 ;
     RECT  220.86 47.615 220.878 67.091 ;
     RECT  132.015 60.449 132.297 67.531 ;
     RECT  142.815 60.193 143.097 67.531 ;
     RECT  202.215 63.689 202.497 67.531 ;
     RECT  205.884 63.077 211.266 67.559 ;
     RECT  131.904 67.531 132.297 67.568 ;
     RECT  142.704 67.531 143.097 67.568 ;
     RECT  153.504 66.991 153.897 67.568 ;
     RECT  164.304 66.991 164.697 67.568 ;
     RECT  175.104 66.991 175.497 67.568 ;
     RECT  185.904 66.991 186.297 67.568 ;
     RECT  196.704 66.991 197.514 67.568 ;
     RECT  206.244 67.559 211.266 67.739 ;
     RECT  235.944 66.763 236.538 67.829 ;
     RECT  232.236 66.821 234.954 67.981 ;
     RECT  206.244 67.739 210.726 68.009 ;
     RECT  2.415 43.709 2.697 68.347 ;
     RECT  2.304 68.347 2.697 68.405 ;
     RECT  228.708 66.631 229.914 68.635 ;
     RECT  201.924 67.531 202.497 68.639 ;
     RECT  232.236 67.981 235.098 68.945 ;
     RECT  202.176 68.639 202.497 69.179 ;
     RECT  142.815 67.568 143.097 69.691 ;
     RECT  153.615 67.568 153.897 69.691 ;
     RECT  164.415 67.568 164.697 69.691 ;
     RECT  175.215 67.568 175.497 69.691 ;
     RECT  186.015 67.568 186.297 69.691 ;
     RECT  196.815 67.568 197.514 69.691 ;
     RECT  218.415 67.037 219.402 69.691 ;
     RECT  142.704 69.691 143.097 69.728 ;
     RECT  153.504 69.691 153.897 69.728 ;
     RECT  164.304 69.691 164.697 69.728 ;
     RECT  175.104 69.691 175.497 69.728 ;
     RECT  185.904 69.691 186.297 69.728 ;
     RECT  196.704 69.691 197.514 69.728 ;
     RECT  218.304 69.691 219.402 69.728 ;
     RECT  232.236 68.945 234.897 69.871 ;
     RECT  236.484 67.829 236.538 70.219 ;
     RECT  159.015 60.193 159.297 70.363 ;
     RECT  210.6 68.009 210.726 70.403 ;
     RECT  159.015 70.363 159.39 70.541 ;
     RECT  236.196 70.219 236.538 70.601 ;
     RECT  206.244 68.009 209.79 70.799 ;
     RECT  152.46 62.155 152.478 70.979 ;
     RECT  153.615 69.728 153.897 71.311 ;
     RECT  164.415 69.728 164.697 71.311 ;
     RECT  175.215 69.728 175.497 71.311 ;
     RECT  186.015 69.728 186.297 71.311 ;
     RECT  196.815 69.728 197.514 71.311 ;
     RECT  218.415 69.728 219.402 71.311 ;
     RECT  153.504 71.311 153.897 71.357 ;
     RECT  164.304 71.311 164.697 71.357 ;
     RECT  175.104 71.311 175.497 71.357 ;
     RECT  185.904 71.311 186.297 71.357 ;
     RECT  196.704 71.311 197.514 71.357 ;
     RECT  218.304 71.311 219.402 71.357 ;
     RECT  196.815 71.357 197.514 71.609 ;
     RECT  169.308 60.193 171.702 71.879 ;
     RECT  237.492 67.915 237.51 71.879 ;
     RECT  169.815 71.879 171.702 73.139 ;
     RECT  232.236 69.871 235.278 73.723 ;
     RECT  210.6 70.403 210.618 73.841 ;
     RECT  232.236 73.723 235.386 73.949 ;
     RECT  236.484 70.601 236.538 74.299 ;
     RECT  169.815 73.139 170.73 74.309 ;
     RECT  171.684 73.139 171.702 74.489 ;
     RECT  206.244 70.799 209.538 74.849 ;
     RECT  169.815 74.309 170.514 75.029 ;
     RECT  232.236 73.949 235.278 75.163 ;
     RECT  236.412 74.299 236.538 75.163 ;
     RECT  232.236 75.163 236.538 75.425 ;
     RECT  172.548 60.107 172.782 75.929 ;
     RECT  237.492 75.451 237.51 75.929 ;
     RECT  206.604 74.849 209.538 76.109 ;
     RECT  206.604 76.109 208.242 76.199 ;
     RECT  232.236 75.425 232.974 76.315 ;
     RECT  233.928 75.425 236.538 76.315 ;
     RECT  228.708 68.635 230.562 76.469 ;
     RECT  232.236 76.315 236.538 76.469 ;
     RECT  232.236 76.469 235.386 76.577 ;
     RECT  172.764 75.929 172.782 76.739 ;
     RECT  236.484 76.469 236.538 76.939 ;
     RECT  223.236 61.349 224.19 77.009 ;
     RECT  182.088 69.211 182.106 77.189 ;
     RECT  206.604 76.199 208.206 77.431 ;
     RECT  206.604 77.431 208.602 77.729 ;
     RECT  236.484 76.939 236.574 77.803 ;
     RECT  236.448 77.803 236.574 77.927 ;
     RECT  232.524 76.577 235.386 78.091 ;
     RECT  236.448 77.927 236.538 78.091 ;
     RECT  164.415 71.357 164.697 78.331 ;
     RECT  175.215 71.357 175.497 78.331 ;
     RECT  186.015 71.357 186.297 78.331 ;
     RECT  196.815 71.609 197.097 78.331 ;
     RECT  218.415 71.357 219.402 78.331 ;
     RECT  232.524 78.091 236.538 78.359 ;
     RECT  164.304 78.331 164.697 78.368 ;
     RECT  232.56 78.359 236.538 78.467 ;
     RECT  175.104 78.331 175.497 78.809 ;
     RECT  185.904 78.331 186.297 78.809 ;
     RECT  196.704 78.331 197.097 78.809 ;
     RECT  218.304 78.331 219.402 78.809 ;
     RECT  232.596 78.467 236.538 78.979 ;
     RECT  206.604 77.729 207.897 79.003 ;
     RECT  209.52 76.109 209.538 79.003 ;
     RECT  209.196 79.003 209.538 79.169 ;
     RECT  232.596 78.979 236.61 79.169 ;
     RECT  206.352 79.003 207.897 79.181 ;
     RECT  209.52 79.169 209.538 79.213 ;
     RECT  208.728 79.435 208.746 79.475 ;
     RECT  209.52 79.213 209.718 79.709 ;
     RECT  153.615 71.357 153.897 79.951 ;
     RECT  164.415 78.368 164.697 79.951 ;
     RECT  175.215 78.809 175.497 79.951 ;
     RECT  186.015 78.809 186.297 79.951 ;
     RECT  196.815 78.809 197.097 79.951 ;
     RECT  218.415 78.809 219.402 79.951 ;
     RECT  153.504 79.951 153.897 79.997 ;
     RECT  164.304 79.951 164.697 79.997 ;
     RECT  175.104 79.951 175.497 79.997 ;
     RECT  185.904 79.951 186.297 79.997 ;
     RECT  196.704 79.951 197.097 79.997 ;
     RECT  217.908 79.951 219.402 79.997 ;
     RECT  209.7 79.709 209.718 80.159 ;
     RECT  228.708 76.469 229.914 80.519 ;
     RECT  232.632 79.169 236.61 80.671 ;
     RECT  223.524 77.009 224.19 80.699 ;
     RECT  232.488 80.671 236.61 80.765 ;
     RECT  221.652 47.885 222.282 80.789 ;
     RECT  218.268 79.997 219.402 81.059 ;
     RECT  232.488 80.765 236.538 81.509 ;
     RECT  232.488 81.509 235.674 81.599 ;
     RECT  179.136 60.151 179.154 82.175 ;
     RECT  236.52 81.509 236.538 82.211 ;
     RECT  232.632 81.599 235.674 82.408 ;
     RECT  232.38 82.408 235.674 82.445 ;
     RECT  237.564 82.381 237.582 82.453 ;
     RECT  230.4 82.687 230.418 82.723 ;
     RECT  206.604 79.181 207.897 82.751 ;
     RECT  230.328 82.723 230.418 82.859 ;
     RECT  232.632 82.445 235.674 82.949 ;
     RECT  206.604 82.751 206.622 82.985 ;
     RECT  218.415 81.059 219.402 83.219 ;
     RECT  233.028 82.949 235.674 83.299 ;
     RECT  236.52 83.035 236.538 83.299 ;
     RECT  219.852 83.371 219.87 83.489 ;
     RECT  233.028 83.299 236.538 83.489 ;
     RECT  233.028 83.489 236.502 83.645 ;
     RECT  230.292 83.371 230.31 83.669 ;
     RECT  221.004 82.687 221.022 83.759 ;
     RECT  222.264 80.789 222.282 83.759 ;
     RECT  225.828 83.641 225.846 83.759 ;
     RECT  231.552 83.605 231.57 83.759 ;
     RECT  236.484 83.645 236.502 83.759 ;
     RECT  233.028 83.645 235.674 83.795 ;
     RECT  223.815 80.699 224.19 83.803 ;
     RECT  220.824 83.803 220.842 83.84 ;
     RECT  222.048 83.839 222.066 83.875 ;
     RECT  228.708 80.519 229.497 83.875 ;
     RECT  228.564 83.875 229.497 83.933 ;
     RECT  221.688 83.875 222.066 83.939 ;
     RECT  223.815 83.803 224.37 83.939 ;
     RECT  2.415 68.405 2.697 83.987 ;
     RECT  7.815 56.759 8.097 83.987 ;
     RECT  13.215 40.469 13.497 83.987 ;
     RECT  18.615 39.209 18.897 83.987 ;
     RECT  24.015 49.517 24.297 83.987 ;
     RECT  29.415 60.193 29.697 83.987 ;
     RECT  34.815 60.193 35.097 83.987 ;
     RECT  40.215 60.193 40.497 83.987 ;
     RECT  45.615 60.193 45.897 83.987 ;
     RECT  51.015 60.193 51.297 83.987 ;
     RECT  56.415 60.193 56.697 83.987 ;
     RECT  61.815 60.193 62.097 83.987 ;
     RECT  67.215 60.193 67.497 83.987 ;
     RECT  72.615 60.193 72.897 83.987 ;
     RECT  78.015 60.193 78.297 83.987 ;
     RECT  83.415 60.193 83.697 83.987 ;
     RECT  88.815 60.193 89.097 83.987 ;
     RECT  94.215 60.193 94.497 83.987 ;
     RECT  99.615 60.193 99.897 83.987 ;
     RECT  105.015 60.193 105.297 83.987 ;
     RECT  110.415 60.193 110.697 83.987 ;
     RECT  115.815 60.193 116.097 83.987 ;
     RECT  121.215 60.193 121.497 83.987 ;
     RECT  126.615 60.193 126.897 83.987 ;
     RECT  132.015 67.568 132.297 83.987 ;
     RECT  137.415 60.193 137.697 83.987 ;
     RECT  142.815 69.728 143.097 83.987 ;
     RECT  148.215 61.079 148.497 83.987 ;
     RECT  153.615 79.997 153.897 83.987 ;
     RECT  159.015 70.541 159.297 83.987 ;
     RECT  164.415 79.997 164.697 83.987 ;
     RECT  169.815 75.029 170.097 83.987 ;
     RECT  175.215 79.997 175.497 83.987 ;
     RECT  180.615 60.193 180.897 83.987 ;
     RECT  186.015 79.997 186.297 83.987 ;
     RECT  191.415 60.193 191.697 83.987 ;
     RECT  196.815 79.997 197.097 83.987 ;
     RECT  202.215 69.179 202.497 83.987 ;
     RECT  207.615 82.751 207.897 83.987 ;
     RECT  213.015 34.619 213.297 83.987 ;
     RECT  218.415 83.219 218.697 83.987 ;
     RECT  223.815 83.939 224.097 83.987 ;
     RECT  229.104 83.933 229.497 83.987 ;
     RECT  221.688 83.939 221.706 84.029 ;
     RECT  226.296 83.911 226.314 84.029 ;
     RECT  229.104 83.987 229.374 84.029 ;
     RECT  233.28 83.795 235.674 84.029 ;
     RECT  233.892 84.029 235.674 84.065 ;
     RECT  234.288 84.065 235.674 84.209 ;
     RECT  2.415 83.987 2.505 84.257 ;
     RECT  7.815 83.987 7.905 84.257 ;
     RECT  13.215 83.987 13.305 84.257 ;
     RECT  18.615 83.987 18.705 84.257 ;
     RECT  24.015 83.987 24.105 84.257 ;
     RECT  29.415 83.987 29.505 84.257 ;
     RECT  34.815 83.987 34.905 84.257 ;
     RECT  40.215 83.987 40.305 84.257 ;
     RECT  45.615 83.987 45.705 84.257 ;
     RECT  51.015 83.987 51.105 84.257 ;
     RECT  56.415 83.987 56.505 84.257 ;
     RECT  61.815 83.987 61.905 84.257 ;
     RECT  67.215 83.987 67.305 84.257 ;
     RECT  72.615 83.987 72.705 84.257 ;
     RECT  78.015 83.987 78.105 84.257 ;
     RECT  83.415 83.987 83.505 84.257 ;
     RECT  88.815 83.987 88.905 84.257 ;
     RECT  94.215 83.987 94.305 84.257 ;
     RECT  99.615 83.987 99.705 84.257 ;
     RECT  105.015 83.987 105.105 84.257 ;
     RECT  110.415 83.987 110.505 84.257 ;
     RECT  115.815 83.987 115.905 84.257 ;
     RECT  121.215 83.987 121.305 84.257 ;
     RECT  126.615 83.987 126.705 84.257 ;
     RECT  132.015 83.987 132.105 84.257 ;
     RECT  137.415 83.987 137.505 84.257 ;
     RECT  142.815 83.987 142.905 84.257 ;
     RECT  148.215 83.987 148.305 84.257 ;
     RECT  153.615 83.987 153.705 84.257 ;
     RECT  159.015 83.987 159.105 84.257 ;
     RECT  164.415 83.987 164.505 84.257 ;
     RECT  169.815 83.987 169.905 84.257 ;
     RECT  175.215 83.987 175.305 84.257 ;
     RECT  180.615 83.987 180.705 84.257 ;
     RECT  186.015 83.987 186.105 84.257 ;
     RECT  191.415 83.987 191.505 84.257 ;
     RECT  196.815 83.987 196.905 84.257 ;
     RECT  202.215 83.987 202.305 84.257 ;
     RECT  207.615 83.987 207.705 84.257 ;
     RECT  213.015 83.987 213.105 84.257 ;
     RECT  218.415 83.987 218.505 84.257 ;
     RECT  223.815 83.987 223.905 84.257 ;
     RECT  229.215 84.029 229.305 84.257 ;
     RECT  234.615 84.209 235.674 84.257 ;
     RECT  234.936 84.257 235.674 84.509 ;
     RECT  237.492 82.453 237.582 85.085 ;
     RECT  235.332 84.509 235.674 85.421 ;
     RECT  235.332 85.421 235.458 85.709 ;
     RECT  235.44 85.709 235.458 85.997 ;
     RECT  237.564 85.085 237.582 86.155 ;
     RECT  237.492 86.155 237.582 86.189 ;
     RECT  237.492 86.189 237.51 86.285 ;
    LAYER M4 ;
     RECT  0.413 0.576 0.497 0.6 ;
     RECT  1.313 1.728 1.397 1.752 ;
     RECT  2.245 1.152 2.333 1.176 ;
     RECT  0.133 68.352 2.408 68.376 ;
     RECT  2.408 2.148 2.512 84.252 ;
     RECT  2.512 2.418 2.704 83.982 ;
     RECT  2.704 68.112 2.819 68.136 ;
     RECT  2.704 64.368 3.557 64.392 ;
     RECT  2.704 6.816 3.841 6.84 ;
     RECT  2.704 7.968 3.841 7.992 ;
     RECT  2.545 0.096 4.115 0.12 ;
     RECT  2.704 14.4 4.643 14.424 ;
     RECT  4.556 16.368 4.643 16.392 ;
     RECT  4.597 1.728 5.027 1.752 ;
     RECT  5.569 0.096 5.987 0.12 ;
     RECT  6.109 16.512 6.275 16.536 ;
     RECT  3.841 6.816 6.353 7.992 ;
     RECT  6.353 6.768 6.419 7.992 ;
     RECT  6.419 6.768 6.437 7.368 ;
     RECT  6.853 1.728 7.808 1.752 ;
     RECT  4.597 2.736 7.808 2.76 ;
     RECT  6.437 6.816 7.808 7.368 ;
     RECT  6.229 18.24 7.808 18.264 ;
     RECT  6.721 43.392 7.808 43.416 ;
     RECT  4.597 60.048 7.808 60.072 ;
     RECT  7.808 1.728 7.813 84.252 ;
     RECT  7.813 2.148 7.912 84.252 ;
     RECT  7.912 2.418 8.104 83.982 ;
     RECT  8.104 8.688 8.531 10.632 ;
     RECT  8.341 0.096 8.723 0.12 ;
     RECT  8.104 18.24 9.065 18.264 ;
     RECT  9.349 18.768 9.433 18.792 ;
     RECT  9.241 1.728 9.635 1.752 ;
     RECT  8.531 10.608 10.465 10.632 ;
     RECT  8.104 6.816 10.501 7.368 ;
     RECT  8.531 8.688 10.501 8.712 ;
     RECT  10.177 0.096 11.459 0.12 ;
     RECT  10.501 6.816 12.697 8.712 ;
     RECT  10.465 9.888 12.697 10.632 ;
     RECT  12.325 1.152 12.737 1.176 ;
     RECT  8.104 2.736 13.208 2.76 ;
     RECT  12.697 6.816 13.208 10.632 ;
     RECT  9.349 20.112 13.208 20.136 ;
     RECT  8.104 43.392 13.208 43.416 ;
     RECT  8.104 60.048 13.208 60.072 ;
     RECT  12.913 0.096 13.283 0.12 ;
     RECT  13.208 2.148 13.312 84.252 ;
     RECT  13.312 2.148 13.504 83.982 ;
     RECT  13.504 20.112 13.601 20.328 ;
     RECT  13.504 2.148 13.849 2.76 ;
     RECT  13.601 20.304 14.284 20.328 ;
     RECT  13.504 40.128 14.821 40.2 ;
     RECT  14.821 40.08 14.861 40.2 ;
     RECT  13.849 1.728 15.185 2.76 ;
     RECT  14.861 40.08 15.329 40.152 ;
     RECT  13.504 43.392 15.901 43.416 ;
     RECT  15.685 0.096 16.019 0.12 ;
     RECT  16.117 13.92 16.153 13.944 ;
     RECT  15.185 2.496 16.585 2.76 ;
     RECT  16.585 1.728 16.931 2.76 ;
     RECT  15.901 43.392 17.605 43.896 ;
     RECT  17.449 0.096 17.843 0.12 ;
     RECT  13.504 6.816 18.469 11.16 ;
     RECT  16.931 2.496 18.608 2.76 ;
     RECT  18.469 6.816 18.608 11.544 ;
     RECT  16.153 13.92 18.608 14.184 ;
     RECT  13.504 22.176 18.608 22.2 ;
     RECT  15.329 40.08 18.608 40.104 ;
     RECT  17.605 43.296 18.608 43.896 ;
     RECT  13.504 60.048 18.608 60.072 ;
     RECT  18.608 2.148 18.712 84.252 ;
     RECT  18.712 2.418 18.904 83.982 ;
     RECT  18.904 22.176 19.693 22.2 ;
     RECT  18.709 1.152 20.189 1.176 ;
     RECT  20.221 0.096 20.579 0.12 ;
     RECT  18.904 6.912 20.837 11.544 ;
     RECT  18.904 2.496 21.121 2.76 ;
     RECT  18.904 23.952 22.637 23.976 ;
     RECT  22.357 19.536 22.741 19.56 ;
     RECT  21.121 1.728 23.315 2.76 ;
     RECT  18.904 43.296 23.317 43.8 ;
     RECT  23.317 43.296 23.893 43.944 ;
     RECT  23.315 2.148 24.008 2.76 ;
     RECT  20.837 7.2 24.008 11.544 ;
     RECT  18.904 13.92 24.008 14.184 ;
     RECT  18.904 16.32 24.008 16.344 ;
     RECT  22.741 18.816 24.008 19.56 ;
     RECT  18.904 40.08 24.008 40.104 ;
     RECT  23.893 43.296 24.008 44.184 ;
     RECT  23.281 49.488 24.008 49.512 ;
     RECT  18.904 60.048 24.008 60.072 ;
     RECT  24.008 2.148 24.112 84.252 ;
     RECT  23.893 0.096 24.227 0.12 ;
     RECT  24.112 2.418 24.304 83.982 ;
     RECT  24.304 24.48 24.515 24.504 ;
     RECT  24.304 6.144 24.697 11.544 ;
     RECT  24.304 29.904 25.297 30.888 ;
     RECT  25.297 29.904 25.333 31.272 ;
     RECT  25.333 29.904 25.369 32.136 ;
     RECT  24.304 41.136 25.369 41.16 ;
     RECT  24.304 25.536 25.429 26.28 ;
     RECT  24.304 37.296 25.429 38.088 ;
     RECT  24.304 40.08 25.477 40.104 ;
     RECT  25.369 41.136 25.477 41.64 ;
     RECT  25.477 40.08 25.484 41.64 ;
     RECT  25.477 35.952 25.513 35.976 ;
     RECT  25.429 25.536 25.525 26.52 ;
     RECT  25.484 39.168 25.571 41.64 ;
     RECT  24.304 16.32 25.573 16.344 ;
     RECT  25.369 29.904 25.573 32.328 ;
     RECT  25.405 33.456 25.573 33.48 ;
     RECT  25.093 1.152 25.657 1.176 ;
     RECT  24.304 2.496 25.657 2.808 ;
     RECT  25.513 35.568 25.801 35.976 ;
     RECT  25.801 35.088 25.945 35.976 ;
     RECT  25.945 35.088 25.957 36.072 ;
     RECT  25.657 1.152 25.985 2.808 ;
     RECT  25.525 24.624 26.005 26.52 ;
     RECT  25.429 37.248 26.005 38.088 ;
     RECT  25.957 34.896 26.053 36.072 ;
     RECT  26.005 37.248 26.053 38.712 ;
     RECT  26.005 24.144 26.149 26.52 ;
     RECT  25.571 40.08 26.149 41.64 ;
     RECT  26.149 23.904 26.341 26.52 ;
     RECT  26.101 27.6 26.341 27.624 ;
     RECT  26.149 40.08 26.417 42.168 ;
     RECT  26.341 23.904 26.485 27.624 ;
     RECT  26.485 47.04 26.533 47.064 ;
     RECT  24.304 48.144 26.533 49.512 ;
     RECT  26.417 40.272 26.557 42.168 ;
     RECT  24.304 43.248 26.557 45.768 ;
     RECT  26.557 40.272 26.581 45.768 ;
     RECT  26.533 47.04 26.581 49.512 ;
     RECT  26.485 23.904 26.629 28.536 ;
     RECT  24.304 13.92 26.965 14.184 ;
     RECT  26.629 23.904 27.013 28.824 ;
     RECT  25.573 29.904 27.013 33.48 ;
     RECT  27.013 23.904 27.061 33.48 ;
     RECT  26.053 34.896 27.061 38.712 ;
     RECT  26.965 13.92 27.107 14.808 ;
     RECT  27.061 23.088 27.109 33.624 ;
     RECT  24.697 6.144 27.253 6.168 ;
     RECT  27.107 13.92 27.301 14.184 ;
     RECT  27.109 23.088 27.533 33.672 ;
     RECT  26.581 40.272 27.533 49.512 ;
     RECT  27.061 34.896 27.601 39.192 ;
     RECT  27.601 34.896 27.637 39.24 ;
     RECT  27.533 29.088 27.677 33.672 ;
     RECT  24.304 18.816 27.733 19.56 ;
     RECT  26.053 20.976 27.733 21 ;
     RECT  25.621 22.032 28.213 22.056 ;
     RECT  27.533 23.088 28.213 27.864 ;
     RECT  27.637 34.896 28.213 39.432 ;
     RECT  27.733 18.816 28.309 21 ;
     RECT  28.213 22.032 28.309 27.864 ;
     RECT  27.301 13.872 28.357 14.184 ;
     RECT  27.677 29.136 28.681 33.672 ;
     RECT  28.681 29.088 28.741 33.672 ;
     RECT  28.213 34.752 28.741 39.432 ;
     RECT  28.309 18.816 28.789 27.864 ;
     RECT  28.789 18.768 28.837 27.864 ;
     RECT  28.837 18.528 28.885 27.864 ;
     RECT  28.981 12.864 29.029 12.888 ;
     RECT  27.253 6.096 29.141 6.168 ;
     RECT  24.697 7.2 29.141 11.544 ;
     RECT  28.357 13.872 29.173 14.232 ;
     RECT  25.573 15.792 29.173 16.344 ;
     RECT  29.141 6.096 29.221 11.544 ;
     RECT  29.029 12.768 29.221 12.888 ;
     RECT  27.533 40.56 29.261 49.512 ;
     RECT  29.261 41.136 29.329 49.512 ;
     RECT  25.985 1.728 29.408 2.808 ;
     RECT  29.221 6.096 29.408 12.888 ;
     RECT  29.173 13.872 29.408 16.344 ;
     RECT  28.885 17.616 29.408 27.864 ;
     RECT  28.741 29.088 29.408 39.432 ;
     RECT  29.329 41.136 29.408 49.704 ;
     RECT  24.304 60.048 29.408 60.072 ;
     RECT  29.408 1.728 29.512 39.432 ;
     RECT  29.408 41.136 29.512 84.252 ;
     RECT  29.512 1.728 29.704 27.864 ;
     RECT  29.512 60.048 29.704 83.982 ;
     RECT  29.704 1.728 29.801 2.808 ;
     RECT  29.512 41.136 30.325 49.704 ;
     RECT  29.512 29.328 30.445 39.432 ;
     RECT  30.325 41.04 30.445 49.704 ;
     RECT  30.445 29.328 30.805 49.704 ;
     RECT  29.704 7.2 30.809 27.864 ;
     RECT  30.805 29.328 30.949 49.8 ;
     RECT  30.949 29.04 30.997 49.8 ;
     RECT  30.809 7.296 31.021 27.864 ;
     RECT  31.021 7.296 31.429 27.96 ;
     RECT  30.997 28.944 31.429 49.8 ;
     RECT  31.429 7.296 31.608 49.8 ;
     RECT  31.608 7.296 31.957 57.816 ;
     RECT  30.613 1.152 32.033 1.176 ;
     RECT  31.957 7.2 32.213 57.816 ;
     RECT  29.801 2.496 32.417 2.808 ;
     RECT  29.704 6.096 32.825 6.168 ;
     RECT  32.825 6.144 32.893 6.168 ;
     RECT  32.213 7.2 32.893 12.888 ;
     RECT  32.417 1.728 33.437 2.808 ;
     RECT  33.937 0.096 34.307 0.12 ;
     RECT  33.437 2.496 34.765 2.808 ;
     RECT  34.765 2.496 34.808 2.856 ;
     RECT  32.893 6.144 34.808 12.888 ;
     RECT  32.213 13.92 34.808 57.816 ;
     RECT  29.704 60.048 34.808 60.072 ;
     RECT  34.808 59.928 34.912 84.252 ;
     RECT  34.808 2.148 35.104 57.816 ;
     RECT  34.912 60.048 35.104 83.982 ;
     RECT  35.104 2.148 35.173 2.856 ;
     RECT  35.173 1.728 36.137 2.856 ;
     RECT  35.104 6.24 37.045 12.936 ;
     RECT  35.104 13.92 37.045 57.816 ;
     RECT  36.137 2.496 37.081 2.856 ;
     RECT  36.997 1.152 37.109 1.176 ;
     RECT  37.045 6.24 37.573 57.816 ;
     RECT  37.573 6.144 37.609 57.816 ;
     RECT  37.081 2.496 37.909 2.808 ;
     RECT  37.609 6 39.053 57.816 ;
     RECT  39.053 6 39.125 12.936 ;
     RECT  39.125 6 39.233 12.84 ;
     RECT  37.909 1.728 39.779 2.808 ;
     RECT  39.779 2.148 40.208 2.808 ;
     RECT  39.233 6.048 40.208 12.84 ;
     RECT  39.053 13.92 40.208 57.816 ;
     RECT  35.104 60.048 40.208 60.072 ;
     RECT  40.208 59.928 40.312 84.252 ;
     RECT  40.208 2.148 40.504 57.816 ;
     RECT  40.312 60.048 40.504 83.982 ;
     RECT  40.504 6.048 40.601 57.816 ;
     RECT  40.417 0.096 40.691 0.12 ;
     RECT  40.504 2.148 41.209 2.808 ;
     RECT  41.209 1.728 41.603 2.808 ;
     RECT  40.601 6.096 41.677 57.816 ;
     RECT  41.677 5.952 42.649 57.816 ;
     RECT  42.649 5.856 42.757 57.816 ;
     RECT  42.145 0.096 43.427 0.12 ;
     RECT  41.603 2.496 43.981 2.808 ;
     RECT  43.981 1.728 44.273 2.808 ;
     RECT  42.757 5.568 44.629 57.816 ;
     RECT  44.629 5.472 44.917 57.816 ;
     RECT  44.273 1.728 45.608 2.52 ;
     RECT  44.917 4.656 45.608 57.816 ;
     RECT  40.504 60.048 45.608 60.072 ;
     RECT  45.608 59.928 45.712 84.252 ;
     RECT  45.608 1.728 45.821 57.816 ;
     RECT  45.821 2.208 45.904 57.816 ;
     RECT  45.712 60.048 45.904 83.982 ;
     RECT  46.117 1.152 46.217 1.176 ;
     RECT  45.904 2.208 47.029 2.76 ;
     RECT  45.904 3.936 47.845 57.816 ;
     RECT  47.029 1.728 48.899 2.76 ;
     RECT  49.417 0.096 49.811 0.12 ;
     RECT  48.899 2.208 50.281 2.76 ;
     RECT  50.281 1.728 50.723 2.76 ;
     RECT  50.723 2.148 51.008 2.76 ;
     RECT  47.845 3.84 51.008 57.816 ;
     RECT  45.904 60.048 51.008 60.072 ;
     RECT  51.008 2.148 51.112 57.816 ;
     RECT  51.008 59.928 51.112 84.252 ;
     RECT  51.112 2.208 51.304 57.816 ;
     RECT  51.112 60.048 51.304 83.982 ;
     RECT  51.217 0.096 51.635 0.12 ;
     RECT  51.304 2.208 52.501 2.76 ;
     RECT  51.304 3.84 54.101 57.816 ;
     RECT  54.101 6.24 54.281 57.816 ;
     RECT  54.101 3.84 55.393 5.208 ;
     RECT  54.281 6.336 55.393 57.816 ;
     RECT  52.501 1.728 56.408 2.76 ;
     RECT  55.393 3.84 56.408 57.816 ;
     RECT  51.304 60.048 56.408 60.072 ;
     RECT  56.408 59.928 56.512 84.252 ;
     RECT  56.408 1.728 56.704 57.816 ;
     RECT  56.512 60.048 56.704 83.982 ;
     RECT  56.704 3.84 60.013 57.816 ;
     RECT  60.013 5.856 60.509 57.816 ;
     RECT  56.704 1.728 60.757 2.76 ;
     RECT  60.757 1.152 61.121 2.76 ;
     RECT  60.013 3.84 61.441 4.776 ;
     RECT  61.297 0.096 61.715 0.12 ;
     RECT  61.121 2.064 61.808 2.76 ;
     RECT  61.441 3.84 61.808 5.208 ;
     RECT  60.509 6.384 61.808 57.816 ;
     RECT  56.704 60.048 61.808 60.072 ;
     RECT  61.808 59.928 61.912 84.252 ;
     RECT  61.808 2.064 62.104 57.816 ;
     RECT  61.912 60.048 62.104 83.982 ;
     RECT  62.104 2.064 62.581 2.76 ;
     RECT  62.581 1.152 62.957 2.76 ;
     RECT  62.957 1.728 63.785 2.76 ;
     RECT  62.104 3.84 63.821 57.816 ;
     RECT  63.785 2.256 64.189 2.76 ;
     RECT  64.177 0.096 64.451 0.12 ;
     RECT  63.821 3.84 64.789 5.304 ;
     RECT  63.821 6.288 64.789 57.816 ;
     RECT  64.189 2.496 65.317 2.76 ;
     RECT  65.317 1.728 67.208 2.76 ;
     RECT  64.789 3.84 67.208 57.816 ;
     RECT  62.104 60.048 67.208 60.072 ;
     RECT  67.208 1.728 67.213 57.816 ;
     RECT  67.213 2.148 67.312 57.816 ;
     RECT  67.208 59.928 67.312 84.252 ;
     RECT  67.312 2.418 67.504 57.816 ;
     RECT  67.312 60.048 67.504 83.982 ;
     RECT  68.053 1.152 68.465 1.176 ;
     RECT  67.504 2.496 68.965 2.76 ;
     RECT  68.965 1.728 72.608 2.76 ;
     RECT  67.504 3.84 72.608 57.816 ;
     RECT  67.504 60.048 72.608 60.072 ;
     RECT  72.608 59.928 72.712 84.252 ;
     RECT  72.608 1.728 72.904 57.816 ;
     RECT  72.712 60.048 72.904 83.982 ;
     RECT  72.904 1.728 74.483 2.76 ;
     RECT  75.013 0.096 75.395 0.12 ;
     RECT  74.483 2.496 75.877 2.76 ;
     RECT  75.877 1.728 78.008 2.76 ;
     RECT  72.904 3.84 78.008 57.816 ;
     RECT  72.904 60.048 78.008 60.072 ;
     RECT  78.008 59.928 78.112 84.252 ;
     RECT  78.008 1.728 78.185 57.816 ;
     RECT  78.185 2.418 78.304 57.816 ;
     RECT  78.112 60.048 78.304 83.982 ;
     RECT  79.045 1.152 80.417 1.176 ;
     RECT  78.304 2.496 80.869 2.76 ;
     RECT  80.869 1.728 82.037 2.76 ;
     RECT  82.357 0.096 82.739 0.12 ;
     RECT  82.037 2.496 83.293 2.76 ;
     RECT  83.293 1.728 83.408 2.76 ;
     RECT  78.304 3.84 83.408 57.816 ;
     RECT  78.304 60.048 83.408 60.072 ;
     RECT  83.408 59.928 83.512 84.252 ;
     RECT  83.408 1.728 83.651 57.816 ;
     RECT  83.651 2.418 83.704 57.816 ;
     RECT  83.512 60.048 83.704 83.982 ;
     RECT  84.193 0.096 84.563 0.12 ;
     RECT  83.704 2.496 85.165 2.76 ;
     RECT  85.165 1.728 88.808 2.76 ;
     RECT  83.704 3.84 88.808 57.816 ;
     RECT  83.704 60.048 88.808 60.072 ;
     RECT  88.808 59.928 88.912 84.252 ;
     RECT  88.808 1.728 89.104 57.816 ;
     RECT  88.912 60.048 89.104 83.982 ;
     RECT  89.104 1.728 89.165 2.76 ;
     RECT  89.989 1.152 90.245 1.176 ;
     RECT  90.565 0.096 91.859 0.12 ;
     RECT  89.165 2.496 92.473 2.76 ;
     RECT  92.473 1.728 94.208 2.76 ;
     RECT  89.104 3.84 94.208 57.816 ;
     RECT  89.104 60.048 94.208 60.072 ;
     RECT  94.208 59.928 94.312 84.252 ;
     RECT  94.208 1.728 94.504 57.816 ;
     RECT  94.312 60.048 94.504 83.982 ;
     RECT  94.504 1.728 97.331 2.76 ;
     RECT  97.873 0.096 98.243 0.12 ;
     RECT  97.331 2.496 98.665 2.76 ;
     RECT  99.109 1.152 99.209 1.176 ;
     RECT  98.665 2.496 99.608 2.856 ;
     RECT  94.504 3.84 99.608 57.816 ;
     RECT  94.504 60.048 99.608 60.072 ;
     RECT  99.608 59.928 99.712 84.252 ;
     RECT  99.608 2.148 99.904 57.816 ;
     RECT  99.712 60.048 99.904 83.982 ;
     RECT  99.904 2.148 100.021 2.76 ;
     RECT  100.021 1.728 104.753 2.76 ;
     RECT  104.753 2.148 105.008 2.76 ;
     RECT  99.904 3.84 105.008 57.816 ;
     RECT  99.904 60.048 105.008 60.072 ;
     RECT  105.008 2.148 105.112 57.816 ;
     RECT  105.008 59.928 105.112 84.252 ;
     RECT  105.112 2.418 105.304 57.816 ;
     RECT  105.112 60.048 105.304 83.982 ;
     RECT  105.253 0.096 105.587 0.12 ;
     RECT  105.304 2.496 106.405 2.76 ;
     RECT  106.405 1.728 106.499 2.76 ;
     RECT  106.981 0.096 108.361 0.12 ;
     RECT  106.499 2.496 109.169 2.76 ;
     RECT  109.169 1.728 110.408 2.76 ;
     RECT  105.304 3.84 110.408 57.816 ;
     RECT  105.304 60.048 110.408 60.072 ;
     RECT  110.408 59.928 110.512 84.252 ;
     RECT  110.408 1.728 110.704 57.816 ;
     RECT  110.512 60.048 110.704 83.982 ;
     RECT  110.704 1.728 111.059 2.76 ;
     RECT  111.589 0.096 111.971 0.12 ;
     RECT  111.059 2.496 112.837 2.76 ;
     RECT  110.704 3.84 114.149 57.816 ;
     RECT  112.837 1.728 114.797 2.76 ;
     RECT  115.573 1.152 115.733 1.176 ;
     RECT  114.797 2.496 115.808 2.76 ;
     RECT  114.149 3.84 115.808 26.04 ;
     RECT  110.704 60.048 115.808 60.072 ;
     RECT  115.808 2.148 115.912 26.04 ;
     RECT  115.808 59.928 115.912 84.252 ;
     RECT  115.912 2.418 116.104 26.04 ;
     RECT  115.912 60.048 116.104 83.982 ;
     RECT  114.149 27.072 117.209 57.816 ;
     RECT  116.104 3.84 117.299 26.04 ;
     RECT  116.125 0.096 117.443 0.12 ;
     RECT  117.209 27.6 117.461 57.816 ;
     RECT  117.461 27.648 117.749 57.816 ;
     RECT  116.104 60.048 118.001 60.072 ;
     RECT  116.104 2.496 118.285 2.76 ;
     RECT  118.285 1.728 118.369 2.76 ;
     RECT  118.933 58.944 119.141 58.968 ;
     RECT  117.299 4.512 119.149 26.04 ;
     RECT  119.141 58.944 119.225 59.88 ;
     RECT  119.149 4.512 119.233 26.232 ;
     RECT  119.233 4.512 120.913 25.944 ;
     RECT  120.133 0.096 121.205 0.12 ;
     RECT  118.369 2.496 121.208 2.76 ;
     RECT  120.913 4.512 121.208 26.04 ;
     RECT  119.225 58.944 121.208 58.968 ;
     RECT  121.208 2.148 121.312 26.04 ;
     RECT  121.208 58.944 121.312 84.252 ;
     RECT  121.312 2.418 121.504 26.04 ;
     RECT  121.312 60.198 121.504 83.982 ;
     RECT  121.949 0.576 122.033 0.6 ;
     RECT  121.504 4.512 122.243 26.04 ;
     RECT  121.312 58.944 122.869 58.968 ;
     RECT  122.869 0.096 124.013 0.12 ;
     RECT  124.741 1.152 124.913 1.176 ;
     RECT  122.243 4.512 125.269 25.8 ;
     RECT  117.749 28.08 125.317 57.816 ;
     RECT  122.869 58.944 125.317 59.064 ;
     RECT  125.621 0.576 125.705 0.6 ;
     RECT  125.317 28.08 125.893 59.064 ;
     RECT  121.504 2.496 126.608 2.76 ;
     RECT  125.269 4.512 126.608 26.472 ;
     RECT  125.893 28.08 126.608 59.64 ;
     RECT  121.504 64.032 126.608 64.056 ;
     RECT  126.469 67.392 126.608 67.416 ;
     RECT  126.565 0.096 126.649 0.12 ;
     RECT  126.608 2.148 126.712 26.472 ;
     RECT  126.608 28.08 126.712 84.252 ;
     RECT  126.712 2.418 126.904 26.472 ;
     RECT  126.712 28.08 126.904 83.982 ;
     RECT  126.904 4.512 126.997 26.472 ;
     RECT  126.904 28.08 126.997 59.64 ;
     RECT  127.465 0.576 127.549 0.6 ;
     RECT  126.997 4.512 127.955 59.64 ;
     RECT  128.389 0.096 128.549 0.12 ;
     RECT  127.955 27.6 129.109 59.64 ;
     RECT  129.301 1.152 129.413 1.176 ;
     RECT  130.213 0.096 131.465 0.12 ;
     RECT  126.904 2.496 132.008 2.76 ;
     RECT  127.955 4.512 132.008 26.472 ;
     RECT  129.109 27.6 132.008 60.024 ;
     RECT  127.909 61.872 132.008 61.896 ;
     RECT  126.904 64.032 132.008 64.056 ;
     RECT  126.904 67.536 132.008 67.56 ;
     RECT  131.965 0.528 132.083 0.552 ;
     RECT  132.008 2.148 132.112 26.472 ;
     RECT  132.008 27.6 132.112 84.252 ;
     RECT  132.112 2.418 132.304 26.472 ;
     RECT  132.112 27.6 132.304 83.982 ;
     RECT  132.949 0.096 133.193 0.12 ;
     RECT  132.304 27.6 134.243 60.024 ;
     RECT  133.861 1.152 135.137 1.176 ;
     RECT  135.637 0.096 135.731 0.12 ;
     RECT  132.304 61.872 135.877 61.896 ;
     RECT  132.304 4.512 135.923 26.472 ;
     RECT  136.597 1.152 136.829 1.176 ;
     RECT  132.304 2.496 137.408 2.76 ;
     RECT  135.923 4.512 137.408 25.8 ;
     RECT  134.243 28.08 137.408 60.024 ;
     RECT  135.877 61.344 137.408 61.896 ;
     RECT  132.304 64.032 137.408 64.056 ;
     RECT  132.304 67.536 137.408 67.56 ;
     RECT  137.408 2.148 137.512 25.932 ;
     RECT  137.408 28.08 137.512 84.252 ;
     RECT  137.501 0.096 137.585 0.12 ;
     RECT  137.512 2.418 137.704 25.932 ;
     RECT  137.512 28.08 137.704 83.982 ;
     RECT  137.704 23.856 137.905 25.932 ;
     RECT  137.704 28.08 137.905 60.024 ;
     RECT  137.704 4.512 137.945 22.536 ;
     RECT  137.905 23.856 137.987 26.232 ;
     RECT  137.905 27.36 138.227 60.024 ;
     RECT  138.421 1.152 138.701 1.176 ;
     RECT  137.945 4.512 139.273 22.056 ;
     RECT  139.273 4.512 139.357 22.2 ;
     RECT  137.987 24.384 139.379 26.232 ;
     RECT  139.379 24.384 140.293 25.8 ;
     RECT  140.293 24.336 140.317 25.8 ;
     RECT  139.357 4.512 140.341 22.056 ;
     RECT  140.317 23.952 140.401 25.8 ;
     RECT  140.401 24.384 140.677 25.8 ;
     RECT  140.341 4.512 141.113 22.776 ;
     RECT  141.113 4.512 141.635 21.672 ;
     RECT  141.635 4.512 141.653 21.336 ;
     RECT  139.333 0.096 142.121 0.12 ;
     RECT  141.113 22.752 142.585 22.776 ;
     RECT  140.677 24.384 142.585 26.472 ;
     RECT  137.704 2.496 142.808 2.76 ;
     RECT  141.653 4.512 142.808 21.24 ;
     RECT  142.585 22.752 142.808 26.472 ;
     RECT  138.227 28.08 142.808 60.024 ;
     RECT  137.704 61.344 142.808 61.896 ;
     RECT  137.704 64.032 142.808 64.056 ;
     RECT  139.957 65.712 142.808 65.736 ;
     RECT  137.704 67.536 142.808 67.56 ;
     RECT  137.704 69.696 142.808 69.72 ;
     RECT  142.808 2.148 142.912 26.472 ;
     RECT  142.808 28.08 142.912 84.252 ;
     RECT  142.912 2.418 143.017 26.472 ;
     RECT  142.912 28.08 143.017 83.982 ;
     RECT  143.017 2.418 143.104 83.982 ;
     RECT  143.104 4.512 144.205 17.448 ;
     RECT  143.104 18.528 144.205 20.136 ;
     RECT  143.104 22.752 144.241 23.256 ;
     RECT  142.981 1.152 144.245 1.176 ;
     RECT  143.104 67.536 144.277 67.56 ;
     RECT  143.104 21.216 144.385 21.24 ;
     RECT  144.205 4.512 144.517 20.136 ;
     RECT  144.385 21.216 144.517 21.288 ;
     RECT  144.241 22.752 144.745 23.304 ;
     RECT  144.745 22.752 144.817 23.4 ;
     RECT  143.104 24.384 144.817 60.024 ;
     RECT  144.781 0.096 144.865 0.12 ;
     RECT  144.517 4.512 144.965 21.288 ;
     RECT  144.965 20.688 145.069 21.288 ;
     RECT  144.277 67.536 145.285 68.136 ;
     RECT  143.104 2.496 145.715 2.52 ;
     RECT  145.717 1.152 145.973 1.176 ;
     RECT  145.573 79.44 146.149 79.464 ;
     RECT  145.069 20.688 146.545 21.768 ;
     RECT  144.817 22.752 146.545 60.024 ;
     RECT  146.545 20.688 146.657 60.024 ;
     RECT  145.285 67.536 146.725 68.664 ;
     RECT  146.657 20.688 146.765 21.624 ;
     RECT  146.657 22.752 146.771 60.024 ;
     RECT  144.965 4.512 146.797 19.608 ;
     RECT  146.629 0.096 146.837 0.12 ;
     RECT  143.104 64.032 147.493 64.056 ;
     RECT  146.149 79.152 147.733 79.464 ;
     RECT  146.797 4.512 148.208 20.376 ;
     RECT  146.765 21.408 148.208 21.624 ;
     RECT  146.771 22.752 148.208 26.472 ;
     RECT  146.771 28.08 148.208 60.024 ;
     RECT  143.104 61.344 148.208 61.896 ;
     RECT  146.197 62.976 148.208 63 ;
     RECT  147.493 64.032 148.208 64.68 ;
     RECT  143.104 65.808 148.208 65.832 ;
     RECT  146.725 66.864 148.208 68.664 ;
     RECT  143.104 69.696 148.208 69.72 ;
     RECT  143.104 71.328 148.208 71.352 ;
     RECT  147.733 79.152 148.208 79.848 ;
     RECT  148.208 2.148 148.312 26.472 ;
     RECT  148.208 28.08 148.312 84.252 ;
     RECT  148.312 2.418 148.504 26.472 ;
     RECT  148.312 28.08 148.504 83.982 ;
     RECT  148.504 4.512 148.741 26.472 ;
     RECT  148.741 4.512 148.781 26.568 ;
     RECT  147.541 1.152 148.817 1.176 ;
     RECT  148.781 18.528 149.069 26.568 ;
     RECT  149.413 0.096 149.753 0.12 ;
     RECT  148.781 4.512 150.325 17.448 ;
     RECT  149.069 18.528 150.325 21.144 ;
     RECT  148.504 61.344 150.613 61.896 ;
     RECT  148.504 62.976 150.613 63 ;
     RECT  150.325 1.152 150.617 1.176 ;
     RECT  149.069 22.464 150.649 26.568 ;
     RECT  150.649 22.176 150.689 26.568 ;
     RECT  150.325 4.512 150.757 21.144 ;
     RECT  150.689 22.176 150.757 23.736 ;
     RECT  150.689 24.72 150.761 26.568 ;
     RECT  150.757 4.512 151.157 23.736 ;
     RECT  151.237 0.096 151.481 0.12 ;
     RECT  151.157 21.888 151.769 23.736 ;
     RECT  151.769 21.888 151.913 23.208 ;
     RECT  151.157 4.512 152.149 20.184 ;
     RECT  151.913 21.888 152.149 23.112 ;
     RECT  152.149 4.512 152.195 23.112 ;
     RECT  152.195 22.704 152.236 23.112 ;
     RECT  152.236 22.752 152.345 23.112 ;
     RECT  150.613 61.344 152.489 63 ;
     RECT  148.504 79.152 153.013 79.992 ;
     RECT  150.761 24.96 153.059 26.568 ;
     RECT  152.149 1.152 153.353 1.176 ;
     RECT  152.195 4.512 153.608 21 ;
     RECT  152.345 22.752 153.608 22.776 ;
     RECT  153.059 24.96 153.608 26.52 ;
     RECT  148.504 28.08 153.608 60.024 ;
     RECT  152.489 61.344 153.608 61.896 ;
     RECT  152.489 62.976 153.608 63 ;
     RECT  148.504 64.032 153.608 64.68 ;
     RECT  148.504 65.808 153.608 65.832 ;
     RECT  148.504 67.008 153.608 68.664 ;
     RECT  148.504 69.696 153.608 69.72 ;
     RECT  148.504 71.328 153.608 71.352 ;
     RECT  153.013 78.192 153.608 79.992 ;
     RECT  149.557 81.312 153.608 81.336 ;
     RECT  153.608 2.148 153.712 26.52 ;
     RECT  153.608 28.08 153.712 84.252 ;
     RECT  153.712 2.418 153.904 26.52 ;
     RECT  153.712 28.08 153.904 83.982 ;
     RECT  153.904 4.512 153.929 20.712 ;
     RECT  153.904 24.96 154.289 26.52 ;
     RECT  153.929 13.344 154.469 20.712 ;
     RECT  154.469 13.344 154.505 17.448 ;
     RECT  153.904 2.784 154.577 2.808 ;
     RECT  154.469 18.528 154.757 20.712 ;
     RECT  154.289 24.96 155.509 24.984 ;
     RECT  154.289 26.496 155.509 26.52 ;
     RECT  153.904 78.336 155.509 79.992 ;
     RECT  153.904 81.312 155.509 81.336 ;
     RECT  154.505 13.392 155.557 17.448 ;
     RECT  154.757 18.528 155.557 19.368 ;
     RECT  153.961 0.096 155.981 0.12 ;
     RECT  155.509 24.96 156.133 26.52 ;
     RECT  156.133 24.912 156.179 26.52 ;
     RECT  153.904 69.696 156.421 69.72 ;
     RECT  153.904 71.328 156.421 71.352 ;
     RECT  156.179 26.496 156.467 26.52 ;
     RECT  154.757 20.688 156.661 20.712 ;
     RECT  155.557 13.392 156.665 19.368 ;
     RECT  156.661 20.688 156.701 21.144 ;
     RECT  156.689 1.152 156.773 1.176 ;
     RECT  156.665 15.504 156.773 19.368 ;
     RECT  156.179 24.912 157.237 24.984 ;
     RECT  153.904 67.008 157.237 68.664 ;
     RECT  156.421 69.696 157.237 71.352 ;
     RECT  156.773 15.552 157.349 19.368 ;
     RECT  157.349 18.528 157.772 19.368 ;
     RECT  156.701 21.12 157.772 21.144 ;
     RECT  157.772 18.528 157.777 21.144 ;
     RECT  157.777 18.528 157.859 21.528 ;
     RECT  157.237 24.912 157.957 25.656 ;
     RECT  153.929 4.512 159.008 12.312 ;
     RECT  156.665 13.392 159.008 14.472 ;
     RECT  157.349 15.552 159.008 17.448 ;
     RECT  157.859 18.528 159.008 19.368 ;
     RECT  157.859 21.216 159.008 21.528 ;
     RECT  153.904 22.752 159.008 22.776 ;
     RECT  157.957 24.912 159.008 25.752 ;
     RECT  158.929 26.736 159.008 26.76 ;
     RECT  153.904 28.08 159.008 60.024 ;
     RECT  153.904 61.344 159.008 61.896 ;
     RECT  153.904 62.976 159.008 63 ;
     RECT  153.904 64.032 159.008 64.68 ;
     RECT  153.904 65.808 159.008 65.832 ;
     RECT  157.237 67.008 159.008 71.352 ;
     RECT  155.509 78.336 159.008 81.336 ;
     RECT  159.008 2.148 159.112 26.76 ;
     RECT  159.008 28.08 159.112 84.252 ;
     RECT  159.112 2.418 159.304 25.752 ;
     RECT  159.112 28.08 159.304 83.982 ;
     RECT  159.304 15.552 159.365 19.368 ;
     RECT  159.304 21.504 159.365 21.528 ;
     RECT  159.304 24.912 159.923 25.752 ;
     RECT  159.365 18.528 160.157 19.368 ;
     RECT  157.561 0.096 160.409 0.12 ;
     RECT  159.112 26.736 160.451 26.76 ;
     RECT  161.261 1.152 161.345 1.176 ;
     RECT  162.181 0.096 163.253 0.12 ;
     RECT  160.693 26.208 163.283 26.232 ;
     RECT  164.005 1.152 164.405 1.176 ;
     RECT  159.304 4.512 164.408 12.312 ;
     RECT  159.304 13.392 164.408 14.472 ;
     RECT  159.365 15.552 164.408 17.448 ;
     RECT  160.157 18.528 164.408 19.128 ;
     RECT  159.304 22.752 164.408 22.776 ;
     RECT  159.923 24.912 164.408 24.984 ;
     RECT  159.304 28.08 164.408 60.024 ;
     RECT  159.304 61.344 164.408 61.896 ;
     RECT  159.304 62.976 164.408 63 ;
     RECT  159.304 64.032 164.408 64.68 ;
     RECT  159.304 65.808 164.408 71.352 ;
     RECT  159.304 75.504 164.408 75.528 ;
     RECT  159.304 78.336 164.408 81.336 ;
     RECT  164.408 2.148 164.512 25.932 ;
     RECT  164.408 28.08 164.512 84.252 ;
     RECT  164.512 2.418 164.704 25.932 ;
     RECT  164.512 28.08 164.704 83.982 ;
     RECT  164.917 0.096 165.053 0.12 ;
     RECT  165.301 26.208 165.385 26.232 ;
     RECT  165.829 1.152 165.917 1.176 ;
     RECT  164.704 24.912 166.921 24.984 ;
     RECT  166.921 24.912 167.269 25.08 ;
     RECT  164.704 22.752 167.315 22.776 ;
     RECT  166.705 26.448 167.461 26.472 ;
     RECT  164.704 61.344 167.461 61.896 ;
     RECT  164.704 62.976 167.461 63 ;
     RECT  167.269 24.528 167.501 25.08 ;
     RECT  167.501 24.912 167.533 25.08 ;
     RECT  167.461 26.208 167.533 26.472 ;
     RECT  166.705 0.096 167.699 0.12 ;
     RECT  168.565 1.152 168.833 1.176 ;
     RECT  169.477 0.096 169.561 0.12 ;
     RECT  164.704 4.512 169.808 12.312 ;
     RECT  164.704 13.392 169.808 14.472 ;
     RECT  164.704 15.552 169.808 17.448 ;
     RECT  164.704 18.528 169.808 19.128 ;
     RECT  167.533 24.912 169.808 26.472 ;
     RECT  164.704 28.08 169.808 60.024 ;
     RECT  167.461 61.344 169.808 63 ;
     RECT  164.704 64.032 169.808 71.352 ;
     RECT  168.565 73.776 169.808 73.8 ;
     RECT  164.704 75.504 169.808 75.528 ;
     RECT  164.704 78.336 169.808 81.336 ;
     RECT  169.808 2.148 169.912 26.472 ;
     RECT  169.808 28.08 169.912 84.252 ;
     RECT  169.912 2.418 170.104 26.472 ;
     RECT  169.912 28.08 170.104 83.982 ;
     RECT  170.369 1.152 170.473 1.176 ;
     RECT  170.104 4.512 170.669 12.312 ;
     RECT  171.277 0.096 171.361 0.12 ;
     RECT  170.104 24.912 172.577 26.472 ;
     RECT  172.261 1.152 172.757 1.176 ;
     RECT  173.141 0.096 173.225 0.12 ;
     RECT  172.577 24.96 174.265 26.472 ;
     RECT  174.085 0.576 174.269 0.6 ;
     RECT  170.669 4.512 175.208 5.496 ;
     RECT  170.669 6.672 175.208 12.312 ;
     RECT  170.104 13.392 175.208 14.472 ;
     RECT  170.104 15.552 175.208 17.448 ;
     RECT  170.104 18.528 175.208 19.128 ;
     RECT  174.265 24.912 175.208 26.472 ;
     RECT  170.104 28.08 175.208 60.024 ;
     RECT  170.104 61.344 175.208 63 ;
     RECT  170.104 64.032 175.208 71.352 ;
     RECT  170.104 73.776 175.208 73.8 ;
     RECT  170.104 75.504 175.208 75.528 ;
     RECT  170.104 78.336 175.208 81.336 ;
     RECT  175.208 2.148 175.312 26.472 ;
     RECT  175.208 28.08 175.312 84.252 ;
     RECT  175.312 2.418 175.504 26.472 ;
     RECT  175.312 28.08 175.504 83.982 ;
     RECT  174.997 0.096 176.867 0.12 ;
     RECT  175.504 78.336 177.109 81.336 ;
     RECT  175.504 13.392 177.545 14.472 ;
     RECT  177.733 1.152 179.021 1.176 ;
     RECT  175.504 4.512 180.608 5.496 ;
     RECT  175.504 6.672 180.608 12.312 ;
     RECT  177.545 14.16 180.608 14.472 ;
     RECT  175.504 15.552 180.608 17.448 ;
     RECT  175.504 18.528 180.608 19.128 ;
     RECT  175.504 24.912 180.608 26.472 ;
     RECT  175.504 28.08 180.608 60.024 ;
     RECT  175.504 61.344 180.608 63 ;
     RECT  175.504 64.032 180.608 71.352 ;
     RECT  175.504 73.776 180.608 73.8 ;
     RECT  175.504 75.504 180.608 75.528 ;
     RECT  177.109 77.952 180.608 81.336 ;
     RECT  180.608 2.148 180.712 26.472 ;
     RECT  180.608 28.08 180.712 84.252 ;
     RECT  180.712 2.418 180.904 26.472 ;
     RECT  180.712 28.08 180.904 83.982 ;
     RECT  180.904 4.512 181.397 5.496 ;
     RECT  179.557 0.096 181.685 0.12 ;
     RECT  180.904 64.032 182.117 71.352 ;
     RECT  180.904 6.672 182.981 12.312 ;
     RECT  182.293 1.728 183.017 1.752 ;
     RECT  182.117 64.032 183.781 68.664 ;
     RECT  182.117 69.696 183.781 71.352 ;
     RECT  180.904 24.912 183.827 26.472 ;
     RECT  183.205 0.096 184.169 0.12 ;
     RECT  180.904 14.16 184.46 14.472 ;
     RECT  184.46 14.16 184.547 14.52 ;
     RECT  182.981 6.672 184.741 8.28 ;
     RECT  181.397 4.896 186.008 5.496 ;
     RECT  184.741 6.672 186.008 8.568 ;
     RECT  182.981 9.6 186.008 12.312 ;
     RECT  184.547 14.16 186.008 14.472 ;
     RECT  180.904 15.552 186.008 17.448 ;
     RECT  180.904 18.528 186.008 19.128 ;
     RECT  183.827 24.912 186.008 24.984 ;
     RECT  183.827 26.448 186.008 26.472 ;
     RECT  180.904 28.08 186.008 60.024 ;
     RECT  180.904 61.344 186.008 63 ;
     RECT  183.781 64.032 186.008 71.352 ;
     RECT  180.904 73.776 186.008 73.8 ;
     RECT  180.904 75.504 186.008 75.528 ;
     RECT  180.904 77.952 186.008 81.336 ;
     RECT  186.008 2.148 186.112 26.472 ;
     RECT  186.008 28.08 186.112 84.252 ;
     RECT  186.112 2.418 186.304 26.472 ;
     RECT  186.112 28.08 186.304 83.982 ;
     RECT  186.304 6.672 186.707 8.424 ;
     RECT  186.304 18.528 186.977 19.128 ;
     RECT  185.029 1.152 187.013 1.176 ;
     RECT  186.304 26.448 187.235 26.472 ;
     RECT  186.304 15.552 187.553 17.448 ;
     RECT  186.304 11.232 187.589 12.312 ;
     RECT  187.589 11.28 187.621 12.312 ;
     RECT  187.621 11.28 188.021 12.36 ;
     RECT  187.553 15.984 188.921 17.448 ;
     RECT  186.304 14.16 188.965 14.472 ;
     RECT  186.304 9.6 189.205 10.2 ;
     RECT  188.021 11.28 189.205 12.312 ;
     RECT  188.965 13.296 189.356 14.472 ;
     RECT  189.356 13.296 189.385 14.664 ;
     RECT  189.205 9.6 189.397 12.312 ;
     RECT  189.385 13.296 189.397 14.76 ;
     RECT  186.707 6.672 189.673 8.28 ;
     RECT  189.397 9.6 189.997 14.76 ;
     RECT  188.921 16.08 189.997 17.448 ;
     RECT  189.673 6.672 190.289 8.52 ;
     RECT  189.997 9.6 190.397 17.448 ;
     RECT  190.397 9.6 190.403 14.952 ;
     RECT  187.765 0.096 190.685 0.12 ;
     RECT  186.304 4.896 191.408 5.496 ;
     RECT  190.289 6.672 191.408 8.28 ;
     RECT  190.403 9.6 191.408 14.76 ;
     RECT  190.397 16.08 191.408 17.448 ;
     RECT  186.977 19.056 191.408 19.128 ;
     RECT  186.304 24.912 191.408 24.984 ;
     RECT  186.304 28.08 191.408 60.024 ;
     RECT  186.304 61.344 191.408 63 ;
     RECT  186.304 64.032 191.408 71.352 ;
     RECT  186.304 73.776 191.408 73.8 ;
     RECT  186.304 75.504 191.408 75.528 ;
     RECT  186.304 77.952 191.408 81.336 ;
     RECT  186.304 82.416 191.408 82.44 ;
     RECT  191.408 2.148 191.512 25.932 ;
     RECT  191.408 28.08 191.512 84.252 ;
     RECT  191.413 1.152 191.585 1.176 ;
     RECT  191.512 2.418 191.704 25.662 ;
     RECT  191.512 28.08 191.704 83.982 ;
     RECT  191.704 16.08 192.125 17.448 ;
     RECT  191.704 6.624 192.179 8.28 ;
     RECT  191.704 9.6 193.165 10.2 ;
     RECT  191.704 11.184 193.165 12.312 ;
     RECT  192.325 0.096 193.385 0.12 ;
     RECT  194.149 1.152 194.537 1.176 ;
     RECT  195.061 0.576 195.437 0.6 ;
     RECT  196.021 1.152 196.193 1.176 ;
     RECT  191.704 4.896 196.808 5.496 ;
     RECT  192.179 6.672 196.808 8.28 ;
     RECT  193.165 9.6 196.808 12.312 ;
     RECT  191.704 13.296 196.808 14.472 ;
     RECT  192.125 16.128 196.808 17.448 ;
     RECT  191.704 19.056 196.808 19.128 ;
     RECT  191.704 24.912 196.808 24.984 ;
     RECT  191.704 28.08 196.808 60.024 ;
     RECT  191.704 61.344 196.808 63 ;
     RECT  191.704 64.032 196.808 71.352 ;
     RECT  191.704 73.776 196.808 73.8 ;
     RECT  191.704 75.504 196.808 75.528 ;
     RECT  191.704 77.952 196.808 81.336 ;
     RECT  191.704 82.416 196.808 82.44 ;
     RECT  196.808 2.148 196.912 25.932 ;
     RECT  196.808 28.08 196.912 84.252 ;
     RECT  196.912 2.418 197.104 25.662 ;
     RECT  196.912 28.08 197.104 83.982 ;
     RECT  197.104 61.344 197.525 63 ;
     RECT  196.901 0.096 197.929 0.12 ;
     RECT  197.104 9.6 198.101 12.312 ;
     RECT  197.104 6.672 198.325 8.28 ;
     RECT  198.101 9.6 198.325 10.2 ;
     RECT  198.325 6.672 198.349 10.2 ;
     RECT  198.757 1.152 198.965 1.176 ;
     RECT  197.104 16.128 199.645 16.152 ;
     RECT  199.669 0.576 199.865 0.6 ;
     RECT  197.104 13.296 200.149 14.472 ;
     RECT  199.645 15.792 200.149 16.152 ;
     RECT  200.149 13.296 200.545 16.152 ;
     RECT  197.104 17.424 200.545 17.448 ;
     RECT  200.581 0.096 200.665 0.12 ;
     RECT  200.545 13.296 200.729 17.448 ;
     RECT  201.473 0.576 201.557 0.6 ;
     RECT  197.104 4.896 202.208 5.496 ;
     RECT  198.349 6.576 202.208 10.2 ;
     RECT  198.101 11.76 202.208 12.312 ;
     RECT  200.729 13.296 202.208 16.152 ;
     RECT  200.729 17.424 202.208 17.448 ;
     RECT  197.104 19.056 202.208 19.128 ;
     RECT  197.104 24.912 202.208 24.984 ;
     RECT  197.104 28.08 202.208 60.024 ;
     RECT  197.525 61.344 202.208 62.472 ;
     RECT  197.104 64.032 202.208 71.352 ;
     RECT  197.104 73.776 202.208 73.8 ;
     RECT  197.104 75.504 202.208 75.528 ;
     RECT  197.104 77.952 202.208 81.336 ;
     RECT  197.104 82.416 202.208 82.44 ;
     RECT  202.208 2.148 202.312 25.932 ;
     RECT  202.208 28.08 202.312 84.252 ;
     RECT  202.312 2.418 202.504 25.662 ;
     RECT  202.312 28.08 202.504 83.982 ;
     RECT  202.504 6.576 203.177 8.712 ;
     RECT  202.504 19.056 203.749 19.128 ;
     RECT  202.504 13.296 203.795 16.152 ;
     RECT  203.795 15.792 204.577 16.152 ;
     RECT  202.504 17.424 204.577 17.448 ;
     RECT  202.504 28.08 205.584 60.024 ;
     RECT  202.504 4.896 206.204 5.496 ;
     RECT  202.405 0.096 206.237 0.12 ;
     RECT  202.504 10.176 206.245 10.2 ;
     RECT  206.204 4.896 206.291 5.64 ;
     RECT  203.177 6.672 206.341 8.712 ;
     RECT  205.584 28.752 206.417 49.704 ;
     RECT  206.417 40.368 206.561 49.704 ;
     RECT  206.291 4.896 206.597 5.496 ;
     RECT  206.965 0.576 207.065 0.6 ;
     RECT  206.341 6.672 207.349 8.808 ;
     RECT  206.597 4.896 207.608 5.064 ;
     RECT  207.349 6.672 207.608 9 ;
     RECT  206.245 10.176 207.608 10.44 ;
     RECT  202.504 11.76 207.608 12.312 ;
     RECT  203.795 13.296 207.608 14.472 ;
     RECT  204.577 15.792 207.608 17.448 ;
     RECT  203.749 19.056 207.608 19.8 ;
     RECT  202.504 24.912 207.608 24.984 ;
     RECT  205.584 58.368 207.608 60.024 ;
     RECT  202.504 61.344 207.608 62.472 ;
     RECT  202.504 64.032 207.608 67.032 ;
     RECT  202.504 68.112 207.608 71.352 ;
     RECT  202.504 73.776 207.608 73.8 ;
     RECT  202.504 75.504 207.608 75.528 ;
     RECT  202.504 77.952 207.608 81.336 ;
     RECT  202.504 82.416 207.608 82.44 ;
     RECT  207.608 2.148 207.712 25.932 ;
     RECT  207.608 58.368 207.712 84.252 ;
     RECT  207.712 2.418 207.8 25.932 ;
     RECT  206.417 28.752 207.8 39.336 ;
     RECT  206.561 40.368 207.8 48.648 ;
     RECT  206.561 49.68 207.8 49.704 ;
     RECT  207.712 58.368 207.8 83.982 ;
     RECT  207.8 2.418 207.904 83.982 ;
     RECT  207.845 0.096 207.929 0.12 ;
     RECT  207.904 47.856 207.929 48.648 ;
     RECT  207.904 28.752 207.965 37.608 ;
     RECT  207.904 40.368 207.965 40.392 ;
     RECT  207.904 41.52 207.965 41.928 ;
     RECT  207.904 44.88 207.965 46.344 ;
     RECT  207.929 48.624 207.965 48.648 ;
     RECT  207.965 28.752 208.001 35.496 ;
     RECT  207.965 44.88 208.001 46.104 ;
     RECT  207.965 36.528 208.037 37.32 ;
     RECT  208.001 28.752 208.109 34.728 ;
     RECT  208.037 36.528 208.109 36.84 ;
     RECT  208.109 36.528 208.289 36.648 ;
     RECT  208.289 36.528 208.325 36.552 ;
     RECT  208.789 0.576 208.873 0.6 ;
     RECT  207.904 77.952 209.225 79.992 ;
     RECT  207.904 64.032 209.549 67.032 ;
     RECT  207.904 68.112 209.801 71.352 ;
     RECT  207.904 6.672 210.181 9 ;
     RECT  207.904 10.416 210.181 10.44 ;
     RECT  210.181 6.672 210.268 10.44 ;
     RECT  207.904 15.792 210.269 17.448 ;
     RECT  208.109 28.752 210.337 34.392 ;
     RECT  210.268 6.672 211.097 9.24 ;
     RECT  209.701 1.152 211.169 1.176 ;
     RECT  211.517 0.096 212.609 0.12 ;
     RECT  211.097 6.672 213.008 9 ;
     RECT  210.268 10.416 213.008 10.44 ;
     RECT  207.904 11.76 213.008 12.312 ;
     RECT  207.904 13.296 213.008 14.472 ;
     RECT  210.269 15.792 213.008 17.112 ;
     RECT  207.904 19.056 213.008 19.8 ;
     RECT  207.904 24.912 213.008 24.984 ;
     RECT  210.337 28.752 213.008 34.488 ;
     RECT  207.904 58.368 213.008 60.024 ;
     RECT  207.904 61.344 213.008 62.472 ;
     RECT  209.549 64.032 213.008 64.68 ;
     RECT  209.549 65.808 213.008 67.032 ;
     RECT  209.801 68.64 213.008 71.352 ;
     RECT  207.904 73.776 213.008 73.8 ;
     RECT  207.904 75.504 213.008 75.528 ;
     RECT  209.225 77.952 213.008 78.936 ;
     RECT  209.225 79.968 213.008 79.992 ;
     RECT  207.904 81.072 213.008 81.336 ;
     RECT  207.904 82.416 213.008 82.44 ;
     RECT  213.008 2.148 213.112 84.252 ;
     RECT  213.112 2.418 213.304 83.982 ;
     RECT  213.317 0.576 213.401 0.6 ;
     RECT  213.304 28.752 213.905 34.488 ;
     RECT  213.304 15.744 214.067 17.112 ;
     RECT  213.304 10.416 214.729 10.44 ;
     RECT  213.304 11.76 214.933 12.312 ;
     RECT  213.304 13.296 214.933 14.472 ;
     RECT  214.933 11.712 215.02 14.472 ;
     RECT  215.02 11.76 215.021 14.472 ;
     RECT  214.067 15.792 215.021 17.112 ;
     RECT  214.729 10.08 215.557 10.44 ;
     RECT  215.021 15.792 216.097 16.152 ;
     RECT  213.304 6.672 216.745 9 ;
     RECT  216.745 6.336 216.817 9 ;
     RECT  215.557 10.032 216.817 10.44 ;
     RECT  215.021 13.296 216.817 14.472 ;
     RECT  216.097 15.552 216.817 16.152 ;
     RECT  216.817 13.296 217.033 16.152 ;
     RECT  214.225 0.096 217.081 0.12 ;
     RECT  216.817 6.336 217.105 10.44 ;
     RECT  217.033 13.296 217.105 16.632 ;
     RECT  217.105 6.336 217.325 10.728 ;
     RECT  215.021 11.76 218.113 12.312 ;
     RECT  217.105 13.296 218.113 16.68 ;
     RECT  218.113 11.76 218.365 16.68 ;
     RECT  217.325 6.336 218.408 10.44 ;
     RECT  218.365 11.76 218.408 16.92 ;
     RECT  213.304 19.056 218.408 19.8 ;
     RECT  213.304 24.912 218.408 24.984 ;
     RECT  213.905 28.752 218.408 34.392 ;
     RECT  213.304 58.368 218.408 60.024 ;
     RECT  213.304 61.344 218.408 62.472 ;
     RECT  213.304 64.032 218.408 64.68 ;
     RECT  213.304 65.808 218.408 67.032 ;
     RECT  213.304 68.64 218.408 71.352 ;
     RECT  213.304 73.776 218.408 73.8 ;
     RECT  213.304 75.504 218.408 75.528 ;
     RECT  213.304 77.952 218.408 78.936 ;
     RECT  213.304 79.968 218.408 79.992 ;
     RECT  213.304 81.072 218.408 81.336 ;
     RECT  213.304 82.416 218.408 82.44 ;
     RECT  218.408 2.148 218.512 84.252 ;
     RECT  218.512 2.418 218.704 83.982 ;
     RECT  218.704 28.752 218.909 34.392 ;
     RECT  217.909 1.152 218.945 1.176 ;
     RECT  218.704 14.16 219.413 16.92 ;
     RECT  218.704 6.576 219.485 13.032 ;
     RECT  219.485 10.08 219.773 13.032 ;
     RECT  219.413 14.16 219.845 16.632 ;
     RECT  219.845 14.16 220.097 16.152 ;
     RECT  219.769 46.656 220.201 46.68 ;
     RECT  219.485 6.576 220.237 9 ;
     RECT  220.201 46.56 220.261 46.68 ;
     RECT  220.261 46.56 220.273 47.352 ;
     RECT  220.237 6.528 220.417 9 ;
     RECT  220.273 46.368 220.493 47.352 ;
     RECT  220.417 6.288 220.549 9 ;
     RECT  220.549 5.616 220.595 9 ;
     RECT  220.493 46.368 220.709 46.632 ;
     RECT  219.773 10.416 220.885 13.032 ;
     RECT  220.709 46.608 220.961 46.632 ;
     RECT  219.769 0.096 220.997 0.12 ;
     RECT  220.885 10.416 220.997 13.08 ;
     RECT  220.097 14.16 221.501 14.808 ;
     RECT  218.704 44.448 221.797 44.472 ;
     RECT  221.797 44.448 221.884 44.616 ;
     RECT  221.605 1.152 221.969 1.176 ;
     RECT  220.097 15.792 222.035 16.152 ;
     RECT  221.989 23.28 222.181 23.304 ;
     RECT  218.704 24.912 222.181 24.984 ;
     RECT  220.997 10.416 222.253 12.312 ;
     RECT  222.181 23.28 222.265 24.984 ;
     RECT  218.909 28.752 222.329 34.2 ;
     RECT  222.253 10.032 222.469 12.312 ;
     RECT  221.501 14.16 222.517 14.472 ;
     RECT  221.929 47.184 222.613 47.208 ;
     RECT  222.469 10.032 222.689 13.032 ;
     RECT  222.517 0.576 222.725 0.6 ;
     RECT  222.689 10.416 222.755 13.032 ;
     RECT  222.517 14.16 222.761 14.808 ;
     RECT  221.884 44.448 222.801 44.52 ;
     RECT  222.325 22.224 222.86 22.248 ;
     RECT  218.704 19.056 222.901 19.8 ;
     RECT  222.755 11.664 222.937 13.032 ;
     RECT  220.595 5.616 223.009 5.64 ;
     RECT  222.613 47.184 223.009 47.352 ;
     RECT  222.289 3.936 223.225 3.96 ;
     RECT  223.009 5.184 223.253 5.64 ;
     RECT  223.225 3.648 223.285 3.96 ;
     RECT  223.253 5.136 223.285 5.64 ;
     RECT  223.285 3.648 223.297 5.64 ;
     RECT  222.86 21.312 223.484 22.248 ;
     RECT  222.265 23.28 223.484 23.304 ;
     RECT  222.937 11.664 223.621 13.08 ;
     RECT  222.035 15.84 223.669 16.152 ;
     RECT  223.484 21.312 223.765 23.304 ;
     RECT  223.297 3.36 223.808 5.64 ;
     RECT  220.595 6.672 223.808 9 ;
     RECT  222.755 10.416 223.808 10.632 ;
     RECT  223.621 11.664 223.808 13.176 ;
     RECT  222.761 14.16 223.808 14.472 ;
     RECT  223.669 15.744 223.808 16.152 ;
     RECT  222.073 17.328 223.808 17.352 ;
     RECT  222.901 19.056 223.808 19.944 ;
     RECT  223.765 21.312 223.808 23.4 ;
     RECT  222.265 24.912 223.808 24.984 ;
     RECT  222.329 28.752 223.808 31.224 ;
     RECT  222.329 32.208 223.808 34.2 ;
     RECT  223.801 36.24 223.808 36.264 ;
     RECT  220.261 41.76 223.808 41.784 ;
     RECT  222.801 43.824 223.808 44.52 ;
     RECT  223.657 45.6 223.808 45.624 ;
     RECT  223.009 46.752 223.808 47.352 ;
     RECT  223.225 48.384 223.808 48.408 ;
     RECT  218.704 58.368 223.808 60.024 ;
     RECT  218.704 61.344 223.808 62.472 ;
     RECT  218.704 64.032 223.808 64.68 ;
     RECT  218.704 65.808 223.808 67.032 ;
     RECT  218.704 68.64 223.808 71.352 ;
     RECT  218.704 73.776 223.808 73.8 ;
     RECT  218.704 75.504 223.808 75.528 ;
     RECT  218.704 77.952 223.808 78.936 ;
     RECT  218.704 81.072 223.808 81.336 ;
     RECT  218.704 82.416 223.808 82.44 ;
     RECT  220.813 83.808 223.808 83.832 ;
     RECT  223.808 2.148 223.912 84.252 ;
     RECT  223.912 2.418 224.104 83.982 ;
     RECT  224.104 13.056 224.165 13.176 ;
     RECT  224.165 13.152 224.237 13.176 ;
     RECT  224.104 42.768 224.309 43.848 ;
     RECT  224.104 32.208 224.345 34.632 ;
     RECT  224.104 46.656 224.417 47.064 ;
     RECT  224.104 2.88 224.525 9 ;
     RECT  224.104 23.376 224.525 26.28 ;
     RECT  224.309 42.768 224.597 43.32 ;
     RECT  224.104 83.808 224.627 83.928 ;
     RECT  224.104 27.936 224.633 31.224 ;
     RECT  224.345 32.208 224.633 34.2 ;
     RECT  224.104 41.04 224.633 41.784 ;
     RECT  224.104 19.056 224.668 19.512 ;
     RECT  224.633 27.936 224.669 30.984 ;
     RECT  224.104 22.032 224.741 22.056 ;
     RECT  224.525 23.904 224.812 26.28 ;
     RECT  224.104 38.16 224.813 38.184 ;
     RECT  224.104 39.216 224.813 39.864 ;
     RECT  224.104 48.384 224.819 48.408 ;
     RECT  224.525 4.512 225.029 9 ;
     RECT  224.104 57.024 225.065 57.096 ;
     RECT  224.104 10.416 225.101 11.784 ;
     RECT  224.669 29.28 225.137 30.984 ;
     RECT  225.137 29.808 225.173 30.984 ;
     RECT  224.633 32.208 225.173 33.336 ;
     RECT  224.104 45.024 225.173 45.048 ;
     RECT  224.668 19.056 225.349 19.176 ;
     RECT  225.101 10.416 225.425 10.44 ;
     RECT  225.349 18.816 225.541 19.176 ;
     RECT  224.104 36.24 225.601 36.264 ;
     RECT  225.541 18.144 225.633 19.176 ;
     RECT  224.104 15.744 225.637 16.152 ;
     RECT  225.601 36.144 225.641 36.264 ;
     RECT  224.669 27.936 225.695 27.96 ;
     RECT  225.641 36.144 225.733 36.168 ;
     RECT  225.695 27.552 225.749 27.96 ;
     RECT  224.812 26.112 225.779 26.28 ;
     RECT  225.733 35.952 225.779 36.168 ;
     RECT  224.525 2.88 225.781 3.432 ;
     RECT  225.779 26.112 225.821 26.136 ;
     RECT  225.733 37.632 225.893 37.656 ;
     RECT  225.101 11.664 225.916 11.784 ;
     RECT  225.781 2.88 226.105 3.624 ;
     RECT  224.813 39.216 226.109 39.24 ;
     RECT  224.633 41.232 226.213 41.256 ;
     RECT  226.172 44.352 226.259 44.376 ;
     RECT  225.065 57.024 226.259 57.048 ;
     RECT  224.812 23.904 226.261 24.984 ;
     RECT  224.417 46.656 226.285 46.68 ;
     RECT  226.261 23.28 226.307 24.984 ;
     RECT  226.105 2.832 226.321 3.624 ;
     RECT  225.029 5.28 226.321 9 ;
     RECT  226.213 41.232 226.325 41.592 ;
     RECT  226.285 45.84 226.361 46.68 ;
     RECT  224.104 14.16 226.721 14.472 ;
     RECT  225.749 27.552 226.789 27.576 ;
     RECT  226.325 41.568 226.825 41.592 ;
     RECT  224.597 43.296 226.861 43.32 ;
     RECT  226.789 27.552 226.883 27.816 ;
     RECT  225.916 11.76 226.901 11.784 ;
     RECT  225.633 18.144 226.901 19.08 ;
     RECT  226.307 23.28 226.901 23.304 ;
     RECT  225.173 30.384 226.901 30.984 ;
     RECT  226.321 2.832 226.933 9 ;
     RECT  225.637 10.32 226.973 10.344 ;
     RECT  226.901 30.384 227.005 30.456 ;
     RECT  224.104 20.736 227.085 20.76 ;
     RECT  227.085 20.064 227.125 20.76 ;
     RECT  227.125 20.064 227.171 21.672 ;
     RECT  226.721 14.208 227.257 14.472 ;
     RECT  225.637 15.696 227.257 16.152 ;
     RECT  227.257 14.208 227.261 16.152 ;
     RECT  225.173 32.208 227.293 32.616 ;
     RECT  226.933 2.832 227.413 9.096 ;
     RECT  226.361 45.84 227.413 46.248 ;
     RECT  226.141 48.096 227.461 48.12 ;
     RECT  226.861 43.296 227.477 43.896 ;
     RECT  227.413 2.832 227.507 9.144 ;
     RECT  227.461 47.712 227.507 48.12 ;
     RECT  227.507 5.28 227.513 9.144 ;
     RECT  227.513 6.192 227.548 9.144 ;
     RECT  226.307 24.768 227.557 24.984 ;
     RECT  227.257 26.928 227.557 26.952 ;
     RECT  227.005 30.288 227.585 30.456 ;
     RECT  227.413 45.6 227.603 46.248 ;
     RECT  227.548 6.24 227.621 9.144 ;
     RECT  227.557 24.768 227.644 26.952 ;
     RECT  226.837 29.04 227.653 29.064 ;
     RECT  226.825 41.568 227.693 42.168 ;
     RECT  227.477 43.296 227.837 43.608 ;
     RECT  227.149 34.224 227.893 34.248 ;
     RECT  227.693 41.568 227.987 41.64 ;
     RECT  227.893 34.224 228.017 34.824 ;
     RECT  225.779 35.952 228.017 35.976 ;
     RECT  227.644 26.112 228.053 26.952 ;
     RECT  227.507 2.832 228.085 3.624 ;
     RECT  227.293 31.92 228.089 32.616 ;
     RECT  227.653 28.32 228.161 29.064 ;
     RECT  228.161 28.416 228.197 29.064 ;
     RECT  228.085 2.64 228.233 3.624 ;
     RECT  228.017 34.224 228.337 34.248 ;
     RECT  226.249 39.264 228.517 39.288 ;
     RECT  227.585 30.432 228.689 30.456 ;
     RECT  228.089 31.92 228.689 31.944 ;
     RECT  228.689 30.432 228.709 31.944 ;
     RECT  228.337 34.08 229.045 34.248 ;
     RECT  228.517 38.736 229.165 39.288 ;
     RECT  228.233 2.832 229.208 3.624 ;
     RECT  229.057 5.136 229.208 5.16 ;
     RECT  227.621 6.672 229.208 9.144 ;
     RECT  228.085 10.992 229.208 11.016 ;
     RECT  227.437 12.864 229.208 12.888 ;
     RECT  227.261 14.448 229.208 16.152 ;
     RECT  226.901 18.144 229.208 18.168 ;
     RECT  227.171 20.064 229.208 20.088 ;
     RECT  227.171 21.648 229.208 21.672 ;
     RECT  227.293 23.328 229.208 23.352 ;
     RECT  227.644 24.768 229.208 24.984 ;
     RECT  228.053 26.112 229.208 26.136 ;
     RECT  228.197 28.416 229.208 28.44 ;
     RECT  228.709 30.192 229.208 31.944 ;
     RECT  229.045 33.264 229.208 34.488 ;
     RECT  229.165 38.736 229.208 40.056 ;
     RECT  227.987 41.616 229.208 41.64 ;
     RECT  227.837 43.584 229.208 43.608 ;
     RECT  227.603 45.6 229.208 45.624 ;
     RECT  227.507 47.712 229.208 47.736 ;
     RECT  224.104 58.368 229.208 60.024 ;
     RECT  224.104 61.344 229.208 62.472 ;
     RECT  224.104 64.032 229.208 64.68 ;
     RECT  224.104 65.808 229.208 67.032 ;
     RECT  224.104 68.64 229.208 71.352 ;
     RECT  224.104 73.776 229.208 73.8 ;
     RECT  224.104 75.504 229.208 75.528 ;
     RECT  224.104 77.952 229.208 78.936 ;
     RECT  224.104 81.072 229.208 81.336 ;
     RECT  224.104 82.416 229.208 82.44 ;
     RECT  224.627 83.904 229.208 83.928 ;
     RECT  229.208 2.148 229.312 84.252 ;
     RECT  229.312 2.418 229.504 83.982 ;
     RECT  229.504 26.112 229.565 26.136 ;
     RECT  229.504 15.984 229.619 16.152 ;
     RECT  229.504 10.992 229.709 11.016 ;
     RECT  229.504 2.88 229.745 4.152 ;
     RECT  229.504 35.28 229.763 36.744 ;
     RECT  229.745 2.88 229.781 3.144 ;
     RECT  229.781 3.024 229.817 3.144 ;
     RECT  223.405 0.096 229.861 0.12 ;
     RECT  229.504 47.712 229.961 47.736 ;
     RECT  229.504 28.416 230.213 28.44 ;
     RECT  229.504 33.264 230.213 33.288 ;
     RECT  229.504 12.864 230.249 12.888 ;
     RECT  229.817 3.12 230.429 3.144 ;
     RECT  229.504 68.64 230.573 71.352 ;
     RECT  229.504 6.096 230.753 9 ;
     RECT  229.504 14.784 230.753 14.808 ;
     RECT  229.504 20.064 230.78 20.088 ;
     RECT  229.504 40.032 230.789 40.056 ;
     RECT  229.504 43.584 230.789 43.608 ;
     RECT  230.78 19.632 230.867 20.088 ;
     RECT  230.785 21.12 230.869 21.144 ;
     RECT  230.725 1.152 230.969 1.176 ;
     RECT  230.753 6.672 230.969 9 ;
     RECT  229.745 4.128 231.077 4.152 ;
     RECT  229.763 35.28 231.077 35.304 ;
     RECT  230.969 6.816 231.581 9 ;
     RECT  229.619 16.128 231.761 16.152 ;
     RECT  231.581 6.816 231.869 8.28 ;
     RECT  231.869 6.96 232.013 8.28 ;
     RECT  229.504 65.808 232.265 67.032 ;
     RECT  229.504 82.416 232.409 82.44 ;
     RECT  229.504 64.032 232.517 64.68 ;
     RECT  232.265 66.48 232.553 67.032 ;
     RECT  230.573 69.216 232.589 71.352 ;
     RECT  229.504 73.776 232.625 73.8 ;
     RECT  229.504 58.368 232.697 60.024 ;
     RECT  232.013 6.96 232.841 6.984 ;
     RECT  232.697 58.368 232.949 59.496 ;
     RECT  232.589 70.512 232.949 70.536 ;
     RECT  229.504 77.952 232.949 78.936 ;
     RECT  229.504 75.504 232.985 75.528 ;
     RECT  229.504 61.344 233.057 62.472 ;
     RECT  232.949 78.768 233.057 78.936 ;
     RECT  232.949 58.368 233.165 59.064 ;
     RECT  233.057 61.344 233.165 61.896 ;
     RECT  232.553 67.008 233.165 67.032 ;
     RECT  232.837 46.56 233.201 46.584 ;
     RECT  232.013 7.968 233.345 8.28 ;
     RECT  233.165 58.944 233.345 59.064 ;
     RECT  232.589 69.216 233.381 69.24 ;
     RECT  229.504 81.072 233.381 81.336 ;
     RECT  233.345 8.256 233.489 8.28 ;
     RECT  233.057 78.912 233.597 78.936 ;
     RECT  231.605 0.096 233.633 0.12 ;
     RECT  233.665 3.024 234.241 3.048 ;
     RECT  234.313 1.104 234.419 1.128 ;
     RECT  234.529 1.584 234.608 1.608 ;
     RECT  234.241 3.024 234.608 3.336 ;
     RECT  234.277 14.688 234.608 14.712 ;
     RECT  234.313 36 234.608 36.024 ;
     RECT  233.345 59.04 234.608 59.064 ;
     RECT  232.517 64.032 234.608 64.056 ;
     RECT  233.381 81.072 234.608 81.096 ;
     RECT  234.241 83.76 234.608 83.784 ;
     RECT  234.608 1.584 234.904 84.252 ;
     RECT  234.904 83.904 234.925 84.252 ;
     RECT  234.421 0.24 235.105 0.264 ;
     RECT  235.105 0.144 235.285 0.264 ;
     RECT  235.285 0.096 235.369 0.264 ;
     RECT  234.925 83.904 235.393 84.504 ;
     RECT  235.321 85.68 235.393 85.704 ;
     RECT  235.393 83.904 235.429 85.704 ;
     RECT  234.904 25.152 235.897 26.328 ;
     RECT  234.904 36 235.897 36.024 ;
     RECT  234.904 5.952 235.933 6.84 ;
     RECT  234.904 8.256 235.933 8.28 ;
     RECT  234.904 10.032 235.933 10.056 ;
     RECT  234.904 11.184 235.933 11.208 ;
     RECT  234.904 12.624 235.933 13.56 ;
     RECT  234.904 14.688 235.933 14.712 ;
     RECT  235.897 16.992 235.933 17.016 ;
     RECT  234.904 21.36 235.933 21.384 ;
     RECT  235.897 24.288 235.933 26.328 ;
     RECT  234.904 30.096 235.933 30.12 ;
     RECT  235.897 36 235.933 37.08 ;
     RECT  234.904 39.12 235.933 40.296 ;
     RECT  234.904 42.048 235.933 42.648 ;
     RECT  234.904 79.824 235.933 79.848 ;
     RECT  234.904 82.464 235.933 82.776 ;
     RECT  235.429 83.904 235.933 85.992 ;
     RECT  235.933 65.28 236.185 65.304 ;
     RECT  235.933 66.768 236.185 67.368 ;
     RECT  235.369 0.144 236.221 0.264 ;
     RECT  235.969 81.024 236.221 81.048 ;
     RECT  236.221 0.144 236.243 0.456 ;
     RECT  234.904 1.584 236.401 4.248 ;
     RECT  235.933 5.952 236.401 15.576 ;
     RECT  235.933 16.704 236.401 19.656 ;
     RECT  234.904 73.728 236.401 73.752 ;
     RECT  235.933 75.168 236.401 75.192 ;
     RECT  235.933 78.096 236.437 79.848 ;
     RECT  235.933 21.36 236.473 21.96 ;
     RECT  236.185 70.224 236.473 70.248 ;
     RECT  236.401 73.728 236.473 75.192 ;
     RECT  234.904 76.368 236.473 76.392 ;
     RECT  236.437 77.808 236.473 79.848 ;
     RECT  236.401 1.584 236.509 19.656 ;
     RECT  236.473 21.36 236.509 22.248 ;
     RECT  235.933 23.424 236.509 28.968 ;
     RECT  235.933 30.096 236.509 42.648 ;
     RECT  235.933 45.792 236.509 45.816 ;
     RECT  236.185 49.296 236.509 49.32 ;
     RECT  235.933 52.224 236.509 52.248 ;
     RECT  236.473 53.952 236.509 53.976 ;
     RECT  236.329 60.624 236.509 60.648 ;
     RECT  236.185 65.28 236.509 67.368 ;
     RECT  236.473 68.496 236.509 79.848 ;
     RECT  236.221 81.024 236.509 81.336 ;
     RECT  235.933 82.464 236.509 85.992 ;
     RECT  236.243 0.24 236.545 0.456 ;
     RECT  236.509 1.584 236.545 62.424 ;
     RECT  236.545 0.24 236.581 62.808 ;
     RECT  236.581 0.24 237.445 63 ;
     RECT  236.509 64.128 237.445 85.992 ;
     RECT  237.445 0.24 237.481 85.992 ;
     RECT  237.481 0.144 237.564 86.28 ;
     RECT  237.564 1.392 237.593 1.416 ;
     RECT  237.564 86.16 237.593 86.184 ;
    LAYER M5 ;
     RECT  0.432 0.016 237.144 0.131 ;
     RECT  236.208 0.131 237.144 0.179 ;
     RECT  132.048 0.131 132.072 0.563 ;
     RECT  0.432 0.131 2.28 0.611 ;
     RECT  121.968 0.131 121.992 0.611 ;
     RECT  124.752 0.131 125.688 0.611 ;
     RECT  127.488 0.131 127.512 0.611 ;
     RECT  174.096 0.131 174.12 0.611 ;
     RECT  194.16 0.131 196.056 0.611 ;
     RECT  198.768 0.131 199.704 0.611 ;
     RECT  201.504 0.131 201.528 0.611 ;
     RECT  206.976 0.131 207 0.611 ;
     RECT  208.8 0.131 210.648 0.611 ;
     RECT  213.36 0.131 213.384 0.611 ;
     RECT  221.616 0.131 222.552 0.611 ;
     RECT  234.384 0.131 234.408 1.139 ;
     RECT  237.12 0.179 237.144 1.139 ;
     RECT  1.344 0.611 2.28 1.187 ;
     RECT  12.336 0.131 12.36 1.187 ;
     RECT  18.72 0.131 19.656 1.187 ;
     RECT  25.104 0.131 33.384 1.187 ;
     RECT  35.184 0.131 39.768 1.187 ;
     RECT  44.304 0.131 48.888 1.187 ;
     RECT  52.512 0.131 60.792 1.187 ;
     RECT  62.592 0.131 63.528 1.187 ;
     RECT  65.328 0.131 74.472 1.187 ;
     RECT  76.272 0.131 81.816 1.187 ;
     RECT  85.44 0.131 90.024 1.187 ;
     RECT  99.12 0.131 104.664 1.187 ;
     RECT  112.848 0.131 115.608 1.187 ;
     RECT  124.752 0.611 124.776 1.187 ;
     RECT  129.312 0.131 129.336 1.187 ;
     RECT  133.872 0.131 134.808 1.187 ;
     RECT  136.608 0.131 136.632 1.187 ;
     RECT  138.432 0.131 138.456 1.187 ;
     RECT  142.992 0.131 143.928 1.187 ;
     RECT  145.728 0.131 145.752 1.187 ;
     RECT  147.552 0.131 148.536 1.187 ;
     RECT  150.336 0.131 150.36 1.187 ;
     RECT  152.16 0.131 153.096 1.187 ;
     RECT  156.72 0.131 156.744 1.187 ;
     RECT  161.28 0.131 161.304 1.187 ;
     RECT  164.016 0.131 164.04 1.187 ;
     RECT  165.84 0.131 165.864 1.187 ;
     RECT  168.576 0.131 168.6 1.187 ;
     RECT  170.4 0.131 170.424 1.187 ;
     RECT  172.272 0.131 172.296 1.187 ;
     RECT  177.744 0.131 178.68 1.187 ;
     RECT  185.04 0.131 186.888 1.187 ;
     RECT  194.16 0.611 194.184 1.187 ;
     RECT  196.032 0.611 196.056 1.187 ;
     RECT  198.768 0.611 198.792 1.187 ;
     RECT  209.712 0.611 210.648 1.187 ;
     RECT  217.92 0.131 218.856 1.187 ;
     RECT  221.616 0.611 221.64 1.187 ;
     RECT  230.736 0.131 230.76 1.187 ;
     RECT  1.344 1.187 1.368 1.763 ;
     RECT  4.992 0.131 5.016 1.763 ;
     RECT  6.864 0.131 7.8 1.763 ;
     RECT  9.6 0.131 9.624 1.763 ;
     RECT  14.16 0.131 15.096 1.763 ;
     RECT  16.896 0.131 16.92 1.763 ;
     RECT  21.456 0.131 23.304 1.763 ;
     RECT  26.016 1.187 29.736 1.763 ;
     RECT  32.448 1.187 33.384 1.763 ;
     RECT  35.184 1.187 36.12 1.763 ;
     RECT  37.92 1.187 39.768 1.763 ;
     RECT  41.568 0.131 41.592 1.763 ;
     RECT  44.304 1.187 45.72 1.763 ;
     RECT  47.04 1.187 48.888 1.763 ;
     RECT  52.512 1.187 59.88 1.763 ;
     RECT  63.504 1.187 63.528 1.763 ;
     RECT  65.328 1.187 67.32 1.763 ;
     RECT  68.976 1.187 74.472 1.763 ;
     RECT  76.272 1.187 78.168 1.763 ;
     RECT  80.88 1.187 81.816 1.763 ;
     RECT  85.44 1.187 89.112 1.763 ;
     RECT  92.736 0.131 97.32 1.763 ;
     RECT  99.6 1.187 104.664 1.763 ;
     RECT  106.464 0.131 106.488 1.763 ;
     RECT  109.2 0.131 111.048 1.763 ;
     RECT  112.848 1.187 114.696 1.763 ;
     RECT  118.32 0.131 119.256 1.763 ;
     RECT  182.304 0.131 182.328 1.763 ;
     RECT  50.688 0.131 50.712 2.137 ;
     RECT  83.616 0.131 83.64 2.137 ;
     RECT  191.424 0.131 191.448 2.137 ;
     RECT  2.4 2.137 2.52 2.151 ;
     RECT  7.8 2.137 7.92 2.151 ;
     RECT  18.6 2.137 18.72 2.151 ;
     RECT  24 2.137 24.12 2.151 ;
     RECT  40.2 2.137 40.32 2.151 ;
     RECT  45.36 1.763 45.72 2.151 ;
     RECT  50.688 2.137 51.12 2.151 ;
     RECT  61.8 2.137 61.92 2.151 ;
     RECT  67.2 1.763 67.32 2.151 ;
     RECT  78 1.763 78.168 2.151 ;
     RECT  83.4 2.137 83.64 2.151 ;
     RECT  105 2.137 105.12 2.151 ;
     RECT  115.8 2.137 115.92 2.151 ;
     RECT  121.2 2.137 121.32 2.151 ;
     RECT  126.6 2.137 126.72 2.151 ;
     RECT  132 2.137 132.12 2.151 ;
     RECT  137.4 2.137 137.52 2.151 ;
     RECT  142.8 2.137 142.92 2.151 ;
     RECT  148.2 1.187 148.32 2.151 ;
     RECT  153.6 2.137 153.72 2.151 ;
     RECT  159 2.137 159.12 2.151 ;
     RECT  164.4 2.137 164.52 2.151 ;
     RECT  169.8 2.137 169.92 2.151 ;
     RECT  175.2 2.137 175.32 2.151 ;
     RECT  180.6 2.137 180.72 2.151 ;
     RECT  186 1.187 186.12 2.151 ;
     RECT  191.4 2.137 191.52 2.151 ;
     RECT  196.8 2.137 196.92 2.151 ;
     RECT  202.2 2.137 202.32 2.151 ;
     RECT  207.6 2.137 207.72 2.151 ;
     RECT  213 2.137 213.12 2.151 ;
     RECT  218.4 1.187 218.52 2.151 ;
     RECT  223.8 2.137 223.92 2.151 ;
     RECT  229.2 2.137 229.32 2.151 ;
     RECT  234.6 2.137 234.72 2.151 ;
     RECT  126.6 2.151 126.912 2.533 ;
     RECT  142.8 2.151 143.112 2.725 ;
     RECT  24 2.151 24.312 2.773 ;
     RECT  110.4 1.763 110.712 3.877 ;
     RECT  45.36 2.151 45.912 3.925 ;
     RECT  61.8 2.151 62.112 3.925 ;
     RECT  110.4 3.877 111.24 3.925 ;
     RECT  223.8 2.151 224.112 3.925 ;
     RECT  45.36 3.925 46.392 4.645 ;
     RECT  115.8 2.151 116.112 4.645 ;
     RECT  227.472 4.501 227.496 4.789 ;
     RECT  207.6 2.151 207.912 5.029 ;
     RECT  223.296 3.925 224.112 5.171 ;
     RECT  50.688 2.151 51.312 5.173 ;
     RECT  88.8 1.763 89.112 5.173 ;
     RECT  50.448 5.173 51.312 5.221 ;
     RECT  119.232 1.763 119.256 5.267 ;
     RECT  64.128 2.245 64.152 5.269 ;
     RECT  44.928 4.645 46.392 5.461 ;
     RECT  47.856 3.829 47.88 5.461 ;
     RECT  48.96 3.877 48.984 5.461 ;
     RECT  99.6 1.763 99.912 5.461 ;
     RECT  67.2 2.151 67.512 5.653 ;
     RECT  24 2.773 24.648 6.133 ;
     RECT  37.008 2.821 37.032 6.133 ;
     RECT  226.848 4.789 227.496 6.275 ;
     RECT  59.952 5.077 59.976 6.323 ;
     RECT  220.56 5.605 220.584 6.323 ;
     RECT  44.928 5.461 48.984 6.563 ;
     RECT  64.128 5.269 64.44 6.563 ;
     RECT  191.4 2.151 191.712 6.613 ;
     RECT  56.4 1.763 56.712 6.661 ;
     RECT  153.6 2.151 153.912 6.661 ;
     RECT  159 2.151 159.312 6.661 ;
     RECT  164.4 2.151 164.712 6.661 ;
     RECT  202.2 2.151 202.512 6.661 ;
     RECT  132 2.151 132.312 6.709 ;
     RECT  180.6 2.151 180.912 6.709 ;
     RECT  186 2.151 186.312 6.709 ;
     RECT  207.36 5.029 207.912 6.709 ;
     RECT  50.448 5.221 52.248 6.803 ;
     RECT  29.4 1.763 29.712 6.805 ;
     RECT  94.2 1.763 94.512 6.805 ;
     RECT  121.2 2.151 121.512 6.805 ;
     RECT  125.76 2.533 126.912 6.805 ;
     RECT  148.2 2.151 148.512 6.805 ;
     RECT  213 2.151 213.312 6.805 ;
     RECT  67.2 5.653 67.848 6.851 ;
     RECT  13.2 2.137 13.608 6.899 ;
     RECT  44.928 6.563 47.88 6.899 ;
     RECT  121.2 6.805 121.8 6.901 ;
     RECT  173.136 6.805 173.16 6.947 ;
     RECT  110.4 3.925 111.48 6.995 ;
     RECT  44.928 6.899 47.112 7.091 ;
     RECT  119.328 6.229 119.352 7.091 ;
     RECT  180.6 6.709 181.896 7.091 ;
     RECT  78 2.151 78.312 7.093 ;
     RECT  56.4 6.661 56.808 7.139 ;
     RECT  58.032 5.317 58.056 7.189 ;
     RECT  121.2 6.901 121.896 7.189 ;
     RECT  169.8 2.151 170.112 7.189 ;
     RECT  121.2 7.189 122.664 7.235 ;
     RECT  58.032 7.189 59.016 7.331 ;
     RECT  29.184 6.805 29.712 7.379 ;
     RECT  18.6 2.151 18.912 7.381 ;
     RECT  55.056 7.093 55.08 7.381 ;
     RECT  158.88 6.661 159.312 7.427 ;
     RECT  99.6 5.461 100.536 7.429 ;
     RECT  145.68 2.485 145.704 7.429 ;
     RECT  4.608 2.725 4.632 7.475 ;
     RECT  48.96 6.563 48.984 7.475 ;
     RECT  131.76 6.709 132.312 7.475 ;
     RECT  148.2 6.805 148.632 7.475 ;
     RECT  61.8 3.925 63.096 7.523 ;
     RECT  64.128 6.563 64.152 7.571 ;
     RECT  101.904 6.805 101.928 7.619 ;
     RECT  115.248 4.645 116.112 7.621 ;
     RECT  117.264 3.829 117.288 7.621 ;
     RECT  96.816 7.477 96.84 7.667 ;
     RECT  125.76 6.805 127.464 7.667 ;
     RECT  169.8 7.189 170.424 7.667 ;
     RECT  198.912 7.237 198.936 7.667 ;
     RECT  202.08 6.661 202.512 7.667 ;
     RECT  98.784 7.429 100.536 7.669 ;
     RECT  69.024 7.525 69.048 7.715 ;
     RECT  115.248 7.621 117.288 7.763 ;
     RECT  115.248 7.763 116.232 7.811 ;
     RECT  132 7.475 132.312 7.813 ;
     RECT  164.304 6.661 164.712 7.813 ;
     RECT  112.896 7.429 112.92 7.859 ;
     RECT  153.504 6.661 153.912 7.859 ;
     RECT  105 2.151 105.312 7.861 ;
     RECT  148.2 7.475 148.512 7.861 ;
     RECT  145.008 7.429 145.704 7.909 ;
     RECT  218.4 2.151 218.712 7.909 ;
     RECT  50.544 6.803 52.248 7.955 ;
     RECT  86.64 7.669 86.664 7.955 ;
     RECT  122.64 7.235 122.664 7.955 ;
     RECT  126.6 7.667 127.464 7.955 ;
     RECT  132 7.813 132.408 7.955 ;
     RECT  164.304 7.813 164.808 7.955 ;
     RECT  18.6 7.381 19.32 7.957 ;
     RECT  20.688 7.045 20.712 7.957 ;
     RECT  37.008 6.133 37.608 7.957 ;
     RECT  75.024 6.037 75.048 7.957 ;
     RECT  6.384 6.757 6.408 8.003 ;
     RECT  36.192 7.957 37.608 8.003 ;
     RECT  44.928 7.091 46.392 8.003 ;
     RECT  55.056 7.381 55.272 8.003 ;
     RECT  98.64 7.669 100.536 8.003 ;
     RECT  105 7.861 105.432 8.003 ;
     RECT  164.304 7.955 164.712 8.003 ;
     RECT  184.848 7.381 184.872 8.003 ;
     RECT  213 6.805 214.008 8.003 ;
     RECT  55.056 8.003 55.08 8.051 ;
     RECT  118.56 7.141 118.584 8.051 ;
     RECT  50.592 7.955 52.248 8.099 ;
     RECT  33.648 7.189 33.672 8.147 ;
     RECT  180.6 7.091 181.176 8.147 ;
     RECT  191.4 6.613 192.168 8.147 ;
     RECT  159 7.427 159.312 8.149 ;
     RECT  93.648 6.805 94.512 8.195 ;
     RECT  186 6.709 186.696 8.435 ;
     RECT  110.4 6.995 111.24 8.437 ;
     RECT  207.36 6.709 208.584 8.483 ;
     RECT  27.264 6.085 27.288 8.485 ;
     RECT  159 8.149 159.432 8.533 ;
     RECT  68.976 7.909 69 8.579 ;
     RECT  147.6 7.861 148.512 8.579 ;
     RECT  36.192 8.003 37.032 8.675 ;
     RECT  227.52 6.277 227.544 8.677 ;
     RECT  198.336 8.149 198.36 8.723 ;
     RECT  227.424 8.677 227.544 8.723 ;
     RECT  27.264 8.485 27.336 8.773 ;
     RECT  22.368 7.957 22.392 8.869 ;
     RECT  77.712 7.093 78.312 8.869 ;
     RECT  151.776 7.813 151.8 8.869 ;
     RECT  42.336 7.861 42.36 8.963 ;
     RECT  72.6 1.763 72.912 8.965 ;
     RECT  99.6 8.003 100.536 8.965 ;
     RECT  207.36 8.483 207.912 9.011 ;
     RECT  18.6 7.957 20.712 9.013 ;
     RECT  45.024 8.003 46.392 9.013 ;
     RECT  58.992 7.331 59.016 9.059 ;
     RECT  145.008 7.909 146.472 9.059 ;
     RECT  85.632 8.965 85.656 9.061 ;
     RECT  132 7.955 132.312 9.061 ;
     RECT  137.4 2.151 137.712 9.061 ;
     RECT  85.536 9.061 85.656 9.107 ;
     RECT  99.6 8.965 100.92 9.107 ;
     RECT  53.376 7.909 53.4 9.109 ;
     RECT  80.976 8.149 81 9.109 ;
     RECT  44.352 9.013 46.392 9.155 ;
     RECT  227.424 8.723 227.448 9.155 ;
     RECT  66.096 7.909 66.12 9.203 ;
     RECT  56.4 7.139 56.712 9.205 ;
     RECT  75.024 7.957 75.288 9.251 ;
     RECT  18.48 9.013 20.712 9.299 ;
     RECT  87.6 8.869 87.624 9.301 ;
     RECT  108.864 7.477 108.888 9.347 ;
     RECT  77.712 8.869 78.408 9.349 ;
     RECT  72.384 8.965 72.912 9.397 ;
     RECT  88.8 5.173 89.208 9.397 ;
     RECT  94.2 8.195 94.512 9.397 ;
     RECT  142.56 2.725 143.112 9.397 ;
     RECT  38.784 7.333 38.808 9.493 ;
     RECT  96.48 8.149 96.504 9.493 ;
     RECT  97.536 9.397 97.56 9.493 ;
     RECT  141.936 9.397 143.112 9.493 ;
     RECT  20.688 9.299 20.712 9.539 ;
     RECT  38.784 9.493 39.192 9.539 ;
     RECT  86.64 9.301 87.624 9.539 ;
     RECT  94.2 9.397 94.632 9.539 ;
     RECT  96.48 9.493 97.56 9.539 ;
     RECT  210.192 8.149 210.216 9.539 ;
     RECT  80.64 9.109 81 9.541 ;
     RECT  82.08 9.301 82.104 9.541 ;
     RECT  67.2 6.851 67.608 9.587 ;
     RECT  87.36 9.539 87.624 9.587 ;
     RECT  88.8 9.397 89.352 9.589 ;
     RECT  96.48 9.539 97.464 9.635 ;
     RECT  7.8 2.151 8.112 9.637 ;
     RECT  151.776 8.869 152.376 9.637 ;
     RECT  76.944 9.349 78.408 9.731 ;
     RECT  166.224 7.381 166.248 9.731 ;
     RECT  102.096 8.773 102.12 9.779 ;
     RECT  218.4 7.909 219 9.827 ;
     RECT  45.36 9.155 46.392 9.877 ;
     RECT  128.592 7.237 128.616 9.877 ;
     RECT  53.376 9.109 53.832 9.925 ;
     RECT  64.848 9.541 64.872 9.925 ;
     RECT  218.4 9.827 218.712 9.925 ;
     RECT  45.36 9.877 47.208 10.019 ;
     RECT  44.352 9.155 44.376 10.067 ;
     RECT  85.536 9.107 85.56 10.067 ;
     RECT  110.4 8.437 111.624 10.069 ;
     RECT  71.952 9.397 72.912 10.211 ;
     RECT  76.896 9.925 76.92 10.211 ;
     RECT  56.4 9.205 57.048 10.213 ;
     RECT  105 8.003 105.312 10.213 ;
     RECT  63.984 9.925 64.872 10.261 ;
     RECT  68.88 9.637 68.904 10.261 ;
     RECT  133.968 8.437 133.992 10.261 ;
     RECT  99.6 9.107 100.536 10.307 ;
     RECT  133.968 10.261 134.712 10.307 ;
     RECT  207.456 9.011 207.912 10.307 ;
     RECT  34.8 2.137 35.112 10.309 ;
     RECT  41.808 9.637 41.832 10.309 ;
     RECT  61.8 7.523 62.112 10.309 ;
     RECT  121.2 7.235 121.512 10.309 ;
     RECT  132 9.061 132.792 10.309 ;
     RECT  141.312 9.493 143.112 10.309 ;
     RECT  87.36 9.587 87.384 10.355 ;
     RECT  128.208 9.877 128.616 10.355 ;
     RECT  121.2 10.309 121.608 10.357 ;
     RECT  123.024 9.541 123.048 10.357 ;
     RECT  39.168 9.539 39.192 10.405 ;
     RECT  40.2 2.151 40.512 10.405 ;
     RECT  126.6 7.955 126.912 10.405 ;
     RECT  36.912 8.675 37.032 10.451 ;
     RECT  41.808 10.309 42.312 10.451 ;
     RECT  206.256 5.605 206.28 10.451 ;
     RECT  37.008 10.451 37.032 10.499 ;
     RECT  75.024 9.251 75.048 10.595 ;
     RECT  151.584 9.637 152.376 10.595 ;
     RECT  113.472 10.213 113.496 10.597 ;
     RECT  7.8 9.637 8.52 10.643 ;
     RECT  96.48 9.635 96.504 10.643 ;
     RECT  61.8 10.309 62.376 10.645 ;
     RECT  60.864 10.645 62.376 10.691 ;
     RECT  110.4 10.069 111.816 10.691 ;
     RECT  126.6 10.405 127.176 10.691 ;
     RECT  141.312 10.309 143.256 10.691 ;
     RECT  121.2 10.357 123.048 10.739 ;
     RECT  136.416 9.061 137.712 10.739 ;
     RECT  108.864 10.357 108.888 10.741 ;
     RECT  145.008 9.059 145.704 10.741 ;
     RECT  108.864 10.741 109.032 10.787 ;
     RECT  80.64 9.541 82.104 10.789 ;
     RECT  180.6 8.147 180.912 10.789 ;
     RECT  196.8 2.151 197.112 10.789 ;
     RECT  191.4 8.147 191.712 10.837 ;
     RECT  39.168 10.405 40.512 10.883 ;
     RECT  53.376 9.925 54.12 10.883 ;
     RECT  56.4 10.213 57.48 10.883 ;
     RECT  59.232 9.685 59.256 10.883 ;
     RECT  136.752 10.739 137.712 10.883 ;
     RECT  159 8.533 159.576 10.883 ;
     RECT  117.264 7.763 117.288 10.979 ;
     RECT  219.696 10.213 219.72 10.979 ;
     RECT  39.168 10.883 39.192 10.981 ;
     RECT  38.256 10.981 39.192 11.075 ;
     RECT  68.64 10.261 68.904 11.075 ;
     RECT  115.248 7.811 116.112 11.077 ;
     RECT  94.2 9.539 94.512 11.125 ;
     RECT  38.256 11.075 39.048 11.171 ;
     RECT  196.8 10.789 197.352 11.171 ;
     RECT  186 8.435 186.312 11.221 ;
     RECT  122.88 10.739 123.048 11.267 ;
     RECT  179.856 10.789 180.912 11.267 ;
     RECT  124.848 10.165 124.872 11.315 ;
     RECT  113.28 10.597 113.496 11.363 ;
     RECT  34.224 10.309 35.112 11.365 ;
     RECT  105 10.213 106.152 11.365 ;
     RECT  110.4 10.691 111.72 11.365 ;
     RECT  142.56 10.691 143.256 11.365 ;
     RECT  144.576 10.741 145.704 11.365 ;
     RECT  150.288 9.493 150.312 11.365 ;
     RECT  155.616 11.173 155.64 11.365 ;
     RECT  155.616 11.365 156.168 11.411 ;
     RECT  185.904 11.221 186.312 11.411 ;
     RECT  32.16 10.789 32.184 11.459 ;
     RECT  34.224 11.365 35.304 11.459 ;
     RECT  63.984 10.261 64.968 11.459 ;
     RECT  88.704 9.589 89.352 11.459 ;
     RECT  91.584 3.925 91.608 11.459 ;
     RECT  110.304 11.365 111.72 11.459 ;
     RECT  142.56 11.365 145.704 11.459 ;
     RECT  18.48 9.299 19.32 11.555 ;
     RECT  102.048 10.357 102.072 11.699 ;
     RECT  134.688 10.307 134.712 11.699 ;
     RECT  222.72 11.029 222.744 11.699 ;
     RECT  225.84 10.309 225.864 11.699 ;
     RECT  99.6 10.307 100.008 11.701 ;
     RECT  148.2 8.579 148.512 11.701 ;
     RECT  152.352 10.595 152.376 11.701 ;
     RECT  92.88 9.205 92.904 11.797 ;
     RECT  94.2 11.125 94.68 11.797 ;
     RECT  99.6 11.701 100.632 11.843 ;
     RECT  148.08 11.701 148.512 11.843 ;
     RECT  131.904 10.309 132.888 11.939 ;
     RECT  41.808 10.451 41.832 11.941 ;
     RECT  137.4 10.883 137.712 11.941 ;
     RECT  141.312 10.691 141.336 11.941 ;
     RECT  142.56 11.459 143.88 11.941 ;
     RECT  63.984 11.459 64.872 11.987 ;
     RECT  79.776 10.789 82.104 11.987 ;
     RECT  105 11.365 106.584 11.987 ;
     RECT  130.56 11.797 130.584 11.987 ;
     RECT  68.88 11.075 68.904 12.035 ;
     RECT  97.632 10.597 97.656 12.035 ;
     RECT  109.008 10.787 109.032 12.035 ;
     RECT  122.88 11.267 122.904 12.035 ;
     RECT  141.312 11.941 143.88 12.179 ;
     RECT  115.104 11.077 116.112 12.181 ;
     RECT  41.808 11.941 42.168 12.227 ;
     RECT  29.4 7.379 29.712 12.229 ;
     RECT  50.688 8.099 52.248 12.229 ;
     RECT  53.376 10.883 53.4 12.229 ;
     RECT  50.688 12.229 53.4 12.275 ;
     RECT  60.864 10.691 62.232 12.277 ;
     RECT  76.272 11.269 76.296 12.323 ;
     RECT  50.688 12.275 53.064 12.325 ;
     RECT  88.704 11.459 89.112 12.325 ;
     RECT  44.064 11.221 44.088 12.467 ;
     RECT  128.208 10.355 128.232 12.467 ;
     RECT  141.312 12.179 143.592 12.469 ;
     RECT  218.256 9.925 218.712 12.469 ;
     RECT  56.4 10.883 57.432 12.515 ;
     RECT  83.4 2.151 83.712 12.517 ;
     RECT  141.12 12.469 143.592 12.517 ;
     RECT  150.288 11.365 150.552 12.517 ;
     RECT  33.408 11.941 33.432 12.563 ;
     RECT  92.88 11.797 94.68 12.563 ;
     RECT  103.968 4.981 103.992 12.563 ;
     RECT  152.352 11.701 152.472 12.563 ;
     RECT  42.144 12.227 42.168 12.613 ;
     RECT  60.864 12.277 62.664 12.755 ;
     RECT  29.232 12.229 29.712 12.757 ;
     RECT  34.8 11.459 35.304 12.803 ;
     RECT  42.144 12.613 42.6 12.803 ;
     RECT  29.04 12.757 29.712 12.853 ;
     RECT  136.032 12.325 136.056 12.853 ;
     RECT  42.144 12.803 42.168 12.899 ;
     RECT  57.696 12.757 57.72 12.899 ;
     RECT  140.64 12.517 143.592 12.899 ;
     RECT  70.848 6.277 70.872 12.947 ;
     RECT  135.552 12.853 136.056 12.995 ;
     RECT  72.384 10.211 72.912 12.997 ;
     RECT  28.992 12.853 29.712 13.045 ;
     RECT  30.96 7.381 30.984 13.045 ;
     RECT  49.104 12.325 49.128 13.045 ;
     RECT  64.8 11.987 64.872 13.045 ;
     RECT  99.6 11.843 99.912 13.045 ;
     RECT  110.304 11.459 111.24 13.045 ;
     RECT  189.216 9.637 189.24 13.045 ;
     RECT  50.256 12.325 53.064 13.091 ;
     RECT  106.56 11.987 106.584 13.091 ;
     RECT  136.032 12.995 136.056 13.091 ;
     RECT  78 9.731 78.408 13.093 ;
     RECT  105 11.987 105.576 13.093 ;
     RECT  37.056 11.653 37.08 13.139 ;
     RECT  45.36 10.019 46.392 13.139 ;
     RECT  60.864 12.755 62.112 13.139 ;
     RECT  77.52 13.093 78.408 13.139 ;
     RECT  107.712 11.941 107.736 13.139 ;
     RECT  114.672 12.181 116.112 13.139 ;
     RECT  140.64 12.899 143.112 13.139 ;
     RECT  145.008 11.459 145.704 13.139 ;
     RECT  218.208 12.469 218.712 13.139 ;
     RECT  49.008 13.045 49.128 13.141 ;
     RECT  150.288 12.517 150.936 13.187 ;
     RECT  40.2 10.883 40.512 13.189 ;
     RECT  134.208 12.517 134.232 13.283 ;
     RECT  189.216 13.045 189.432 13.285 ;
     RECT  40.2 13.189 40.632 13.331 ;
     RECT  92.88 12.563 94.512 13.331 ;
     RECT  86.304 13.381 86.328 13.571 ;
     RECT  64.8 13.045 65.592 13.621 ;
     RECT  137.4 11.941 137.928 13.667 ;
     RECT  50.688 13.091 53.064 13.669 ;
     RECT  80.016 11.987 82.104 13.715 ;
     RECT  131.904 11.939 132.312 13.715 ;
     RECT  152.352 12.563 152.376 13.763 ;
     RECT  80.496 13.715 82.104 13.811 ;
     RECT  109.68 13.045 111.24 13.861 ;
     RECT  126.6 10.691 126.912 13.861 ;
     RECT  213 8.003 213.312 13.861 ;
     RECT  214.944 10.069 214.968 13.861 ;
     RECT  27.072 8.773 27.336 13.907 ;
     RECT  213 13.861 214.968 13.907 ;
     RECT  16.128 8.485 16.152 13.955 ;
     RECT  83.184 12.517 83.712 13.955 ;
     RECT  48.912 13.141 49.128 13.957 ;
     RECT  71.808 12.997 72.912 13.957 ;
     RECT  48.912 13.957 49.512 14.099 ;
     RECT  128.16 13.045 128.184 14.099 ;
     RECT  28.992 13.045 30.984 14.197 ;
     RECT  150.288 13.187 150.312 14.197 ;
     RECT  58.176 13.045 58.2 14.243 ;
     RECT  148.2 11.843 148.512 14.245 ;
     RECT  105 13.093 106.056 14.291 ;
     RECT  50.688 13.669 53.64 14.339 ;
     RECT  64.416 13.621 65.592 14.339 ;
     RECT  141.12 13.139 143.112 14.339 ;
     RECT  71.808 13.957 73.512 14.387 ;
     RECT  109.68 13.861 111.816 14.387 ;
     RECT  126.192 13.861 126.912 14.387 ;
     RECT  138.912 13.621 138.936 14.387 ;
     RECT  77.52 13.139 78.312 14.437 ;
     RECT  132 13.715 132.312 14.485 ;
     RECT  99.6 13.045 100.2 14.533 ;
     RECT  28.368 14.197 31.944 14.627 ;
     RECT  121.2 10.739 121.896 14.627 ;
     RECT  110.304 14.387 111.816 14.629 ;
     RECT  77.52 14.437 78.744 14.675 ;
     RECT  45.504 13.139 46.392 14.723 ;
     RECT  188.976 13.285 189.432 14.725 ;
     RECT  190.464 10.837 191.712 14.725 ;
     RECT  107.04 14.629 107.064 14.771 ;
     RECT  110.304 14.629 112.008 14.771 ;
     RECT  139.632 14.629 139.656 14.771 ;
     RECT  188.976 14.725 191.712 14.771 ;
     RECT  27.072 13.907 27.288 14.773 ;
     RECT  34.8 12.803 35.112 14.773 ;
     RECT  50.688 14.339 53.064 14.773 ;
     RECT  88.512 12.325 89.112 14.773 ;
     RECT  156.144 11.411 156.168 14.773 ;
     RECT  229.2 2.151 229.512 14.773 ;
     RECT  119.856 12.997 119.88 14.819 ;
     RECT  121.2 14.627 121.608 14.819 ;
     RECT  92.88 13.331 92.904 14.821 ;
     RECT  30.96 14.627 31.944 14.867 ;
     RECT  96.144 14.245 96.168 14.867 ;
     RECT  121.2 14.819 121.512 14.869 ;
     RECT  142.56 14.339 143.112 14.915 ;
     RECT  132 14.485 132.408 14.963 ;
     RECT  188.976 14.771 190.392 14.963 ;
     RECT  203.52 13.621 203.544 15.013 ;
     RECT  203.52 15.013 203.784 15.059 ;
     RECT  147.216 14.245 148.512 15.203 ;
     RECT  137.4 13.667 137.712 15.253 ;
     RECT  43.872 14.773 43.896 15.395 ;
     RECT  64.416 14.339 64.872 15.443 ;
     RECT  72.384 14.387 73.512 15.443 ;
     RECT  80.496 13.811 81 15.443 ;
     RECT  82.08 13.811 82.104 15.443 ;
     RECT  155.568 14.773 156.168 15.443 ;
     RECT  34.128 14.773 35.112 15.445 ;
     RECT  67.2 9.587 67.512 15.445 ;
     RECT  141.12 14.339 141.144 15.445 ;
     RECT  33.648 15.445 35.112 15.491 ;
     RECT  77.664 14.675 78.744 15.491 ;
     RECT  61.8 13.139 62.112 15.493 ;
     RECT  84.816 14.389 84.84 15.493 ;
     RECT  102.672 13.573 102.696 15.493 ;
     RECT  47.904 15.349 47.928 15.637 ;
     RECT  48.912 14.099 48.936 15.637 ;
     RECT  47.904 15.637 48.936 15.683 ;
     RECT  55.296 14.773 55.32 15.683 ;
     RECT  84.816 15.493 84.936 15.683 ;
     RECT  223.8 5.171 224.112 15.733 ;
     RECT  24 6.133 25.08 15.781 ;
     RECT  222.528 14.773 222.552 15.781 ;
     RECT  45.6 14.723 46.392 15.829 ;
     RECT  105 14.291 105.576 15.829 ;
     RECT  186 11.411 186.312 15.829 ;
     RECT  49.92 14.773 53.064 15.925 ;
     RECT  56.4 12.515 56.712 15.973 ;
     RECT  47.904 15.683 48.552 16.019 ;
     RECT  84.816 15.683 84.84 16.019 ;
     RECT  92.88 14.821 92.952 16.019 ;
     RECT  99.6 14.533 100.824 16.019 ;
     RECT  102.288 15.493 102.696 16.019 ;
     RECT  104.016 15.829 105.576 16.019 ;
     RECT  110.304 14.771 111.816 16.019 ;
     RECT  118.176 14.773 118.2 16.019 ;
     RECT  137.28 15.253 137.712 16.019 ;
     RECT  150.288 14.197 151.08 16.019 ;
     RECT  213 13.907 214.056 16.019 ;
     RECT  229.2 14.773 229.608 16.019 ;
     RECT  115.248 13.139 116.112 16.021 ;
     RECT  145.008 13.139 145.032 16.021 ;
     RECT  115.248 16.021 116.232 16.069 ;
     RECT  92.928 16.019 92.952 16.115 ;
     RECT  120.816 14.869 121.512 16.165 ;
     RECT  96.72 16.021 96.84 16.211 ;
     RECT  188.976 14.963 189.48 16.259 ;
     RECT  45.504 15.829 46.392 16.307 ;
     RECT  102.288 16.019 102.312 16.307 ;
     RECT  218.304 13.139 218.712 16.307 ;
     RECT  18.6 11.555 19.32 16.355 ;
     RECT  104.016 16.019 105.48 16.355 ;
     RECT  120.624 16.165 121.512 16.403 ;
     RECT  64.416 15.443 64.44 16.405 ;
     RECT  80.496 15.443 80.52 16.405 ;
     RECT  153.6 7.859 153.912 16.405 ;
     RECT  39.024 11.171 39.048 16.547 ;
     RECT  111.792 16.019 111.816 16.547 ;
     RECT  145.008 16.021 145.32 16.547 ;
     RECT  184.512 14.485 184.536 16.547 ;
     RECT  185.76 15.829 186.312 16.547 ;
     RECT  189.456 16.259 189.48 16.547 ;
     RECT  42.672 15.061 42.696 16.595 ;
     RECT  45.6 16.307 46.392 16.595 ;
     RECT  49.92 15.925 53.928 16.595 ;
     RECT  61.8 15.493 62.76 16.595 ;
     RECT  113.28 11.363 113.304 16.595 ;
     RECT  129.312 14.917 129.336 16.595 ;
     RECT  56.4 15.973 57.048 16.597 ;
     RECT  50.064 16.595 53.928 16.691 ;
     RECT  102.048 16.549 102.072 16.691 ;
     RECT  45.6 16.595 46.248 16.787 ;
     RECT  125.376 16.645 125.4 16.787 ;
     RECT  40.2 13.331 40.512 16.789 ;
     RECT  115.152 16.069 116.232 16.789 ;
     RECT  56.4 16.597 57.72 16.835 ;
     RECT  108.768 16.597 108.792 16.885 ;
     RECT  112.8 16.789 112.968 16.885 ;
     RECT  141.072 15.445 141.144 16.885 ;
     RECT  104.88 16.355 105.48 16.931 ;
     RECT  48.528 16.019 48.552 16.981 ;
     RECT  115.152 16.789 116.808 16.981 ;
     RECT  145.008 16.547 145.032 16.981 ;
     RECT  90.96 14.101 90.984 17.029 ;
     RECT  137.4 16.019 137.712 17.029 ;
     RECT  36.192 16.021 37.176 17.075 ;
     RECT  72.48 15.443 73.512 17.075 ;
     RECT  80.496 16.405 81.432 17.075 ;
     RECT  90.624 17.029 90.984 17.075 ;
     RECT  64.272 16.405 64.44 17.077 ;
     RECT  77.664 15.491 78.312 17.077 ;
     RECT  92.784 16.981 92.808 17.077 ;
     RECT  144.816 16.981 145.032 17.077 ;
     RECT  30.96 14.867 31.32 17.123 ;
     RECT  92.784 17.077 92.952 17.123 ;
     RECT  108.624 16.885 108.888 17.123 ;
     RECT  112.704 16.885 112.968 17.123 ;
     RECT  115.152 16.981 116.904 17.123 ;
     RECT  120.816 16.403 121.512 17.123 ;
     RECT  140.592 16.885 141.144 17.123 ;
     RECT  37.152 17.075 37.176 17.171 ;
     RECT  66.624 15.445 67.512 17.171 ;
     RECT  76.944 17.077 78.312 17.171 ;
     RECT  96.72 16.211 96.744 17.171 ;
     RECT  105 16.931 105.48 17.171 ;
     RECT  115.152 17.123 116.112 17.171 ;
     RECT  150.288 16.019 150.888 17.171 ;
     RECT  28.368 14.627 29.712 17.173 ;
     RECT  30.96 17.123 31.224 17.173 ;
     RECT  40.2 16.789 41.016 17.173 ;
     RECT  78 17.171 78.312 17.173 ;
     RECT  109.104 17.125 109.128 17.173 ;
     RECT  110.304 16.019 110.808 17.173 ;
     RECT  76.944 17.171 76.968 17.219 ;
     RECT  92.928 17.123 92.952 17.219 ;
     RECT  109.104 17.173 110.808 17.219 ;
     RECT  140.784 17.123 141.144 17.219 ;
     RECT  144.72 17.077 145.032 17.219 ;
     RECT  53.904 16.691 53.928 17.315 ;
     RECT  56.4 16.835 57.048 17.315 ;
     RECT  109.104 17.219 110.712 17.315 ;
     RECT  139.104 16.549 139.128 17.315 ;
     RECT  112.848 17.123 112.968 17.363 ;
     RECT  145.008 17.219 145.032 17.363 ;
     RECT  222 15.781 222.552 17.363 ;
     RECT  40.2 17.173 41.16 17.411 ;
     RECT  50.064 16.691 52.2 17.411 ;
     RECT  64.272 17.077 65.016 17.411 ;
     RECT  33.648 15.491 33.672 17.509 ;
     RECT  34.8 15.491 35.112 17.509 ;
     RECT  94.2 13.331 94.512 17.509 ;
     RECT  61.8 16.595 62.112 17.605 ;
     RECT  75.696 15.253 75.72 17.605 ;
     RECT  136.8 17.029 137.712 17.605 ;
     RECT  33.648 17.509 35.112 17.651 ;
     RECT  64.272 17.411 64.296 17.651 ;
     RECT  87.936 14.773 89.112 17.651 ;
     RECT  153.072 16.405 153.912 17.651 ;
     RECT  48.24 16.981 48.552 17.653 ;
     RECT  136.8 17.605 138.552 17.843 ;
     RECT  67.2 17.171 67.512 17.941 ;
     RECT  45.6 16.787 45.912 17.989 ;
     RECT  59.28 17.893 59.448 17.989 ;
     RECT  99.6 16.019 99.912 17.989 ;
     RECT  156.144 15.443 156.168 17.989 ;
     RECT  67.2 17.941 67.608 18.083 ;
     RECT  80.496 17.075 81.288 18.179 ;
     RECT  115.248 17.171 116.112 18.179 ;
     RECT  47.952 17.653 48.552 18.181 ;
     RECT  56.4 17.315 56.712 18.181 ;
     RECT  61.584 17.605 62.112 18.181 ;
     RECT  78 17.173 78.408 18.181 ;
     RECT  88.8 17.651 89.112 18.181 ;
     RECT  126.6 14.387 126.912 18.181 ;
     RECT  6.24 16.501 6.264 18.275 ;
     RECT  75.696 17.605 75.816 18.275 ;
     RECT  90.624 17.075 90.648 18.275 ;
     RECT  61.584 18.181 62.76 18.371 ;
     RECT  77.52 18.181 78.408 18.419 ;
     RECT  47.616 18.181 48.552 18.421 ;
     RECT  83.4 13.955 83.712 18.421 ;
     RECT  136.8 17.843 137.712 18.467 ;
     RECT  41.808 17.989 41.832 18.517 ;
     RECT  134.016 18.421 134.04 18.563 ;
     RECT  121.2 17.123 121.512 18.565 ;
     RECT  148.2 15.203 148.512 18.565 ;
     RECT  150.288 17.171 150.312 18.565 ;
     RECT  56.16 18.181 56.712 18.661 ;
     RECT  155.568 17.989 156.888 18.707 ;
     RECT  58.464 17.989 59.448 18.709 ;
     RECT  148.2 18.565 150.312 18.709 ;
     RECT  58.128 18.709 59.448 18.755 ;
     RECT  65.424 18.709 65.448 18.757 ;
     RECT  122.88 16.501 122.904 18.757 ;
     RECT  123.936 14.629 123.96 18.757 ;
     RECT  55.296 18.661 56.712 18.803 ;
     RECT  56.064 18.803 56.712 18.805 ;
     RECT  142.8 14.915 143.112 18.805 ;
     RECT  22.368 8.869 22.776 18.851 ;
     RECT  58.128 18.755 58.152 18.851 ;
     RECT  99.6 17.989 100.008 18.851 ;
     RECT  126.6 18.181 127.08 18.851 ;
     RECT  128.784 18.181 128.808 18.851 ;
     RECT  130.176 17.029 130.2 18.851 ;
     RECT  144.24 18.181 144.264 18.851 ;
     RECT  147.36 18.709 150.312 18.851 ;
     RECT  41.76 18.517 41.832 18.899 ;
     RECT  50.688 17.411 52.2 18.947 ;
     RECT  114.336 18.709 114.36 18.947 ;
     RECT  110.304 17.315 110.712 18.949 ;
     RECT  88.8 18.181 89.592 18.997 ;
     RECT  121.104 18.565 121.512 18.997 ;
     RECT  26.976 14.773 27.288 19.045 ;
     RECT  28.368 17.173 31.224 19.045 ;
     RECT  83.28 18.421 83.712 19.045 ;
     RECT  133.584 18.997 133.608 19.093 ;
     RECT  133.44 19.093 133.608 19.139 ;
     RECT  94.2 17.509 94.968 19.141 ;
     RECT  82.464 19.045 83.712 19.187 ;
     RECT  225.552 18.133 225.576 19.187 ;
     RECT  118.944 16.501 118.968 19.237 ;
     RECT  109.104 17.315 109.128 19.285 ;
     RECT  56.064 18.805 56.808 19.331 ;
     RECT  88.8 18.997 89.832 19.331 ;
     RECT  122.88 18.757 123.96 19.379 ;
     RECT  125.376 19.237 125.4 19.379 ;
     RECT  155.568 18.707 156.168 19.379 ;
     RECT  59.424 18.755 59.448 19.427 ;
     RECT  94.2 19.141 95.016 19.477 ;
     RECT  223.68 15.733 224.112 19.477 ;
     RECT  37.056 18.229 37.08 19.523 ;
     RECT  65.424 18.757 66.12 19.523 ;
     RECT  22.368 18.851 22.392 19.571 ;
     RECT  72.48 17.075 72.912 19.621 ;
     RECT  132 14.963 132.312 19.621 ;
     RECT  94.2 19.477 95.88 19.669 ;
     RECT  93.936 19.669 95.88 19.715 ;
     RECT  120.768 18.997 121.512 19.717 ;
     RECT  108.816 19.285 109.128 19.763 ;
     RECT  40.2 17.411 40.512 19.765 ;
     RECT  41.76 18.899 41.784 19.765 ;
     RECT  222 17.363 222.024 19.765 ;
     RECT  223.536 19.477 224.616 19.765 ;
     RECT  45.36 17.989 45.912 19.811 ;
     RECT  88.8 19.331 89.592 19.811 ;
     RECT  147.36 18.851 149.448 19.811 ;
     RECT  203.76 15.059 203.784 19.811 ;
     RECT  111.744 18.709 111.768 19.859 ;
     RECT  120.768 19.717 121.608 19.859 ;
     RECT  61.584 18.371 62.112 19.907 ;
     RECT  56.064 19.331 56.712 19.909 ;
     RECT  99.6 18.851 99.912 19.909 ;
     RECT  97.728 17.893 97.752 20.003 ;
     RECT  118.512 19.237 118.968 20.003 ;
     RECT  142.704 18.805 143.112 20.003 ;
     RECT  131.088 19.621 132.312 20.051 ;
     RECT  87.216 18.229 87.24 20.101 ;
     RECT  88.8 19.811 89.112 20.101 ;
     RECT  9.36 18.757 9.384 20.147 ;
     RECT  147.36 19.811 148.632 20.147 ;
     RECT  93.936 19.715 95.016 20.149 ;
     RECT  13.2 6.899 13.512 20.293 ;
     RECT  90.624 20.101 90.648 20.339 ;
     RECT  120.768 19.859 121.512 20.339 ;
     RECT  87.216 20.101 89.112 20.387 ;
     RECT  93.312 20.149 95.016 20.435 ;
     RECT  126.6 18.851 126.912 20.485 ;
     RECT  141.12 17.219 141.144 20.485 ;
     RECT  47.232 18.421 48.552 20.579 ;
     RECT  71.808 19.621 72.912 20.579 ;
     RECT  141.12 20.485 141.624 20.627 ;
     RECT  105 17.171 105.312 20.629 ;
     RECT  108.816 19.763 108.84 20.675 ;
     RECT  45.6 19.811 45.912 20.677 ;
     RECT  38.352 18.565 38.376 20.819 ;
     RECT  91.776 19.765 91.8 20.819 ;
     RECT  87.216 20.387 87.24 20.867 ;
     RECT  58.032 19.909 58.056 20.869 ;
     RECT  110.208 18.949 110.712 20.917 ;
     RECT  24 15.781 25.608 20.965 ;
     RECT  26.976 19.045 31.224 20.965 ;
     RECT  55.776 19.909 56.712 20.965 ;
     RECT  129.072 19.477 129.096 20.965 ;
     RECT  110.208 20.917 111.432 21.059 ;
     RECT  40.2 19.765 41.784 21.061 ;
     RECT  58.032 20.869 58.152 21.061 ;
     RECT  65.424 19.523 65.544 21.061 ;
     RECT  67.2 18.083 67.512 21.061 ;
     RECT  99.6 19.909 100.824 21.061 ;
     RECT  99.6 21.061 100.968 21.107 ;
     RECT  107.088 19.381 107.112 21.107 ;
     RECT  144.528 19.909 144.552 21.107 ;
     RECT  39.888 21.061 41.784 21.155 ;
     RECT  77.52 18.419 78.312 21.155 ;
     RECT  80.496 18.179 80.52 21.155 ;
     RECT  93.312 20.435 94.68 21.155 ;
     RECT  113.376 20.533 113.4 21.155 ;
     RECT  123.936 19.379 123.96 21.155 ;
     RECT  148.2 20.147 148.632 21.155 ;
     RECT  230.832 19.621 230.856 21.155 ;
     RECT  157.824 20.149 157.848 21.251 ;
     RECT  47.904 20.579 48.552 21.491 ;
     RECT  24 20.965 31.224 21.541 ;
     RECT  41.76 21.155 41.784 21.637 ;
     RECT  45.6 20.677 46.008 21.637 ;
     RECT  72.48 20.579 72.912 21.637 ;
     RECT  75.696 18.275 75.72 21.637 ;
     RECT  94.2 21.155 94.68 21.637 ;
     RECT  125.328 20.821 125.352 21.637 ;
     RECT  126.6 20.485 127.08 21.637 ;
     RECT  132 20.051 132.312 21.637 ;
     RECT  133.44 19.139 133.464 21.637 ;
     RECT  39.888 21.155 40.512 21.683 ;
     RECT  47.904 21.491 48.264 21.683 ;
     RECT  58.032 21.061 58.536 21.683 ;
     RECT  100.944 21.107 100.968 21.683 ;
     RECT  110.208 21.059 110.712 21.683 ;
     RECT  139.536 19.237 139.56 21.683 ;
     RECT  141.6 20.627 141.624 21.683 ;
     RECT  227.136 20.053 227.16 21.683 ;
     RECT  125.328 21.637 127.08 21.827 ;
     RECT  129.072 20.965 129.672 21.827 ;
     RECT  58.512 21.683 58.536 21.829 ;
     RECT  58.512 21.829 58.68 21.875 ;
     RECT  79.296 21.013 79.32 21.923 ;
     RECT  104.016 20.629 105.312 21.925 ;
     RECT  41.76 21.637 42.696 21.971 ;
     RECT  104.016 21.925 106.152 21.971 ;
     RECT  132 21.637 133.464 21.971 ;
     RECT  222 19.765 224.616 22.067 ;
     RECT  18.6 16.355 18.912 22.165 ;
     RECT  13.2 20.293 14.232 22.211 ;
     RECT  97.44 21.109 97.464 22.211 ;
     RECT  24 21.541 31.896 22.259 ;
     RECT  222 22.067 224.112 22.259 ;
     RECT  50.688 18.947 51.312 22.355 ;
     RECT  65.424 21.061 67.512 22.355 ;
     RECT  69.6 19.909 69.624 22.355 ;
     RECT  74.256 22.213 74.28 22.355 ;
     RECT  105 21.971 106.152 22.451 ;
     RECT  55.776 20.965 57.048 22.693 ;
     RECT  33.648 21.541 33.672 22.739 ;
     RECT  45.6 21.637 46.776 22.739 ;
     RECT  72.48 21.637 73.032 22.739 ;
     RECT  120 21.397 120.024 22.739 ;
     RECT  152.16 20.965 152.184 22.739 ;
     RECT  75.504 21.637 75.72 22.741 ;
     RECT  42.672 21.971 42.696 22.787 ;
     RECT  77.76 21.155 78.312 22.787 ;
     RECT  83.28 19.187 83.712 22.787 ;
     RECT  75.504 22.741 76.44 22.835 ;
     RECT  117.936 21.541 117.96 22.835 ;
     RECT  121.2 20.339 121.512 22.837 ;
     RECT  122.88 19.379 122.904 22.837 ;
     RECT  63.696 22.645 63.72 22.883 ;
     RECT  65.424 22.355 65.784 22.979 ;
     RECT  118.944 20.003 118.968 22.981 ;
     RECT  110.304 21.683 110.712 23.029 ;
     RECT  96.912 22.789 96.936 23.123 ;
     RECT  121.2 22.837 122.904 23.123 ;
     RECT  72.48 22.739 72.912 23.125 ;
     RECT  142.8 20.003 143.112 23.125 ;
     RECT  53.808 22.165 53.832 23.171 ;
     RECT  82.032 20.725 82.056 23.171 ;
     RECT  222 22.259 222.024 23.269 ;
     RECT  222 23.269 222.216 23.315 ;
     RECT  88.8 20.387 89.112 23.317 ;
     RECT  94.2 21.637 95.208 23.365 ;
     RECT  45.6 22.739 45.912 23.557 ;
     RECT  105 22.451 105.312 23.557 ;
     RECT  58.656 21.875 58.68 23.603 ;
     RECT  55.632 22.693 57.048 23.699 ;
     RECT  94.2 23.365 95.256 23.797 ;
     RECT  38.4 20.965 38.424 23.845 ;
     RECT  45.264 23.557 45.912 23.845 ;
     RECT  61.8 19.907 62.112 23.845 ;
     RECT  137.4 18.467 137.712 23.845 ;
     RECT  223.536 22.259 224.112 23.893 ;
     RECT  93.264 23.797 95.256 23.939 ;
     RECT  226.272 23.269 226.296 23.939 ;
     RECT  18.6 22.165 19.656 23.987 ;
     RECT  65.424 22.979 65.688 23.987 ;
     RECT  88.608 23.317 89.112 23.987 ;
     RECT  140.352 22.741 140.376 23.987 ;
     RECT  222.192 23.315 222.216 23.987 ;
     RECT  115.8 18.179 116.112 24.085 ;
     RECT  75.696 22.835 76.44 24.131 ;
     RECT  118.32 22.981 118.968 24.131 ;
     RECT  129.072 21.827 129.096 24.133 ;
     RECT  118.56 24.131 118.968 24.179 ;
     RECT  97.2 23.317 97.224 24.323 ;
     RECT  108.288 23.557 108.312 24.325 ;
     RECT  101.568 23.317 101.592 24.371 ;
     RECT  24 22.259 31.224 24.373 ;
     RECT  106.608 24.133 106.632 24.419 ;
     RECT  108.288 24.325 108.744 24.467 ;
     RECT  24 24.373 31.56 24.469 ;
     RECT  94.2 23.939 95.256 24.515 ;
     RECT  110.304 23.029 111.096 24.515 ;
     RECT  125.328 21.827 126.912 24.517 ;
     RECT  76.416 24.131 76.44 24.563 ;
     RECT  167.28 16.261 167.304 24.563 ;
     RECT  48.24 21.683 48.264 24.613 ;
     RECT  105 23.557 105.432 24.613 ;
     RECT  130.8 23.269 130.824 24.613 ;
     RECT  38.16 23.845 38.424 24.659 ;
     RECT  48.24 24.613 48.456 24.659 ;
     RECT  105 24.613 106.104 24.755 ;
     RECT  132 21.971 132.936 24.805 ;
     RECT  134.544 23.269 134.568 24.805 ;
     RECT  103.728 23.317 103.752 24.853 ;
     RECT  103.584 24.853 103.752 24.899 ;
     RECT  132 24.805 134.568 24.899 ;
     RECT  128.736 24.133 129.096 24.901 ;
     RECT  130.464 24.613 130.824 24.901 ;
     RECT  61.056 23.845 62.112 24.947 ;
     RECT  115.8 24.085 116.232 24.947 ;
     RECT  223.536 23.893 224.76 24.947 ;
     RECT  110.304 24.515 110.712 25.045 ;
     RECT  128.736 24.901 130.824 25.045 ;
     RECT  148.2 21.155 148.512 25.045 ;
     RECT  45.264 23.845 46.824 25.091 ;
     RECT  59.088 23.701 59.112 25.091 ;
     RECT  137.4 23.845 137.976 25.093 ;
     RECT  38.16 24.659 38.184 25.139 ;
     RECT  55.632 23.699 56.712 25.139 ;
     RECT  64.224 24.469 64.248 25.139 ;
     RECT  74.064 23.701 74.088 25.139 ;
     RECT  103.584 24.899 103.608 25.139 ;
     RECT  142.8 23.125 143.496 25.139 ;
     RECT  43.248 23.125 43.272 25.187 ;
     RECT  140.304 24.325 140.328 25.187 ;
     RECT  146.592 23.557 146.616 25.187 ;
     RECT  40.2 21.683 40.512 25.189 ;
     RECT  136.752 25.093 137.976 25.235 ;
     RECT  139.296 22.165 139.32 25.237 ;
     RECT  72.336 23.125 72.912 25.283 ;
     RECT  40.2 25.189 41.304 25.331 ;
     RECT  105 24.755 105.432 25.331 ;
     RECT  223.8 24.947 224.76 25.427 ;
     RECT  48.432 24.659 48.456 25.475 ;
     RECT  56.304 25.139 56.712 25.475 ;
     RECT  65.424 23.987 65.448 25.475 ;
     RECT  108.288 24.467 108.312 25.475 ;
     RECT  110.064 25.045 110.712 25.475 ;
     RECT  128.736 25.045 130.92 25.525 ;
     RECT  132 24.899 133.656 25.525 ;
     RECT  159 10.883 159.312 25.525 ;
     RECT  227.664 24.757 227.688 25.573 ;
     RECT  139.056 25.237 139.32 25.621 ;
     RECT  147.744 25.045 148.512 25.621 ;
     RECT  149.904 25.333 149.928 25.621 ;
     RECT  156.144 19.379 156.168 25.621 ;
     RECT  159 25.525 159.864 25.621 ;
     RECT  166.944 25.045 166.968 25.621 ;
     RECT  45.6 25.091 46.824 25.715 ;
     RECT  54.096 23.653 54.12 25.715 ;
     RECT  158.4 25.621 159.864 25.717 ;
     RECT  72.48 25.283 72.912 25.811 ;
     RECT  24 24.469 31.944 25.813 ;
     RECT  121.2 23.123 121.512 26.005 ;
     RECT  122.88 23.123 122.904 26.005 ;
     RECT  24 25.813 32.088 26.195 ;
     RECT  118.944 24.179 118.968 26.197 ;
     RECT  145.296 25.621 145.32 26.197 ;
     RECT  164.4 8.003 164.712 26.197 ;
     RECT  136.752 25.235 137.712 26.437 ;
     RECT  149.904 25.621 150.648 26.437 ;
     RECT  186 16.547 186.312 26.437 ;
     RECT  155.52 25.621 156.168 26.485 ;
     RECT  157.248 25.621 157.272 26.485 ;
     RECT  153.6 17.651 153.912 26.533 ;
     RECT  158.4 25.717 159.912 26.725 ;
     RECT  125.328 24.517 127.656 27.349 ;
     RECT  128.736 25.525 133.656 27.349 ;
     RECT  135.888 26.437 137.712 27.349 ;
     RECT  139.056 25.621 139.992 27.349 ;
     RECT  142.8 25.139 143.112 27.349 ;
     RECT  144.288 26.197 144.312 27.349 ;
     RECT  145.296 26.197 146.232 27.349 ;
     RECT  147.504 25.621 148.512 27.349 ;
     RECT  225.744 26.101 225.768 27.587 ;
     RECT  125.328 27.349 133.656 27.589 ;
     RECT  227.568 25.573 227.688 27.781 ;
     RECT  223.8 25.427 224.112 27.925 ;
     RECT  24 26.195 31.56 28.019 ;
     RECT  226.848 27.781 227.688 28.309 ;
     RECT  226.848 28.309 227.976 28.355 ;
     RECT  226.848 28.355 226.872 29.075 ;
     RECT  223.8 27.925 224.52 29.123 ;
     RECT  24 28.019 31.512 29.315 ;
     RECT  227.952 28.355 227.976 30.181 ;
     RECT  229.2 16.019 229.512 30.181 ;
     RECT  210.336 30.757 210.36 30.947 ;
     RECT  227.952 30.181 229.512 31.379 ;
     RECT  24 29.315 31.32 32.821 ;
     RECT  223.8 29.123 224.112 33.013 ;
     RECT  207.6 10.307 207.912 34.165 ;
     RECT  227.952 31.379 227.976 34.213 ;
     RECT  206.976 34.165 207.912 34.403 ;
     RECT  229.056 31.379 229.512 34.499 ;
     RECT  227.904 34.213 227.976 34.835 ;
     RECT  229.2 34.499 229.512 35.845 ;
     RECT  223.8 33.013 224.232 36.275 ;
     RECT  229.2 35.845 229.752 36.755 ;
     RECT  225.744 35.941 225.768 37.667 ;
     RECT  24 32.821 31.512 38.003 ;
     RECT  24 38.003 28.2 38.099 ;
     RECT  223.8 36.275 224.112 38.149 ;
     RECT  25.488 38.099 28.2 40.595 ;
     RECT  29.232 38.003 31.512 41.075 ;
     RECT  223.8 38.149 224.616 41.075 ;
     RECT  31.296 41.075 31.512 41.267 ;
     RECT  227.952 34.835 227.976 41.603 ;
     RECT  29.232 41.075 30.312 41.843 ;
     RECT  31.392 41.267 31.512 42.083 ;
     RECT  29.232 41.843 30.216 42.131 ;
     RECT  31.392 42.083 31.416 42.227 ;
     RECT  223.8 41.075 224.568 42.803 ;
     RECT  18.6 23.987 18.912 43.285 ;
     RECT  17.616 43.285 18.912 43.427 ;
     RECT  25.536 40.595 28.2 43.667 ;
     RECT  223.8 42.803 224.112 43.813 ;
     RECT  25.632 43.667 28.2 44.147 ;
     RECT  222.864 43.813 224.112 44.531 ;
     RECT  221.808 44.437 221.832 44.627 ;
     RECT  25.632 44.147 27.912 44.819 ;
     RECT  25.632 44.819 27.816 44.915 ;
     RECT  25.632 44.915 27.336 45.731 ;
     RECT  227.424 45.589 227.448 46.213 ;
     RECT  227.424 46.213 227.592 46.259 ;
     RECT  29.232 42.131 29.712 46.547 ;
     RECT  223.8 44.531 224.112 47.173 ;
     RECT  26.352 45.731 27.336 47.363 ;
     RECT  220.272 41.749 220.296 47.363 ;
     RECT  227.568 46.259 227.592 47.701 ;
     RECT  227.472 47.701 227.592 47.747 ;
     RECT  227.472 47.747 227.496 48.131 ;
     RECT  223.344 47.173 224.112 48.373 ;
     RECT  223.344 48.373 224.808 48.419 ;
     RECT  26.352 47.363 26.712 48.899 ;
     RECT  26.352 48.899 26.664 49.187 ;
     RECT  26.64 49.187 26.664 49.475 ;
     RECT  226.224 41.557 226.248 57.059 ;
     RECT  125.328 27.589 134.232 58.163 ;
     RECT  129.072 58.163 134.232 58.211 ;
     RECT  125.328 58.163 127.944 58.403 ;
     RECT  125.712 58.403 127.944 58.451 ;
     RECT  166.944 25.621 168.6 58.451 ;
     RECT  132 58.211 134.232 58.499 ;
     RECT  135.888 27.349 139.992 58.547 ;
     RECT  132 58.499 132.936 58.691 ;
     RECT  118.944 26.197 119.208 58.979 ;
     RECT  125.712 58.451 126.912 59.027 ;
     RECT  121.2 26.005 122.904 59.075 ;
     RECT  132 58.691 132.792 59.075 ;
     RECT  129.072 58.211 130.824 59.123 ;
     RECT  129.072 59.123 130.488 59.171 ;
     RECT  139.344 58.547 139.992 59.507 ;
     RECT  129.072 59.171 129.528 59.555 ;
     RECT  158.4 26.725 160.44 59.555 ;
     RECT  129.072 59.555 129.144 59.603 ;
     RECT  125.904 59.027 126.912 59.651 ;
     RECT  135.888 58.547 138.216 59.651 ;
     RECT  149.568 26.437 150.648 59.699 ;
     RECT  119.184 58.979 119.208 59.891 ;
     RECT  134.208 58.499 134.232 59.891 ;
     RECT  129.12 59.603 129.144 60.035 ;
     RECT  4.608 14.389 4.632 60.083 ;
     RECT  135.888 59.651 135.912 61.379 ;
     RECT  127.92 58.451 127.944 61.907 ;
     RECT  150.624 59.699 150.648 62.195 ;
     RECT  167.472 58.451 168.6 62.195 ;
     RECT  167.808 62.195 168.6 62.483 ;
     RECT  121.2 59.075 122.232 64.067 ;
     RECT  2.4 2.151 2.712 64.357 ;
     RECT  145.296 27.349 148.512 64.691 ;
     RECT  164.4 26.197 165.336 65.267 ;
     RECT  139.968 59.507 139.992 65.747 ;
     RECT  145.296 64.691 146.76 66.899 ;
     RECT  126.48 59.651 126.912 67.427 ;
     RECT  2.4 64.357 2.808 68.147 ;
     RECT  142.8 27.349 144.312 68.147 ;
     RECT  145.296 66.899 146.184 68.675 ;
     RECT  155.52 26.485 157.272 69.251 ;
     RECT  183.792 25.717 183.816 69.251 ;
     RECT  137.4 59.651 138.216 69.731 ;
     RECT  155.52 69.251 156.456 70.403 ;
     RECT  142.8 68.147 143.928 71.363 ;
     RECT  0.144 68.341 0.168 72.035 ;
     RECT  168.576 62.483 168.6 73.811 ;
     RECT  159 59.555 160.44 75.539 ;
     RECT  177.12 25.621 177.144 77.987 ;
     RECT  153.024 26.533 153.912 78.227 ;
     RECT  163.248 26.197 163.272 78.707 ;
     RECT  160.416 75.539 160.44 78.947 ;
     RECT  145.584 68.675 146.184 79.187 ;
     RECT  145.584 79.187 145.608 79.475 ;
     RECT  147.744 64.691 148.512 79.859 ;
     RECT  155.52 70.403 155.544 80.675 ;
     RECT  173.52 25.813 173.544 81.107 ;
     RECT  149.568 59.699 149.592 81.347 ;
     RECT  186 26.437 187.224 82.451 ;
     RECT  223.8 48.419 224.808 83.939 ;
     RECT  2.4 68.147 2.712 84.249 ;
     RECT  7.8 10.643 8.112 84.249 ;
     RECT  13.2 22.211 13.512 84.249 ;
     RECT  18.6 43.427 18.912 84.249 ;
     RECT  24 38.099 24.312 84.249 ;
     RECT  29.4 46.547 29.712 84.249 ;
     RECT  34.8 17.651 35.112 84.249 ;
     RECT  40.2 25.331 40.512 84.249 ;
     RECT  45.6 25.715 45.912 84.249 ;
     RECT  51 22.355 51.312 84.249 ;
     RECT  56.4 25.475 56.712 84.249 ;
     RECT  61.8 24.947 62.112 84.249 ;
     RECT  67.2 22.355 67.512 84.249 ;
     RECT  72.6 25.811 72.912 84.249 ;
     RECT  78 22.787 78.312 84.249 ;
     RECT  83.4 22.787 83.712 84.249 ;
     RECT  88.8 23.987 89.112 84.249 ;
     RECT  94.2 24.515 94.512 84.249 ;
     RECT  99.6 21.107 99.912 84.249 ;
     RECT  105 25.331 105.312 84.249 ;
     RECT  110.4 25.475 110.712 84.249 ;
     RECT  115.8 24.947 116.112 84.249 ;
     RECT  121.2 64.067 121.512 84.249 ;
     RECT  126.6 67.427 126.912 84.249 ;
     RECT  132 59.075 132.312 84.249 ;
     RECT  137.4 69.731 137.712 84.249 ;
     RECT  142.8 71.363 143.112 84.249 ;
     RECT  148.2 79.859 148.512 84.249 ;
     RECT  153.6 78.227 153.912 84.249 ;
     RECT  159 75.539 159.312 84.249 ;
     RECT  164.4 65.267 164.712 84.249 ;
     RECT  169.8 7.667 170.112 84.249 ;
     RECT  175.2 2.151 175.512 84.249 ;
     RECT  180.6 11.267 180.912 84.249 ;
     RECT  186 82.451 186.312 84.249 ;
     RECT  191.4 14.771 191.712 84.249 ;
     RECT  196.8 11.171 197.112 84.249 ;
     RECT  202.2 7.667 202.512 84.249 ;
     RECT  207.6 34.403 207.912 84.249 ;
     RECT  213 16.019 213.312 84.249 ;
     RECT  218.4 16.307 218.712 84.249 ;
     RECT  223.8 83.939 224.112 84.249 ;
     RECT  229.2 36.755 229.512 84.249 ;
     RECT  234.6 2.151 234.912 84.249 ;
     RECT  2.4 84.249 2.52 84.263 ;
     RECT  7.8 84.249 7.92 84.263 ;
     RECT  13.2 84.249 13.32 84.263 ;
     RECT  18.6 84.249 18.72 84.263 ;
     RECT  24 84.249 24.12 84.263 ;
     RECT  29.4 84.249 29.52 84.263 ;
     RECT  34.8 84.249 34.92 84.263 ;
     RECT  40.2 84.249 40.32 84.263 ;
     RECT  45.6 84.249 45.72 84.263 ;
     RECT  51 84.249 51.12 84.263 ;
     RECT  56.4 84.249 56.52 84.263 ;
     RECT  61.8 84.249 61.92 84.263 ;
     RECT  67.2 84.249 67.32 84.263 ;
     RECT  72.6 84.249 72.72 84.263 ;
     RECT  78 84.249 78.12 84.263 ;
     RECT  83.4 84.249 83.52 84.263 ;
     RECT  88.8 84.249 88.92 84.263 ;
     RECT  94.2 84.249 94.32 84.263 ;
     RECT  99.6 84.249 99.72 84.263 ;
     RECT  105 84.249 105.12 84.263 ;
     RECT  110.4 84.249 110.52 84.263 ;
     RECT  115.8 84.249 115.92 84.263 ;
     RECT  121.2 84.249 121.32 84.263 ;
     RECT  126.6 84.249 126.72 84.263 ;
     RECT  132 84.249 132.12 84.263 ;
     RECT  137.4 84.249 137.52 84.263 ;
     RECT  142.8 84.249 142.92 84.263 ;
     RECT  148.2 84.249 148.32 84.263 ;
     RECT  153.6 84.249 153.72 84.263 ;
     RECT  159 84.249 159.12 84.263 ;
     RECT  164.4 84.249 164.52 84.263 ;
     RECT  169.8 84.249 169.92 84.263 ;
     RECT  175.2 84.249 175.32 84.263 ;
     RECT  180.6 84.249 180.72 84.263 ;
     RECT  186 84.249 186.12 84.263 ;
     RECT  191.4 84.249 191.52 84.263 ;
     RECT  196.8 84.249 196.92 84.263 ;
     RECT  202.2 84.249 202.32 84.263 ;
     RECT  207.6 84.249 207.72 84.263 ;
     RECT  213 84.249 213.12 84.263 ;
     RECT  218.4 84.249 218.52 84.263 ;
     RECT  223.8 84.249 223.92 84.263 ;
     RECT  229.2 84.249 229.32 84.263 ;
     RECT  234.6 84.249 234.72 84.263 ;
     RECT  18.72 1.187 18.912 2.151 ;
     RECT  45.72 1.187 47.04 1.763 ;
     RECT  67.32 1.187 68.976 1.763 ;
     RECT  78.168 1.187 78.312 2.151 ;
     RECT  142.992 1.187 143.112 2.137 ;
     RECT  148.32 1.187 148.512 2.151 ;
     RECT  186.12 1.187 186.312 2.151 ;
     RECT  218.52 1.187 218.712 2.151 ;
     RECT  45.72 1.763 45.912 2.151 ;
     RECT  67.32 1.763 67.512 2.151 ;
     RECT  142.92 2.137 143.112 2.151 ;
     RECT  116.112 3.829 117.264 7.621 ;
     RECT  47.88 3.877 48.96 5.461 ;
     RECT  46.392 3.925 47.856 5.461 ;
     RECT  63.096 3.925 64.128 7.523 ;
     RECT  103.992 4.981 105 12.563 ;
     RECT  48.984 5.173 50.448 6.803 ;
     RECT  56.712 5.317 58.032 6.661 ;
     RECT  206.28 5.605 207.36 9.011 ;
     RECT  47.88 6.563 48.96 6.899 ;
     RECT  56.808 6.661 58.032 7.139 ;
     RECT  6.408 6.757 7.8 8.003 ;
     RECT  100.536 6.805 101.904 7.619 ;
     RECT  67.608 6.851 67.848 7.525 ;
     RECT  111.24 6.995 111.48 7.429 ;
     RECT  55.08 7.093 56.4 7.381 ;
     RECT  56.712 7.139 58.032 7.331 ;
     RECT  117.288 7.141 118.56 8.051 ;
     RECT  33.672 7.189 34.8 8.147 ;
     RECT  121.512 7.235 122.64 7.955 ;
     RECT  127.464 7.237 128.592 7.955 ;
     RECT  37.608 7.333 38.784 8.003 ;
     RECT  38.808 7.333 40.2 9.493 ;
     RECT  19.32 7.381 20.688 7.957 ;
     RECT  29.712 7.381 30.96 13.045 ;
     RECT  55.272 7.381 56.4 8.003 ;
     RECT  164.712 7.381 166.224 7.813 ;
     RECT  184.872 7.381 186 8.003 ;
     RECT  111.24 7.429 112.896 7.859 ;
     RECT  108.888 7.477 110.4 9.347 ;
     RECT  67.608 7.525 69.024 7.715 ;
     RECT  100.536 7.619 101.928 8.773 ;
     RECT  67.608 7.715 69 7.909 ;
     RECT  116.232 7.763 117.264 7.811 ;
     RECT  116.112 7.811 117.264 10.979 ;
     RECT  164.808 7.813 166.224 7.955 ;
     RECT  111.24 7.859 111.624 8.437 ;
     RECT  153.504 7.859 153.6 8.869 ;
     RECT  52.248 7.909 53.376 12.229 ;
     RECT  66.12 7.909 67.2 9.203 ;
     RECT  67.608 7.909 68.976 8.579 ;
     RECT  146.472 7.909 147.6 8.579 ;
     RECT  86.64 7.955 86.664 8.869 ;
     RECT  132.312 7.955 132.408 9.061 ;
     RECT  164.712 7.955 166.224 9.731 ;
     RECT  35.112 7.957 36.192 8.675 ;
     RECT  44.928 8.003 45.024 9.013 ;
     RECT  55.08 8.003 56.4 8.051 ;
     RECT  197.112 8.149 198.336 8.723 ;
     RECT  93.648 8.195 94.2 9.205 ;
     RECT  67.608 8.579 68.904 9.587 ;
     RECT  100.536 8.773 102.096 8.965 ;
     RECT  22.776 8.869 24 18.851 ;
     RECT  86.64 8.869 87.6 8.965 ;
     RECT  87.624 8.869 88.8 9.587 ;
     RECT  152.376 8.869 153.6 11.701 ;
     RECT  70.872 8.965 72.384 9.397 ;
     RECT  85.656 8.965 87.6 9.107 ;
     RECT  100.92 8.965 102.096 9.107 ;
     RECT  206.28 9.011 207.456 10.307 ;
     RECT  132.792 9.061 133.968 10.307 ;
     RECT  85.56 9.107 87.6 9.301 ;
     RECT  100.536 9.107 102.096 9.779 ;
     RECT  44.376 9.155 45.36 10.067 ;
     RECT  91.608 9.205 92.88 11.459 ;
     RECT  92.904 9.205 94.2 11.797 ;
     RECT  19.32 9.299 20.688 9.539 ;
     RECT  81 9.301 82.08 9.541 ;
     RECT  82.104 9.301 83.4 12.517 ;
     RECT  85.56 9.301 86.64 9.539 ;
     RECT  108.864 9.347 110.4 10.357 ;
     RECT  70.872 9.397 71.952 10.211 ;
     RECT  96.504 9.397 97.536 9.493 ;
     RECT  39.192 9.493 40.2 10.405 ;
     RECT  150.312 9.493 151.776 9.637 ;
     RECT  38.784 9.539 39.168 10.981 ;
     RECT  97.464 9.539 97.56 9.635 ;
     RECT  121.512 9.541 123.024 10.309 ;
     RECT  67.512 9.587 68.904 9.637 ;
     RECT  87.384 9.587 88.8 9.589 ;
     RECT  87.384 9.589 88.704 10.355 ;
     RECT  96.504 9.635 97.56 10.597 ;
     RECT  40.512 9.637 41.808 12.227 ;
     RECT  67.512 9.637 68.88 10.261 ;
     RECT  150.312 9.637 151.584 10.595 ;
     RECT  76.944 9.731 78 9.925 ;
     RECT  100.536 9.779 102.072 10.307 ;
     RECT  218.712 9.827 219 10.213 ;
     RECT  126.912 9.877 128.208 10.405 ;
     RECT  76.92 9.925 78 10.211 ;
     RECT  44.352 10.067 45.36 11.221 ;
     RECT  70.872 10.211 72.384 12.947 ;
     RECT  218.712 10.213 219.696 10.979 ;
     RECT  67.512 10.261 68.64 11.075 ;
     RECT  100.008 10.307 102.072 10.357 ;
     RECT  132.792 10.307 132.888 10.309 ;
     RECT  206.28 10.307 207.6 10.451 ;
     RECT  121.608 10.309 123.024 10.357 ;
     RECT  100.008 10.357 102.048 11.699 ;
     RECT  108.888 10.357 110.4 10.741 ;
     RECT  127.176 10.405 128.208 10.691 ;
     RECT  41.832 10.451 42.168 11.941 ;
     RECT  150.312 10.595 150.552 11.365 ;
     RECT  96.504 10.597 97.632 10.643 ;
     RECT  111.816 10.597 113.28 10.691 ;
     RECT  126.912 10.691 128.208 12.467 ;
     RECT  141.336 10.691 142.56 11.941 ;
     RECT  121.896 10.739 122.88 12.035 ;
     RECT  109.032 10.741 110.4 11.365 ;
     RECT  143.256 10.741 144.576 11.365 ;
     RECT  108.864 10.787 109.008 11.941 ;
     RECT  30.984 10.789 32.16 11.459 ;
     RECT  78.408 10.789 79.776 11.987 ;
     RECT  189.24 10.837 190.464 13.045 ;
     RECT  39.192 10.883 40.2 11.075 ;
     RECT  136.752 10.883 137.4 12.325 ;
     RECT  222.744 11.029 223.8 11.699 ;
     RECT  39.048 11.075 40.2 16.547 ;
     RECT  67.512 11.075 68.88 12.035 ;
     RECT  44.088 11.221 45.36 12.467 ;
     RECT  113.304 11.363 113.496 12.181 ;
     RECT  109.032 11.365 110.304 12.035 ;
     RECT  34.224 11.459 34.8 11.941 ;
     RECT  143.88 11.459 145.008 12.179 ;
     RECT  100.008 11.699 100.632 11.701 ;
     RECT  134.688 11.699 134.712 12.325 ;
     RECT  152.472 11.701 153.6 12.563 ;
     RECT  130.584 11.797 131.904 11.987 ;
     RECT  99.912 11.843 100.2 13.045 ;
     RECT  33.432 11.941 34.8 12.563 ;
     RECT  106.584 11.941 107.712 13.091 ;
     RECT  107.736 11.941 109.008 12.035 ;
     RECT  105.576 11.987 106.56 13.091 ;
     RECT  109.68 12.035 110.304 13.045 ;
     RECT  143.592 12.179 145.008 12.899 ;
     RECT  113.304 12.181 114.672 13.139 ;
     RECT  40.512 12.227 42.144 12.899 ;
     RECT  53.064 12.275 53.4 13.669 ;
     RECT  49.128 12.325 50.256 13.091 ;
     RECT  134.688 12.325 136.032 12.517 ;
     RECT  136.056 12.325 137.4 13.091 ;
     RECT  126.912 12.467 128.184 13.045 ;
     RECT  56.712 12.515 57.432 12.757 ;
     RECT  82.104 12.517 83.184 13.955 ;
     RECT  134.232 12.517 136.032 12.853 ;
     RECT  150.936 12.517 152.352 13.187 ;
     RECT  152.376 12.563 153.6 13.763 ;
     RECT  56.712 12.757 57.696 12.899 ;
     RECT  134.232 12.853 135.552 12.995 ;
     RECT  40.512 12.899 40.632 13.189 ;
     RECT  56.712 12.899 57.72 13.045 ;
     RECT  71.808 12.947 72.384 12.997 ;
     RECT  119.88 12.997 121.2 14.819 ;
     RECT  56.712 13.045 58.176 14.243 ;
     RECT  126.912 13.045 128.16 14.099 ;
     RECT  189.432 13.045 190.464 14.725 ;
     RECT  49.128 13.091 50.688 13.957 ;
     RECT  105.576 13.091 106.056 13.093 ;
     RECT  78.312 13.139 78.408 14.437 ;
     RECT  140.64 13.139 141.12 14.629 ;
     RECT  150.312 13.187 152.352 13.763 ;
     RECT  92.904 13.331 94.2 14.821 ;
     RECT  137.928 13.621 138.912 13.667 ;
     RECT  202.512 13.621 203.52 15.059 ;
     RECT  137.712 13.667 138.912 14.387 ;
     RECT  150.312 13.763 151.08 14.197 ;
     RECT  81 13.811 82.08 15.443 ;
     RECT  111.816 13.861 113.28 14.629 ;
     RECT  27.288 13.907 27.336 14.197 ;
     RECT  82.104 13.955 83.4 15.443 ;
     RECT  49.512 13.957 50.688 14.099 ;
     RECT  48.936 14.099 50.688 14.773 ;
     RECT  27.288 14.197 28.368 19.045 ;
     RECT  105.576 14.291 106.056 14.629 ;
     RECT  141.144 14.339 142.56 14.915 ;
     RECT  83.712 14.389 84.816 16.019 ;
     RECT  184.536 14.485 186 15.829 ;
     RECT  29.712 14.627 30.96 17.173 ;
     RECT  105.576 14.629 107.04 14.771 ;
     RECT  112.008 14.629 113.28 14.771 ;
     RECT  139.656 14.629 141.12 14.771 ;
     RECT  45.504 14.723 45.6 15.829 ;
     RECT  111.816 14.771 113.28 16.547 ;
     RECT  141.072 14.771 141.12 15.445 ;
     RECT  190.392 14.771 191.4 14.963 ;
     RECT  48.936 14.773 49.92 15.683 ;
     RECT  55.32 14.773 56.4 15.683 ;
     RECT  222.552 14.773 223.8 15.733 ;
     RECT  120.624 14.819 121.2 14.869 ;
     RECT  92.952 14.821 94.2 16.115 ;
     RECT  120.624 14.869 120.816 16.165 ;
     RECT  202.512 15.059 203.76 19.811 ;
     RECT  42.696 15.061 43.872 15.395 ;
     RECT  46.392 15.349 47.904 16.019 ;
     RECT  47.928 15.349 48.912 15.637 ;
     RECT  80.52 15.443 81.432 16.405 ;
     RECT  33.672 15.491 34.8 17.509 ;
     RECT  100.824 15.493 102.288 16.019 ;
     RECT  48.552 15.683 49.92 16.595 ;
     RECT  222.552 15.733 223.68 17.363 ;
     RECT  25.608 15.781 26.976 20.965 ;
     RECT  102.696 15.829 104.016 16.019 ;
     RECT  184.536 15.829 185.76 16.547 ;
     RECT  48.24 16.019 48.528 16.981 ;
     RECT  92.88 16.019 92.928 16.115 ;
     RECT  102.048 16.019 102.288 16.307 ;
     RECT  110.808 16.019 111.792 16.547 ;
     RECT  137.28 16.019 137.4 17.029 ;
     RECT  35.112 16.021 36.192 17.075 ;
     RECT  92.88 16.115 94.2 16.981 ;
     RECT  102.048 16.307 102.072 16.549 ;
     RECT  62.76 16.405 64.272 16.595 ;
     RECT  121.512 16.501 122.88 19.717 ;
     RECT  122.904 16.501 123.936 18.757 ;
     RECT  112.704 16.547 113.28 16.595 ;
     RECT  137.712 16.549 139.104 17.315 ;
     RECT  48.552 16.595 50.064 17.411 ;
     RECT  112.704 16.595 112.968 16.789 ;
     RECT  108.792 16.597 110.304 16.885 ;
     RECT  123.96 16.645 125.376 16.787 ;
     RECT  125.4 16.645 126.6 16.787 ;
     RECT  112.704 16.789 112.8 16.885 ;
     RECT  57.048 16.835 57.72 17.315 ;
     RECT  108.888 16.885 110.304 17.123 ;
     RECT  139.128 16.885 140.592 17.123 ;
     RECT  92.808 16.981 94.2 17.077 ;
     RECT  89.112 17.029 90.624 18.181 ;
     RECT  37.056 17.075 37.152 17.171 ;
     RECT  75.72 17.077 76.944 17.219 ;
     RECT  92.952 17.077 94.2 17.219 ;
     RECT  109.104 17.123 110.304 17.125 ;
     RECT  121.104 17.123 121.2 18.565 ;
     RECT  109.128 17.125 110.304 17.173 ;
     RECT  37.056 17.171 37.176 18.229 ;
     RECT  76.968 17.171 78 17.219 ;
     RECT  75.72 17.219 75.816 17.605 ;
     RECT  77.52 17.219 78 18.181 ;
     RECT  110.712 17.219 110.808 18.709 ;
     RECT  56.712 17.315 57.72 17.989 ;
     RECT  109.128 17.315 110.304 18.949 ;
     RECT  137.712 17.315 138.552 17.605 ;
     RECT  40.512 17.411 41.16 17.989 ;
     RECT  40.512 17.989 41.808 18.517 ;
     RECT  56.712 17.989 58.464 18.709 ;
     RECT  224.112 18.133 225.552 19.187 ;
     RECT  115.248 18.179 115.8 18.709 ;
     RECT  89.592 18.181 90.624 18.275 ;
     RECT  128.808 18.181 130.176 18.851 ;
     RECT  143.112 18.181 144.24 18.851 ;
     RECT  37.08 18.229 37.176 18.565 ;
     RECT  89.592 18.275 89.832 18.997 ;
     RECT  45.912 18.421 47.232 20.579 ;
     RECT  40.512 18.517 41.76 19.765 ;
     RECT  37.08 18.565 38.352 19.523 ;
     RECT  56.712 18.709 58.128 18.805 ;
     RECT  110.712 18.709 111.744 19.859 ;
     RECT  114.36 18.709 115.8 18.947 ;
     RECT  58.152 18.755 59.424 18.851 ;
     RECT  8.112 18.757 9.36 20.147 ;
     RECT  66.12 18.757 67.2 19.523 ;
     RECT  55.776 18.803 56.064 19.909 ;
     RECT  56.808 18.805 58.128 18.851 ;
     RECT  56.808 18.851 59.424 19.331 ;
     RECT  99.912 18.851 100.008 19.909 ;
     RECT  129.072 18.851 129.096 19.477 ;
     RECT  143.112 18.851 144.264 19.909 ;
     RECT  109.128 18.949 110.208 19.763 ;
     RECT  132.312 18.997 133.584 19.093 ;
     RECT  132.312 19.093 133.44 21.637 ;
     RECT  224.112 19.187 224.616 19.477 ;
     RECT  123.96 19.237 125.376 19.379 ;
     RECT  125.4 19.237 126.6 19.379 ;
     RECT  56.712 19.331 59.424 19.427 ;
     RECT  89.592 19.331 89.832 19.811 ;
     RECT  122.904 19.379 123.936 21.155 ;
     RECT  123.96 19.379 126.6 20.821 ;
     RECT  56.712 19.427 58.152 19.909 ;
     RECT  222.024 19.477 223.536 19.765 ;
     RECT  229.512 19.621 230.832 21.155 ;
     RECT  121.608 19.717 122.88 19.859 ;
     RECT  108.84 19.763 110.208 20.675 ;
     RECT  89.112 19.811 89.832 20.101 ;
     RECT  110.712 19.859 111.432 20.917 ;
     RECT  121.512 19.859 122.88 22.837 ;
     RECT  56.712 19.909 58.032 20.965 ;
     RECT  58.056 19.909 58.152 20.869 ;
     RECT  143.112 19.909 144.528 21.107 ;
     RECT  142.704 20.003 142.8 20.485 ;
     RECT  89.112 20.101 90.624 20.339 ;
     RECT  90.648 20.101 91.776 20.339 ;
     RECT  91.8 20.149 93.312 20.819 ;
     RECT  157.848 20.149 159 21.251 ;
     RECT  120.768 20.339 121.2 21.397 ;
     RECT  94.68 20.435 95.016 21.637 ;
     RECT  141.624 20.485 142.8 21.683 ;
     RECT  45.912 20.579 47.904 20.677 ;
     RECT  46.008 20.677 47.904 21.637 ;
     RECT  80.52 20.725 82.032 21.155 ;
     RECT  82.056 20.725 83.28 22.787 ;
     RECT  123.96 20.821 125.328 21.155 ;
     RECT  125.352 20.821 126.6 21.637 ;
     RECT  57.048 20.965 58.032 21.683 ;
     RECT  152.184 20.965 153.6 22.739 ;
     RECT  78.312 21.013 79.296 21.923 ;
     RECT  79.32 21.013 80.496 21.155 ;
     RECT  38.424 21.061 39.888 21.683 ;
     RECT  99.912 21.107 100.944 21.683 ;
     RECT  40.512 21.155 41.76 21.971 ;
     RECT  118.968 21.397 120 22.739 ;
     RECT  120.024 21.397 121.2 22.739 ;
     RECT  33.672 21.541 34.8 22.739 ;
     RECT  117.96 21.541 118.944 22.835 ;
     RECT  46.776 21.637 47.904 21.683 ;
     RECT  46.776 21.683 48.24 22.739 ;
     RECT  57.048 21.683 58.512 21.875 ;
     RECT  139.536 21.683 139.56 22.165 ;
     RECT  104.016 21.971 105 23.317 ;
     RECT  139.32 22.165 139.56 22.741 ;
     RECT  73.032 22.213 74.256 22.355 ;
     RECT  74.28 22.213 75.504 22.355 ;
     RECT  222.024 22.259 223.536 23.269 ;
     RECT  65.784 22.355 67.2 22.979 ;
     RECT  73.032 22.355 75.504 22.739 ;
     RECT  105.312 22.451 105.432 23.557 ;
     RECT  45.912 22.739 48.24 23.845 ;
     RECT  72.912 22.739 75.504 22.835 ;
     RECT  76.44 22.741 77.76 22.787 ;
     RECT  139.32 22.741 140.352 23.987 ;
     RECT  82.056 22.787 83.4 23.171 ;
     RECT  72.912 22.835 74.088 23.701 ;
     RECT  118.32 22.835 118.944 22.981 ;
     RECT  65.688 22.979 67.2 23.987 ;
     RECT  121.512 23.123 122.88 26.005 ;
     RECT  130.824 23.269 132 25.045 ;
     RECT  222.216 23.269 223.536 23.987 ;
     RECT  103.752 23.317 105 24.899 ;
     RECT  54.12 23.653 55.632 25.139 ;
     RECT  72.912 23.701 74.064 25.139 ;
     RECT  46.824 23.845 48.24 24.659 ;
     RECT  137.976 23.845 139.296 25.235 ;
     RECT  224.76 23.893 226.272 23.939 ;
     RECT  139.32 23.987 140.328 24.325 ;
     RECT  105.432 24.133 106.608 24.419 ;
     RECT  139.32 24.325 140.304 25.187 ;
     RECT  105.432 24.419 106.104 24.613 ;
     RECT  64.248 24.469 65.424 25.139 ;
     RECT  127.656 24.517 128.736 27.349 ;
     RECT  167.28 24.563 167.304 25.045 ;
     RECT  129.096 24.613 130.464 24.901 ;
     RECT  227.688 24.757 229.2 28.309 ;
     RECT  103.608 24.899 105 25.139 ;
     RECT  130.92 25.045 132 25.525 ;
     RECT  146.616 25.045 147.744 25.187 ;
     RECT  166.968 25.045 167.304 25.621 ;
     RECT  143.112 25.139 143.496 26.197 ;
     RECT  139.32 25.187 139.992 25.621 ;
     RECT  146.592 25.187 147.744 25.621 ;
     RECT  137.712 25.235 139.296 25.237 ;
     RECT  137.712 25.237 139.056 27.349 ;
     RECT  148.512 25.333 149.904 26.437 ;
     RECT  145.32 25.621 147.504 26.197 ;
     RECT  156.168 25.621 157.248 26.485 ;
     RECT  157.272 25.621 158.4 59.555 ;
     RECT  168.6 25.621 169.8 73.811 ;
     RECT  143.112 26.197 144.288 27.349 ;
     RECT  144.312 26.197 145.296 68.147 ;
     RECT  146.232 26.197 147.504 27.349 ;
     RECT  163.272 26.197 164.4 78.707 ;
     RECT  148.512 26.437 149.568 81.347 ;
     RECT  227.976 28.309 229.2 30.181 ;
     RECT  226.872 28.355 227.952 29.075 ;
     RECT  227.976 31.379 229.056 34.499 ;
     RECT  227.976 34.499 229.2 41.603 ;
     RECT  224.232 35.941 225.744 36.275 ;
     RECT  28.2 38.003 29.232 44.147 ;
     RECT  24.312 38.099 25.488 40.595 ;
     RECT  24.312 40.595 25.536 43.667 ;
     RECT  30.312 41.075 31.296 41.267 ;
     RECT  30.312 41.267 31.392 41.843 ;
     RECT  30.216 41.843 31.392 42.131 ;
     RECT  24.312 43.667 25.632 45.731 ;
     RECT  27.912 44.147 29.232 44.819 ;
     RECT  220.296 44.437 221.808 44.627 ;
     RECT  221.832 44.437 222.864 44.531 ;
     RECT  27.816 44.819 29.232 44.915 ;
     RECT  226.248 45.589 227.424 46.259 ;
     RECT  226.248 46.259 227.568 47.701 ;
     RECT  226.248 47.701 227.472 48.131 ;
     RECT  224.808 48.373 226.224 57.059 ;
     RECT  127.944 58.163 129.072 59.603 ;
     RECT  130.824 58.211 132 59.123 ;
     RECT  126.912 58.451 127.92 61.907 ;
     RECT  132.936 58.499 134.208 58.691 ;
     RECT  138.216 58.547 139.344 59.507 ;
     RECT  132.792 58.691 134.208 59.075 ;
     RECT  130.488 59.123 132 59.171 ;
     RECT  127.944 59.603 129.12 60.035 ;
     RECT  135.912 59.651 137.4 61.379 ;
     RECT  149.592 59.699 150.624 62.195 ;
     RECT  146.76 64.691 147.744 66.899 ;
     RECT  143.928 68.147 145.296 68.675 ;
     RECT  159.312 75.539 160.416 78.947 ;
  END
END qfd_link_adp128
END LIBRARY
